VERSION 5.8 ;
BUSBITCHARS "[]" ;
DIVIDERCHAR "/" ;
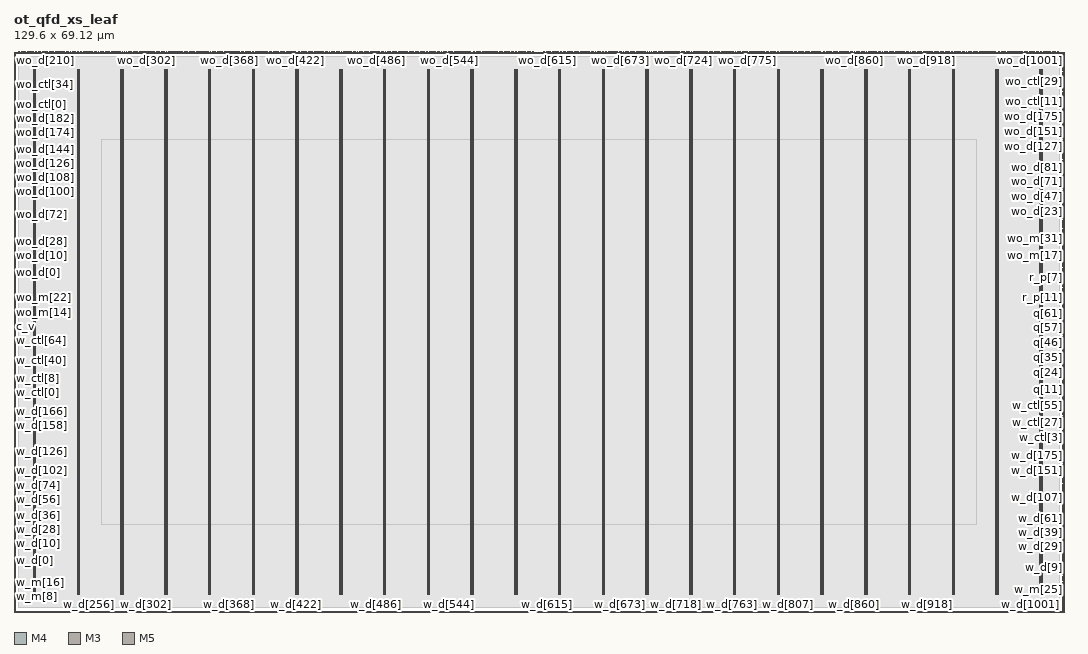
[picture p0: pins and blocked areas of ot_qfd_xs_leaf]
MACRO ot_qfd_xs_leaf
  CLASS BLOCK ;
  ORIGIN 0 0 ;
  FOREIGN ot_qfd_xs_leaf 0 0 ;
  SIZE 129.6 BY 69.12 ;
  SYMMETRY X Y ;
  PIN c_ep
    DIRECTION INPUT ;
    USE SIGNAL ;
    PORT
      LAYER M4 ;
        RECT 129.408 26.928 129.600 26.952 ;
    END
  END c_ep
  PIN c_v
    DIRECTION INPUT ;
    USE SIGNAL ;
    PORT
      LAYER M4 ;
        RECT 0.000 34.224 0.192 34.248 ;
    END
  END c_v
  PIN clk
    DIRECTION INPUT ;
    USE SIGNAL ;
    PORT
      LAYER M4 ;
        RECT 0.000 34.416 0.192 34.440 ;
    END
  END clk
  PIN co_ep
    DIRECTION OUTPUT ;
    USE SIGNAL ;
    PORT
      LAYER M4 ;
        RECT 129.408 68.784 129.600 68.808 ;
    END
  END co_ep
  PIN co_v
    DIRECTION OUTPUT ;
    USE SIGNAL ;
    PORT
      LAYER M4 ;
        RECT 0.000 68.784 0.192 68.808 ;
    END
  END co_v
  PIN q[0]
    DIRECTION OUTPUT ;
    USE SIGNAL ;
    PORT
      LAYER M4 ;
        RECT 129.408 27.072 129.600 27.096 ;
    END
  END q[0]
  PIN q[10]
    DIRECTION OUTPUT ;
    USE SIGNAL ;
    PORT
      LAYER M4 ;
        RECT 129.408 27.264 129.600 27.288 ;
    END
  END q[10]
  PIN q[11]
    DIRECTION OUTPUT ;
    USE SIGNAL ;
    PORT
      LAYER M4 ;
        RECT 129.408 27.408 129.600 27.432 ;
    END
  END q[11]
  PIN q[12]
    DIRECTION OUTPUT ;
    USE SIGNAL ;
    PORT
      LAYER M4 ;
        RECT 129.408 27.504 129.600 27.528 ;
    END
  END q[12]
  PIN q[13]
    DIRECTION OUTPUT ;
    USE SIGNAL ;
    PORT
      LAYER M4 ;
        RECT 129.408 27.696 129.600 27.720 ;
    END
  END q[13]
  PIN q[14]
    DIRECTION OUTPUT ;
    USE SIGNAL ;
    PORT
      LAYER M4 ;
        RECT 129.408 27.840 129.600 27.864 ;
    END
  END q[14]
  PIN q[15]
    DIRECTION OUTPUT ;
    USE SIGNAL ;
    PORT
      LAYER M4 ;
        RECT 129.408 28.032 129.600 28.056 ;
    END
  END q[15]
  PIN q[16]
    DIRECTION OUTPUT ;
    USE SIGNAL ;
    PORT
      LAYER M4 ;
        RECT 129.408 28.176 129.600 28.200 ;
    END
  END q[16]
  PIN q[17]
    DIRECTION OUTPUT ;
    USE SIGNAL ;
    PORT
      LAYER M4 ;
        RECT 129.408 28.368 129.600 28.392 ;
    END
  END q[17]
  PIN q[18]
    DIRECTION OUTPUT ;
    USE SIGNAL ;
    PORT
      LAYER M4 ;
        RECT 129.408 28.464 129.600 28.488 ;
    END
  END q[18]
  PIN q[19]
    DIRECTION OUTPUT ;
    USE SIGNAL ;
    PORT
      LAYER M4 ;
        RECT 129.408 28.608 129.600 28.632 ;
    END
  END q[19]
  PIN q[1]
    DIRECTION OUTPUT ;
    USE SIGNAL ;
    PORT
      LAYER M4 ;
        RECT 129.408 28.800 129.600 28.824 ;
    END
  END q[1]
  PIN q[20]
    DIRECTION OUTPUT ;
    USE SIGNAL ;
    PORT
      LAYER M4 ;
        RECT 129.408 28.944 129.600 28.968 ;
    END
  END q[20]
  PIN q[21]
    DIRECTION OUTPUT ;
    USE SIGNAL ;
    PORT
      LAYER M4 ;
        RECT 129.408 29.136 129.600 29.160 ;
    END
  END q[21]
  PIN q[22]
    DIRECTION OUTPUT ;
    USE SIGNAL ;
    PORT
      LAYER M4 ;
        RECT 129.408 29.232 129.600 29.256 ;
    END
  END q[22]
  PIN q[23]
    DIRECTION OUTPUT ;
    USE SIGNAL ;
    PORT
      LAYER M4 ;
        RECT 129.408 29.424 129.600 29.448 ;
    END
  END q[23]
  PIN q[24]
    DIRECTION OUTPUT ;
    USE SIGNAL ;
    PORT
      LAYER M4 ;
        RECT 129.408 29.568 129.600 29.592 ;
    END
  END q[24]
  PIN q[25]
    DIRECTION OUTPUT ;
    USE SIGNAL ;
    PORT
      LAYER M4 ;
        RECT 129.408 29.712 129.600 29.736 ;
    END
  END q[25]
  PIN q[26]
    DIRECTION OUTPUT ;
    USE SIGNAL ;
    PORT
      LAYER M4 ;
        RECT 129.408 29.904 129.600 29.928 ;
    END
  END q[26]
  PIN q[27]
    DIRECTION OUTPUT ;
    USE SIGNAL ;
    PORT
      LAYER M4 ;
        RECT 129.408 30.000 129.600 30.024 ;
    END
  END q[27]
  PIN q[28]
    DIRECTION OUTPUT ;
    USE SIGNAL ;
    PORT
      LAYER M4 ;
        RECT 129.408 30.192 129.600 30.216 ;
    END
  END q[28]
  PIN q[29]
    DIRECTION OUTPUT ;
    USE SIGNAL ;
    PORT
      LAYER M4 ;
        RECT 129.408 30.336 129.600 30.360 ;
    END
  END q[29]
  PIN q[2]
    DIRECTION OUTPUT ;
    USE SIGNAL ;
    PORT
      LAYER M4 ;
        RECT 129.408 30.480 129.600 30.504 ;
    END
  END q[2]
  PIN q[30]
    DIRECTION OUTPUT ;
    USE SIGNAL ;
    PORT
      LAYER M4 ;
        RECT 129.408 30.672 129.600 30.696 ;
    END
  END q[30]
  PIN q[31]
    DIRECTION OUTPUT ;
    USE SIGNAL ;
    PORT
      LAYER M4 ;
        RECT 129.408 30.768 129.600 30.792 ;
    END
  END q[31]
  PIN q[32]
    DIRECTION OUTPUT ;
    USE SIGNAL ;
    PORT
      LAYER M4 ;
        RECT 129.408 30.960 129.600 30.984 ;
    END
  END q[32]
  PIN q[33]
    DIRECTION OUTPUT ;
    USE SIGNAL ;
    PORT
      LAYER M4 ;
        RECT 129.408 31.104 129.600 31.128 ;
    END
  END q[33]
  PIN q[34]
    DIRECTION OUTPUT ;
    USE SIGNAL ;
    PORT
      LAYER M4 ;
        RECT 129.408 31.296 129.600 31.320 ;
    END
  END q[34]
  PIN q[35]
    DIRECTION OUTPUT ;
    USE SIGNAL ;
    PORT
      LAYER M4 ;
        RECT 129.408 31.440 129.600 31.464 ;
    END
  END q[35]
  PIN q[36]
    DIRECTION OUTPUT ;
    USE SIGNAL ;
    PORT
      LAYER M4 ;
        RECT 129.408 31.536 129.600 31.560 ;
    END
  END q[36]
  PIN q[37]
    DIRECTION OUTPUT ;
    USE SIGNAL ;
    PORT
      LAYER M4 ;
        RECT 129.408 31.728 129.600 31.752 ;
    END
  END q[37]
  PIN q[38]
    DIRECTION OUTPUT ;
    USE SIGNAL ;
    PORT
      LAYER M4 ;
        RECT 129.408 31.872 129.600 31.896 ;
    END
  END q[38]
  PIN q[39]
    DIRECTION OUTPUT ;
    USE SIGNAL ;
    PORT
      LAYER M4 ;
        RECT 129.408 32.064 129.600 32.088 ;
    END
  END q[39]
  PIN q[3]
    DIRECTION OUTPUT ;
    USE SIGNAL ;
    PORT
      LAYER M4 ;
        RECT 129.408 32.208 129.600 32.232 ;
    END
  END q[3]
  PIN q[40]
    DIRECTION OUTPUT ;
    USE SIGNAL ;
    PORT
      LAYER M4 ;
        RECT 129.408 32.400 129.600 32.424 ;
    END
  END q[40]
  PIN q[41]
    DIRECTION OUTPUT ;
    USE SIGNAL ;
    PORT
      LAYER M4 ;
        RECT 129.408 32.496 129.600 32.520 ;
    END
  END q[41]
  PIN q[42]
    DIRECTION OUTPUT ;
    USE SIGNAL ;
    PORT
      LAYER M4 ;
        RECT 129.408 32.640 129.600 32.664 ;
    END
  END q[42]
  PIN q[43]
    DIRECTION OUTPUT ;
    USE SIGNAL ;
    PORT
      LAYER M4 ;
        RECT 129.408 32.832 129.600 32.856 ;
    END
  END q[43]
  PIN q[44]
    DIRECTION OUTPUT ;
    USE SIGNAL ;
    PORT
      LAYER M4 ;
        RECT 129.408 32.976 129.600 33.000 ;
    END
  END q[44]
  PIN q[45]
    DIRECTION OUTPUT ;
    USE SIGNAL ;
    PORT
      LAYER M4 ;
        RECT 129.408 33.168 129.600 33.192 ;
    END
  END q[45]
  PIN q[46]
    DIRECTION OUTPUT ;
    USE SIGNAL ;
    PORT
      LAYER M4 ;
        RECT 129.408 33.264 129.600 33.288 ;
    END
  END q[46]
  PIN q[47]
    DIRECTION OUTPUT ;
    USE SIGNAL ;
    PORT
      LAYER M4 ;
        RECT 129.408 33.456 129.600 33.480 ;
    END
  END q[47]
  PIN q[48]
    DIRECTION OUTPUT ;
    USE SIGNAL ;
    PORT
      LAYER M4 ;
        RECT 129.408 33.600 129.600 33.624 ;
    END
  END q[48]
  PIN q[49]
    DIRECTION OUTPUT ;
    USE SIGNAL ;
    PORT
      LAYER M4 ;
        RECT 129.408 33.744 129.600 33.768 ;
    END
  END q[49]
  PIN q[4]
    DIRECTION OUTPUT ;
    USE SIGNAL ;
    PORT
      LAYER M4 ;
        RECT 129.408 33.936 129.600 33.960 ;
    END
  END q[4]
  PIN q[50]
    DIRECTION OUTPUT ;
    USE SIGNAL ;
    PORT
      LAYER M4 ;
        RECT 129.408 34.032 129.600 34.056 ;
    END
  END q[50]
  PIN q[51]
    DIRECTION OUTPUT ;
    USE SIGNAL ;
    PORT
      LAYER M4 ;
        RECT 129.408 34.224 129.600 34.248 ;
    END
  END q[51]
  PIN q[52]
    DIRECTION OUTPUT ;
    USE SIGNAL ;
    PORT
      LAYER M4 ;
        RECT 129.408 34.368 129.600 34.392 ;
    END
  END q[52]
  PIN q[53]
    DIRECTION OUTPUT ;
    USE SIGNAL ;
    PORT
      LAYER M4 ;
        RECT 129.408 34.560 129.600 34.584 ;
    END
  END q[53]
  PIN q[54]
    DIRECTION OUTPUT ;
    USE SIGNAL ;
    PORT
      LAYER M4 ;
        RECT 129.408 34.704 129.600 34.728 ;
    END
  END q[54]
  PIN q[55]
    DIRECTION OUTPUT ;
    USE SIGNAL ;
    PORT
      LAYER M4 ;
        RECT 129.408 34.800 129.600 34.824 ;
    END
  END q[55]
  PIN q[56]
    DIRECTION OUTPUT ;
    USE SIGNAL ;
    PORT
      LAYER M4 ;
        RECT 129.408 34.992 129.600 35.016 ;
    END
  END q[56]
  PIN q[57]
    DIRECTION OUTPUT ;
    USE SIGNAL ;
    PORT
      LAYER M4 ;
        RECT 129.408 35.136 129.600 35.160 ;
    END
  END q[57]
  PIN q[58]
    DIRECTION OUTPUT ;
    USE SIGNAL ;
    PORT
      LAYER M4 ;
        RECT 129.408 35.328 129.600 35.352 ;
    END
  END q[58]
  PIN q[59]
    DIRECTION OUTPUT ;
    USE SIGNAL ;
    PORT
      LAYER M4 ;
        RECT 129.408 35.472 129.600 35.496 ;
    END
  END q[59]
  PIN q[5]
    DIRECTION OUTPUT ;
    USE SIGNAL ;
    PORT
      LAYER M4 ;
        RECT 129.408 35.568 129.600 35.592 ;
    END
  END q[5]
  PIN q[60]
    DIRECTION OUTPUT ;
    USE SIGNAL ;
    PORT
      LAYER M4 ;
        RECT 129.408 35.760 129.600 35.784 ;
    END
  END q[60]
  PIN q[61]
    DIRECTION OUTPUT ;
    USE SIGNAL ;
    PORT
      LAYER M4 ;
        RECT 129.408 35.904 129.600 35.928 ;
    END
  END q[61]
  PIN q[62]
    DIRECTION OUTPUT ;
    USE SIGNAL ;
    PORT
      LAYER M4 ;
        RECT 129.408 36.096 129.600 36.120 ;
    END
  END q[62]
  PIN q[63]
    DIRECTION OUTPUT ;
    USE SIGNAL ;
    PORT
      LAYER M4 ;
        RECT 129.408 36.240 129.600 36.264 ;
    END
  END q[63]
  PIN q[6]
    DIRECTION OUTPUT ;
    USE SIGNAL ;
    PORT
      LAYER M4 ;
        RECT 129.408 36.432 129.600 36.456 ;
    END
  END q[6]
  PIN q[7]
    DIRECTION OUTPUT ;
    USE SIGNAL ;
    PORT
      LAYER M4 ;
        RECT 129.408 36.528 129.600 36.552 ;
    END
  END q[7]
  PIN q[8]
    DIRECTION OUTPUT ;
    USE SIGNAL ;
    PORT
      LAYER M4 ;
        RECT 129.408 36.672 129.600 36.696 ;
    END
  END q[8]
  PIN q[9]
    DIRECTION OUTPUT ;
    USE SIGNAL ;
    PORT
      LAYER M4 ;
        RECT 129.408 36.864 129.600 36.888 ;
    END
  END q[9]
  PIN q_bad
    DIRECTION OUTPUT ;
    USE SIGNAL ;
    PORT
      LAYER M4 ;
        RECT 129.408 37.008 129.600 37.032 ;
    END
  END q_bad
  PIN q_v
    DIRECTION OUTPUT ;
    USE SIGNAL ;
    PORT
      LAYER M4 ;
        RECT 129.408 37.200 129.600 37.224 ;
    END
  END q_v
  PIN r_ep
    DIRECTION INPUT ;
    USE SIGNAL ;
    PORT
      LAYER M4 ;
        RECT 129.408 37.296 129.600 37.320 ;
    END
  END r_ep
  PIN r_p[0]
    DIRECTION INPUT ;
    USE SIGNAL ;
    PORT
      LAYER M4 ;
        RECT 129.408 37.488 129.600 37.512 ;
    END
  END r_p[0]
  PIN r_p[10]
    DIRECTION INPUT ;
    USE SIGNAL ;
    PORT
      LAYER M4 ;
        RECT 129.408 37.632 129.600 37.656 ;
    END
  END r_p[10]
  PIN r_p[11]
    DIRECTION INPUT ;
    USE SIGNAL ;
    PORT
      LAYER M4 ;
        RECT 129.408 37.776 129.600 37.800 ;
    END
  END r_p[11]
  PIN r_p[12]
    DIRECTION INPUT ;
    USE SIGNAL ;
    PORT
      LAYER M4 ;
        RECT 129.408 37.968 129.600 37.992 ;
    END
  END r_p[12]
  PIN r_p[13]
    DIRECTION INPUT ;
    USE SIGNAL ;
    PORT
      LAYER M4 ;
        RECT 129.408 38.064 129.600 38.088 ;
    END
  END r_p[13]
  PIN r_p[14]
    DIRECTION INPUT ;
    USE SIGNAL ;
    PORT
      LAYER M4 ;
        RECT 129.408 38.256 129.600 38.280 ;
    END
  END r_p[14]
  PIN r_p[15]
    DIRECTION INPUT ;
    USE SIGNAL ;
    PORT
      LAYER M4 ;
        RECT 129.408 38.400 129.600 38.424 ;
    END
  END r_p[15]
  PIN r_p[16]
    DIRECTION INPUT ;
    USE SIGNAL ;
    PORT
      LAYER M4 ;
        RECT 129.408 38.544 129.600 38.568 ;
    END
  END r_p[16]
  PIN r_p[17]
    DIRECTION INPUT ;
    USE SIGNAL ;
    PORT
      LAYER M4 ;
        RECT 129.408 38.736 129.600 38.760 ;
    END
  END r_p[17]
  PIN r_p[18]
    DIRECTION INPUT ;
    USE SIGNAL ;
    PORT
      LAYER M4 ;
        RECT 129.408 38.832 129.600 38.856 ;
    END
  END r_p[18]
  PIN r_p[19]
    DIRECTION INPUT ;
    USE SIGNAL ;
    PORT
      LAYER M4 ;
        RECT 129.408 39.024 129.600 39.048 ;
    END
  END r_p[19]
  PIN r_p[1]
    DIRECTION INPUT ;
    USE SIGNAL ;
    PORT
      LAYER M4 ;
        RECT 129.408 39.168 129.600 39.192 ;
    END
  END r_p[1]
  PIN r_p[20]
    DIRECTION INPUT ;
    USE SIGNAL ;
    PORT
      LAYER M4 ;
        RECT 129.408 39.360 129.600 39.384 ;
    END
  END r_p[20]
  PIN r_p[21]
    DIRECTION INPUT ;
    USE SIGNAL ;
    PORT
      LAYER M4 ;
        RECT 129.408 39.504 129.600 39.528 ;
    END
  END r_p[21]
  PIN r_p[22]
    DIRECTION INPUT ;
    USE SIGNAL ;
    PORT
      LAYER M4 ;
        RECT 129.408 39.600 129.600 39.624 ;
    END
  END r_p[22]
  PIN r_p[23]
    DIRECTION INPUT ;
    USE SIGNAL ;
    PORT
      LAYER M4 ;
        RECT 129.408 39.792 129.600 39.816 ;
    END
  END r_p[23]
  PIN r_p[24]
    DIRECTION INPUT ;
    USE SIGNAL ;
    PORT
      LAYER M4 ;
        RECT 129.408 39.936 129.600 39.960 ;
    END
  END r_p[24]
  PIN r_p[25]
    DIRECTION INPUT ;
    USE SIGNAL ;
    PORT
      LAYER M4 ;
        RECT 129.408 40.128 129.600 40.152 ;
    END
  END r_p[25]
  PIN r_p[26]
    DIRECTION INPUT ;
    USE SIGNAL ;
    PORT
      LAYER M4 ;
        RECT 129.408 40.272 129.600 40.296 ;
    END
  END r_p[26]
  PIN r_p[27]
    DIRECTION INPUT ;
    USE SIGNAL ;
    PORT
      LAYER M4 ;
        RECT 129.408 40.464 129.600 40.488 ;
    END
  END r_p[27]
  PIN r_p[2]
    DIRECTION INPUT ;
    USE SIGNAL ;
    PORT
      LAYER M4 ;
        RECT 129.408 40.560 129.600 40.584 ;
    END
  END r_p[2]
  PIN r_p[3]
    DIRECTION INPUT ;
    USE SIGNAL ;
    PORT
      LAYER M4 ;
        RECT 129.408 40.704 129.600 40.728 ;
    END
  END r_p[3]
  PIN r_p[4]
    DIRECTION INPUT ;
    USE SIGNAL ;
    PORT
      LAYER M4 ;
        RECT 129.408 40.896 129.600 40.920 ;
    END
  END r_p[4]
  PIN r_p[5]
    DIRECTION INPUT ;
    USE SIGNAL ;
    PORT
      LAYER M4 ;
        RECT 129.408 41.040 129.600 41.064 ;
    END
  END r_p[5]
  PIN r_p[6]
    DIRECTION INPUT ;
    USE SIGNAL ;
    PORT
      LAYER M4 ;
        RECT 129.408 41.232 129.600 41.256 ;
    END
  END r_p[6]
  PIN r_p[7]
    DIRECTION INPUT ;
    USE SIGNAL ;
    PORT
      LAYER M4 ;
        RECT 129.408 41.328 129.600 41.352 ;
    END
  END r_p[7]
  PIN r_p[8]
    DIRECTION INPUT ;
    USE SIGNAL ;
    PORT
      LAYER M4 ;
        RECT 129.408 41.520 129.600 41.544 ;
    END
  END r_p[8]
  PIN r_p[9]
    DIRECTION INPUT ;
    USE SIGNAL ;
    PORT
      LAYER M4 ;
        RECT 129.408 41.664 129.600 41.688 ;
    END
  END r_p[9]
  PIN r_t
    DIRECTION INPUT ;
    USE SIGNAL ;
    PORT
      LAYER M4 ;
        RECT 129.408 41.808 129.600 41.832 ;
    END
  END r_t
  PIN r_v
    DIRECTION INPUT ;
    USE SIGNAL ;
    PORT
      LAYER M4 ;
        RECT 129.408 42.000 129.600 42.024 ;
    END
  END r_v
  PIN rst_n
    DIRECTION INPUT ;
    USE SIGNAL ;
    PORT
      LAYER M4 ;
        RECT 0.000 34.608 0.192 34.632 ;
    END
  END rst_n
  PIN w_ctl[0]
    DIRECTION INPUT ;
    USE SIGNAL ;
    PORT
      LAYER M4 ;
        RECT 0.000 27.120 0.192 27.144 ;
    END
  END w_ctl[0]
  PIN w_ctl[10]
    DIRECTION INPUT ;
    USE SIGNAL ;
    PORT
      LAYER M4 ;
        RECT 0.000 28.080 0.192 28.104 ;
    END
  END w_ctl[10]
  PIN w_ctl[11]
    DIRECTION INPUT ;
    USE SIGNAL ;
    PORT
      LAYER M4 ;
        RECT 129.408 22.128 129.600 22.152 ;
    END
  END w_ctl[11]
  PIN w_ctl[12]
    DIRECTION INPUT ;
    USE SIGNAL ;
    PORT
      LAYER M4 ;
        RECT 0.000 28.272 0.192 28.296 ;
    END
  END w_ctl[12]
  PIN w_ctl[13]
    DIRECTION INPUT ;
    USE SIGNAL ;
    PORT
      LAYER M4 ;
        RECT 129.408 22.272 129.600 22.296 ;
    END
  END w_ctl[13]
  PIN w_ctl[14]
    DIRECTION INPUT ;
    USE SIGNAL ;
    PORT
      LAYER M4 ;
        RECT 0.000 28.464 0.192 28.488 ;
    END
  END w_ctl[14]
  PIN w_ctl[15]
    DIRECTION INPUT ;
    USE SIGNAL ;
    PORT
      LAYER M4 ;
        RECT 129.408 22.416 129.600 22.440 ;
    END
  END w_ctl[15]
  PIN w_ctl[16]
    DIRECTION INPUT ;
    USE SIGNAL ;
    PORT
      LAYER M4 ;
        RECT 0.000 28.656 0.192 28.680 ;
    END
  END w_ctl[16]
  PIN w_ctl[17]
    DIRECTION INPUT ;
    USE SIGNAL ;
    PORT
      LAYER M4 ;
        RECT 129.408 22.608 129.600 22.632 ;
    END
  END w_ctl[17]
  PIN w_ctl[18]
    DIRECTION INPUT ;
    USE SIGNAL ;
    PORT
      LAYER M4 ;
        RECT 0.000 28.944 0.192 28.968 ;
    END
  END w_ctl[18]
  PIN w_ctl[19]
    DIRECTION INPUT ;
    USE SIGNAL ;
    PORT
      LAYER M4 ;
        RECT 129.408 22.704 129.600 22.728 ;
    END
  END w_ctl[19]
  PIN w_ctl[1]
    DIRECTION INPUT ;
    USE SIGNAL ;
    PORT
      LAYER M4 ;
        RECT 129.408 21.360 129.600 21.384 ;
    END
  END w_ctl[1]
  PIN w_ctl[20]
    DIRECTION INPUT ;
    USE SIGNAL ;
    PORT
      LAYER M4 ;
        RECT 0.000 29.136 0.192 29.160 ;
    END
  END w_ctl[20]
  PIN w_ctl[21]
    DIRECTION INPUT ;
    USE SIGNAL ;
    PORT
      LAYER M4 ;
        RECT 129.408 22.896 129.600 22.920 ;
    END
  END w_ctl[21]
  PIN w_ctl[22]
    DIRECTION INPUT ;
    USE SIGNAL ;
    PORT
      LAYER M4 ;
        RECT 0.000 29.328 0.192 29.352 ;
    END
  END w_ctl[22]
  PIN w_ctl[23]
    DIRECTION INPUT ;
    USE SIGNAL ;
    PORT
      LAYER M4 ;
        RECT 129.408 23.040 129.600 23.064 ;
    END
  END w_ctl[23]
  PIN w_ctl[24]
    DIRECTION INPUT ;
    USE SIGNAL ;
    PORT
      LAYER M4 ;
        RECT 0.000 29.520 0.192 29.544 ;
    END
  END w_ctl[24]
  PIN w_ctl[25]
    DIRECTION INPUT ;
    USE SIGNAL ;
    PORT
      LAYER M4 ;
        RECT 129.408 23.232 129.600 23.256 ;
    END
  END w_ctl[25]
  PIN w_ctl[26]
    DIRECTION INPUT ;
    USE SIGNAL ;
    PORT
      LAYER M4 ;
        RECT 0.000 29.712 0.192 29.736 ;
    END
  END w_ctl[26]
  PIN w_ctl[27]
    DIRECTION INPUT ;
    USE SIGNAL ;
    PORT
      LAYER M4 ;
        RECT 129.408 23.376 129.600 23.400 ;
    END
  END w_ctl[27]
  PIN w_ctl[28]
    DIRECTION INPUT ;
    USE SIGNAL ;
    PORT
      LAYER M4 ;
        RECT 0.000 29.904 0.192 29.928 ;
    END
  END w_ctl[28]
  PIN w_ctl[29]
    DIRECTION INPUT ;
    USE SIGNAL ;
    PORT
      LAYER M4 ;
        RECT 129.408 23.472 129.600 23.496 ;
    END
  END w_ctl[29]
  PIN w_ctl[2]
    DIRECTION INPUT ;
    USE SIGNAL ;
    PORT
      LAYER M4 ;
        RECT 0.000 27.312 0.192 27.336 ;
    END
  END w_ctl[2]
  PIN w_ctl[30]
    DIRECTION INPUT ;
    USE SIGNAL ;
    PORT
      LAYER M4 ;
        RECT 0.000 30.096 0.192 30.120 ;
    END
  END w_ctl[30]
  PIN w_ctl[31]
    DIRECTION INPUT ;
    USE SIGNAL ;
    PORT
      LAYER M4 ;
        RECT 129.408 23.664 129.600 23.688 ;
    END
  END w_ctl[31]
  PIN w_ctl[32]
    DIRECTION INPUT ;
    USE SIGNAL ;
    PORT
      LAYER M4 ;
        RECT 0.000 30.288 0.192 30.312 ;
    END
  END w_ctl[32]
  PIN w_ctl[33]
    DIRECTION INPUT ;
    USE SIGNAL ;
    PORT
      LAYER M4 ;
        RECT 129.408 23.808 129.600 23.832 ;
    END
  END w_ctl[33]
  PIN w_ctl[34]
    DIRECTION INPUT ;
    USE SIGNAL ;
    PORT
      LAYER M4 ;
        RECT 0.000 30.480 0.192 30.504 ;
    END
  END w_ctl[34]
  PIN w_ctl[35]
    DIRECTION INPUT ;
    USE SIGNAL ;
    PORT
      LAYER M4 ;
        RECT 129.408 24.000 129.600 24.024 ;
    END
  END w_ctl[35]
  PIN w_ctl[36]
    DIRECTION INPUT ;
    USE SIGNAL ;
    PORT
      LAYER M4 ;
        RECT 0.000 30.672 0.192 30.696 ;
    END
  END w_ctl[36]
  PIN w_ctl[37]
    DIRECTION INPUT ;
    USE SIGNAL ;
    PORT
      LAYER M4 ;
        RECT 129.408 24.144 129.600 24.168 ;
    END
  END w_ctl[37]
  PIN w_ctl[38]
    DIRECTION INPUT ;
    USE SIGNAL ;
    PORT
      LAYER M4 ;
        RECT 0.000 30.864 0.192 30.888 ;
    END
  END w_ctl[38]
  PIN w_ctl[39]
    DIRECTION INPUT ;
    USE SIGNAL ;
    PORT
      LAYER M4 ;
        RECT 129.408 24.336 129.600 24.360 ;
    END
  END w_ctl[39]
  PIN w_ctl[3]
    DIRECTION INPUT ;
    USE SIGNAL ;
    PORT
      LAYER M4 ;
        RECT 129.408 21.504 129.600 21.528 ;
    END
  END w_ctl[3]
  PIN w_ctl[40]
    DIRECTION INPUT ;
    USE SIGNAL ;
    PORT
      LAYER M4 ;
        RECT 0.000 31.056 0.192 31.080 ;
    END
  END w_ctl[40]
  PIN w_ctl[41]
    DIRECTION INPUT ;
    USE SIGNAL ;
    PORT
      LAYER M4 ;
        RECT 129.408 24.432 129.600 24.456 ;
    END
  END w_ctl[41]
  PIN w_ctl[42]
    DIRECTION INPUT ;
    USE SIGNAL ;
    PORT
      LAYER M4 ;
        RECT 0.000 31.296 0.192 31.320 ;
    END
  END w_ctl[42]
  PIN w_ctl[43]
    DIRECTION INPUT ;
    USE SIGNAL ;
    PORT
      LAYER M4 ;
        RECT 129.408 24.576 129.600 24.600 ;
    END
  END w_ctl[43]
  PIN w_ctl[44]
    DIRECTION INPUT ;
    USE SIGNAL ;
    PORT
      LAYER M4 ;
        RECT 0.000 31.488 0.192 31.512 ;
    END
  END w_ctl[44]
  PIN w_ctl[45]
    DIRECTION INPUT ;
    USE SIGNAL ;
    PORT
      LAYER M4 ;
        RECT 129.408 24.768 129.600 24.792 ;
    END
  END w_ctl[45]
  PIN w_ctl[46]
    DIRECTION INPUT ;
    USE SIGNAL ;
    PORT
      LAYER M4 ;
        RECT 0.000 31.680 0.192 31.704 ;
    END
  END w_ctl[46]
  PIN w_ctl[47]
    DIRECTION INPUT ;
    USE SIGNAL ;
    PORT
      LAYER M4 ;
        RECT 129.408 24.912 129.600 24.936 ;
    END
  END w_ctl[47]
  PIN w_ctl[48]
    DIRECTION INPUT ;
    USE SIGNAL ;
    PORT
      LAYER M4 ;
        RECT 0.000 31.872 0.192 31.896 ;
    END
  END w_ctl[48]
  PIN w_ctl[49]
    DIRECTION INPUT ;
    USE SIGNAL ;
    PORT
      LAYER M4 ;
        RECT 129.408 25.104 129.600 25.128 ;
    END
  END w_ctl[49]
  PIN w_ctl[4]
    DIRECTION INPUT ;
    USE SIGNAL ;
    PORT
      LAYER M4 ;
        RECT 0.000 27.504 0.192 27.528 ;
    END
  END w_ctl[4]
  PIN w_ctl[50]
    DIRECTION INPUT ;
    USE SIGNAL ;
    PORT
      LAYER M4 ;
        RECT 0.000 32.064 0.192 32.088 ;
    END
  END w_ctl[50]
  PIN w_ctl[51]
    DIRECTION INPUT ;
    USE SIGNAL ;
    PORT
      LAYER M4 ;
        RECT 129.408 25.200 129.600 25.224 ;
    END
  END w_ctl[51]
  PIN w_ctl[52]
    DIRECTION INPUT ;
    USE SIGNAL ;
    PORT
      LAYER M4 ;
        RECT 0.000 32.256 0.192 32.280 ;
    END
  END w_ctl[52]
  PIN w_ctl[53]
    DIRECTION INPUT ;
    USE SIGNAL ;
    PORT
      LAYER M4 ;
        RECT 129.408 25.392 129.600 25.416 ;
    END
  END w_ctl[53]
  PIN w_ctl[54]
    DIRECTION INPUT ;
    USE SIGNAL ;
    PORT
      LAYER M4 ;
        RECT 0.000 32.448 0.192 32.472 ;
    END
  END w_ctl[54]
  PIN w_ctl[55]
    DIRECTION INPUT ;
    USE SIGNAL ;
    PORT
      LAYER M4 ;
        RECT 129.408 25.536 129.600 25.560 ;
    END
  END w_ctl[55]
  PIN w_ctl[56]
    DIRECTION INPUT ;
    USE SIGNAL ;
    PORT
      LAYER M4 ;
        RECT 0.000 32.640 0.192 32.664 ;
    END
  END w_ctl[56]
  PIN w_ctl[57]
    DIRECTION INPUT ;
    USE SIGNAL ;
    PORT
      LAYER M4 ;
        RECT 129.408 25.680 129.600 25.704 ;
    END
  END w_ctl[57]
  PIN w_ctl[58]
    DIRECTION INPUT ;
    USE SIGNAL ;
    PORT
      LAYER M4 ;
        RECT 0.000 32.832 0.192 32.856 ;
    END
  END w_ctl[58]
  PIN w_ctl[59]
    DIRECTION INPUT ;
    USE SIGNAL ;
    PORT
      LAYER M4 ;
        RECT 129.408 25.872 129.600 25.896 ;
    END
  END w_ctl[59]
  PIN w_ctl[5]
    DIRECTION INPUT ;
    USE SIGNAL ;
    PORT
      LAYER M4 ;
        RECT 129.408 21.648 129.600 21.672 ;
    END
  END w_ctl[5]
  PIN w_ctl[60]
    DIRECTION INPUT ;
    USE SIGNAL ;
    PORT
      LAYER M4 ;
        RECT 0.000 33.024 0.192 33.048 ;
    END
  END w_ctl[60]
  PIN w_ctl[61]
    DIRECTION INPUT ;
    USE SIGNAL ;
    PORT
      LAYER M4 ;
        RECT 129.408 25.968 129.600 25.992 ;
    END
  END w_ctl[61]
  PIN w_ctl[62]
    DIRECTION INPUT ;
    USE SIGNAL ;
    PORT
      LAYER M4 ;
        RECT 0.000 33.216 0.192 33.240 ;
    END
  END w_ctl[62]
  PIN w_ctl[63]
    DIRECTION INPUT ;
    USE SIGNAL ;
    PORT
      LAYER M4 ;
        RECT 129.408 26.160 129.600 26.184 ;
    END
  END w_ctl[63]
  PIN w_ctl[64]
    DIRECTION INPUT ;
    USE SIGNAL ;
    PORT
      LAYER M4 ;
        RECT 0.000 33.456 0.192 33.480 ;
    END
  END w_ctl[64]
  PIN w_ctl[65]
    DIRECTION INPUT ;
    USE SIGNAL ;
    PORT
      LAYER M4 ;
        RECT 129.408 26.304 129.600 26.328 ;
    END
  END w_ctl[65]
  PIN w_ctl[66]
    DIRECTION INPUT ;
    USE SIGNAL ;
    PORT
      LAYER M4 ;
        RECT 0.000 33.648 0.192 33.672 ;
    END
  END w_ctl[66]
  PIN w_ctl[67]
    DIRECTION INPUT ;
    USE SIGNAL ;
    PORT
      LAYER M4 ;
        RECT 129.408 26.496 129.600 26.520 ;
    END
  END w_ctl[67]
  PIN w_ctl[68]
    DIRECTION INPUT ;
    USE SIGNAL ;
    PORT
      LAYER M4 ;
        RECT 0.000 33.840 0.192 33.864 ;
    END
  END w_ctl[68]
  PIN w_ctl[69]
    DIRECTION INPUT ;
    USE SIGNAL ;
    PORT
      LAYER M4 ;
        RECT 129.408 26.640 129.600 26.664 ;
    END
  END w_ctl[69]
  PIN w_ctl[6]
    DIRECTION INPUT ;
    USE SIGNAL ;
    PORT
      LAYER M4 ;
        RECT 0.000 27.696 0.192 27.720 ;
    END
  END w_ctl[6]
  PIN w_ctl[70]
    DIRECTION INPUT ;
    USE SIGNAL ;
    PORT
      LAYER M4 ;
        RECT 0.000 34.032 0.192 34.056 ;
    END
  END w_ctl[70]
  PIN w_ctl[71]
    DIRECTION INPUT ;
    USE SIGNAL ;
    PORT
      LAYER M4 ;
        RECT 129.408 26.736 129.600 26.760 ;
    END
  END w_ctl[71]
  PIN w_ctl[7]
    DIRECTION INPUT ;
    USE SIGNAL ;
    PORT
      LAYER M4 ;
        RECT 129.408 21.840 129.600 21.864 ;
    END
  END w_ctl[7]
  PIN w_ctl[8]
    DIRECTION INPUT ;
    USE SIGNAL ;
    PORT
      LAYER M4 ;
        RECT 0.000 27.888 0.192 27.912 ;
    END
  END w_ctl[8]
  PIN w_ctl[9]
    DIRECTION INPUT ;
    USE SIGNAL ;
    PORT
      LAYER M4 ;
        RECT 129.408 21.936 129.600 21.960 ;
    END
  END w_ctl[9]
  PIN w_d[0]
    DIRECTION INPUT ;
    USE SIGNAL ;
    PORT
      LAYER M4 ;
        RECT 0.000 7.344 0.192 7.368 ;
    END
  END w_d[0]
  PIN w_d[1000]
    DIRECTION INPUT ;
    USE SIGNAL ;
    PORT
      LAYER M3 ;
        RECT 125.280 0.000 125.298 0.038 ;
    END
  END w_d[1000]
  PIN w_d[1001]
    DIRECTION INPUT ;
    USE SIGNAL ;
    PORT
      LAYER M3 ;
        RECT 125.424 0.000 125.442 0.038 ;
    END
  END w_d[1001]
  PIN w_d[1002]
    DIRECTION INPUT ;
    USE SIGNAL ;
    PORT
      LAYER M3 ;
        RECT 125.568 0.000 125.586 0.038 ;
    END
  END w_d[1002]
  PIN w_d[1003]
    DIRECTION INPUT ;
    USE SIGNAL ;
    PORT
      LAYER M3 ;
        RECT 125.712 0.000 125.730 0.038 ;
    END
  END w_d[1003]
  PIN w_d[1004]
    DIRECTION INPUT ;
    USE SIGNAL ;
    PORT
      LAYER M5 ;
        RECT 125.856 0.000 125.880 0.084 ;
    END
  END w_d[1004]
  PIN w_d[1005]
    DIRECTION INPUT ;
    USE SIGNAL ;
    PORT
      LAYER M3 ;
        RECT 126.000 0.000 126.018 0.038 ;
    END
  END w_d[1005]
  PIN w_d[1006]
    DIRECTION INPUT ;
    USE SIGNAL ;
    PORT
      LAYER M5 ;
        RECT 126.144 0.000 126.168 0.084 ;
    END
  END w_d[1006]
  PIN w_d[1007]
    DIRECTION INPUT ;
    USE SIGNAL ;
    PORT
      LAYER M5 ;
        RECT 126.336 0.000 126.360 0.084 ;
    END
  END w_d[1007]
  PIN w_d[1008]
    DIRECTION INPUT ;
    USE SIGNAL ;
    PORT
      LAYER M5 ;
        RECT 126.432 0.000 126.456 0.084 ;
    END
  END w_d[1008]
  PIN w_d[1009]
    DIRECTION INPUT ;
    USE SIGNAL ;
    PORT
      LAYER M3 ;
        RECT 126.648 0.000 126.666 0.038 ;
    END
  END w_d[1009]
  PIN w_d[100]
    DIRECTION INPUT ;
    USE SIGNAL ;
    PORT
      LAYER M4 ;
        RECT 0.000 17.232 0.192 17.256 ;
    END
  END w_d[100]
  PIN w_d[1010]
    DIRECTION INPUT ;
    USE SIGNAL ;
    PORT
      LAYER M3 ;
        RECT 126.864 0.000 126.882 0.038 ;
    END
  END w_d[1010]
  PIN w_d[1011]
    DIRECTION INPUT ;
    USE SIGNAL ;
    PORT
      LAYER M3 ;
        RECT 127.080 0.000 127.098 0.038 ;
    END
  END w_d[1011]
  PIN w_d[1012]
    DIRECTION INPUT ;
    USE SIGNAL ;
    PORT
      LAYER M3 ;
        RECT 127.224 0.000 127.242 0.038 ;
    END
  END w_d[1012]
  PIN w_d[1013]
    DIRECTION INPUT ;
    USE SIGNAL ;
    PORT
      LAYER M3 ;
        RECT 127.368 0.000 127.386 0.038 ;
    END
  END w_d[1013]
  PIN w_d[1014]
    DIRECTION INPUT ;
    USE SIGNAL ;
    PORT
      LAYER M3 ;
        RECT 127.512 0.000 127.530 0.038 ;
    END
  END w_d[1014]
  PIN w_d[1015]
    DIRECTION INPUT ;
    USE SIGNAL ;
    PORT
      LAYER M5 ;
        RECT 127.680 0.000 127.704 0.084 ;
    END
  END w_d[1015]
  PIN w_d[1016]
    DIRECTION INPUT ;
    USE SIGNAL ;
    PORT
      LAYER M3 ;
        RECT 127.800 0.000 127.818 0.038 ;
    END
  END w_d[1016]
  PIN w_d[1017]
    DIRECTION INPUT ;
    USE SIGNAL ;
    PORT
      LAYER M5 ;
        RECT 127.968 0.000 127.992 0.084 ;
    END
  END w_d[1017]
  PIN w_d[1018]
    DIRECTION INPUT ;
    USE SIGNAL ;
    PORT
      LAYER M3 ;
        RECT 128.160 0.000 128.178 0.038 ;
    END
  END w_d[1018]
  PIN w_d[1019]
    DIRECTION INPUT ;
    USE SIGNAL ;
    PORT
      LAYER M5 ;
        RECT 128.256 0.000 128.280 0.084 ;
    END
  END w_d[1019]
  PIN w_d[101]
    DIRECTION INPUT ;
    USE SIGNAL ;
    PORT
      LAYER M4 ;
        RECT 129.408 13.584 129.600 13.608 ;
    END
  END w_d[101]
  PIN w_d[1020]
    DIRECTION INPUT ;
    USE SIGNAL ;
    PORT
      LAYER M3 ;
        RECT 128.448 0.000 128.466 0.038 ;
    END
  END w_d[1020]
  PIN w_d[1021]
    DIRECTION INPUT ;
    USE SIGNAL ;
    PORT
      LAYER M5 ;
        RECT 128.544 0.000 128.568 0.084 ;
    END
  END w_d[1021]
  PIN w_d[1022]
    DIRECTION INPUT ;
    USE SIGNAL ;
    PORT
      LAYER M3 ;
        RECT 128.736 0.000 128.754 0.038 ;
    END
  END w_d[1022]
  PIN w_d[1023]
    DIRECTION INPUT ;
    USE SIGNAL ;
    PORT
      LAYER M3 ;
        RECT 128.880 0.000 128.898 0.038 ;
    END
  END w_d[1023]
  PIN w_d[102]
    DIRECTION INPUT ;
    USE SIGNAL ;
    PORT
      LAYER M4 ;
        RECT 0.000 17.472 0.192 17.496 ;
    END
  END w_d[102]
  PIN w_d[103]
    DIRECTION INPUT ;
    USE SIGNAL ;
    PORT
      LAYER M4 ;
        RECT 129.408 13.776 129.600 13.800 ;
    END
  END w_d[103]
  PIN w_d[104]
    DIRECTION INPUT ;
    USE SIGNAL ;
    PORT
      LAYER M4 ;
        RECT 0.000 17.664 0.192 17.688 ;
    END
  END w_d[104]
  PIN w_d[105]
    DIRECTION INPUT ;
    USE SIGNAL ;
    PORT
      LAYER M4 ;
        RECT 129.408 13.872 129.600 13.896 ;
    END
  END w_d[105]
  PIN w_d[106]
    DIRECTION INPUT ;
    USE SIGNAL ;
    PORT
      LAYER M4 ;
        RECT 0.000 17.856 0.192 17.880 ;
    END
  END w_d[106]
  PIN w_d[107]
    DIRECTION INPUT ;
    USE SIGNAL ;
    PORT
      LAYER M4 ;
        RECT 129.408 14.064 129.600 14.088 ;
    END
  END w_d[107]
  PIN w_d[108]
    DIRECTION INPUT ;
    USE SIGNAL ;
    PORT
      LAYER M4 ;
        RECT 0.000 18.048 0.192 18.072 ;
    END
  END w_d[108]
  PIN w_d[109]
    DIRECTION INPUT ;
    USE SIGNAL ;
    PORT
      LAYER M4 ;
        RECT 129.408 14.208 129.600 14.232 ;
    END
  END w_d[109]
  PIN w_d[10]
    DIRECTION INPUT ;
    USE SIGNAL ;
    PORT
      LAYER M4 ;
        RECT 0.000 8.400 0.192 8.424 ;
    END
  END w_d[10]
  PIN w_d[110]
    DIRECTION INPUT ;
    USE SIGNAL ;
    PORT
      LAYER M4 ;
        RECT 0.000 18.240 0.192 18.264 ;
    END
  END w_d[110]
  PIN w_d[111]
    DIRECTION INPUT ;
    USE SIGNAL ;
    PORT
      LAYER M4 ;
        RECT 129.408 14.352 129.600 14.376 ;
    END
  END w_d[111]
  PIN w_d[112]
    DIRECTION INPUT ;
    USE SIGNAL ;
    PORT
      LAYER M4 ;
        RECT 0.000 18.432 0.192 18.456 ;
    END
  END w_d[112]
  PIN w_d[113]
    DIRECTION INPUT ;
    USE SIGNAL ;
    PORT
      LAYER M4 ;
        RECT 129.408 14.544 129.600 14.568 ;
    END
  END w_d[113]
  PIN w_d[114]
    DIRECTION INPUT ;
    USE SIGNAL ;
    PORT
      LAYER M4 ;
        RECT 0.000 18.624 0.192 18.648 ;
    END
  END w_d[114]
  PIN w_d[115]
    DIRECTION INPUT ;
    USE SIGNAL ;
    PORT
      LAYER M4 ;
        RECT 129.408 14.640 129.600 14.664 ;
    END
  END w_d[115]
  PIN w_d[116]
    DIRECTION INPUT ;
    USE SIGNAL ;
    PORT
      LAYER M4 ;
        RECT 0.000 18.816 0.192 18.840 ;
    END
  END w_d[116]
  PIN w_d[117]
    DIRECTION INPUT ;
    USE SIGNAL ;
    PORT
      LAYER M4 ;
        RECT 129.408 14.832 129.600 14.856 ;
    END
  END w_d[117]
  PIN w_d[118]
    DIRECTION INPUT ;
    USE SIGNAL ;
    PORT
      LAYER M4 ;
        RECT 0.000 19.008 0.192 19.032 ;
    END
  END w_d[118]
  PIN w_d[119]
    DIRECTION INPUT ;
    USE SIGNAL ;
    PORT
      LAYER M4 ;
        RECT 129.408 14.976 129.600 15.000 ;
    END
  END w_d[119]
  PIN w_d[11]
    DIRECTION INPUT ;
    USE SIGNAL ;
    PORT
      LAYER M4 ;
        RECT 129.408 6.576 129.600 6.600 ;
    END
  END w_d[11]
  PIN w_d[120]
    DIRECTION INPUT ;
    USE SIGNAL ;
    PORT
      LAYER M4 ;
        RECT 0.000 19.200 0.192 19.224 ;
    END
  END w_d[120]
  PIN w_d[121]
    DIRECTION INPUT ;
    USE SIGNAL ;
    PORT
      LAYER M4 ;
        RECT 129.408 15.168 129.600 15.192 ;
    END
  END w_d[121]
  PIN w_d[122]
    DIRECTION INPUT ;
    USE SIGNAL ;
    PORT
      LAYER M4 ;
        RECT 0.000 19.392 0.192 19.416 ;
    END
  END w_d[122]
  PIN w_d[123]
    DIRECTION INPUT ;
    USE SIGNAL ;
    PORT
      LAYER M4 ;
        RECT 129.408 15.312 129.600 15.336 ;
    END
  END w_d[123]
  PIN w_d[124]
    DIRECTION INPUT ;
    USE SIGNAL ;
    PORT
      LAYER M4 ;
        RECT 0.000 19.584 0.192 19.608 ;
    END
  END w_d[124]
  PIN w_d[125]
    DIRECTION INPUT ;
    USE SIGNAL ;
    PORT
      LAYER M4 ;
        RECT 129.408 15.408 129.600 15.432 ;
    END
  END w_d[125]
  PIN w_d[126]
    DIRECTION INPUT ;
    USE SIGNAL ;
    PORT
      LAYER M4 ;
        RECT 0.000 19.824 0.192 19.848 ;
    END
  END w_d[126]
  PIN w_d[127]
    DIRECTION INPUT ;
    USE SIGNAL ;
    PORT
      LAYER M4 ;
        RECT 129.408 15.600 129.600 15.624 ;
    END
  END w_d[127]
  PIN w_d[128]
    DIRECTION INPUT ;
    USE SIGNAL ;
    PORT
      LAYER M4 ;
        RECT 0.000 20.016 0.192 20.040 ;
    END
  END w_d[128]
  PIN w_d[129]
    DIRECTION INPUT ;
    USE SIGNAL ;
    PORT
      LAYER M4 ;
        RECT 129.408 15.744 129.600 15.768 ;
    END
  END w_d[129]
  PIN w_d[12]
    DIRECTION INPUT ;
    USE SIGNAL ;
    PORT
      LAYER M4 ;
        RECT 0.000 8.592 0.192 8.616 ;
    END
  END w_d[12]
  PIN w_d[130]
    DIRECTION INPUT ;
    USE SIGNAL ;
    PORT
      LAYER M4 ;
        RECT 0.000 20.208 0.192 20.232 ;
    END
  END w_d[130]
  PIN w_d[131]
    DIRECTION INPUT ;
    USE SIGNAL ;
    PORT
      LAYER M4 ;
        RECT 129.408 15.936 129.600 15.960 ;
    END
  END w_d[131]
  PIN w_d[132]
    DIRECTION INPUT ;
    USE SIGNAL ;
    PORT
      LAYER M4 ;
        RECT 0.000 20.400 0.192 20.424 ;
    END
  END w_d[132]
  PIN w_d[133]
    DIRECTION INPUT ;
    USE SIGNAL ;
    PORT
      LAYER M4 ;
        RECT 129.408 16.080 129.600 16.104 ;
    END
  END w_d[133]
  PIN w_d[134]
    DIRECTION INPUT ;
    USE SIGNAL ;
    PORT
      LAYER M4 ;
        RECT 0.000 20.592 0.192 20.616 ;
    END
  END w_d[134]
  PIN w_d[135]
    DIRECTION INPUT ;
    USE SIGNAL ;
    PORT
      LAYER M4 ;
        RECT 129.408 16.272 129.600 16.296 ;
    END
  END w_d[135]
  PIN w_d[136]
    DIRECTION INPUT ;
    USE SIGNAL ;
    PORT
      LAYER M4 ;
        RECT 0.000 20.784 0.192 20.808 ;
    END
  END w_d[136]
  PIN w_d[137]
    DIRECTION INPUT ;
    USE SIGNAL ;
    PORT
      LAYER M4 ;
        RECT 129.408 16.368 129.600 16.392 ;
    END
  END w_d[137]
  PIN w_d[138]
    DIRECTION INPUT ;
    USE SIGNAL ;
    PORT
      LAYER M4 ;
        RECT 0.000 20.976 0.192 21.000 ;
    END
  END w_d[138]
  PIN w_d[139]
    DIRECTION INPUT ;
    USE SIGNAL ;
    PORT
      LAYER M4 ;
        RECT 129.408 16.512 129.600 16.536 ;
    END
  END w_d[139]
  PIN w_d[13]
    DIRECTION INPUT ;
    USE SIGNAL ;
    PORT
      LAYER M4 ;
        RECT 129.408 6.768 129.600 6.792 ;
    END
  END w_d[13]
  PIN w_d[140]
    DIRECTION INPUT ;
    USE SIGNAL ;
    PORT
      LAYER M4 ;
        RECT 0.000 21.168 0.192 21.192 ;
    END
  END w_d[140]
  PIN w_d[141]
    DIRECTION INPUT ;
    USE SIGNAL ;
    PORT
      LAYER M4 ;
        RECT 129.408 16.704 129.600 16.728 ;
    END
  END w_d[141]
  PIN w_d[142]
    DIRECTION INPUT ;
    USE SIGNAL ;
    PORT
      LAYER M4 ;
        RECT 0.000 21.360 0.192 21.384 ;
    END
  END w_d[142]
  PIN w_d[143]
    DIRECTION INPUT ;
    USE SIGNAL ;
    PORT
      LAYER M4 ;
        RECT 129.408 16.848 129.600 16.872 ;
    END
  END w_d[143]
  PIN w_d[144]
    DIRECTION INPUT ;
    USE SIGNAL ;
    PORT
      LAYER M4 ;
        RECT 0.000 21.552 0.192 21.576 ;
    END
  END w_d[144]
  PIN w_d[145]
    DIRECTION INPUT ;
    USE SIGNAL ;
    PORT
      LAYER M4 ;
        RECT 129.408 17.040 129.600 17.064 ;
    END
  END w_d[145]
  PIN w_d[146]
    DIRECTION INPUT ;
    USE SIGNAL ;
    PORT
      LAYER M4 ;
        RECT 0.000 21.744 0.192 21.768 ;
    END
  END w_d[146]
  PIN w_d[147]
    DIRECTION INPUT ;
    USE SIGNAL ;
    PORT
      LAYER M4 ;
        RECT 129.408 17.136 129.600 17.160 ;
    END
  END w_d[147]
  PIN w_d[148]
    DIRECTION INPUT ;
    USE SIGNAL ;
    PORT
      LAYER M4 ;
        RECT 0.000 22.032 0.192 22.056 ;
    END
  END w_d[148]
  PIN w_d[149]
    DIRECTION INPUT ;
    USE SIGNAL ;
    PORT
      LAYER M4 ;
        RECT 129.408 17.328 129.600 17.352 ;
    END
  END w_d[149]
  PIN w_d[14]
    DIRECTION INPUT ;
    USE SIGNAL ;
    PORT
      LAYER M4 ;
        RECT 0.000 8.784 0.192 8.808 ;
    END
  END w_d[14]
  PIN w_d[150]
    DIRECTION INPUT ;
    USE SIGNAL ;
    PORT
      LAYER M4 ;
        RECT 0.000 22.224 0.192 22.248 ;
    END
  END w_d[150]
  PIN w_d[151]
    DIRECTION INPUT ;
    USE SIGNAL ;
    PORT
      LAYER M4 ;
        RECT 129.408 17.472 129.600 17.496 ;
    END
  END w_d[151]
  PIN w_d[152]
    DIRECTION INPUT ;
    USE SIGNAL ;
    PORT
      LAYER M4 ;
        RECT 0.000 22.416 0.192 22.440 ;
    END
  END w_d[152]
  PIN w_d[153]
    DIRECTION INPUT ;
    USE SIGNAL ;
    PORT
      LAYER M4 ;
        RECT 129.408 17.616 129.600 17.640 ;
    END
  END w_d[153]
  PIN w_d[154]
    DIRECTION INPUT ;
    USE SIGNAL ;
    PORT
      LAYER M4 ;
        RECT 0.000 22.608 0.192 22.632 ;
    END
  END w_d[154]
  PIN w_d[155]
    DIRECTION INPUT ;
    USE SIGNAL ;
    PORT
      LAYER M4 ;
        RECT 129.408 17.808 129.600 17.832 ;
    END
  END w_d[155]
  PIN w_d[156]
    DIRECTION INPUT ;
    USE SIGNAL ;
    PORT
      LAYER M4 ;
        RECT 0.000 22.800 0.192 22.824 ;
    END
  END w_d[156]
  PIN w_d[157]
    DIRECTION INPUT ;
    USE SIGNAL ;
    PORT
      LAYER M4 ;
        RECT 129.408 17.904 129.600 17.928 ;
    END
  END w_d[157]
  PIN w_d[158]
    DIRECTION INPUT ;
    USE SIGNAL ;
    PORT
      LAYER M4 ;
        RECT 0.000 22.992 0.192 23.016 ;
    END
  END w_d[158]
  PIN w_d[159]
    DIRECTION INPUT ;
    USE SIGNAL ;
    PORT
      LAYER M4 ;
        RECT 129.408 18.096 129.600 18.120 ;
    END
  END w_d[159]
  PIN w_d[15]
    DIRECTION INPUT ;
    USE SIGNAL ;
    PORT
      LAYER M4 ;
        RECT 129.408 6.912 129.600 6.936 ;
    END
  END w_d[15]
  PIN w_d[160]
    DIRECTION INPUT ;
    USE SIGNAL ;
    PORT
      LAYER M4 ;
        RECT 0.000 23.184 0.192 23.208 ;
    END
  END w_d[160]
  PIN w_d[161]
    DIRECTION INPUT ;
    USE SIGNAL ;
    PORT
      LAYER M4 ;
        RECT 129.408 18.240 129.600 18.264 ;
    END
  END w_d[161]
  PIN w_d[162]
    DIRECTION INPUT ;
    USE SIGNAL ;
    PORT
      LAYER M4 ;
        RECT 0.000 23.376 0.192 23.400 ;
    END
  END w_d[162]
  PIN w_d[163]
    DIRECTION INPUT ;
    USE SIGNAL ;
    PORT
      LAYER M4 ;
        RECT 129.408 18.432 129.600 18.456 ;
    END
  END w_d[163]
  PIN w_d[164]
    DIRECTION INPUT ;
    USE SIGNAL ;
    PORT
      LAYER M4 ;
        RECT 0.000 23.568 0.192 23.592 ;
    END
  END w_d[164]
  PIN w_d[165]
    DIRECTION INPUT ;
    USE SIGNAL ;
    PORT
      LAYER M4 ;
        RECT 129.408 18.576 129.600 18.600 ;
    END
  END w_d[165]
  PIN w_d[166]
    DIRECTION INPUT ;
    USE SIGNAL ;
    PORT
      LAYER M4 ;
        RECT 0.000 23.760 0.192 23.784 ;
    END
  END w_d[166]
  PIN w_d[167]
    DIRECTION INPUT ;
    USE SIGNAL ;
    PORT
      LAYER M4 ;
        RECT 129.408 18.672 129.600 18.696 ;
    END
  END w_d[167]
  PIN w_d[168]
    DIRECTION INPUT ;
    USE SIGNAL ;
    PORT
      LAYER M4 ;
        RECT 0.000 23.952 0.192 23.976 ;
    END
  END w_d[168]
  PIN w_d[169]
    DIRECTION INPUT ;
    USE SIGNAL ;
    PORT
      LAYER M4 ;
        RECT 129.408 18.864 129.600 18.888 ;
    END
  END w_d[169]
  PIN w_d[16]
    DIRECTION INPUT ;
    USE SIGNAL ;
    PORT
      LAYER M4 ;
        RECT 0.000 8.976 0.192 9.000 ;
    END
  END w_d[16]
  PIN w_d[170]
    DIRECTION INPUT ;
    USE SIGNAL ;
    PORT
      LAYER M4 ;
        RECT 0.000 24.144 0.192 24.168 ;
    END
  END w_d[170]
  PIN w_d[171]
    DIRECTION INPUT ;
    USE SIGNAL ;
    PORT
      LAYER M4 ;
        RECT 129.408 19.008 129.600 19.032 ;
    END
  END w_d[171]
  PIN w_d[172]
    DIRECTION INPUT ;
    USE SIGNAL ;
    PORT
      LAYER M4 ;
        RECT 0.000 24.384 0.192 24.408 ;
    END
  END w_d[172]
  PIN w_d[173]
    DIRECTION INPUT ;
    USE SIGNAL ;
    PORT
      LAYER M4 ;
        RECT 129.408 19.200 129.600 19.224 ;
    END
  END w_d[173]
  PIN w_d[174]
    DIRECTION INPUT ;
    USE SIGNAL ;
    PORT
      LAYER M4 ;
        RECT 0.000 24.576 0.192 24.600 ;
    END
  END w_d[174]
  PIN w_d[175]
    DIRECTION INPUT ;
    USE SIGNAL ;
    PORT
      LAYER M4 ;
        RECT 129.408 19.344 129.600 19.368 ;
    END
  END w_d[175]
  PIN w_d[176]
    DIRECTION INPUT ;
    USE SIGNAL ;
    PORT
      LAYER M4 ;
        RECT 0.000 24.768 0.192 24.792 ;
    END
  END w_d[176]
  PIN w_d[177]
    DIRECTION INPUT ;
    USE SIGNAL ;
    PORT
      LAYER M4 ;
        RECT 129.408 19.440 129.600 19.464 ;
    END
  END w_d[177]
  PIN w_d[178]
    DIRECTION INPUT ;
    USE SIGNAL ;
    PORT
      LAYER M4 ;
        RECT 0.000 24.960 0.192 24.984 ;
    END
  END w_d[178]
  PIN w_d[179]
    DIRECTION INPUT ;
    USE SIGNAL ;
    PORT
      LAYER M4 ;
        RECT 129.408 19.632 129.600 19.656 ;
    END
  END w_d[179]
  PIN w_d[17]
    DIRECTION INPUT ;
    USE SIGNAL ;
    PORT
      LAYER M4 ;
        RECT 129.408 7.104 129.600 7.128 ;
    END
  END w_d[17]
  PIN w_d[180]
    DIRECTION INPUT ;
    USE SIGNAL ;
    PORT
      LAYER M4 ;
        RECT 0.000 25.152 0.192 25.176 ;
    END
  END w_d[180]
  PIN w_d[181]
    DIRECTION INPUT ;
    USE SIGNAL ;
    PORT
      LAYER M4 ;
        RECT 129.408 19.776 129.600 19.800 ;
    END
  END w_d[181]
  PIN w_d[182]
    DIRECTION INPUT ;
    USE SIGNAL ;
    PORT
      LAYER M4 ;
        RECT 0.000 25.344 0.192 25.368 ;
    END
  END w_d[182]
  PIN w_d[183]
    DIRECTION INPUT ;
    USE SIGNAL ;
    PORT
      LAYER M4 ;
        RECT 129.408 19.968 129.600 19.992 ;
    END
  END w_d[183]
  PIN w_d[184]
    DIRECTION INPUT ;
    USE SIGNAL ;
    PORT
      LAYER M4 ;
        RECT 0.000 25.536 0.192 25.560 ;
    END
  END w_d[184]
  PIN w_d[185]
    DIRECTION INPUT ;
    USE SIGNAL ;
    PORT
      LAYER M4 ;
        RECT 129.408 20.112 129.600 20.136 ;
    END
  END w_d[185]
  PIN w_d[186]
    DIRECTION INPUT ;
    USE SIGNAL ;
    PORT
      LAYER M4 ;
        RECT 0.000 25.728 0.192 25.752 ;
    END
  END w_d[186]
  PIN w_d[187]
    DIRECTION INPUT ;
    USE SIGNAL ;
    PORT
      LAYER M4 ;
        RECT 129.408 20.304 129.600 20.328 ;
    END
  END w_d[187]
  PIN w_d[188]
    DIRECTION INPUT ;
    USE SIGNAL ;
    PORT
      LAYER M4 ;
        RECT 0.000 25.920 0.192 25.944 ;
    END
  END w_d[188]
  PIN w_d[189]
    DIRECTION INPUT ;
    USE SIGNAL ;
    PORT
      LAYER M4 ;
        RECT 129.408 20.400 129.600 20.424 ;
    END
  END w_d[189]
  PIN w_d[18]
    DIRECTION INPUT ;
    USE SIGNAL ;
    PORT
      LAYER M4 ;
        RECT 0.000 9.168 0.192 9.192 ;
    END
  END w_d[18]
  PIN w_d[190]
    DIRECTION INPUT ;
    USE SIGNAL ;
    PORT
      LAYER M4 ;
        RECT 0.000 26.112 0.192 26.136 ;
    END
  END w_d[190]
  PIN w_d[191]
    DIRECTION INPUT ;
    USE SIGNAL ;
    PORT
      LAYER M4 ;
        RECT 129.408 20.544 129.600 20.568 ;
    END
  END w_d[191]
  PIN w_d[192]
    DIRECTION INPUT ;
    USE SIGNAL ;
    PORT
      LAYER M4 ;
        RECT 0.000 26.304 0.192 26.328 ;
    END
  END w_d[192]
  PIN w_d[193]
    DIRECTION INPUT ;
    USE SIGNAL ;
    PORT
      LAYER M4 ;
        RECT 129.408 20.736 129.600 20.760 ;
    END
  END w_d[193]
  PIN w_d[194]
    DIRECTION INPUT ;
    USE SIGNAL ;
    PORT
      LAYER M4 ;
        RECT 0.000 26.496 0.192 26.520 ;
    END
  END w_d[194]
  PIN w_d[195]
    DIRECTION INPUT ;
    USE SIGNAL ;
    PORT
      LAYER M4 ;
        RECT 129.408 20.880 129.600 20.904 ;
    END
  END w_d[195]
  PIN w_d[196]
    DIRECTION INPUT ;
    USE SIGNAL ;
    PORT
      LAYER M4 ;
        RECT 0.000 26.736 0.192 26.760 ;
    END
  END w_d[196]
  PIN w_d[197]
    DIRECTION INPUT ;
    USE SIGNAL ;
    PORT
      LAYER M4 ;
        RECT 129.408 21.072 129.600 21.096 ;
    END
  END w_d[197]
  PIN w_d[198]
    DIRECTION INPUT ;
    USE SIGNAL ;
    PORT
      LAYER M4 ;
        RECT 0.000 26.928 0.192 26.952 ;
    END
  END w_d[198]
  PIN w_d[199]
    DIRECTION INPUT ;
    USE SIGNAL ;
    PORT
      LAYER M4 ;
        RECT 129.408 21.168 129.600 21.192 ;
    END
  END w_d[199]
  PIN w_d[19]
    DIRECTION INPUT ;
    USE SIGNAL ;
    PORT
      LAYER M4 ;
        RECT 129.408 7.248 129.600 7.272 ;
    END
  END w_d[19]
  PIN w_d[1]
    DIRECTION INPUT ;
    USE SIGNAL ;
    PORT
      LAYER M4 ;
        RECT 129.408 5.808 129.600 5.832 ;
    END
  END w_d[1]
  PIN w_d[200]
    DIRECTION INPUT ;
    USE SIGNAL ;
    PORT
      LAYER M3 ;
        RECT 0.576 0.000 0.594 0.038 ;
    END
  END w_d[200]
  PIN w_d[201]
    DIRECTION INPUT ;
    USE SIGNAL ;
    PORT
      LAYER M3 ;
        RECT 0.720 0.000 0.738 0.038 ;
    END
  END w_d[201]
  PIN w_d[202]
    DIRECTION INPUT ;
    USE SIGNAL ;
    PORT
      LAYER M5 ;
        RECT 0.864 0.000 0.888 0.084 ;
    END
  END w_d[202]
  PIN w_d[203]
    DIRECTION INPUT ;
    USE SIGNAL ;
    PORT
      LAYER M3 ;
        RECT 1.008 0.000 1.026 0.038 ;
    END
  END w_d[203]
  PIN w_d[204]
    DIRECTION INPUT ;
    USE SIGNAL ;
    PORT
      LAYER M5 ;
        RECT 1.152 0.000 1.176 0.084 ;
    END
  END w_d[204]
  PIN w_d[205]
    DIRECTION INPUT ;
    USE SIGNAL ;
    PORT
      LAYER M5 ;
        RECT 1.344 0.000 1.368 0.084 ;
    END
  END w_d[205]
  PIN w_d[206]
    DIRECTION INPUT ;
    USE SIGNAL ;
    PORT
      LAYER M5 ;
        RECT 1.440 0.000 1.464 0.084 ;
    END
  END w_d[206]
  PIN w_d[207]
    DIRECTION INPUT ;
    USE SIGNAL ;
    PORT
      LAYER M5 ;
        RECT 1.632 0.000 1.656 0.084 ;
    END
  END w_d[207]
  PIN w_d[208]
    DIRECTION INPUT ;
    USE SIGNAL ;
    PORT
      LAYER M3 ;
        RECT 1.800 0.000 1.818 0.038 ;
    END
  END w_d[208]
  PIN w_d[209]
    DIRECTION INPUT ;
    USE SIGNAL ;
    PORT
      LAYER M5 ;
        RECT 1.920 0.000 1.944 0.084 ;
    END
  END w_d[209]
  PIN w_d[20]
    DIRECTION INPUT ;
    USE SIGNAL ;
    PORT
      LAYER M4 ;
        RECT 0.000 9.360 0.192 9.384 ;
    END
  END w_d[20]
  PIN w_d[210]
    DIRECTION INPUT ;
    USE SIGNAL ;
    PORT
      LAYER M3 ;
        RECT 2.088 0.000 2.106 0.038 ;
    END
  END w_d[210]
  PIN w_d[211]
    DIRECTION INPUT ;
    USE SIGNAL ;
    PORT
      LAYER M5 ;
        RECT 2.208 0.000 2.232 0.084 ;
    END
  END w_d[211]
  PIN w_d[212]
    DIRECTION INPUT ;
    USE SIGNAL ;
    PORT
      LAYER M3 ;
        RECT 2.376 0.000 2.394 0.038 ;
    END
  END w_d[212]
  PIN w_d[213]
    DIRECTION INPUT ;
    USE SIGNAL ;
    PORT
      LAYER M3 ;
        RECT 2.592 0.000 2.610 0.038 ;
    END
  END w_d[213]
  PIN w_d[214]
    DIRECTION INPUT ;
    USE SIGNAL ;
    PORT
      LAYER M3 ;
        RECT 2.808 0.000 2.826 0.038 ;
    END
  END w_d[214]
  PIN w_d[215]
    DIRECTION INPUT ;
    USE SIGNAL ;
    PORT
      LAYER M5 ;
        RECT 2.976 0.000 3.000 0.084 ;
    END
  END w_d[215]
  PIN w_d[216]
    DIRECTION INPUT ;
    USE SIGNAL ;
    PORT
      LAYER M3 ;
        RECT 3.168 0.000 3.186 0.038 ;
    END
  END w_d[216]
  PIN w_d[217]
    DIRECTION INPUT ;
    USE SIGNAL ;
    PORT
      LAYER M5 ;
        RECT 3.264 0.000 3.288 0.084 ;
    END
  END w_d[217]
  PIN w_d[218]
    DIRECTION INPUT ;
    USE SIGNAL ;
    PORT
      LAYER M3 ;
        RECT 3.456 0.000 3.474 0.038 ;
    END
  END w_d[218]
  PIN w_d[219]
    DIRECTION INPUT ;
    USE SIGNAL ;
    PORT
      LAYER M3 ;
        RECT 3.600 0.000 3.618 0.038 ;
    END
  END w_d[219]
  PIN w_d[21]
    DIRECTION INPUT ;
    USE SIGNAL ;
    PORT
      LAYER M4 ;
        RECT 129.408 7.344 129.600 7.368 ;
    END
  END w_d[21]
  PIN w_d[220]
    DIRECTION INPUT ;
    USE SIGNAL ;
    PORT
      LAYER M3 ;
        RECT 3.744 0.000 3.762 0.038 ;
    END
  END w_d[220]
  PIN w_d[221]
    DIRECTION INPUT ;
    USE SIGNAL ;
    PORT
      LAYER M3 ;
        RECT 3.888 0.000 3.906 0.038 ;
    END
  END w_d[221]
  PIN w_d[222]
    DIRECTION INPUT ;
    USE SIGNAL ;
    PORT
      LAYER M3 ;
        RECT 4.032 0.000 4.050 0.038 ;
    END
  END w_d[222]
  PIN w_d[223]
    DIRECTION INPUT ;
    USE SIGNAL ;
    PORT
      LAYER M3 ;
        RECT 4.176 0.000 4.194 0.038 ;
    END
  END w_d[223]
  PIN w_d[224]
    DIRECTION INPUT ;
    USE SIGNAL ;
    PORT
      LAYER M5 ;
        RECT 4.320 0.000 4.344 0.084 ;
    END
  END w_d[224]
  PIN w_d[225]
    DIRECTION INPUT ;
    USE SIGNAL ;
    PORT
      LAYER M3 ;
        RECT 4.464 0.000 4.482 0.038 ;
    END
  END w_d[225]
  PIN w_d[226]
    DIRECTION INPUT ;
    USE SIGNAL ;
    PORT
      LAYER M5 ;
        RECT 4.608 0.000 4.632 0.084 ;
    END
  END w_d[226]
  PIN w_d[227]
    DIRECTION INPUT ;
    USE SIGNAL ;
    PORT
      LAYER M5 ;
        RECT 4.800 0.000 4.824 0.084 ;
    END
  END w_d[227]
  PIN w_d[228]
    DIRECTION INPUT ;
    USE SIGNAL ;
    PORT
      LAYER M5 ;
        RECT 4.896 0.000 4.920 0.084 ;
    END
  END w_d[228]
  PIN w_d[229]
    DIRECTION INPUT ;
    USE SIGNAL ;
    PORT
      LAYER M5 ;
        RECT 5.088 0.000 5.112 0.084 ;
    END
  END w_d[229]
  PIN w_d[22]
    DIRECTION INPUT ;
    USE SIGNAL ;
    PORT
      LAYER M4 ;
        RECT 0.000 9.552 0.192 9.576 ;
    END
  END w_d[22]
  PIN w_d[230]
    DIRECTION INPUT ;
    USE SIGNAL ;
    PORT
      LAYER M3 ;
        RECT 5.256 0.000 5.274 0.038 ;
    END
  END w_d[230]
  PIN w_d[231]
    DIRECTION INPUT ;
    USE SIGNAL ;
    PORT
      LAYER M5 ;
        RECT 5.376 0.000 5.400 0.084 ;
    END
  END w_d[231]
  PIN w_d[232]
    DIRECTION INPUT ;
    USE SIGNAL ;
    PORT
      LAYER M3 ;
        RECT 5.544 0.000 5.562 0.038 ;
    END
  END w_d[232]
  PIN w_d[233]
    DIRECTION INPUT ;
    USE SIGNAL ;
    PORT
      LAYER M5 ;
        RECT 5.664 0.000 5.688 0.084 ;
    END
  END w_d[233]
  PIN w_d[234]
    DIRECTION INPUT ;
    USE SIGNAL ;
    PORT
      LAYER M3 ;
        RECT 5.832 0.000 5.850 0.038 ;
    END
  END w_d[234]
  PIN w_d[235]
    DIRECTION INPUT ;
    USE SIGNAL ;
    PORT
      LAYER M3 ;
        RECT 5.976 0.000 5.994 0.038 ;
    END
  END w_d[235]
  PIN w_d[236]
    DIRECTION INPUT ;
    USE SIGNAL ;
    PORT
      LAYER M3 ;
        RECT 6.120 0.000 6.138 0.038 ;
    END
  END w_d[236]
  PIN w_d[237]
    DIRECTION INPUT ;
    USE SIGNAL ;
    PORT
      LAYER M3 ;
        RECT 6.264 0.000 6.282 0.038 ;
    END
  END w_d[237]
  PIN w_d[238]
    DIRECTION INPUT ;
    USE SIGNAL ;
    PORT
      LAYER M5 ;
        RECT 6.432 0.000 6.456 0.084 ;
    END
  END w_d[238]
  PIN w_d[239]
    DIRECTION INPUT ;
    USE SIGNAL ;
    PORT
      LAYER M3 ;
        RECT 6.552 0.000 6.570 0.038 ;
    END
  END w_d[239]
  PIN w_d[23]
    DIRECTION INPUT ;
    USE SIGNAL ;
    PORT
      LAYER M4 ;
        RECT 129.408 7.536 129.600 7.560 ;
    END
  END w_d[23]
  PIN w_d[240]
    DIRECTION INPUT ;
    USE SIGNAL ;
    PORT
      LAYER M5 ;
        RECT 6.720 0.000 6.744 0.084 ;
    END
  END w_d[240]
  PIN w_d[241]
    DIRECTION INPUT ;
    USE SIGNAL ;
    PORT
      LAYER M3 ;
        RECT 6.912 0.000 6.930 0.038 ;
    END
  END w_d[241]
  PIN w_d[242]
    DIRECTION INPUT ;
    USE SIGNAL ;
    PORT
      LAYER M5 ;
        RECT 7.008 0.000 7.032 0.084 ;
    END
  END w_d[242]
  PIN w_d[243]
    DIRECTION INPUT ;
    USE SIGNAL ;
    PORT
      LAYER M3 ;
        RECT 7.200 0.000 7.218 0.038 ;
    END
  END w_d[243]
  PIN w_d[244]
    DIRECTION INPUT ;
    USE SIGNAL ;
    PORT
      LAYER M5 ;
        RECT 7.296 0.000 7.320 0.084 ;
    END
  END w_d[244]
  PIN w_d[245]
    DIRECTION INPUT ;
    USE SIGNAL ;
    PORT
      LAYER M3 ;
        RECT 7.488 0.000 7.506 0.038 ;
    END
  END w_d[245]
  PIN w_d[246]
    DIRECTION INPUT ;
    USE SIGNAL ;
    PORT
      LAYER M3 ;
        RECT 7.632 0.000 7.650 0.038 ;
    END
  END w_d[246]
  PIN w_d[247]
    DIRECTION INPUT ;
    USE SIGNAL ;
    PORT
      LAYER M3 ;
        RECT 7.776 0.000 7.794 0.038 ;
    END
  END w_d[247]
  PIN w_d[248]
    DIRECTION INPUT ;
    USE SIGNAL ;
    PORT
      LAYER M3 ;
        RECT 7.992 0.000 8.010 0.038 ;
    END
  END w_d[248]
  PIN w_d[249]
    DIRECTION INPUT ;
    USE SIGNAL ;
    PORT
      LAYER M5 ;
        RECT 8.256 0.000 8.280 0.084 ;
    END
  END w_d[249]
  PIN w_d[24]
    DIRECTION INPUT ;
    USE SIGNAL ;
    PORT
      LAYER M4 ;
        RECT 0.000 9.744 0.192 9.768 ;
    END
  END w_d[24]
  PIN w_d[250]
    DIRECTION INPUT ;
    USE SIGNAL ;
    PORT
      LAYER M5 ;
        RECT 8.352 0.000 8.376 0.084 ;
    END
  END w_d[250]
  PIN w_d[251]
    DIRECTION INPUT ;
    USE SIGNAL ;
    PORT
      LAYER M5 ;
        RECT 8.544 0.000 8.568 0.084 ;
    END
  END w_d[251]
  PIN w_d[252]
    DIRECTION INPUT ;
    USE SIGNAL ;
    PORT
      LAYER M3 ;
        RECT 8.712 0.000 8.730 0.038 ;
    END
  END w_d[252]
  PIN w_d[253]
    DIRECTION INPUT ;
    USE SIGNAL ;
    PORT
      LAYER M5 ;
        RECT 8.832 0.000 8.856 0.084 ;
    END
  END w_d[253]
  PIN w_d[254]
    DIRECTION INPUT ;
    USE SIGNAL ;
    PORT
      LAYER M3 ;
        RECT 9.000 0.000 9.018 0.038 ;
    END
  END w_d[254]
  PIN w_d[255]
    DIRECTION INPUT ;
    USE SIGNAL ;
    PORT
      LAYER M3 ;
        RECT 9.144 0.000 9.162 0.038 ;
    END
  END w_d[255]
  PIN w_d[256]
    DIRECTION INPUT ;
    USE SIGNAL ;
    PORT
      LAYER M3 ;
        RECT 9.288 0.000 9.306 0.038 ;
    END
  END w_d[256]
  PIN w_d[257]
    DIRECTION INPUT ;
    USE SIGNAL ;
    PORT
      LAYER M3 ;
        RECT 9.432 0.000 9.450 0.038 ;
    END
  END w_d[257]
  PIN w_d[258]
    DIRECTION INPUT ;
    USE SIGNAL ;
    PORT
      LAYER M3 ;
        RECT 9.576 0.000 9.594 0.038 ;
    END
  END w_d[258]
  PIN w_d[259]
    DIRECTION INPUT ;
    USE SIGNAL ;
    PORT
      LAYER M3 ;
        RECT 9.720 0.000 9.738 0.038 ;
    END
  END w_d[259]
  PIN w_d[25]
    DIRECTION INPUT ;
    USE SIGNAL ;
    PORT
      LAYER M4 ;
        RECT 129.408 7.680 129.600 7.704 ;
    END
  END w_d[25]
  PIN w_d[260]
    DIRECTION INPUT ;
    USE SIGNAL ;
    PORT
      LAYER M5 ;
        RECT 9.888 0.000 9.912 0.084 ;
    END
  END w_d[260]
  PIN w_d[261]
    DIRECTION INPUT ;
    USE SIGNAL ;
    PORT
      LAYER M3 ;
        RECT 10.008 0.000 10.026 0.038 ;
    END
  END w_d[261]
  PIN w_d[262]
    DIRECTION INPUT ;
    USE SIGNAL ;
    PORT
      LAYER M5 ;
        RECT 10.176 0.000 10.200 0.084 ;
    END
  END w_d[262]
  PIN w_d[263]
    DIRECTION INPUT ;
    USE SIGNAL ;
    PORT
      LAYER M3 ;
        RECT 10.368 0.000 10.386 0.038 ;
    END
  END w_d[263]
  PIN w_d[264]
    DIRECTION INPUT ;
    USE SIGNAL ;
    PORT
      LAYER M5 ;
        RECT 10.464 0.000 10.488 0.084 ;
    END
  END w_d[264]
  PIN w_d[265]
    DIRECTION INPUT ;
    USE SIGNAL ;
    PORT
      LAYER M3 ;
        RECT 10.656 0.000 10.674 0.038 ;
    END
  END w_d[265]
  PIN w_d[266]
    DIRECTION INPUT ;
    USE SIGNAL ;
    PORT
      LAYER M3 ;
        RECT 10.800 0.000 10.818 0.038 ;
    END
  END w_d[266]
  PIN w_d[267]
    DIRECTION INPUT ;
    USE SIGNAL ;
    PORT
      LAYER M3 ;
        RECT 10.944 0.000 10.962 0.038 ;
    END
  END w_d[267]
  PIN w_d[268]
    DIRECTION INPUT ;
    USE SIGNAL ;
    PORT
      LAYER M3 ;
        RECT 11.088 0.000 11.106 0.038 ;
    END
  END w_d[268]
  PIN w_d[269]
    DIRECTION INPUT ;
    USE SIGNAL ;
    PORT
      LAYER M3 ;
        RECT 11.232 0.000 11.250 0.038 ;
    END
  END w_d[269]
  PIN w_d[26]
    DIRECTION INPUT ;
    USE SIGNAL ;
    PORT
      LAYER M4 ;
        RECT 0.000 9.936 0.192 9.960 ;
    END
  END w_d[26]
  PIN w_d[270]
    DIRECTION INPUT ;
    USE SIGNAL ;
    PORT
      LAYER M3 ;
        RECT 11.376 0.000 11.394 0.038 ;
    END
  END w_d[270]
  PIN w_d[271]
    DIRECTION INPUT ;
    USE SIGNAL ;
    PORT
      LAYER M5 ;
        RECT 11.520 0.000 11.544 0.084 ;
    END
  END w_d[271]
  PIN w_d[272]
    DIRECTION INPUT ;
    USE SIGNAL ;
    PORT
      LAYER M3 ;
        RECT 11.664 0.000 11.682 0.038 ;
    END
  END w_d[272]
  PIN w_d[273]
    DIRECTION INPUT ;
    USE SIGNAL ;
    PORT
      LAYER M5 ;
        RECT 11.808 0.000 11.832 0.084 ;
    END
  END w_d[273]
  PIN w_d[274]
    DIRECTION INPUT ;
    USE SIGNAL ;
    PORT
      LAYER M5 ;
        RECT 12.000 0.000 12.024 0.084 ;
    END
  END w_d[274]
  PIN w_d[275]
    DIRECTION INPUT ;
    USE SIGNAL ;
    PORT
      LAYER M5 ;
        RECT 12.096 0.000 12.120 0.084 ;
    END
  END w_d[275]
  PIN w_d[276]
    DIRECTION INPUT ;
    USE SIGNAL ;
    PORT
      LAYER M5 ;
        RECT 12.288 0.000 12.312 0.084 ;
    END
  END w_d[276]
  PIN w_d[277]
    DIRECTION INPUT ;
    USE SIGNAL ;
    PORT
      LAYER M3 ;
        RECT 12.456 0.000 12.474 0.038 ;
    END
  END w_d[277]
  PIN w_d[278]
    DIRECTION INPUT ;
    USE SIGNAL ;
    PORT
      LAYER M5 ;
        RECT 12.576 0.000 12.600 0.084 ;
    END
  END w_d[278]
  PIN w_d[279]
    DIRECTION INPUT ;
    USE SIGNAL ;
    PORT
      LAYER M3 ;
        RECT 12.744 0.000 12.762 0.038 ;
    END
  END w_d[279]
  PIN w_d[27]
    DIRECTION INPUT ;
    USE SIGNAL ;
    PORT
      LAYER M4 ;
        RECT 129.408 7.872 129.600 7.896 ;
    END
  END w_d[27]
  PIN w_d[280]
    DIRECTION INPUT ;
    USE SIGNAL ;
    PORT
      LAYER M5 ;
        RECT 12.864 0.000 12.888 0.084 ;
    END
  END w_d[280]
  PIN w_d[281]
    DIRECTION INPUT ;
    USE SIGNAL ;
    PORT
      LAYER M3 ;
        RECT 13.032 0.000 13.050 0.038 ;
    END
  END w_d[281]
  PIN w_d[282]
    DIRECTION INPUT ;
    USE SIGNAL ;
    PORT
      LAYER M3 ;
        RECT 13.176 0.000 13.194 0.038 ;
    END
  END w_d[282]
  PIN w_d[283]
    DIRECTION INPUT ;
    USE SIGNAL ;
    PORT
      LAYER M3 ;
        RECT 13.392 0.000 13.410 0.038 ;
    END
  END w_d[283]
  PIN w_d[284]
    DIRECTION INPUT ;
    USE SIGNAL ;
    PORT
      LAYER M5 ;
        RECT 13.632 0.000 13.656 0.084 ;
    END
  END w_d[284]
  PIN w_d[285]
    DIRECTION INPUT ;
    USE SIGNAL ;
    PORT
      LAYER M3 ;
        RECT 13.824 0.000 13.842 0.038 ;
    END
  END w_d[285]
  PIN w_d[286]
    DIRECTION INPUT ;
    USE SIGNAL ;
    PORT
      LAYER M5 ;
        RECT 13.920 0.000 13.944 0.084 ;
    END
  END w_d[286]
  PIN w_d[287]
    DIRECTION INPUT ;
    USE SIGNAL ;
    PORT
      LAYER M3 ;
        RECT 14.112 0.000 14.130 0.038 ;
    END
  END w_d[287]
  PIN w_d[288]
    DIRECTION INPUT ;
    USE SIGNAL ;
    PORT
      LAYER M3 ;
        RECT 14.256 0.000 14.274 0.038 ;
    END
  END w_d[288]
  PIN w_d[289]
    DIRECTION INPUT ;
    USE SIGNAL ;
    PORT
      LAYER M3 ;
        RECT 14.400 0.000 14.418 0.038 ;
    END
  END w_d[289]
  PIN w_d[28]
    DIRECTION INPUT ;
    USE SIGNAL ;
    PORT
      LAYER M4 ;
        RECT 0.000 10.128 0.192 10.152 ;
    END
  END w_d[28]
  PIN w_d[290]
    DIRECTION INPUT ;
    USE SIGNAL ;
    PORT
      LAYER M3 ;
        RECT 14.544 0.000 14.562 0.038 ;
    END
  END w_d[290]
  PIN w_d[291]
    DIRECTION INPUT ;
    USE SIGNAL ;
    PORT
      LAYER M3 ;
        RECT 14.688 0.000 14.706 0.038 ;
    END
  END w_d[291]
  PIN w_d[292]
    DIRECTION INPUT ;
    USE SIGNAL ;
    PORT
      LAYER M3 ;
        RECT 14.832 0.000 14.850 0.038 ;
    END
  END w_d[292]
  PIN w_d[293]
    DIRECTION INPUT ;
    USE SIGNAL ;
    PORT
      LAYER M5 ;
        RECT 14.976 0.000 15.000 0.084 ;
    END
  END w_d[293]
  PIN w_d[294]
    DIRECTION INPUT ;
    USE SIGNAL ;
    PORT
      LAYER M3 ;
        RECT 15.120 0.000 15.138 0.038 ;
    END
  END w_d[294]
  PIN w_d[295]
    DIRECTION INPUT ;
    USE SIGNAL ;
    PORT
      LAYER M5 ;
        RECT 15.264 0.000 15.288 0.084 ;
    END
  END w_d[295]
  PIN w_d[296]
    DIRECTION INPUT ;
    USE SIGNAL ;
    PORT
      LAYER M5 ;
        RECT 15.456 0.000 15.480 0.084 ;
    END
  END w_d[296]
  PIN w_d[297]
    DIRECTION INPUT ;
    USE SIGNAL ;
    PORT
      LAYER M5 ;
        RECT 15.552 0.000 15.576 0.084 ;
    END
  END w_d[297]
  PIN w_d[298]
    DIRECTION INPUT ;
    USE SIGNAL ;
    PORT
      LAYER M5 ;
        RECT 15.744 0.000 15.768 0.084 ;
    END
  END w_d[298]
  PIN w_d[299]
    DIRECTION INPUT ;
    USE SIGNAL ;
    PORT
      LAYER M3 ;
        RECT 15.912 0.000 15.930 0.038 ;
    END
  END w_d[299]
  PIN w_d[29]
    DIRECTION INPUT ;
    USE SIGNAL ;
    PORT
      LAYER M4 ;
        RECT 129.408 8.016 129.600 8.040 ;
    END
  END w_d[29]
  PIN w_d[2]
    DIRECTION INPUT ;
    USE SIGNAL ;
    PORT
      LAYER M4 ;
        RECT 0.000 7.536 0.192 7.560 ;
    END
  END w_d[2]
  PIN w_d[300]
    DIRECTION INPUT ;
    USE SIGNAL ;
    PORT
      LAYER M5 ;
        RECT 16.032 0.000 16.056 0.084 ;
    END
  END w_d[300]
  PIN w_d[301]
    DIRECTION INPUT ;
    USE SIGNAL ;
    PORT
      LAYER M3 ;
        RECT 16.200 0.000 16.218 0.038 ;
    END
  END w_d[301]
  PIN w_d[302]
    DIRECTION INPUT ;
    USE SIGNAL ;
    PORT
      LAYER M3 ;
        RECT 16.344 0.000 16.362 0.038 ;
    END
  END w_d[302]
  PIN w_d[303]
    DIRECTION INPUT ;
    USE SIGNAL ;
    PORT
      LAYER M3 ;
        RECT 16.488 0.000 16.506 0.038 ;
    END
  END w_d[303]
  PIN w_d[304]
    DIRECTION INPUT ;
    USE SIGNAL ;
    PORT
      LAYER M3 ;
        RECT 16.632 0.000 16.650 0.038 ;
    END
  END w_d[304]
  PIN w_d[305]
    DIRECTION INPUT ;
    USE SIGNAL ;
    PORT
      LAYER M3 ;
        RECT 16.776 0.000 16.794 0.038 ;
    END
  END w_d[305]
  PIN w_d[306]
    DIRECTION INPUT ;
    USE SIGNAL ;
    PORT
      LAYER M3 ;
        RECT 16.920 0.000 16.938 0.038 ;
    END
  END w_d[306]
  PIN w_d[307]
    DIRECTION INPUT ;
    USE SIGNAL ;
    PORT
      LAYER M5 ;
        RECT 17.088 0.000 17.112 0.084 ;
    END
  END w_d[307]
  PIN w_d[308]
    DIRECTION INPUT ;
    USE SIGNAL ;
    PORT
      LAYER M3 ;
        RECT 17.208 0.000 17.226 0.038 ;
    END
  END w_d[308]
  PIN w_d[309]
    DIRECTION INPUT ;
    USE SIGNAL ;
    PORT
      LAYER M5 ;
        RECT 17.376 0.000 17.400 0.084 ;
    END
  END w_d[309]
  PIN w_d[30]
    DIRECTION INPUT ;
    USE SIGNAL ;
    PORT
      LAYER M4 ;
        RECT 0.000 10.320 0.192 10.344 ;
    END
  END w_d[30]
  PIN w_d[310]
    DIRECTION INPUT ;
    USE SIGNAL ;
    PORT
      LAYER M3 ;
        RECT 17.568 0.000 17.586 0.038 ;
    END
  END w_d[310]
  PIN w_d[311]
    DIRECTION INPUT ;
    USE SIGNAL ;
    PORT
      LAYER M5 ;
        RECT 17.664 0.000 17.688 0.084 ;
    END
  END w_d[311]
  PIN w_d[312]
    DIRECTION INPUT ;
    USE SIGNAL ;
    PORT
      LAYER M3 ;
        RECT 17.856 0.000 17.874 0.038 ;
    END
  END w_d[312]
  PIN w_d[313]
    DIRECTION INPUT ;
    USE SIGNAL ;
    PORT
      LAYER M3 ;
        RECT 18.000 0.000 18.018 0.038 ;
    END
  END w_d[313]
  PIN w_d[314]
    DIRECTION INPUT ;
    USE SIGNAL ;
    PORT
      LAYER M3 ;
        RECT 18.144 0.000 18.162 0.038 ;
    END
  END w_d[314]
  PIN w_d[315]
    DIRECTION INPUT ;
    USE SIGNAL ;
    PORT
      LAYER M3 ;
        RECT 18.288 0.000 18.306 0.038 ;
    END
  END w_d[315]
  PIN w_d[316]
    DIRECTION INPUT ;
    USE SIGNAL ;
    PORT
      LAYER M3 ;
        RECT 18.432 0.000 18.450 0.038 ;
    END
  END w_d[316]
  PIN w_d[317]
    DIRECTION INPUT ;
    USE SIGNAL ;
    PORT
      LAYER M3 ;
        RECT 18.576 0.000 18.594 0.038 ;
    END
  END w_d[317]
  PIN w_d[318]
    DIRECTION INPUT ;
    USE SIGNAL ;
    PORT
      LAYER M3 ;
        RECT 18.864 0.000 18.882 0.038 ;
    END
  END w_d[318]
  PIN w_d[319]
    DIRECTION INPUT ;
    USE SIGNAL ;
    PORT
      LAYER M5 ;
        RECT 19.008 0.000 19.032 0.084 ;
    END
  END w_d[319]
  PIN w_d[31]
    DIRECTION INPUT ;
    USE SIGNAL ;
    PORT
      LAYER M4 ;
        RECT 129.408 8.208 129.600 8.232 ;
    END
  END w_d[31]
  PIN w_d[320]
    DIRECTION INPUT ;
    USE SIGNAL ;
    PORT
      LAYER M5 ;
        RECT 19.200 0.000 19.224 0.084 ;
    END
  END w_d[320]
  PIN w_d[321]
    DIRECTION INPUT ;
    USE SIGNAL ;
    PORT
      LAYER M3 ;
        RECT 19.368 0.000 19.386 0.038 ;
    END
  END w_d[321]
  PIN w_d[322]
    DIRECTION INPUT ;
    USE SIGNAL ;
    PORT
      LAYER M5 ;
        RECT 19.488 0.000 19.512 0.084 ;
    END
  END w_d[322]
  PIN w_d[323]
    DIRECTION INPUT ;
    USE SIGNAL ;
    PORT
      LAYER M3 ;
        RECT 19.656 0.000 19.674 0.038 ;
    END
  END w_d[323]
  PIN w_d[324]
    DIRECTION INPUT ;
    USE SIGNAL ;
    PORT
      LAYER M3 ;
        RECT 19.800 0.000 19.818 0.038 ;
    END
  END w_d[324]
  PIN w_d[325]
    DIRECTION INPUT ;
    USE SIGNAL ;
    PORT
      LAYER M3 ;
        RECT 19.944 0.000 19.962 0.038 ;
    END
  END w_d[325]
  PIN w_d[326]
    DIRECTION INPUT ;
    USE SIGNAL ;
    PORT
      LAYER M3 ;
        RECT 20.088 0.000 20.106 0.038 ;
    END
  END w_d[326]
  PIN w_d[327]
    DIRECTION INPUT ;
    USE SIGNAL ;
    PORT
      LAYER M3 ;
        RECT 20.232 0.000 20.250 0.038 ;
    END
  END w_d[327]
  PIN w_d[328]
    DIRECTION INPUT ;
    USE SIGNAL ;
    PORT
      LAYER M3 ;
        RECT 20.376 0.000 20.394 0.038 ;
    END
  END w_d[328]
  PIN w_d[329]
    DIRECTION INPUT ;
    USE SIGNAL ;
    PORT
      LAYER M5 ;
        RECT 20.544 0.000 20.568 0.084 ;
    END
  END w_d[329]
  PIN w_d[32]
    DIRECTION INPUT ;
    USE SIGNAL ;
    PORT
      LAYER M4 ;
        RECT 0.000 10.512 0.192 10.536 ;
    END
  END w_d[32]
  PIN w_d[330]
    DIRECTION INPUT ;
    USE SIGNAL ;
    PORT
      LAYER M3 ;
        RECT 20.664 0.000 20.682 0.038 ;
    END
  END w_d[330]
  PIN w_d[331]
    DIRECTION INPUT ;
    USE SIGNAL ;
    PORT
      LAYER M5 ;
        RECT 20.832 0.000 20.856 0.084 ;
    END
  END w_d[331]
  PIN w_d[332]
    DIRECTION INPUT ;
    USE SIGNAL ;
    PORT
      LAYER M3 ;
        RECT 21.024 0.000 21.042 0.038 ;
    END
  END w_d[332]
  PIN w_d[333]
    DIRECTION INPUT ;
    USE SIGNAL ;
    PORT
      LAYER M5 ;
        RECT 21.120 0.000 21.144 0.084 ;
    END
  END w_d[333]
  PIN w_d[334]
    DIRECTION INPUT ;
    USE SIGNAL ;
    PORT
      LAYER M3 ;
        RECT 21.312 0.000 21.330 0.038 ;
    END
  END w_d[334]
  PIN w_d[335]
    DIRECTION INPUT ;
    USE SIGNAL ;
    PORT
      LAYER M3 ;
        RECT 21.456 0.000 21.474 0.038 ;
    END
  END w_d[335]
  PIN w_d[336]
    DIRECTION INPUT ;
    USE SIGNAL ;
    PORT
      LAYER M3 ;
        RECT 21.600 0.000 21.618 0.038 ;
    END
  END w_d[336]
  PIN w_d[337]
    DIRECTION INPUT ;
    USE SIGNAL ;
    PORT
      LAYER M3 ;
        RECT 21.744 0.000 21.762 0.038 ;
    END
  END w_d[337]
  PIN w_d[338]
    DIRECTION INPUT ;
    USE SIGNAL ;
    PORT
      LAYER M5 ;
        RECT 21.888 0.000 21.912 0.084 ;
    END
  END w_d[338]
  PIN w_d[339]
    DIRECTION INPUT ;
    USE SIGNAL ;
    PORT
      LAYER M3 ;
        RECT 22.032 0.000 22.050 0.038 ;
    END
  END w_d[339]
  PIN w_d[33]
    DIRECTION INPUT ;
    USE SIGNAL ;
    PORT
      LAYER M4 ;
        RECT 129.408 8.304 129.600 8.328 ;
    END
  END w_d[33]
  PIN w_d[340]
    DIRECTION INPUT ;
    USE SIGNAL ;
    PORT
      LAYER M5 ;
        RECT 22.176 0.000 22.200 0.084 ;
    END
  END w_d[340]
  PIN w_d[341]
    DIRECTION INPUT ;
    USE SIGNAL ;
    PORT
      LAYER M3 ;
        RECT 22.320 0.000 22.338 0.038 ;
    END
  END w_d[341]
  PIN w_d[342]
    DIRECTION INPUT ;
    USE SIGNAL ;
    PORT
      LAYER M5 ;
        RECT 22.464 0.000 22.488 0.084 ;
    END
  END w_d[342]
  PIN w_d[343]
    DIRECTION INPUT ;
    USE SIGNAL ;
    PORT
      LAYER M5 ;
        RECT 22.656 0.000 22.680 0.084 ;
    END
  END w_d[343]
  PIN w_d[344]
    DIRECTION INPUT ;
    USE SIGNAL ;
    PORT
      LAYER M5 ;
        RECT 22.752 0.000 22.776 0.084 ;
    END
  END w_d[344]
  PIN w_d[345]
    DIRECTION INPUT ;
    USE SIGNAL ;
    PORT
      LAYER M5 ;
        RECT 22.944 0.000 22.968 0.084 ;
    END
  END w_d[345]
  PIN w_d[346]
    DIRECTION INPUT ;
    USE SIGNAL ;
    PORT
      LAYER M3 ;
        RECT 23.112 0.000 23.130 0.038 ;
    END
  END w_d[346]
  PIN w_d[347]
    DIRECTION INPUT ;
    USE SIGNAL ;
    PORT
      LAYER M5 ;
        RECT 23.232 0.000 23.256 0.084 ;
    END
  END w_d[347]
  PIN w_d[348]
    DIRECTION INPUT ;
    USE SIGNAL ;
    PORT
      LAYER M3 ;
        RECT 23.400 0.000 23.418 0.038 ;
    END
  END w_d[348]
  PIN w_d[349]
    DIRECTION INPUT ;
    USE SIGNAL ;
    PORT
      LAYER M3 ;
        RECT 23.544 0.000 23.562 0.038 ;
    END
  END w_d[349]
  PIN w_d[34]
    DIRECTION INPUT ;
    USE SIGNAL ;
    PORT
      LAYER M4 ;
        RECT 0.000 10.752 0.192 10.776 ;
    END
  END w_d[34]
  PIN w_d[350]
    DIRECTION INPUT ;
    USE SIGNAL ;
    PORT
      LAYER M3 ;
        RECT 23.688 0.000 23.706 0.038 ;
    END
  END w_d[350]
  PIN w_d[351]
    DIRECTION INPUT ;
    USE SIGNAL ;
    PORT
      LAYER M3 ;
        RECT 23.832 0.000 23.850 0.038 ;
    END
  END w_d[351]
  PIN w_d[352]
    DIRECTION INPUT ;
    USE SIGNAL ;
    PORT
      LAYER M3 ;
        RECT 23.976 0.000 23.994 0.038 ;
    END
  END w_d[352]
  PIN w_d[353]
    DIRECTION INPUT ;
    USE SIGNAL ;
    PORT
      LAYER M3 ;
        RECT 24.192 0.000 24.210 0.038 ;
    END
  END w_d[353]
  PIN w_d[354]
    DIRECTION INPUT ;
    USE SIGNAL ;
    PORT
      LAYER M3 ;
        RECT 24.480 0.000 24.498 0.038 ;
    END
  END w_d[354]
  PIN w_d[355]
    DIRECTION INPUT ;
    USE SIGNAL ;
    PORT
      LAYER M5 ;
        RECT 24.576 0.000 24.600 0.084 ;
    END
  END w_d[355]
  PIN w_d[356]
    DIRECTION INPUT ;
    USE SIGNAL ;
    PORT
      LAYER M3 ;
        RECT 24.768 0.000 24.786 0.038 ;
    END
  END w_d[356]
  PIN w_d[357]
    DIRECTION INPUT ;
    USE SIGNAL ;
    PORT
      LAYER M3 ;
        RECT 24.912 0.000 24.930 0.038 ;
    END
  END w_d[357]
  PIN w_d[358]
    DIRECTION INPUT ;
    USE SIGNAL ;
    PORT
      LAYER M3 ;
        RECT 25.056 0.000 25.074 0.038 ;
    END
  END w_d[358]
  PIN w_d[359]
    DIRECTION INPUT ;
    USE SIGNAL ;
    PORT
      LAYER M3 ;
        RECT 25.200 0.000 25.218 0.038 ;
    END
  END w_d[359]
  PIN w_d[35]
    DIRECTION INPUT ;
    USE SIGNAL ;
    PORT
      LAYER M4 ;
        RECT 129.408 8.448 129.600 8.472 ;
    END
  END w_d[35]
  PIN w_d[360]
    DIRECTION INPUT ;
    USE SIGNAL ;
    PORT
      LAYER M5 ;
        RECT 25.344 0.000 25.368 0.084 ;
    END
  END w_d[360]
  PIN w_d[361]
    DIRECTION INPUT ;
    USE SIGNAL ;
    PORT
      LAYER M3 ;
        RECT 25.488 0.000 25.506 0.038 ;
    END
  END w_d[361]
  PIN w_d[362]
    DIRECTION INPUT ;
    USE SIGNAL ;
    PORT
      LAYER M5 ;
        RECT 25.632 0.000 25.656 0.084 ;
    END
  END w_d[362]
  PIN w_d[363]
    DIRECTION INPUT ;
    USE SIGNAL ;
    PORT
      LAYER M3 ;
        RECT 25.776 0.000 25.794 0.038 ;
    END
  END w_d[363]
  PIN w_d[364]
    DIRECTION INPUT ;
    USE SIGNAL ;
    PORT
      LAYER M5 ;
        RECT 25.920 0.000 25.944 0.084 ;
    END
  END w_d[364]
  PIN w_d[365]
    DIRECTION INPUT ;
    USE SIGNAL ;
    PORT
      LAYER M5 ;
        RECT 26.112 0.000 26.136 0.084 ;
    END
  END w_d[365]
  PIN w_d[366]
    DIRECTION INPUT ;
    USE SIGNAL ;
    PORT
      LAYER M5 ;
        RECT 26.208 0.000 26.232 0.084 ;
    END
  END w_d[366]
  PIN w_d[367]
    DIRECTION INPUT ;
    USE SIGNAL ;
    PORT
      LAYER M5 ;
        RECT 26.400 0.000 26.424 0.084 ;
    END
  END w_d[367]
  PIN w_d[368]
    DIRECTION INPUT ;
    USE SIGNAL ;
    PORT
      LAYER M3 ;
        RECT 26.568 0.000 26.586 0.038 ;
    END
  END w_d[368]
  PIN w_d[369]
    DIRECTION INPUT ;
    USE SIGNAL ;
    PORT
      LAYER M5 ;
        RECT 26.688 0.000 26.712 0.084 ;
    END
  END w_d[369]
  PIN w_d[36]
    DIRECTION INPUT ;
    USE SIGNAL ;
    PORT
      LAYER M4 ;
        RECT 0.000 10.944 0.192 10.968 ;
    END
  END w_d[36]
  PIN w_d[370]
    DIRECTION INPUT ;
    USE SIGNAL ;
    PORT
      LAYER M3 ;
        RECT 26.856 0.000 26.874 0.038 ;
    END
  END w_d[370]
  PIN w_d[371]
    DIRECTION INPUT ;
    USE SIGNAL ;
    PORT
      LAYER M3 ;
        RECT 27.000 0.000 27.018 0.038 ;
    END
  END w_d[371]
  PIN w_d[372]
    DIRECTION INPUT ;
    USE SIGNAL ;
    PORT
      LAYER M3 ;
        RECT 27.144 0.000 27.162 0.038 ;
    END
  END w_d[372]
  PIN w_d[373]
    DIRECTION INPUT ;
    USE SIGNAL ;
    PORT
      LAYER M3 ;
        RECT 27.288 0.000 27.306 0.038 ;
    END
  END w_d[373]
  PIN w_d[374]
    DIRECTION INPUT ;
    USE SIGNAL ;
    PORT
      LAYER M3 ;
        RECT 27.432 0.000 27.450 0.038 ;
    END
  END w_d[374]
  PIN w_d[375]
    DIRECTION INPUT ;
    USE SIGNAL ;
    PORT
      LAYER M3 ;
        RECT 27.576 0.000 27.594 0.038 ;
    END
  END w_d[375]
  PIN w_d[376]
    DIRECTION INPUT ;
    USE SIGNAL ;
    PORT
      LAYER M5 ;
        RECT 27.744 0.000 27.768 0.084 ;
    END
  END w_d[376]
  PIN w_d[377]
    DIRECTION INPUT ;
    USE SIGNAL ;
    PORT
      LAYER M3 ;
        RECT 27.864 0.000 27.882 0.038 ;
    END
  END w_d[377]
  PIN w_d[378]
    DIRECTION INPUT ;
    USE SIGNAL ;
    PORT
      LAYER M5 ;
        RECT 28.032 0.000 28.056 0.084 ;
    END
  END w_d[378]
  PIN w_d[379]
    DIRECTION INPUT ;
    USE SIGNAL ;
    PORT
      LAYER M3 ;
        RECT 28.224 0.000 28.242 0.038 ;
    END
  END w_d[379]
  PIN w_d[37]
    DIRECTION INPUT ;
    USE SIGNAL ;
    PORT
      LAYER M4 ;
        RECT 129.408 8.640 129.600 8.664 ;
    END
  END w_d[37]
  PIN w_d[380]
    DIRECTION INPUT ;
    USE SIGNAL ;
    PORT
      LAYER M5 ;
        RECT 28.320 0.000 28.344 0.084 ;
    END
  END w_d[380]
  PIN w_d[381]
    DIRECTION INPUT ;
    USE SIGNAL ;
    PORT
      LAYER M3 ;
        RECT 28.512 0.000 28.530 0.038 ;
    END
  END w_d[381]
  PIN w_d[382]
    DIRECTION INPUT ;
    USE SIGNAL ;
    PORT
      LAYER M3 ;
        RECT 28.656 0.000 28.674 0.038 ;
    END
  END w_d[382]
  PIN w_d[383]
    DIRECTION INPUT ;
    USE SIGNAL ;
    PORT
      LAYER M3 ;
        RECT 28.800 0.000 28.818 0.038 ;
    END
  END w_d[383]
  PIN w_d[384]
    DIRECTION INPUT ;
    USE SIGNAL ;
    PORT
      LAYER M3 ;
        RECT 28.944 0.000 28.962 0.038 ;
    END
  END w_d[384]
  PIN w_d[385]
    DIRECTION INPUT ;
    USE SIGNAL ;
    PORT
      LAYER M5 ;
        RECT 29.088 0.000 29.112 0.084 ;
    END
  END w_d[385]
  PIN w_d[386]
    DIRECTION INPUT ;
    USE SIGNAL ;
    PORT
      LAYER M3 ;
        RECT 29.232 0.000 29.250 0.038 ;
    END
  END w_d[386]
  PIN w_d[387]
    DIRECTION INPUT ;
    USE SIGNAL ;
    PORT
      LAYER M5 ;
        RECT 29.376 0.000 29.400 0.084 ;
    END
  END w_d[387]
  PIN w_d[388]
    DIRECTION INPUT ;
    USE SIGNAL ;
    PORT
      LAYER M3 ;
        RECT 29.592 0.000 29.610 0.038 ;
    END
  END w_d[388]
  PIN w_d[389]
    DIRECTION INPUT ;
    USE SIGNAL ;
    PORT
      LAYER M5 ;
        RECT 29.856 0.000 29.880 0.084 ;
    END
  END w_d[389]
  PIN w_d[38]
    DIRECTION INPUT ;
    USE SIGNAL ;
    PORT
      LAYER M4 ;
        RECT 0.000 11.136 0.192 11.160 ;
    END
  END w_d[38]
  PIN w_d[390]
    DIRECTION INPUT ;
    USE SIGNAL ;
    PORT
      LAYER M3 ;
        RECT 30.024 0.000 30.042 0.038 ;
    END
  END w_d[390]
  PIN w_d[391]
    DIRECTION INPUT ;
    USE SIGNAL ;
    PORT
      LAYER M5 ;
        RECT 30.144 0.000 30.168 0.084 ;
    END
  END w_d[391]
  PIN w_d[392]
    DIRECTION INPUT ;
    USE SIGNAL ;
    PORT
      LAYER M3 ;
        RECT 30.312 0.000 30.330 0.038 ;
    END
  END w_d[392]
  PIN w_d[393]
    DIRECTION INPUT ;
    USE SIGNAL ;
    PORT
      LAYER M3 ;
        RECT 30.456 0.000 30.474 0.038 ;
    END
  END w_d[393]
  PIN w_d[394]
    DIRECTION INPUT ;
    USE SIGNAL ;
    PORT
      LAYER M3 ;
        RECT 30.600 0.000 30.618 0.038 ;
    END
  END w_d[394]
  PIN w_d[395]
    DIRECTION INPUT ;
    USE SIGNAL ;
    PORT
      LAYER M3 ;
        RECT 30.744 0.000 30.762 0.038 ;
    END
  END w_d[395]
  PIN w_d[396]
    DIRECTION INPUT ;
    USE SIGNAL ;
    PORT
      LAYER M5 ;
        RECT 30.912 0.000 30.936 0.084 ;
    END
  END w_d[396]
  PIN w_d[397]
    DIRECTION INPUT ;
    USE SIGNAL ;
    PORT
      LAYER M3 ;
        RECT 31.032 0.000 31.050 0.038 ;
    END
  END w_d[397]
  PIN w_d[398]
    DIRECTION INPUT ;
    USE SIGNAL ;
    PORT
      LAYER M5 ;
        RECT 31.200 0.000 31.224 0.084 ;
    END
  END w_d[398]
  PIN w_d[399]
    DIRECTION INPUT ;
    USE SIGNAL ;
    PORT
      LAYER M3 ;
        RECT 31.320 0.000 31.338 0.038 ;
    END
  END w_d[399]
  PIN w_d[39]
    DIRECTION INPUT ;
    USE SIGNAL ;
    PORT
      LAYER M4 ;
        RECT 129.408 8.784 129.600 8.808 ;
    END
  END w_d[39]
  PIN w_d[3]
    DIRECTION INPUT ;
    USE SIGNAL ;
    PORT
      LAYER M4 ;
        RECT 129.408 6.000 129.600 6.024 ;
    END
  END w_d[3]
  PIN w_d[400]
    DIRECTION INPUT ;
    USE SIGNAL ;
    PORT
      LAYER M5 ;
        RECT 31.488 0.000 31.512 0.084 ;
    END
  END w_d[400]
  PIN w_d[401]
    DIRECTION INPUT ;
    USE SIGNAL ;
    PORT
      LAYER M3 ;
        RECT 31.680 0.000 31.698 0.038 ;
    END
  END w_d[401]
  PIN w_d[402]
    DIRECTION INPUT ;
    USE SIGNAL ;
    PORT
      LAYER M5 ;
        RECT 31.776 0.000 31.800 0.084 ;
    END
  END w_d[402]
  PIN w_d[403]
    DIRECTION INPUT ;
    USE SIGNAL ;
    PORT
      LAYER M3 ;
        RECT 31.968 0.000 31.986 0.038 ;
    END
  END w_d[403]
  PIN w_d[404]
    DIRECTION INPUT ;
    USE SIGNAL ;
    PORT
      LAYER M3 ;
        RECT 32.112 0.000 32.130 0.038 ;
    END
  END w_d[404]
  PIN w_d[405]
    DIRECTION INPUT ;
    USE SIGNAL ;
    PORT
      LAYER M3 ;
        RECT 32.256 0.000 32.274 0.038 ;
    END
  END w_d[405]
  PIN w_d[406]
    DIRECTION INPUT ;
    USE SIGNAL ;
    PORT
      LAYER M3 ;
        RECT 32.400 0.000 32.418 0.038 ;
    END
  END w_d[406]
  PIN w_d[407]
    DIRECTION INPUT ;
    USE SIGNAL ;
    PORT
      LAYER M5 ;
        RECT 32.544 0.000 32.568 0.084 ;
    END
  END w_d[407]
  PIN w_d[408]
    DIRECTION INPUT ;
    USE SIGNAL ;
    PORT
      LAYER M3 ;
        RECT 32.688 0.000 32.706 0.038 ;
    END
  END w_d[408]
  PIN w_d[409]
    DIRECTION INPUT ;
    USE SIGNAL ;
    PORT
      LAYER M5 ;
        RECT 32.832 0.000 32.856 0.084 ;
    END
  END w_d[409]
  PIN w_d[40]
    DIRECTION INPUT ;
    USE SIGNAL ;
    PORT
      LAYER M4 ;
        RECT 0.000 11.328 0.192 11.352 ;
    END
  END w_d[40]
  PIN w_d[410]
    DIRECTION INPUT ;
    USE SIGNAL ;
    PORT
      LAYER M3 ;
        RECT 32.976 0.000 32.994 0.038 ;
    END
  END w_d[410]
  PIN w_d[411]
    DIRECTION INPUT ;
    USE SIGNAL ;
    PORT
      LAYER M5 ;
        RECT 33.120 0.000 33.144 0.084 ;
    END
  END w_d[411]
  PIN w_d[412]
    DIRECTION INPUT ;
    USE SIGNAL ;
    PORT
      LAYER M5 ;
        RECT 33.312 0.000 33.336 0.084 ;
    END
  END w_d[412]
  PIN w_d[413]
    DIRECTION INPUT ;
    USE SIGNAL ;
    PORT
      LAYER M5 ;
        RECT 33.408 0.000 33.432 0.084 ;
    END
  END w_d[413]
  PIN w_d[414]
    DIRECTION INPUT ;
    USE SIGNAL ;
    PORT
      LAYER M5 ;
        RECT 33.600 0.000 33.624 0.084 ;
    END
  END w_d[414]
  PIN w_d[415]
    DIRECTION INPUT ;
    USE SIGNAL ;
    PORT
      LAYER M3 ;
        RECT 33.768 0.000 33.786 0.038 ;
    END
  END w_d[415]
  PIN w_d[416]
    DIRECTION INPUT ;
    USE SIGNAL ;
    PORT
      LAYER M5 ;
        RECT 33.888 0.000 33.912 0.084 ;
    END
  END w_d[416]
  PIN w_d[417]
    DIRECTION INPUT ;
    USE SIGNAL ;
    PORT
      LAYER M3 ;
        RECT 34.056 0.000 34.074 0.038 ;
    END
  END w_d[417]
  PIN w_d[418]
    DIRECTION INPUT ;
    USE SIGNAL ;
    PORT
      LAYER M3 ;
        RECT 34.200 0.000 34.218 0.038 ;
    END
  END w_d[418]
  PIN w_d[419]
    DIRECTION INPUT ;
    USE SIGNAL ;
    PORT
      LAYER M3 ;
        RECT 34.344 0.000 34.362 0.038 ;
    END
  END w_d[419]
  PIN w_d[41]
    DIRECTION INPUT ;
    USE SIGNAL ;
    PORT
      LAYER M4 ;
        RECT 129.408 8.976 129.600 9.000 ;
    END
  END w_d[41]
  PIN w_d[420]
    DIRECTION INPUT ;
    USE SIGNAL ;
    PORT
      LAYER M3 ;
        RECT 34.488 0.000 34.506 0.038 ;
    END
  END w_d[420]
  PIN w_d[421]
    DIRECTION INPUT ;
    USE SIGNAL ;
    PORT
      LAYER M3 ;
        RECT 34.632 0.000 34.650 0.038 ;
    END
  END w_d[421]
  PIN w_d[422]
    DIRECTION INPUT ;
    USE SIGNAL ;
    PORT
      LAYER M3 ;
        RECT 34.776 0.000 34.794 0.038 ;
    END
  END w_d[422]
  PIN w_d[423]
    DIRECTION INPUT ;
    USE SIGNAL ;
    PORT
      LAYER M3 ;
        RECT 35.064 0.000 35.082 0.038 ;
    END
  END w_d[423]
  PIN w_d[424]
    DIRECTION INPUT ;
    USE SIGNAL ;
    PORT
      LAYER M5 ;
        RECT 35.232 0.000 35.256 0.084 ;
    END
  END w_d[424]
  PIN w_d[425]
    DIRECTION INPUT ;
    USE SIGNAL ;
    PORT
      LAYER M3 ;
        RECT 35.424 0.000 35.442 0.038 ;
    END
  END w_d[425]
  PIN w_d[426]
    DIRECTION INPUT ;
    USE SIGNAL ;
    PORT
      LAYER M3 ;
        RECT 35.568 0.000 35.586 0.038 ;
    END
  END w_d[426]
  PIN w_d[427]
    DIRECTION INPUT ;
    USE SIGNAL ;
    PORT
      LAYER M3 ;
        RECT 35.712 0.000 35.730 0.038 ;
    END
  END w_d[427]
  PIN w_d[428]
    DIRECTION INPUT ;
    USE SIGNAL ;
    PORT
      LAYER M3 ;
        RECT 35.856 0.000 35.874 0.038 ;
    END
  END w_d[428]
  PIN w_d[429]
    DIRECTION INPUT ;
    USE SIGNAL ;
    PORT
      LAYER M5 ;
        RECT 36.000 0.000 36.024 0.084 ;
    END
  END w_d[429]
  PIN w_d[42]
    DIRECTION INPUT ;
    USE SIGNAL ;
    PORT
      LAYER M4 ;
        RECT 0.000 11.520 0.192 11.544 ;
    END
  END w_d[42]
  PIN w_d[430]
    DIRECTION INPUT ;
    USE SIGNAL ;
    PORT
      LAYER M3 ;
        RECT 36.144 0.000 36.162 0.038 ;
    END
  END w_d[430]
  PIN w_d[431]
    DIRECTION INPUT ;
    USE SIGNAL ;
    PORT
      LAYER M5 ;
        RECT 36.288 0.000 36.312 0.084 ;
    END
  END w_d[431]
  PIN w_d[432]
    DIRECTION INPUT ;
    USE SIGNAL ;
    PORT
      LAYER M5 ;
        RECT 36.480 0.000 36.504 0.084 ;
    END
  END w_d[432]
  PIN w_d[433]
    DIRECTION INPUT ;
    USE SIGNAL ;
    PORT
      LAYER M5 ;
        RECT 36.576 0.000 36.600 0.084 ;
    END
  END w_d[433]
  PIN w_d[434]
    DIRECTION INPUT ;
    USE SIGNAL ;
    PORT
      LAYER M5 ;
        RECT 36.768 0.000 36.792 0.084 ;
    END
  END w_d[434]
  PIN w_d[435]
    DIRECTION INPUT ;
    USE SIGNAL ;
    PORT
      LAYER M5 ;
        RECT 36.864 0.000 36.888 0.084 ;
    END
  END w_d[435]
  PIN w_d[436]
    DIRECTION INPUT ;
    USE SIGNAL ;
    PORT
      LAYER M5 ;
        RECT 37.056 0.000 37.080 0.084 ;
    END
  END w_d[436]
  PIN w_d[437]
    DIRECTION INPUT ;
    USE SIGNAL ;
    PORT
      LAYER M3 ;
        RECT 37.224 0.000 37.242 0.038 ;
    END
  END w_d[437]
  PIN w_d[438]
    DIRECTION INPUT ;
    USE SIGNAL ;
    PORT
      LAYER M5 ;
        RECT 37.344 0.000 37.368 0.084 ;
    END
  END w_d[438]
  PIN w_d[439]
    DIRECTION INPUT ;
    USE SIGNAL ;
    PORT
      LAYER M3 ;
        RECT 37.512 0.000 37.530 0.038 ;
    END
  END w_d[439]
  PIN w_d[43]
    DIRECTION INPUT ;
    USE SIGNAL ;
    PORT
      LAYER M4 ;
        RECT 129.408 9.072 129.600 9.096 ;
    END
  END w_d[43]
  PIN w_d[440]
    DIRECTION INPUT ;
    USE SIGNAL ;
    PORT
      LAYER M3 ;
        RECT 37.656 0.000 37.674 0.038 ;
    END
  END w_d[440]
  PIN w_d[441]
    DIRECTION INPUT ;
    USE SIGNAL ;
    PORT
      LAYER M3 ;
        RECT 37.800 0.000 37.818 0.038 ;
    END
  END w_d[441]
  PIN w_d[442]
    DIRECTION INPUT ;
    USE SIGNAL ;
    PORT
      LAYER M3 ;
        RECT 37.944 0.000 37.962 0.038 ;
    END
  END w_d[442]
  PIN w_d[443]
    DIRECTION INPUT ;
    USE SIGNAL ;
    PORT
      LAYER M5 ;
        RECT 38.112 0.000 38.136 0.084 ;
    END
  END w_d[443]
  PIN w_d[444]
    DIRECTION INPUT ;
    USE SIGNAL ;
    PORT
      LAYER M3 ;
        RECT 38.232 0.000 38.250 0.038 ;
    END
  END w_d[444]
  PIN w_d[445]
    DIRECTION INPUT ;
    USE SIGNAL ;
    PORT
      LAYER M5 ;
        RECT 38.400 0.000 38.424 0.084 ;
    END
  END w_d[445]
  PIN w_d[446]
    DIRECTION INPUT ;
    USE SIGNAL ;
    PORT
      LAYER M3 ;
        RECT 38.520 0.000 38.538 0.038 ;
    END
  END w_d[446]
  PIN w_d[447]
    DIRECTION INPUT ;
    USE SIGNAL ;
    PORT
      LAYER M5 ;
        RECT 38.688 0.000 38.712 0.084 ;
    END
  END w_d[447]
  PIN w_d[448]
    DIRECTION INPUT ;
    USE SIGNAL ;
    PORT
      LAYER M3 ;
        RECT 38.880 0.000 38.898 0.038 ;
    END
  END w_d[448]
  PIN w_d[449]
    DIRECTION INPUT ;
    USE SIGNAL ;
    PORT
      LAYER M5 ;
        RECT 38.976 0.000 39.000 0.084 ;
    END
  END w_d[449]
  PIN w_d[44]
    DIRECTION INPUT ;
    USE SIGNAL ;
    PORT
      LAYER M4 ;
        RECT 0.000 11.712 0.192 11.736 ;
    END
  END w_d[44]
  PIN w_d[450]
    DIRECTION INPUT ;
    USE SIGNAL ;
    PORT
      LAYER M3 ;
        RECT 39.168 0.000 39.186 0.038 ;
    END
  END w_d[450]
  PIN w_d[451]
    DIRECTION INPUT ;
    USE SIGNAL ;
    PORT
      LAYER M3 ;
        RECT 39.312 0.000 39.330 0.038 ;
    END
  END w_d[451]
  PIN w_d[452]
    DIRECTION INPUT ;
    USE SIGNAL ;
    PORT
      LAYER M3 ;
        RECT 39.456 0.000 39.474 0.038 ;
    END
  END w_d[452]
  PIN w_d[453]
    DIRECTION INPUT ;
    USE SIGNAL ;
    PORT
      LAYER M3 ;
        RECT 39.600 0.000 39.618 0.038 ;
    END
  END w_d[453]
  PIN w_d[454]
    DIRECTION INPUT ;
    USE SIGNAL ;
    PORT
      LAYER M5 ;
        RECT 39.744 0.000 39.768 0.084 ;
    END
  END w_d[454]
  PIN w_d[455]
    DIRECTION INPUT ;
    USE SIGNAL ;
    PORT
      LAYER M3 ;
        RECT 39.888 0.000 39.906 0.038 ;
    END
  END w_d[455]
  PIN w_d[456]
    DIRECTION INPUT ;
    USE SIGNAL ;
    PORT
      LAYER M5 ;
        RECT 40.032 0.000 40.056 0.084 ;
    END
  END w_d[456]
  PIN w_d[457]
    DIRECTION INPUT ;
    USE SIGNAL ;
    PORT
      LAYER M3 ;
        RECT 40.176 0.000 40.194 0.038 ;
    END
  END w_d[457]
  PIN w_d[458]
    DIRECTION INPUT ;
    USE SIGNAL ;
    PORT
      LAYER M3 ;
        RECT 40.464 0.000 40.482 0.038 ;
    END
  END w_d[458]
  PIN w_d[459]
    DIRECTION INPUT ;
    USE SIGNAL ;
    PORT
      LAYER M3 ;
        RECT 40.680 0.000 40.698 0.038 ;
    END
  END w_d[459]
  PIN w_d[45]
    DIRECTION INPUT ;
    USE SIGNAL ;
    PORT
      LAYER M4 ;
        RECT 129.408 9.264 129.600 9.288 ;
    END
  END w_d[45]
  PIN w_d[460]
    DIRECTION INPUT ;
    USE SIGNAL ;
    PORT
      LAYER M5 ;
        RECT 40.800 0.000 40.824 0.084 ;
    END
  END w_d[460]
  PIN w_d[461]
    DIRECTION INPUT ;
    USE SIGNAL ;
    PORT
      LAYER M3 ;
        RECT 40.968 0.000 40.986 0.038 ;
    END
  END w_d[461]
  PIN w_d[462]
    DIRECTION INPUT ;
    USE SIGNAL ;
    PORT
      LAYER M3 ;
        RECT 41.112 0.000 41.130 0.038 ;
    END
  END w_d[462]
  PIN w_d[463]
    DIRECTION INPUT ;
    USE SIGNAL ;
    PORT
      LAYER M3 ;
        RECT 41.256 0.000 41.274 0.038 ;
    END
  END w_d[463]
  PIN w_d[464]
    DIRECTION INPUT ;
    USE SIGNAL ;
    PORT
      LAYER M3 ;
        RECT 41.400 0.000 41.418 0.038 ;
    END
  END w_d[464]
  PIN w_d[465]
    DIRECTION INPUT ;
    USE SIGNAL ;
    PORT
      LAYER M5 ;
        RECT 41.568 0.000 41.592 0.084 ;
    END
  END w_d[465]
  PIN w_d[466]
    DIRECTION INPUT ;
    USE SIGNAL ;
    PORT
      LAYER M3 ;
        RECT 41.688 0.000 41.706 0.038 ;
    END
  END w_d[466]
  PIN w_d[467]
    DIRECTION INPUT ;
    USE SIGNAL ;
    PORT
      LAYER M5 ;
        RECT 41.856 0.000 41.880 0.084 ;
    END
  END w_d[467]
  PIN w_d[468]
    DIRECTION INPUT ;
    USE SIGNAL ;
    PORT
      LAYER M3 ;
        RECT 41.976 0.000 41.994 0.038 ;
    END
  END w_d[468]
  PIN w_d[469]
    DIRECTION INPUT ;
    USE SIGNAL ;
    PORT
      LAYER M5 ;
        RECT 42.144 0.000 42.168 0.084 ;
    END
  END w_d[469]
  PIN w_d[46]
    DIRECTION INPUT ;
    USE SIGNAL ;
    PORT
      LAYER M4 ;
        RECT 0.000 11.904 0.192 11.928 ;
    END
  END w_d[46]
  PIN w_d[470]
    DIRECTION INPUT ;
    USE SIGNAL ;
    PORT
      LAYER M3 ;
        RECT 42.336 0.000 42.354 0.038 ;
    END
  END w_d[470]
  PIN w_d[471]
    DIRECTION INPUT ;
    USE SIGNAL ;
    PORT
      LAYER M5 ;
        RECT 42.432 0.000 42.456 0.084 ;
    END
  END w_d[471]
  PIN w_d[472]
    DIRECTION INPUT ;
    USE SIGNAL ;
    PORT
      LAYER M3 ;
        RECT 42.624 0.000 42.642 0.038 ;
    END
  END w_d[472]
  PIN w_d[473]
    DIRECTION INPUT ;
    USE SIGNAL ;
    PORT
      LAYER M3 ;
        RECT 42.768 0.000 42.786 0.038 ;
    END
  END w_d[473]
  PIN w_d[474]
    DIRECTION INPUT ;
    USE SIGNAL ;
    PORT
      LAYER M3 ;
        RECT 42.912 0.000 42.930 0.038 ;
    END
  END w_d[474]
  PIN w_d[475]
    DIRECTION INPUT ;
    USE SIGNAL ;
    PORT
      LAYER M3 ;
        RECT 43.056 0.000 43.074 0.038 ;
    END
  END w_d[475]
  PIN w_d[476]
    DIRECTION INPUT ;
    USE SIGNAL ;
    PORT
      LAYER M5 ;
        RECT 43.200 0.000 43.224 0.084 ;
    END
  END w_d[476]
  PIN w_d[477]
    DIRECTION INPUT ;
    USE SIGNAL ;
    PORT
      LAYER M3 ;
        RECT 43.344 0.000 43.362 0.038 ;
    END
  END w_d[477]
  PIN w_d[478]
    DIRECTION INPUT ;
    USE SIGNAL ;
    PORT
      LAYER M5 ;
        RECT 43.488 0.000 43.512 0.084 ;
    END
  END w_d[478]
  PIN w_d[479]
    DIRECTION INPUT ;
    USE SIGNAL ;
    PORT
      LAYER M5 ;
        RECT 43.680 0.000 43.704 0.084 ;
    END
  END w_d[479]
  PIN w_d[47]
    DIRECTION INPUT ;
    USE SIGNAL ;
    PORT
      LAYER M4 ;
        RECT 129.408 9.408 129.600 9.432 ;
    END
  END w_d[47]
  PIN w_d[480]
    DIRECTION INPUT ;
    USE SIGNAL ;
    PORT
      LAYER M5 ;
        RECT 43.776 0.000 43.800 0.084 ;
    END
  END w_d[480]
  PIN w_d[481]
    DIRECTION INPUT ;
    USE SIGNAL ;
    PORT
      LAYER M5 ;
        RECT 43.968 0.000 43.992 0.084 ;
    END
  END w_d[481]
  PIN w_d[482]
    DIRECTION INPUT ;
    USE SIGNAL ;
    PORT
      LAYER M5 ;
        RECT 44.064 0.000 44.088 0.084 ;
    END
  END w_d[482]
  PIN w_d[483]
    DIRECTION INPUT ;
    USE SIGNAL ;
    PORT
      LAYER M5 ;
        RECT 44.256 0.000 44.280 0.084 ;
    END
  END w_d[483]
  PIN w_d[484]
    DIRECTION INPUT ;
    USE SIGNAL ;
    PORT
      LAYER M3 ;
        RECT 44.424 0.000 44.442 0.038 ;
    END
  END w_d[484]
  PIN w_d[485]
    DIRECTION INPUT ;
    USE SIGNAL ;
    PORT
      LAYER M5 ;
        RECT 44.544 0.000 44.568 0.084 ;
    END
  END w_d[485]
  PIN w_d[486]
    DIRECTION INPUT ;
    USE SIGNAL ;
    PORT
      LAYER M3 ;
        RECT 44.712 0.000 44.730 0.038 ;
    END
  END w_d[486]
  PIN w_d[487]
    DIRECTION INPUT ;
    USE SIGNAL ;
    PORT
      LAYER M3 ;
        RECT 44.856 0.000 44.874 0.038 ;
    END
  END w_d[487]
  PIN w_d[488]
    DIRECTION INPUT ;
    USE SIGNAL ;
    PORT
      LAYER M3 ;
        RECT 45.000 0.000 45.018 0.038 ;
    END
  END w_d[488]
  PIN w_d[489]
    DIRECTION INPUT ;
    USE SIGNAL ;
    PORT
      LAYER M3 ;
        RECT 45.144 0.000 45.162 0.038 ;
    END
  END w_d[489]
  PIN w_d[48]
    DIRECTION INPUT ;
    USE SIGNAL ;
    PORT
      LAYER M4 ;
        RECT 0.000 12.096 0.192 12.120 ;
    END
  END w_d[48]
  PIN w_d[490]
    DIRECTION INPUT ;
    USE SIGNAL ;
    PORT
      LAYER M5 ;
        RECT 45.312 0.000 45.336 0.084 ;
    END
  END w_d[490]
  PIN w_d[491]
    DIRECTION INPUT ;
    USE SIGNAL ;
    PORT
      LAYER M3 ;
        RECT 45.432 0.000 45.450 0.038 ;
    END
  END w_d[491]
  PIN w_d[492]
    DIRECTION INPUT ;
    USE SIGNAL ;
    PORT
      LAYER M5 ;
        RECT 45.600 0.000 45.624 0.084 ;
    END
  END w_d[492]
  PIN w_d[493]
    DIRECTION INPUT ;
    USE SIGNAL ;
    PORT
      LAYER M3 ;
        RECT 45.792 0.000 45.810 0.038 ;
    END
  END w_d[493]
  PIN w_d[494]
    DIRECTION INPUT ;
    USE SIGNAL ;
    PORT
      LAYER M3 ;
        RECT 46.080 0.000 46.098 0.038 ;
    END
  END w_d[494]
  PIN w_d[495]
    DIRECTION INPUT ;
    USE SIGNAL ;
    PORT
      LAYER M3 ;
        RECT 46.224 0.000 46.242 0.038 ;
    END
  END w_d[495]
  PIN w_d[496]
    DIRECTION INPUT ;
    USE SIGNAL ;
    PORT
      LAYER M3 ;
        RECT 46.368 0.000 46.386 0.038 ;
    END
  END w_d[496]
  PIN w_d[497]
    DIRECTION INPUT ;
    USE SIGNAL ;
    PORT
      LAYER M3 ;
        RECT 46.512 0.000 46.530 0.038 ;
    END
  END w_d[497]
  PIN w_d[498]
    DIRECTION INPUT ;
    USE SIGNAL ;
    PORT
      LAYER M5 ;
        RECT 46.656 0.000 46.680 0.084 ;
    END
  END w_d[498]
  PIN w_d[499]
    DIRECTION INPUT ;
    USE SIGNAL ;
    PORT
      LAYER M3 ;
        RECT 46.800 0.000 46.818 0.038 ;
    END
  END w_d[499]
  PIN w_d[49]
    DIRECTION INPUT ;
    USE SIGNAL ;
    PORT
      LAYER M4 ;
        RECT 129.408 9.552 129.600 9.576 ;
    END
  END w_d[49]
  PIN w_d[4]
    DIRECTION INPUT ;
    USE SIGNAL ;
    PORT
      LAYER M4 ;
        RECT 0.000 7.728 0.192 7.752 ;
    END
  END w_d[4]
  PIN w_d[500]
    DIRECTION INPUT ;
    USE SIGNAL ;
    PORT
      LAYER M5 ;
        RECT 46.944 0.000 46.968 0.084 ;
    END
  END w_d[500]
  PIN w_d[501]
    DIRECTION INPUT ;
    USE SIGNAL ;
    PORT
      LAYER M5 ;
        RECT 47.136 0.000 47.160 0.084 ;
    END
  END w_d[501]
  PIN w_d[502]
    DIRECTION INPUT ;
    USE SIGNAL ;
    PORT
      LAYER M5 ;
        RECT 47.232 0.000 47.256 0.084 ;
    END
  END w_d[502]
  PIN w_d[503]
    DIRECTION INPUT ;
    USE SIGNAL ;
    PORT
      LAYER M5 ;
        RECT 47.424 0.000 47.448 0.084 ;
    END
  END w_d[503]
  PIN w_d[504]
    DIRECTION INPUT ;
    USE SIGNAL ;
    PORT
      LAYER M5 ;
        RECT 47.520 0.000 47.544 0.084 ;
    END
  END w_d[504]
  PIN w_d[505]
    DIRECTION INPUT ;
    USE SIGNAL ;
    PORT
      LAYER M5 ;
        RECT 47.712 0.000 47.736 0.084 ;
    END
  END w_d[505]
  PIN w_d[506]
    DIRECTION INPUT ;
    USE SIGNAL ;
    PORT
      LAYER M3 ;
        RECT 47.880 0.000 47.898 0.038 ;
    END
  END w_d[506]
  PIN w_d[507]
    DIRECTION INPUT ;
    USE SIGNAL ;
    PORT
      LAYER M5 ;
        RECT 48.000 0.000 48.024 0.084 ;
    END
  END w_d[507]
  PIN w_d[508]
    DIRECTION INPUT ;
    USE SIGNAL ;
    PORT
      LAYER M3 ;
        RECT 48.168 0.000 48.186 0.038 ;
    END
  END w_d[508]
  PIN w_d[509]
    DIRECTION INPUT ;
    USE SIGNAL ;
    PORT
      LAYER M3 ;
        RECT 48.312 0.000 48.330 0.038 ;
    END
  END w_d[509]
  PIN w_d[50]
    DIRECTION INPUT ;
    USE SIGNAL ;
    PORT
      LAYER M4 ;
        RECT 0.000 12.288 0.192 12.312 ;
    END
  END w_d[50]
  PIN w_d[510]
    DIRECTION INPUT ;
    USE SIGNAL ;
    PORT
      LAYER M3 ;
        RECT 48.456 0.000 48.474 0.038 ;
    END
  END w_d[510]
  PIN w_d[511]
    DIRECTION INPUT ;
    USE SIGNAL ;
    PORT
      LAYER M3 ;
        RECT 48.600 0.000 48.618 0.038 ;
    END
  END w_d[511]
  PIN w_d[512]
    DIRECTION INPUT ;
    USE SIGNAL ;
    PORT
      LAYER M5 ;
        RECT 48.768 0.000 48.792 0.084 ;
    END
  END w_d[512]
  PIN w_d[513]
    DIRECTION INPUT ;
    USE SIGNAL ;
    PORT
      LAYER M3 ;
        RECT 48.888 0.000 48.906 0.038 ;
    END
  END w_d[513]
  PIN w_d[514]
    DIRECTION INPUT ;
    USE SIGNAL ;
    PORT
      LAYER M5 ;
        RECT 49.056 0.000 49.080 0.084 ;
    END
  END w_d[514]
  PIN w_d[515]
    DIRECTION INPUT ;
    USE SIGNAL ;
    PORT
      LAYER M3 ;
        RECT 49.176 0.000 49.194 0.038 ;
    END
  END w_d[515]
  PIN w_d[516]
    DIRECTION INPUT ;
    USE SIGNAL ;
    PORT
      LAYER M5 ;
        RECT 49.344 0.000 49.368 0.084 ;
    END
  END w_d[516]
  PIN w_d[517]
    DIRECTION INPUT ;
    USE SIGNAL ;
    PORT
      LAYER M3 ;
        RECT 49.536 0.000 49.554 0.038 ;
    END
  END w_d[517]
  PIN w_d[518]
    DIRECTION INPUT ;
    USE SIGNAL ;
    PORT
      LAYER M5 ;
        RECT 49.632 0.000 49.656 0.084 ;
    END
  END w_d[518]
  PIN w_d[519]
    DIRECTION INPUT ;
    USE SIGNAL ;
    PORT
      LAYER M3 ;
        RECT 49.824 0.000 49.842 0.038 ;
    END
  END w_d[519]
  PIN w_d[51]
    DIRECTION INPUT ;
    USE SIGNAL ;
    PORT
      LAYER M4 ;
        RECT 129.408 9.744 129.600 9.768 ;
    END
  END w_d[51]
  PIN w_d[520]
    DIRECTION INPUT ;
    USE SIGNAL ;
    PORT
      LAYER M3 ;
        RECT 49.968 0.000 49.986 0.038 ;
    END
  END w_d[520]
  PIN w_d[521]
    DIRECTION INPUT ;
    USE SIGNAL ;
    PORT
      LAYER M3 ;
        RECT 50.112 0.000 50.130 0.038 ;
    END
  END w_d[521]
  PIN w_d[522]
    DIRECTION INPUT ;
    USE SIGNAL ;
    PORT
      LAYER M3 ;
        RECT 50.256 0.000 50.274 0.038 ;
    END
  END w_d[522]
  PIN w_d[523]
    DIRECTION INPUT ;
    USE SIGNAL ;
    PORT
      LAYER M5 ;
        RECT 50.400 0.000 50.424 0.084 ;
    END
  END w_d[523]
  PIN w_d[524]
    DIRECTION INPUT ;
    USE SIGNAL ;
    PORT
      LAYER M3 ;
        RECT 50.544 0.000 50.562 0.038 ;
    END
  END w_d[524]
  PIN w_d[525]
    DIRECTION INPUT ;
    USE SIGNAL ;
    PORT
      LAYER M5 ;
        RECT 50.688 0.000 50.712 0.084 ;
    END
  END w_d[525]
  PIN w_d[526]
    DIRECTION INPUT ;
    USE SIGNAL ;
    PORT
      LAYER M5 ;
        RECT 50.880 0.000 50.904 0.084 ;
    END
  END w_d[526]
  PIN w_d[527]
    DIRECTION INPUT ;
    USE SIGNAL ;
    PORT
      LAYER M5 ;
        RECT 50.976 0.000 51.000 0.084 ;
    END
  END w_d[527]
  PIN w_d[528]
    DIRECTION INPUT ;
    USE SIGNAL ;
    PORT
      LAYER M3 ;
        RECT 51.264 0.000 51.282 0.038 ;
    END
  END w_d[528]
  PIN w_d[529]
    DIRECTION INPUT ;
    USE SIGNAL ;
    PORT
      LAYER M5 ;
        RECT 51.456 0.000 51.480 0.084 ;
    END
  END w_d[529]
  PIN w_d[52]
    DIRECTION INPUT ;
    USE SIGNAL ;
    PORT
      LAYER M4 ;
        RECT 0.000 12.480 0.192 12.504 ;
    END
  END w_d[52]
  PIN w_d[530]
    DIRECTION INPUT ;
    USE SIGNAL ;
    PORT
      LAYER M3 ;
        RECT 51.624 0.000 51.642 0.038 ;
    END
  END w_d[530]
  PIN w_d[531]
    DIRECTION INPUT ;
    USE SIGNAL ;
    PORT
      LAYER M3 ;
        RECT 51.768 0.000 51.786 0.038 ;
    END
  END w_d[531]
  PIN w_d[532]
    DIRECTION INPUT ;
    USE SIGNAL ;
    PORT
      LAYER M3 ;
        RECT 51.912 0.000 51.930 0.038 ;
    END
  END w_d[532]
  PIN w_d[533]
    DIRECTION INPUT ;
    USE SIGNAL ;
    PORT
      LAYER M3 ;
        RECT 52.056 0.000 52.074 0.038 ;
    END
  END w_d[533]
  PIN w_d[534]
    DIRECTION INPUT ;
    USE SIGNAL ;
    PORT
      LAYER M5 ;
        RECT 52.224 0.000 52.248 0.084 ;
    END
  END w_d[534]
  PIN w_d[535]
    DIRECTION INPUT ;
    USE SIGNAL ;
    PORT
      LAYER M3 ;
        RECT 52.344 0.000 52.362 0.038 ;
    END
  END w_d[535]
  PIN w_d[536]
    DIRECTION INPUT ;
    USE SIGNAL ;
    PORT
      LAYER M5 ;
        RECT 52.512 0.000 52.536 0.084 ;
    END
  END w_d[536]
  PIN w_d[537]
    DIRECTION INPUT ;
    USE SIGNAL ;
    PORT
      LAYER M3 ;
        RECT 52.704 0.000 52.722 0.038 ;
    END
  END w_d[537]
  PIN w_d[538]
    DIRECTION INPUT ;
    USE SIGNAL ;
    PORT
      LAYER M5 ;
        RECT 52.800 0.000 52.824 0.084 ;
    END
  END w_d[538]
  PIN w_d[539]
    DIRECTION INPUT ;
    USE SIGNAL ;
    PORT
      LAYER M3 ;
        RECT 52.992 0.000 53.010 0.038 ;
    END
  END w_d[539]
  PIN w_d[53]
    DIRECTION INPUT ;
    USE SIGNAL ;
    PORT
      LAYER M4 ;
        RECT 129.408 9.840 129.600 9.864 ;
    END
  END w_d[53]
  PIN w_d[540]
    DIRECTION INPUT ;
    USE SIGNAL ;
    PORT
      LAYER M5 ;
        RECT 53.088 0.000 53.112 0.084 ;
    END
  END w_d[540]
  PIN w_d[541]
    DIRECTION INPUT ;
    USE SIGNAL ;
    PORT
      LAYER M3 ;
        RECT 53.280 0.000 53.298 0.038 ;
    END
  END w_d[541]
  PIN w_d[542]
    DIRECTION INPUT ;
    USE SIGNAL ;
    PORT
      LAYER M3 ;
        RECT 53.424 0.000 53.442 0.038 ;
    END
  END w_d[542]
  PIN w_d[543]
    DIRECTION INPUT ;
    USE SIGNAL ;
    PORT
      LAYER M3 ;
        RECT 53.568 0.000 53.586 0.038 ;
    END
  END w_d[543]
  PIN w_d[544]
    DIRECTION INPUT ;
    USE SIGNAL ;
    PORT
      LAYER M3 ;
        RECT 53.712 0.000 53.730 0.038 ;
    END
  END w_d[544]
  PIN w_d[545]
    DIRECTION INPUT ;
    USE SIGNAL ;
    PORT
      LAYER M5 ;
        RECT 53.856 0.000 53.880 0.084 ;
    END
  END w_d[545]
  PIN w_d[546]
    DIRECTION INPUT ;
    USE SIGNAL ;
    PORT
      LAYER M3 ;
        RECT 54.000 0.000 54.018 0.038 ;
    END
  END w_d[546]
  PIN w_d[547]
    DIRECTION INPUT ;
    USE SIGNAL ;
    PORT
      LAYER M5 ;
        RECT 54.144 0.000 54.168 0.084 ;
    END
  END w_d[547]
  PIN w_d[548]
    DIRECTION INPUT ;
    USE SIGNAL ;
    PORT
      LAYER M5 ;
        RECT 54.336 0.000 54.360 0.084 ;
    END
  END w_d[548]
  PIN w_d[549]
    DIRECTION INPUT ;
    USE SIGNAL ;
    PORT
      LAYER M5 ;
        RECT 54.432 0.000 54.456 0.084 ;
    END
  END w_d[549]
  PIN w_d[54]
    DIRECTION INPUT ;
    USE SIGNAL ;
    PORT
      LAYER M4 ;
        RECT 0.000 12.672 0.192 12.696 ;
    END
  END w_d[54]
  PIN w_d[550]
    DIRECTION INPUT ;
    USE SIGNAL ;
    PORT
      LAYER M5 ;
        RECT 54.624 0.000 54.648 0.084 ;
    END
  END w_d[550]
  PIN w_d[551]
    DIRECTION INPUT ;
    USE SIGNAL ;
    PORT
      LAYER M5 ;
        RECT 54.720 0.000 54.744 0.084 ;
    END
  END w_d[551]
  PIN w_d[552]
    DIRECTION INPUT ;
    USE SIGNAL ;
    PORT
      LAYER M5 ;
        RECT 54.912 0.000 54.936 0.084 ;
    END
  END w_d[552]
  PIN w_d[553]
    DIRECTION INPUT ;
    USE SIGNAL ;
    PORT
      LAYER M3 ;
        RECT 55.080 0.000 55.098 0.038 ;
    END
  END w_d[553]
  PIN w_d[554]
    DIRECTION INPUT ;
    USE SIGNAL ;
    PORT
      LAYER M5 ;
        RECT 55.200 0.000 55.224 0.084 ;
    END
  END w_d[554]
  PIN w_d[555]
    DIRECTION INPUT ;
    USE SIGNAL ;
    PORT
      LAYER M3 ;
        RECT 55.368 0.000 55.386 0.038 ;
    END
  END w_d[555]
  PIN w_d[556]
    DIRECTION INPUT ;
    USE SIGNAL ;
    PORT
      LAYER M3 ;
        RECT 55.512 0.000 55.530 0.038 ;
    END
  END w_d[556]
  PIN w_d[557]
    DIRECTION INPUT ;
    USE SIGNAL ;
    PORT
      LAYER M3 ;
        RECT 55.656 0.000 55.674 0.038 ;
    END
  END w_d[557]
  PIN w_d[558]
    DIRECTION INPUT ;
    USE SIGNAL ;
    PORT
      LAYER M3 ;
        RECT 55.800 0.000 55.818 0.038 ;
    END
  END w_d[558]
  PIN w_d[559]
    DIRECTION INPUT ;
    USE SIGNAL ;
    PORT
      LAYER M5 ;
        RECT 55.968 0.000 55.992 0.084 ;
    END
  END w_d[559]
  PIN w_d[55]
    DIRECTION INPUT ;
    USE SIGNAL ;
    PORT
      LAYER M4 ;
        RECT 129.408 10.032 129.600 10.056 ;
    END
  END w_d[55]
  PIN w_d[560]
    DIRECTION INPUT ;
    USE SIGNAL ;
    PORT
      LAYER M3 ;
        RECT 56.088 0.000 56.106 0.038 ;
    END
  END w_d[560]
  PIN w_d[561]
    DIRECTION INPUT ;
    USE SIGNAL ;
    PORT
      LAYER M5 ;
        RECT 56.256 0.000 56.280 0.084 ;
    END
  END w_d[561]
  PIN w_d[562]
    DIRECTION INPUT ;
    USE SIGNAL ;
    PORT
      LAYER M3 ;
        RECT 56.376 0.000 56.394 0.038 ;
    END
  END w_d[562]
  PIN w_d[563]
    DIRECTION INPUT ;
    USE SIGNAL ;
    PORT
      LAYER M3 ;
        RECT 56.664 0.000 56.682 0.038 ;
    END
  END w_d[563]
  PIN w_d[564]
    DIRECTION INPUT ;
    USE SIGNAL ;
    PORT
      LAYER M3 ;
        RECT 56.880 0.000 56.898 0.038 ;
    END
  END w_d[564]
  PIN w_d[565]
    DIRECTION INPUT ;
    USE SIGNAL ;
    PORT
      LAYER M3 ;
        RECT 57.024 0.000 57.042 0.038 ;
    END
  END w_d[565]
  PIN w_d[566]
    DIRECTION INPUT ;
    USE SIGNAL ;
    PORT
      LAYER M3 ;
        RECT 57.168 0.000 57.186 0.038 ;
    END
  END w_d[566]
  PIN w_d[567]
    DIRECTION INPUT ;
    USE SIGNAL ;
    PORT
      LAYER M5 ;
        RECT 57.312 0.000 57.336 0.084 ;
    END
  END w_d[567]
  PIN w_d[568]
    DIRECTION INPUT ;
    USE SIGNAL ;
    PORT
      LAYER M3 ;
        RECT 57.456 0.000 57.474 0.038 ;
    END
  END w_d[568]
  PIN w_d[569]
    DIRECTION INPUT ;
    USE SIGNAL ;
    PORT
      LAYER M5 ;
        RECT 57.600 0.000 57.624 0.084 ;
    END
  END w_d[569]
  PIN w_d[56]
    DIRECTION INPUT ;
    USE SIGNAL ;
    PORT
      LAYER M4 ;
        RECT 0.000 12.912 0.192 12.936 ;
    END
  END w_d[56]
  PIN w_d[570]
    DIRECTION INPUT ;
    USE SIGNAL ;
    PORT
      LAYER M5 ;
        RECT 57.792 0.000 57.816 0.084 ;
    END
  END w_d[570]
  PIN w_d[571]
    DIRECTION INPUT ;
    USE SIGNAL ;
    PORT
      LAYER M5 ;
        RECT 57.888 0.000 57.912 0.084 ;
    END
  END w_d[571]
  PIN w_d[572]
    DIRECTION INPUT ;
    USE SIGNAL ;
    PORT
      LAYER M5 ;
        RECT 58.080 0.000 58.104 0.084 ;
    END
  END w_d[572]
  PIN w_d[573]
    DIRECTION INPUT ;
    USE SIGNAL ;
    PORT
      LAYER M3 ;
        RECT 58.248 0.000 58.266 0.038 ;
    END
  END w_d[573]
  PIN w_d[574]
    DIRECTION INPUT ;
    USE SIGNAL ;
    PORT
      LAYER M5 ;
        RECT 58.368 0.000 58.392 0.084 ;
    END
  END w_d[574]
  PIN w_d[575]
    DIRECTION INPUT ;
    USE SIGNAL ;
    PORT
      LAYER M3 ;
        RECT 58.536 0.000 58.554 0.038 ;
    END
  END w_d[575]
  PIN w_d[576]
    DIRECTION INPUT ;
    USE SIGNAL ;
    PORT
      LAYER M5 ;
        RECT 58.656 0.000 58.680 0.084 ;
    END
  END w_d[576]
  PIN w_d[577]
    DIRECTION INPUT ;
    USE SIGNAL ;
    PORT
      LAYER M3 ;
        RECT 58.824 0.000 58.842 0.038 ;
    END
  END w_d[577]
  PIN w_d[578]
    DIRECTION INPUT ;
    USE SIGNAL ;
    PORT
      LAYER M3 ;
        RECT 58.968 0.000 58.986 0.038 ;
    END
  END w_d[578]
  PIN w_d[579]
    DIRECTION INPUT ;
    USE SIGNAL ;
    PORT
      LAYER M3 ;
        RECT 59.112 0.000 59.130 0.038 ;
    END
  END w_d[579]
  PIN w_d[57]
    DIRECTION INPUT ;
    USE SIGNAL ;
    PORT
      LAYER M4 ;
        RECT 129.408 10.176 129.600 10.200 ;
    END
  END w_d[57]
  PIN w_d[580]
    DIRECTION INPUT ;
    USE SIGNAL ;
    PORT
      LAYER M3 ;
        RECT 59.256 0.000 59.274 0.038 ;
    END
  END w_d[580]
  PIN w_d[581]
    DIRECTION INPUT ;
    USE SIGNAL ;
    PORT
      LAYER M5 ;
        RECT 59.424 0.000 59.448 0.084 ;
    END
  END w_d[581]
  PIN w_d[582]
    DIRECTION INPUT ;
    USE SIGNAL ;
    PORT
      LAYER M3 ;
        RECT 59.544 0.000 59.562 0.038 ;
    END
  END w_d[582]
  PIN w_d[583]
    DIRECTION INPUT ;
    USE SIGNAL ;
    PORT
      LAYER M5 ;
        RECT 59.712 0.000 59.736 0.084 ;
    END
  END w_d[583]
  PIN w_d[584]
    DIRECTION INPUT ;
    USE SIGNAL ;
    PORT
      LAYER M3 ;
        RECT 59.904 0.000 59.922 0.038 ;
    END
  END w_d[584]
  PIN w_d[585]
    DIRECTION INPUT ;
    USE SIGNAL ;
    PORT
      LAYER M5 ;
        RECT 60.000 0.000 60.024 0.084 ;
    END
  END w_d[585]
  PIN w_d[586]
    DIRECTION INPUT ;
    USE SIGNAL ;
    PORT
      LAYER M3 ;
        RECT 60.192 0.000 60.210 0.038 ;
    END
  END w_d[586]
  PIN w_d[587]
    DIRECTION INPUT ;
    USE SIGNAL ;
    PORT
      LAYER M5 ;
        RECT 60.288 0.000 60.312 0.084 ;
    END
  END w_d[587]
  PIN w_d[588]
    DIRECTION INPUT ;
    USE SIGNAL ;
    PORT
      LAYER M3 ;
        RECT 60.480 0.000 60.498 0.038 ;
    END
  END w_d[588]
  PIN w_d[589]
    DIRECTION INPUT ;
    USE SIGNAL ;
    PORT
      LAYER M3 ;
        RECT 60.624 0.000 60.642 0.038 ;
    END
  END w_d[589]
  PIN w_d[58]
    DIRECTION INPUT ;
    USE SIGNAL ;
    PORT
      LAYER M4 ;
        RECT 0.000 13.104 0.192 13.128 ;
    END
  END w_d[58]
  PIN w_d[590]
    DIRECTION INPUT ;
    USE SIGNAL ;
    PORT
      LAYER M3 ;
        RECT 60.768 0.000 60.786 0.038 ;
    END
  END w_d[590]
  PIN w_d[591]
    DIRECTION INPUT ;
    USE SIGNAL ;
    PORT
      LAYER M3 ;
        RECT 60.912 0.000 60.930 0.038 ;
    END
  END w_d[591]
  PIN w_d[592]
    DIRECTION INPUT ;
    USE SIGNAL ;
    PORT
      LAYER M5 ;
        RECT 61.056 0.000 61.080 0.084 ;
    END
  END w_d[592]
  PIN w_d[593]
    DIRECTION INPUT ;
    USE SIGNAL ;
    PORT
      LAYER M3 ;
        RECT 61.200 0.000 61.218 0.038 ;
    END
  END w_d[593]
  PIN w_d[594]
    DIRECTION INPUT ;
    USE SIGNAL ;
    PORT
      LAYER M5 ;
        RECT 61.344 0.000 61.368 0.084 ;
    END
  END w_d[594]
  PIN w_d[595]
    DIRECTION INPUT ;
    USE SIGNAL ;
    PORT
      LAYER M5 ;
        RECT 61.536 0.000 61.560 0.084 ;
    END
  END w_d[595]
  PIN w_d[596]
    DIRECTION INPUT ;
    USE SIGNAL ;
    PORT
      LAYER M5 ;
        RECT 61.632 0.000 61.656 0.084 ;
    END
  END w_d[596]
  PIN w_d[597]
    DIRECTION INPUT ;
    USE SIGNAL ;
    PORT
      LAYER M3 ;
        RECT 61.848 0.000 61.866 0.038 ;
    END
  END w_d[597]
  PIN w_d[598]
    DIRECTION INPUT ;
    USE SIGNAL ;
    PORT
      LAYER M3 ;
        RECT 62.064 0.000 62.082 0.038 ;
    END
  END w_d[598]
  PIN w_d[599]
    DIRECTION INPUT ;
    USE SIGNAL ;
    PORT
      LAYER M3 ;
        RECT 62.280 0.000 62.298 0.038 ;
    END
  END w_d[599]
  PIN w_d[59]
    DIRECTION INPUT ;
    USE SIGNAL ;
    PORT
      LAYER M4 ;
        RECT 129.408 10.368 129.600 10.392 ;
    END
  END w_d[59]
  PIN w_d[5]
    DIRECTION INPUT ;
    USE SIGNAL ;
    PORT
      LAYER M4 ;
        RECT 129.408 6.144 129.600 6.168 ;
    END
  END w_d[5]
  PIN w_d[600]
    DIRECTION INPUT ;
    USE SIGNAL ;
    PORT
      LAYER M3 ;
        RECT 62.424 0.000 62.442 0.038 ;
    END
  END w_d[600]
  PIN w_d[601]
    DIRECTION INPUT ;
    USE SIGNAL ;
    PORT
      LAYER M3 ;
        RECT 62.568 0.000 62.586 0.038 ;
    END
  END w_d[601]
  PIN w_d[602]
    DIRECTION INPUT ;
    USE SIGNAL ;
    PORT
      LAYER M3 ;
        RECT 62.712 0.000 62.730 0.038 ;
    END
  END w_d[602]
  PIN w_d[603]
    DIRECTION INPUT ;
    USE SIGNAL ;
    PORT
      LAYER M5 ;
        RECT 62.880 0.000 62.904 0.084 ;
    END
  END w_d[603]
  PIN w_d[604]
    DIRECTION INPUT ;
    USE SIGNAL ;
    PORT
      LAYER M3 ;
        RECT 63.000 0.000 63.018 0.038 ;
    END
  END w_d[604]
  PIN w_d[605]
    DIRECTION INPUT ;
    USE SIGNAL ;
    PORT
      LAYER M5 ;
        RECT 63.168 0.000 63.192 0.084 ;
    END
  END w_d[605]
  PIN w_d[606]
    DIRECTION INPUT ;
    USE SIGNAL ;
    PORT
      LAYER M3 ;
        RECT 63.360 0.000 63.378 0.038 ;
    END
  END w_d[606]
  PIN w_d[607]
    DIRECTION INPUT ;
    USE SIGNAL ;
    PORT
      LAYER M5 ;
        RECT 63.456 0.000 63.480 0.084 ;
    END
  END w_d[607]
  PIN w_d[608]
    DIRECTION INPUT ;
    USE SIGNAL ;
    PORT
      LAYER M3 ;
        RECT 63.648 0.000 63.666 0.038 ;
    END
  END w_d[608]
  PIN w_d[609]
    DIRECTION INPUT ;
    USE SIGNAL ;
    PORT
      LAYER M5 ;
        RECT 63.744 0.000 63.768 0.084 ;
    END
  END w_d[609]
  PIN w_d[60]
    DIRECTION INPUT ;
    USE SIGNAL ;
    PORT
      LAYER M4 ;
        RECT 0.000 13.296 0.192 13.320 ;
    END
  END w_d[60]
  PIN w_d[610]
    DIRECTION INPUT ;
    USE SIGNAL ;
    PORT
      LAYER M3 ;
        RECT 63.936 0.000 63.954 0.038 ;
    END
  END w_d[610]
  PIN w_d[611]
    DIRECTION INPUT ;
    USE SIGNAL ;
    PORT
      LAYER M3 ;
        RECT 64.080 0.000 64.098 0.038 ;
    END
  END w_d[611]
  PIN w_d[612]
    DIRECTION INPUT ;
    USE SIGNAL ;
    PORT
      LAYER M3 ;
        RECT 65.376 0.000 65.394 0.038 ;
    END
  END w_d[612]
  PIN w_d[613]
    DIRECTION INPUT ;
    USE SIGNAL ;
    PORT
      LAYER M3 ;
        RECT 65.520 0.000 65.538 0.038 ;
    END
  END w_d[613]
  PIN w_d[614]
    DIRECTION INPUT ;
    USE SIGNAL ;
    PORT
      LAYER M5 ;
        RECT 65.664 0.000 65.688 0.084 ;
    END
  END w_d[614]
  PIN w_d[615]
    DIRECTION INPUT ;
    USE SIGNAL ;
    PORT
      LAYER M3 ;
        RECT 65.808 0.000 65.826 0.038 ;
    END
  END w_d[615]
  PIN w_d[616]
    DIRECTION INPUT ;
    USE SIGNAL ;
    PORT
      LAYER M5 ;
        RECT 65.952 0.000 65.976 0.084 ;
    END
  END w_d[616]
  PIN w_d[617]
    DIRECTION INPUT ;
    USE SIGNAL ;
    PORT
      LAYER M5 ;
        RECT 66.144 0.000 66.168 0.084 ;
    END
  END w_d[617]
  PIN w_d[618]
    DIRECTION INPUT ;
    USE SIGNAL ;
    PORT
      LAYER M5 ;
        RECT 66.240 0.000 66.264 0.084 ;
    END
  END w_d[618]
  PIN w_d[619]
    DIRECTION INPUT ;
    USE SIGNAL ;
    PORT
      LAYER M5 ;
        RECT 66.432 0.000 66.456 0.084 ;
    END
  END w_d[619]
  PIN w_d[61]
    DIRECTION INPUT ;
    USE SIGNAL ;
    PORT
      LAYER M4 ;
        RECT 129.408 10.512 129.600 10.536 ;
    END
  END w_d[61]
  PIN w_d[620]
    DIRECTION INPUT ;
    USE SIGNAL ;
    PORT
      LAYER M3 ;
        RECT 66.600 0.000 66.618 0.038 ;
    END
  END w_d[620]
  PIN w_d[621]
    DIRECTION INPUT ;
    USE SIGNAL ;
    PORT
      LAYER M5 ;
        RECT 66.720 0.000 66.744 0.084 ;
    END
  END w_d[621]
  PIN w_d[622]
    DIRECTION INPUT ;
    USE SIGNAL ;
    PORT
      LAYER M3 ;
        RECT 66.888 0.000 66.906 0.038 ;
    END
  END w_d[622]
  PIN w_d[623]
    DIRECTION INPUT ;
    USE SIGNAL ;
    PORT
      LAYER M5 ;
        RECT 67.008 0.000 67.032 0.084 ;
    END
  END w_d[623]
  PIN w_d[624]
    DIRECTION INPUT ;
    USE SIGNAL ;
    PORT
      LAYER M3 ;
        RECT 67.176 0.000 67.194 0.038 ;
    END
  END w_d[624]
  PIN w_d[625]
    DIRECTION INPUT ;
    USE SIGNAL ;
    PORT
      LAYER M3 ;
        RECT 67.392 0.000 67.410 0.038 ;
    END
  END w_d[625]
  PIN w_d[626]
    DIRECTION INPUT ;
    USE SIGNAL ;
    PORT
      LAYER M3 ;
        RECT 67.608 0.000 67.626 0.038 ;
    END
  END w_d[626]
  PIN w_d[627]
    DIRECTION INPUT ;
    USE SIGNAL ;
    PORT
      LAYER M5 ;
        RECT 67.776 0.000 67.800 0.084 ;
    END
  END w_d[627]
  PIN w_d[628]
    DIRECTION INPUT ;
    USE SIGNAL ;
    PORT
      LAYER M3 ;
        RECT 67.968 0.000 67.986 0.038 ;
    END
  END w_d[628]
  PIN w_d[629]
    DIRECTION INPUT ;
    USE SIGNAL ;
    PORT
      LAYER M5 ;
        RECT 68.064 0.000 68.088 0.084 ;
    END
  END w_d[629]
  PIN w_d[62]
    DIRECTION INPUT ;
    USE SIGNAL ;
    PORT
      LAYER M4 ;
        RECT 0.000 13.488 0.192 13.512 ;
    END
  END w_d[62]
  PIN w_d[630]
    DIRECTION INPUT ;
    USE SIGNAL ;
    PORT
      LAYER M3 ;
        RECT 68.256 0.000 68.274 0.038 ;
    END
  END w_d[630]
  PIN w_d[631]
    DIRECTION INPUT ;
    USE SIGNAL ;
    PORT
      LAYER M3 ;
        RECT 68.400 0.000 68.418 0.038 ;
    END
  END w_d[631]
  PIN w_d[632]
    DIRECTION INPUT ;
    USE SIGNAL ;
    PORT
      LAYER M3 ;
        RECT 68.544 0.000 68.562 0.038 ;
    END
  END w_d[632]
  PIN w_d[633]
    DIRECTION INPUT ;
    USE SIGNAL ;
    PORT
      LAYER M3 ;
        RECT 68.688 0.000 68.706 0.038 ;
    END
  END w_d[633]
  PIN w_d[634]
    DIRECTION INPUT ;
    USE SIGNAL ;
    PORT
      LAYER M3 ;
        RECT 68.832 0.000 68.850 0.038 ;
    END
  END w_d[634]
  PIN w_d[635]
    DIRECTION INPUT ;
    USE SIGNAL ;
    PORT
      LAYER M3 ;
        RECT 68.976 0.000 68.994 0.038 ;
    END
  END w_d[635]
  PIN w_d[636]
    DIRECTION INPUT ;
    USE SIGNAL ;
    PORT
      LAYER M5 ;
        RECT 69.120 0.000 69.144 0.084 ;
    END
  END w_d[636]
  PIN w_d[637]
    DIRECTION INPUT ;
    USE SIGNAL ;
    PORT
      LAYER M3 ;
        RECT 69.264 0.000 69.282 0.038 ;
    END
  END w_d[637]
  PIN w_d[638]
    DIRECTION INPUT ;
    USE SIGNAL ;
    PORT
      LAYER M5 ;
        RECT 69.408 0.000 69.432 0.084 ;
    END
  END w_d[638]
  PIN w_d[639]
    DIRECTION INPUT ;
    USE SIGNAL ;
    PORT
      LAYER M5 ;
        RECT 69.600 0.000 69.624 0.084 ;
    END
  END w_d[639]
  PIN w_d[63]
    DIRECTION INPUT ;
    USE SIGNAL ;
    PORT
      LAYER M4 ;
        RECT 129.408 10.608 129.600 10.632 ;
    END
  END w_d[63]
  PIN w_d[640]
    DIRECTION INPUT ;
    USE SIGNAL ;
    PORT
      LAYER M5 ;
        RECT 69.696 0.000 69.720 0.084 ;
    END
  END w_d[640]
  PIN w_d[641]
    DIRECTION INPUT ;
    USE SIGNAL ;
    PORT
      LAYER M5 ;
        RECT 69.888 0.000 69.912 0.084 ;
    END
  END w_d[641]
  PIN w_d[642]
    DIRECTION INPUT ;
    USE SIGNAL ;
    PORT
      LAYER M3 ;
        RECT 70.056 0.000 70.074 0.038 ;
    END
  END w_d[642]
  PIN w_d[643]
    DIRECTION INPUT ;
    USE SIGNAL ;
    PORT
      LAYER M5 ;
        RECT 70.176 0.000 70.200 0.084 ;
    END
  END w_d[643]
  PIN w_d[644]
    DIRECTION INPUT ;
    USE SIGNAL ;
    PORT
      LAYER M3 ;
        RECT 70.344 0.000 70.362 0.038 ;
    END
  END w_d[644]
  PIN w_d[645]
    DIRECTION INPUT ;
    USE SIGNAL ;
    PORT
      LAYER M5 ;
        RECT 70.464 0.000 70.488 0.084 ;
    END
  END w_d[645]
  PIN w_d[646]
    DIRECTION INPUT ;
    USE SIGNAL ;
    PORT
      LAYER M3 ;
        RECT 70.632 0.000 70.650 0.038 ;
    END
  END w_d[646]
  PIN w_d[647]
    DIRECTION INPUT ;
    USE SIGNAL ;
    PORT
      LAYER M3 ;
        RECT 70.776 0.000 70.794 0.038 ;
    END
  END w_d[647]
  PIN w_d[648]
    DIRECTION INPUT ;
    USE SIGNAL ;
    PORT
      LAYER M3 ;
        RECT 70.920 0.000 70.938 0.038 ;
    END
  END w_d[648]
  PIN w_d[649]
    DIRECTION INPUT ;
    USE SIGNAL ;
    PORT
      LAYER M3 ;
        RECT 71.064 0.000 71.082 0.038 ;
    END
  END w_d[649]
  PIN w_d[64]
    DIRECTION INPUT ;
    USE SIGNAL ;
    PORT
      LAYER M4 ;
        RECT 0.000 13.680 0.192 13.704 ;
    END
  END w_d[64]
  PIN w_d[650]
    DIRECTION INPUT ;
    USE SIGNAL ;
    PORT
      LAYER M5 ;
        RECT 71.232 0.000 71.256 0.084 ;
    END
  END w_d[650]
  PIN w_d[651]
    DIRECTION INPUT ;
    USE SIGNAL ;
    PORT
      LAYER M3 ;
        RECT 71.352 0.000 71.370 0.038 ;
    END
  END w_d[651]
  PIN w_d[652]
    DIRECTION INPUT ;
    USE SIGNAL ;
    PORT
      LAYER M5 ;
        RECT 71.520 0.000 71.544 0.084 ;
    END
  END w_d[652]
  PIN w_d[653]
    DIRECTION INPUT ;
    USE SIGNAL ;
    PORT
      LAYER M3 ;
        RECT 71.712 0.000 71.730 0.038 ;
    END
  END w_d[653]
  PIN w_d[654]
    DIRECTION INPUT ;
    USE SIGNAL ;
    PORT
      LAYER M5 ;
        RECT 71.808 0.000 71.832 0.084 ;
    END
  END w_d[654]
  PIN w_d[655]
    DIRECTION INPUT ;
    USE SIGNAL ;
    PORT
      LAYER M3 ;
        RECT 72.000 0.000 72.018 0.038 ;
    END
  END w_d[655]
  PIN w_d[656]
    DIRECTION INPUT ;
    USE SIGNAL ;
    PORT
      LAYER M5 ;
        RECT 72.096 0.000 72.120 0.084 ;
    END
  END w_d[656]
  PIN w_d[657]
    DIRECTION INPUT ;
    USE SIGNAL ;
    PORT
      LAYER M3 ;
        RECT 72.288 0.000 72.306 0.038 ;
    END
  END w_d[657]
  PIN w_d[658]
    DIRECTION INPUT ;
    USE SIGNAL ;
    PORT
      LAYER M3 ;
        RECT 72.432 0.000 72.450 0.038 ;
    END
  END w_d[658]
  PIN w_d[659]
    DIRECTION INPUT ;
    USE SIGNAL ;
    PORT
      LAYER M3 ;
        RECT 72.576 0.000 72.594 0.038 ;
    END
  END w_d[659]
  PIN w_d[65]
    DIRECTION INPUT ;
    USE SIGNAL ;
    PORT
      LAYER M4 ;
        RECT 129.408 10.800 129.600 10.824 ;
    END
  END w_d[65]
  PIN w_d[660]
    DIRECTION INPUT ;
    USE SIGNAL ;
    PORT
      LAYER M3 ;
        RECT 72.792 0.000 72.810 0.038 ;
    END
  END w_d[660]
  PIN w_d[661]
    DIRECTION INPUT ;
    USE SIGNAL ;
    PORT
      LAYER M5 ;
        RECT 73.056 0.000 73.080 0.084 ;
    END
  END w_d[661]
  PIN w_d[662]
    DIRECTION INPUT ;
    USE SIGNAL ;
    PORT
      LAYER M5 ;
        RECT 73.152 0.000 73.176 0.084 ;
    END
  END w_d[662]
  PIN w_d[663]
    DIRECTION INPUT ;
    USE SIGNAL ;
    PORT
      LAYER M5 ;
        RECT 73.344 0.000 73.368 0.084 ;
    END
  END w_d[663]
  PIN w_d[664]
    DIRECTION INPUT ;
    USE SIGNAL ;
    PORT
      LAYER M3 ;
        RECT 73.512 0.000 73.530 0.038 ;
    END
  END w_d[664]
  PIN w_d[665]
    DIRECTION INPUT ;
    USE SIGNAL ;
    PORT
      LAYER M5 ;
        RECT 73.632 0.000 73.656 0.084 ;
    END
  END w_d[665]
  PIN w_d[666]
    DIRECTION INPUT ;
    USE SIGNAL ;
    PORT
      LAYER M3 ;
        RECT 73.800 0.000 73.818 0.038 ;
    END
  END w_d[666]
  PIN w_d[667]
    DIRECTION INPUT ;
    USE SIGNAL ;
    PORT
      LAYER M3 ;
        RECT 73.944 0.000 73.962 0.038 ;
    END
  END w_d[667]
  PIN w_d[668]
    DIRECTION INPUT ;
    USE SIGNAL ;
    PORT
      LAYER M3 ;
        RECT 74.088 0.000 74.106 0.038 ;
    END
  END w_d[668]
  PIN w_d[669]
    DIRECTION INPUT ;
    USE SIGNAL ;
    PORT
      LAYER M3 ;
        RECT 74.232 0.000 74.250 0.038 ;
    END
  END w_d[669]
  PIN w_d[66]
    DIRECTION INPUT ;
    USE SIGNAL ;
    PORT
      LAYER M4 ;
        RECT 0.000 13.872 0.192 13.896 ;
    END
  END w_d[66]
  PIN w_d[670]
    DIRECTION INPUT ;
    USE SIGNAL ;
    PORT
      LAYER M3 ;
        RECT 74.376 0.000 74.394 0.038 ;
    END
  END w_d[670]
  PIN w_d[671]
    DIRECTION INPUT ;
    USE SIGNAL ;
    PORT
      LAYER M3 ;
        RECT 74.520 0.000 74.538 0.038 ;
    END
  END w_d[671]
  PIN w_d[672]
    DIRECTION INPUT ;
    USE SIGNAL ;
    PORT
      LAYER M5 ;
        RECT 74.688 0.000 74.712 0.084 ;
    END
  END w_d[672]
  PIN w_d[673]
    DIRECTION INPUT ;
    USE SIGNAL ;
    PORT
      LAYER M3 ;
        RECT 74.808 0.000 74.826 0.038 ;
    END
  END w_d[673]
  PIN w_d[674]
    DIRECTION INPUT ;
    USE SIGNAL ;
    PORT
      LAYER M5 ;
        RECT 74.976 0.000 75.000 0.084 ;
    END
  END w_d[674]
  PIN w_d[675]
    DIRECTION INPUT ;
    USE SIGNAL ;
    PORT
      LAYER M3 ;
        RECT 75.168 0.000 75.186 0.038 ;
    END
  END w_d[675]
  PIN w_d[676]
    DIRECTION INPUT ;
    USE SIGNAL ;
    PORT
      LAYER M5 ;
        RECT 75.264 0.000 75.288 0.084 ;
    END
  END w_d[676]
  PIN w_d[677]
    DIRECTION INPUT ;
    USE SIGNAL ;
    PORT
      LAYER M3 ;
        RECT 75.456 0.000 75.474 0.038 ;
    END
  END w_d[677]
  PIN w_d[678]
    DIRECTION INPUT ;
    USE SIGNAL ;
    PORT
      LAYER M3 ;
        RECT 75.600 0.000 75.618 0.038 ;
    END
  END w_d[678]
  PIN w_d[679]
    DIRECTION INPUT ;
    USE SIGNAL ;
    PORT
      LAYER M3 ;
        RECT 75.744 0.000 75.762 0.038 ;
    END
  END w_d[679]
  PIN w_d[67]
    DIRECTION INPUT ;
    USE SIGNAL ;
    PORT
      LAYER M4 ;
        RECT 129.408 10.944 129.600 10.968 ;
    END
  END w_d[67]
  PIN w_d[680]
    DIRECTION INPUT ;
    USE SIGNAL ;
    PORT
      LAYER M3 ;
        RECT 75.888 0.000 75.906 0.038 ;
    END
  END w_d[680]
  PIN w_d[681]
    DIRECTION INPUT ;
    USE SIGNAL ;
    PORT
      LAYER M3 ;
        RECT 76.032 0.000 76.050 0.038 ;
    END
  END w_d[681]
  PIN w_d[682]
    DIRECTION INPUT ;
    USE SIGNAL ;
    PORT
      LAYER M3 ;
        RECT 76.176 0.000 76.194 0.038 ;
    END
  END w_d[682]
  PIN w_d[683]
    DIRECTION INPUT ;
    USE SIGNAL ;
    PORT
      LAYER M5 ;
        RECT 76.320 0.000 76.344 0.084 ;
    END
  END w_d[683]
  PIN w_d[684]
    DIRECTION INPUT ;
    USE SIGNAL ;
    PORT
      LAYER M3 ;
        RECT 76.464 0.000 76.482 0.038 ;
    END
  END w_d[684]
  PIN w_d[685]
    DIRECTION INPUT ;
    USE SIGNAL ;
    PORT
      LAYER M5 ;
        RECT 76.608 0.000 76.632 0.084 ;
    END
  END w_d[685]
  PIN w_d[686]
    DIRECTION INPUT ;
    USE SIGNAL ;
    PORT
      LAYER M5 ;
        RECT 76.800 0.000 76.824 0.084 ;
    END
  END w_d[686]
  PIN w_d[687]
    DIRECTION INPUT ;
    USE SIGNAL ;
    PORT
      LAYER M5 ;
        RECT 76.896 0.000 76.920 0.084 ;
    END
  END w_d[687]
  PIN w_d[688]
    DIRECTION INPUT ;
    USE SIGNAL ;
    PORT
      LAYER M5 ;
        RECT 77.088 0.000 77.112 0.084 ;
    END
  END w_d[688]
  PIN w_d[689]
    DIRECTION INPUT ;
    USE SIGNAL ;
    PORT
      LAYER M3 ;
        RECT 77.256 0.000 77.274 0.038 ;
    END
  END w_d[689]
  PIN w_d[68]
    DIRECTION INPUT ;
    USE SIGNAL ;
    PORT
      LAYER M4 ;
        RECT 0.000 14.064 0.192 14.088 ;
    END
  END w_d[68]
  PIN w_d[690]
    DIRECTION INPUT ;
    USE SIGNAL ;
    PORT
      LAYER M5 ;
        RECT 77.376 0.000 77.400 0.084 ;
    END
  END w_d[690]
  PIN w_d[691]
    DIRECTION INPUT ;
    USE SIGNAL ;
    PORT
      LAYER M3 ;
        RECT 77.544 0.000 77.562 0.038 ;
    END
  END w_d[691]
  PIN w_d[692]
    DIRECTION INPUT ;
    USE SIGNAL ;
    PORT
      LAYER M5 ;
        RECT 77.664 0.000 77.688 0.084 ;
    END
  END w_d[692]
  PIN w_d[693]
    DIRECTION INPUT ;
    USE SIGNAL ;
    PORT
      LAYER M3 ;
        RECT 77.832 0.000 77.850 0.038 ;
    END
  END w_d[693]
  PIN w_d[694]
    DIRECTION INPUT ;
    USE SIGNAL ;
    PORT
      LAYER M3 ;
        RECT 77.976 0.000 77.994 0.038 ;
    END
  END w_d[694]
  PIN w_d[695]
    DIRECTION INPUT ;
    USE SIGNAL ;
    PORT
      LAYER M3 ;
        RECT 78.192 0.000 78.210 0.038 ;
    END
  END w_d[695]
  PIN w_d[696]
    DIRECTION INPUT ;
    USE SIGNAL ;
    PORT
      LAYER M5 ;
        RECT 78.432 0.000 78.456 0.084 ;
    END
  END w_d[696]
  PIN w_d[697]
    DIRECTION INPUT ;
    USE SIGNAL ;
    PORT
      LAYER M3 ;
        RECT 78.624 0.000 78.642 0.038 ;
    END
  END w_d[697]
  PIN w_d[698]
    DIRECTION INPUT ;
    USE SIGNAL ;
    PORT
      LAYER M5 ;
        RECT 78.720 0.000 78.744 0.084 ;
    END
  END w_d[698]
  PIN w_d[699]
    DIRECTION INPUT ;
    USE SIGNAL ;
    PORT
      LAYER M3 ;
        RECT 78.912 0.000 78.930 0.038 ;
    END
  END w_d[699]
  PIN w_d[69]
    DIRECTION INPUT ;
    USE SIGNAL ;
    PORT
      LAYER M4 ;
        RECT 129.408 11.136 129.600 11.160 ;
    END
  END w_d[69]
  PIN w_d[6]
    DIRECTION INPUT ;
    USE SIGNAL ;
    PORT
      LAYER M4 ;
        RECT 0.000 7.920 0.192 7.944 ;
    END
  END w_d[6]
  PIN w_d[700]
    DIRECTION INPUT ;
    USE SIGNAL ;
    PORT
      LAYER M3 ;
        RECT 79.056 0.000 79.074 0.038 ;
    END
  END w_d[700]
  PIN w_d[701]
    DIRECTION INPUT ;
    USE SIGNAL ;
    PORT
      LAYER M3 ;
        RECT 79.200 0.000 79.218 0.038 ;
    END
  END w_d[701]
  PIN w_d[702]
    DIRECTION INPUT ;
    USE SIGNAL ;
    PORT
      LAYER M3 ;
        RECT 79.344 0.000 79.362 0.038 ;
    END
  END w_d[702]
  PIN w_d[703]
    DIRECTION INPUT ;
    USE SIGNAL ;
    PORT
      LAYER M3 ;
        RECT 79.488 0.000 79.506 0.038 ;
    END
  END w_d[703]
  PIN w_d[704]
    DIRECTION INPUT ;
    USE SIGNAL ;
    PORT
      LAYER M3 ;
        RECT 79.632 0.000 79.650 0.038 ;
    END
  END w_d[704]
  PIN w_d[705]
    DIRECTION INPUT ;
    USE SIGNAL ;
    PORT
      LAYER M5 ;
        RECT 79.776 0.000 79.800 0.084 ;
    END
  END w_d[705]
  PIN w_d[706]
    DIRECTION INPUT ;
    USE SIGNAL ;
    PORT
      LAYER M3 ;
        RECT 79.920 0.000 79.938 0.038 ;
    END
  END w_d[706]
  PIN w_d[707]
    DIRECTION INPUT ;
    USE SIGNAL ;
    PORT
      LAYER M5 ;
        RECT 80.064 0.000 80.088 0.084 ;
    END
  END w_d[707]
  PIN w_d[708]
    DIRECTION INPUT ;
    USE SIGNAL ;
    PORT
      LAYER M5 ;
        RECT 80.256 0.000 80.280 0.084 ;
    END
  END w_d[708]
  PIN w_d[709]
    DIRECTION INPUT ;
    USE SIGNAL ;
    PORT
      LAYER M5 ;
        RECT 80.352 0.000 80.376 0.084 ;
    END
  END w_d[709]
  PIN w_d[70]
    DIRECTION INPUT ;
    USE SIGNAL ;
    PORT
      LAYER M4 ;
        RECT 0.000 14.256 0.192 14.280 ;
    END
  END w_d[70]
  PIN w_d[710]
    DIRECTION INPUT ;
    USE SIGNAL ;
    PORT
      LAYER M5 ;
        RECT 80.544 0.000 80.568 0.084 ;
    END
  END w_d[710]
  PIN w_d[711]
    DIRECTION INPUT ;
    USE SIGNAL ;
    PORT
      LAYER M3 ;
        RECT 80.712 0.000 80.730 0.038 ;
    END
  END w_d[711]
  PIN w_d[712]
    DIRECTION INPUT ;
    USE SIGNAL ;
    PORT
      LAYER M5 ;
        RECT 80.832 0.000 80.856 0.084 ;
    END
  END w_d[712]
  PIN w_d[713]
    DIRECTION INPUT ;
    USE SIGNAL ;
    PORT
      LAYER M3 ;
        RECT 81.000 0.000 81.018 0.038 ;
    END
  END w_d[713]
  PIN w_d[714]
    DIRECTION INPUT ;
    USE SIGNAL ;
    PORT
      LAYER M3 ;
        RECT 81.144 0.000 81.162 0.038 ;
    END
  END w_d[714]
  PIN w_d[715]
    DIRECTION INPUT ;
    USE SIGNAL ;
    PORT
      LAYER M3 ;
        RECT 81.288 0.000 81.306 0.038 ;
    END
  END w_d[715]
  PIN w_d[716]
    DIRECTION INPUT ;
    USE SIGNAL ;
    PORT
      LAYER M3 ;
        RECT 81.432 0.000 81.450 0.038 ;
    END
  END w_d[716]
  PIN w_d[717]
    DIRECTION INPUT ;
    USE SIGNAL ;
    PORT
      LAYER M3 ;
        RECT 81.576 0.000 81.594 0.038 ;
    END
  END w_d[717]
  PIN w_d[718]
    DIRECTION INPUT ;
    USE SIGNAL ;
    PORT
      LAYER M3 ;
        RECT 81.720 0.000 81.738 0.038 ;
    END
  END w_d[718]
  PIN w_d[719]
    DIRECTION INPUT ;
    USE SIGNAL ;
    PORT
      LAYER M5 ;
        RECT 81.888 0.000 81.912 0.084 ;
    END
  END w_d[719]
  PIN w_d[71]
    DIRECTION INPUT ;
    USE SIGNAL ;
    PORT
      LAYER M4 ;
        RECT 129.408 11.280 129.600 11.304 ;
    END
  END w_d[71]
  PIN w_d[720]
    DIRECTION INPUT ;
    USE SIGNAL ;
    PORT
      LAYER M3 ;
        RECT 82.008 0.000 82.026 0.038 ;
    END
  END w_d[720]
  PIN w_d[721]
    DIRECTION INPUT ;
    USE SIGNAL ;
    PORT
      LAYER M5 ;
        RECT 82.176 0.000 82.200 0.084 ;
    END
  END w_d[721]
  PIN w_d[722]
    DIRECTION INPUT ;
    USE SIGNAL ;
    PORT
      LAYER M3 ;
        RECT 82.368 0.000 82.386 0.038 ;
    END
  END w_d[722]
  PIN w_d[723]
    DIRECTION INPUT ;
    USE SIGNAL ;
    PORT
      LAYER M5 ;
        RECT 82.464 0.000 82.488 0.084 ;
    END
  END w_d[723]
  PIN w_d[724]
    DIRECTION INPUT ;
    USE SIGNAL ;
    PORT
      LAYER M3 ;
        RECT 82.656 0.000 82.674 0.038 ;
    END
  END w_d[724]
  PIN w_d[725]
    DIRECTION INPUT ;
    USE SIGNAL ;
    PORT
      LAYER M3 ;
        RECT 82.800 0.000 82.818 0.038 ;
    END
  END w_d[725]
  PIN w_d[726]
    DIRECTION INPUT ;
    USE SIGNAL ;
    PORT
      LAYER M3 ;
        RECT 82.944 0.000 82.962 0.038 ;
    END
  END w_d[726]
  PIN w_d[727]
    DIRECTION INPUT ;
    USE SIGNAL ;
    PORT
      LAYER M3 ;
        RECT 83.088 0.000 83.106 0.038 ;
    END
  END w_d[727]
  PIN w_d[728]
    DIRECTION INPUT ;
    USE SIGNAL ;
    PORT
      LAYER M3 ;
        RECT 83.232 0.000 83.250 0.038 ;
    END
  END w_d[728]
  PIN w_d[729]
    DIRECTION INPUT ;
    USE SIGNAL ;
    PORT
      LAYER M3 ;
        RECT 83.376 0.000 83.394 0.038 ;
    END
  END w_d[729]
  PIN w_d[72]
    DIRECTION INPUT ;
    USE SIGNAL ;
    PORT
      LAYER M4 ;
        RECT 0.000 14.448 0.192 14.472 ;
    END
  END w_d[72]
  PIN w_d[730]
    DIRECTION INPUT ;
    USE SIGNAL ;
    PORT
      LAYER M3 ;
        RECT 83.664 0.000 83.682 0.038 ;
    END
  END w_d[730]
  PIN w_d[731]
    DIRECTION INPUT ;
    USE SIGNAL ;
    PORT
      LAYER M5 ;
        RECT 83.808 0.000 83.832 0.084 ;
    END
  END w_d[731]
  PIN w_d[732]
    DIRECTION INPUT ;
    USE SIGNAL ;
    PORT
      LAYER M5 ;
        RECT 84.000 0.000 84.024 0.084 ;
    END
  END w_d[732]
  PIN w_d[733]
    DIRECTION INPUT ;
    USE SIGNAL ;
    PORT
      LAYER M3 ;
        RECT 84.168 0.000 84.186 0.038 ;
    END
  END w_d[733]
  PIN w_d[734]
    DIRECTION INPUT ;
    USE SIGNAL ;
    PORT
      LAYER M5 ;
        RECT 84.288 0.000 84.312 0.084 ;
    END
  END w_d[734]
  PIN w_d[735]
    DIRECTION INPUT ;
    USE SIGNAL ;
    PORT
      LAYER M3 ;
        RECT 84.456 0.000 84.474 0.038 ;
    END
  END w_d[735]
  PIN w_d[736]
    DIRECTION INPUT ;
    USE SIGNAL ;
    PORT
      LAYER M3 ;
        RECT 84.600 0.000 84.618 0.038 ;
    END
  END w_d[736]
  PIN w_d[737]
    DIRECTION INPUT ;
    USE SIGNAL ;
    PORT
      LAYER M3 ;
        RECT 84.744 0.000 84.762 0.038 ;
    END
  END w_d[737]
  PIN w_d[738]
    DIRECTION INPUT ;
    USE SIGNAL ;
    PORT
      LAYER M3 ;
        RECT 84.888 0.000 84.906 0.038 ;
    END
  END w_d[738]
  PIN w_d[739]
    DIRECTION INPUT ;
    USE SIGNAL ;
    PORT
      LAYER M3 ;
        RECT 85.032 0.000 85.050 0.038 ;
    END
  END w_d[739]
  PIN w_d[73]
    DIRECTION INPUT ;
    USE SIGNAL ;
    PORT
      LAYER M4 ;
        RECT 129.408 11.376 129.600 11.400 ;
    END
  END w_d[73]
  PIN w_d[740]
    DIRECTION INPUT ;
    USE SIGNAL ;
    PORT
      LAYER M3 ;
        RECT 85.176 0.000 85.194 0.038 ;
    END
  END w_d[740]
  PIN w_d[741]
    DIRECTION INPUT ;
    USE SIGNAL ;
    PORT
      LAYER M5 ;
        RECT 85.344 0.000 85.368 0.084 ;
    END
  END w_d[741]
  PIN w_d[742]
    DIRECTION INPUT ;
    USE SIGNAL ;
    PORT
      LAYER M3 ;
        RECT 85.464 0.000 85.482 0.038 ;
    END
  END w_d[742]
  PIN w_d[743]
    DIRECTION INPUT ;
    USE SIGNAL ;
    PORT
      LAYER M5 ;
        RECT 85.632 0.000 85.656 0.084 ;
    END
  END w_d[743]
  PIN w_d[744]
    DIRECTION INPUT ;
    USE SIGNAL ;
    PORT
      LAYER M3 ;
        RECT 85.824 0.000 85.842 0.038 ;
    END
  END w_d[744]
  PIN w_d[745]
    DIRECTION INPUT ;
    USE SIGNAL ;
    PORT
      LAYER M5 ;
        RECT 85.920 0.000 85.944 0.084 ;
    END
  END w_d[745]
  PIN w_d[746]
    DIRECTION INPUT ;
    USE SIGNAL ;
    PORT
      LAYER M3 ;
        RECT 86.112 0.000 86.130 0.038 ;
    END
  END w_d[746]
  PIN w_d[747]
    DIRECTION INPUT ;
    USE SIGNAL ;
    PORT
      LAYER M3 ;
        RECT 86.256 0.000 86.274 0.038 ;
    END
  END w_d[747]
  PIN w_d[748]
    DIRECTION INPUT ;
    USE SIGNAL ;
    PORT
      LAYER M3 ;
        RECT 86.400 0.000 86.418 0.038 ;
    END
  END w_d[748]
  PIN w_d[749]
    DIRECTION INPUT ;
    USE SIGNAL ;
    PORT
      LAYER M3 ;
        RECT 86.544 0.000 86.562 0.038 ;
    END
  END w_d[749]
  PIN w_d[74]
    DIRECTION INPUT ;
    USE SIGNAL ;
    PORT
      LAYER M4 ;
        RECT 0.000 14.640 0.192 14.664 ;
    END
  END w_d[74]
  PIN w_d[750]
    DIRECTION INPUT ;
    USE SIGNAL ;
    PORT
      LAYER M5 ;
        RECT 86.688 0.000 86.712 0.084 ;
    END
  END w_d[750]
  PIN w_d[751]
    DIRECTION INPUT ;
    USE SIGNAL ;
    PORT
      LAYER M3 ;
        RECT 86.832 0.000 86.850 0.038 ;
    END
  END w_d[751]
  PIN w_d[752]
    DIRECTION INPUT ;
    USE SIGNAL ;
    PORT
      LAYER M5 ;
        RECT 86.976 0.000 87.000 0.084 ;
    END
  END w_d[752]
  PIN w_d[753]
    DIRECTION INPUT ;
    USE SIGNAL ;
    PORT
      LAYER M3 ;
        RECT 87.120 0.000 87.138 0.038 ;
    END
  END w_d[753]
  PIN w_d[754]
    DIRECTION INPUT ;
    USE SIGNAL ;
    PORT
      LAYER M5 ;
        RECT 87.264 0.000 87.288 0.084 ;
    END
  END w_d[754]
  PIN w_d[755]
    DIRECTION INPUT ;
    USE SIGNAL ;
    PORT
      LAYER M5 ;
        RECT 87.456 0.000 87.480 0.084 ;
    END
  END w_d[755]
  PIN w_d[756]
    DIRECTION INPUT ;
    USE SIGNAL ;
    PORT
      LAYER M5 ;
        RECT 87.552 0.000 87.576 0.084 ;
    END
  END w_d[756]
  PIN w_d[757]
    DIRECTION INPUT ;
    USE SIGNAL ;
    PORT
      LAYER M5 ;
        RECT 87.744 0.000 87.768 0.084 ;
    END
  END w_d[757]
  PIN w_d[758]
    DIRECTION INPUT ;
    USE SIGNAL ;
    PORT
      LAYER M3 ;
        RECT 87.912 0.000 87.930 0.038 ;
    END
  END w_d[758]
  PIN w_d[759]
    DIRECTION INPUT ;
    USE SIGNAL ;
    PORT
      LAYER M5 ;
        RECT 88.032 0.000 88.056 0.084 ;
    END
  END w_d[759]
  PIN w_d[75]
    DIRECTION INPUT ;
    USE SIGNAL ;
    PORT
      LAYER M4 ;
        RECT 129.408 11.568 129.600 11.592 ;
    END
  END w_d[75]
  PIN w_d[760]
    DIRECTION INPUT ;
    USE SIGNAL ;
    PORT
      LAYER M3 ;
        RECT 88.200 0.000 88.218 0.038 ;
    END
  END w_d[760]
  PIN w_d[761]
    DIRECTION INPUT ;
    USE SIGNAL ;
    PORT
      LAYER M3 ;
        RECT 88.344 0.000 88.362 0.038 ;
    END
  END w_d[761]
  PIN w_d[762]
    DIRECTION INPUT ;
    USE SIGNAL ;
    PORT
      LAYER M3 ;
        RECT 88.488 0.000 88.506 0.038 ;
    END
  END w_d[762]
  PIN w_d[763]
    DIRECTION INPUT ;
    USE SIGNAL ;
    PORT
      LAYER M3 ;
        RECT 88.632 0.000 88.650 0.038 ;
    END
  END w_d[763]
  PIN w_d[764]
    DIRECTION INPUT ;
    USE SIGNAL ;
    PORT
      LAYER M3 ;
        RECT 88.776 0.000 88.794 0.038 ;
    END
  END w_d[764]
  PIN w_d[765]
    DIRECTION INPUT ;
    USE SIGNAL ;
    PORT
      LAYER M3 ;
        RECT 88.992 0.000 89.010 0.038 ;
    END
  END w_d[765]
  PIN w_d[766]
    DIRECTION INPUT ;
    USE SIGNAL ;
    PORT
      LAYER M3 ;
        RECT 89.280 0.000 89.298 0.038 ;
    END
  END w_d[766]
  PIN w_d[767]
    DIRECTION INPUT ;
    USE SIGNAL ;
    PORT
      LAYER M5 ;
        RECT 89.376 0.000 89.400 0.084 ;
    END
  END w_d[767]
  PIN w_d[768]
    DIRECTION INPUT ;
    USE SIGNAL ;
    PORT
      LAYER M3 ;
        RECT 89.568 0.000 89.586 0.038 ;
    END
  END w_d[768]
  PIN w_d[769]
    DIRECTION INPUT ;
    USE SIGNAL ;
    PORT
      LAYER M3 ;
        RECT 89.712 0.000 89.730 0.038 ;
    END
  END w_d[769]
  PIN w_d[76]
    DIRECTION INPUT ;
    USE SIGNAL ;
    PORT
      LAYER M4 ;
        RECT 0.000 14.832 0.192 14.856 ;
    END
  END w_d[76]
  PIN w_d[770]
    DIRECTION INPUT ;
    USE SIGNAL ;
    PORT
      LAYER M3 ;
        RECT 89.856 0.000 89.874 0.038 ;
    END
  END w_d[770]
  PIN w_d[771]
    DIRECTION INPUT ;
    USE SIGNAL ;
    PORT
      LAYER M3 ;
        RECT 90.000 0.000 90.018 0.038 ;
    END
  END w_d[771]
  PIN w_d[772]
    DIRECTION INPUT ;
    USE SIGNAL ;
    PORT
      LAYER M5 ;
        RECT 90.144 0.000 90.168 0.084 ;
    END
  END w_d[772]
  PIN w_d[773]
    DIRECTION INPUT ;
    USE SIGNAL ;
    PORT
      LAYER M3 ;
        RECT 90.288 0.000 90.306 0.038 ;
    END
  END w_d[773]
  PIN w_d[774]
    DIRECTION INPUT ;
    USE SIGNAL ;
    PORT
      LAYER M5 ;
        RECT 90.432 0.000 90.456 0.084 ;
    END
  END w_d[774]
  PIN w_d[775]
    DIRECTION INPUT ;
    USE SIGNAL ;
    PORT
      LAYER M3 ;
        RECT 90.576 0.000 90.594 0.038 ;
    END
  END w_d[775]
  PIN w_d[776]
    DIRECTION INPUT ;
    USE SIGNAL ;
    PORT
      LAYER M5 ;
        RECT 90.720 0.000 90.744 0.084 ;
    END
  END w_d[776]
  PIN w_d[777]
    DIRECTION INPUT ;
    USE SIGNAL ;
    PORT
      LAYER M5 ;
        RECT 90.912 0.000 90.936 0.084 ;
    END
  END w_d[777]
  PIN w_d[778]
    DIRECTION INPUT ;
    USE SIGNAL ;
    PORT
      LAYER M5 ;
        RECT 91.008 0.000 91.032 0.084 ;
    END
  END w_d[778]
  PIN w_d[779]
    DIRECTION INPUT ;
    USE SIGNAL ;
    PORT
      LAYER M5 ;
        RECT 91.200 0.000 91.224 0.084 ;
    END
  END w_d[779]
  PIN w_d[77]
    DIRECTION INPUT ;
    USE SIGNAL ;
    PORT
      LAYER M4 ;
        RECT 129.408 11.712 129.600 11.736 ;
    END
  END w_d[77]
  PIN w_d[780]
    DIRECTION INPUT ;
    USE SIGNAL ;
    PORT
      LAYER M3 ;
        RECT 91.368 0.000 91.386 0.038 ;
    END
  END w_d[780]
  PIN w_d[781]
    DIRECTION INPUT ;
    USE SIGNAL ;
    PORT
      LAYER M5 ;
        RECT 91.488 0.000 91.512 0.084 ;
    END
  END w_d[781]
  PIN w_d[782]
    DIRECTION INPUT ;
    USE SIGNAL ;
    PORT
      LAYER M3 ;
        RECT 91.656 0.000 91.674 0.038 ;
    END
  END w_d[782]
  PIN w_d[783]
    DIRECTION INPUT ;
    USE SIGNAL ;
    PORT
      LAYER M3 ;
        RECT 91.800 0.000 91.818 0.038 ;
    END
  END w_d[783]
  PIN w_d[784]
    DIRECTION INPUT ;
    USE SIGNAL ;
    PORT
      LAYER M3 ;
        RECT 91.944 0.000 91.962 0.038 ;
    END
  END w_d[784]
  PIN w_d[785]
    DIRECTION INPUT ;
    USE SIGNAL ;
    PORT
      LAYER M3 ;
        RECT 92.088 0.000 92.106 0.038 ;
    END
  END w_d[785]
  PIN w_d[786]
    DIRECTION INPUT ;
    USE SIGNAL ;
    PORT
      LAYER M3 ;
        RECT 92.232 0.000 92.250 0.038 ;
    END
  END w_d[786]
  PIN w_d[787]
    DIRECTION INPUT ;
    USE SIGNAL ;
    PORT
      LAYER M3 ;
        RECT 92.376 0.000 92.394 0.038 ;
    END
  END w_d[787]
  PIN w_d[788]
    DIRECTION INPUT ;
    USE SIGNAL ;
    PORT
      LAYER M5 ;
        RECT 92.544 0.000 92.568 0.084 ;
    END
  END w_d[788]
  PIN w_d[789]
    DIRECTION INPUT ;
    USE SIGNAL ;
    PORT
      LAYER M3 ;
        RECT 92.664 0.000 92.682 0.038 ;
    END
  END w_d[789]
  PIN w_d[78]
    DIRECTION INPUT ;
    USE SIGNAL ;
    PORT
      LAYER M4 ;
        RECT 0.000 15.024 0.192 15.048 ;
    END
  END w_d[78]
  PIN w_d[790]
    DIRECTION INPUT ;
    USE SIGNAL ;
    PORT
      LAYER M5 ;
        RECT 92.832 0.000 92.856 0.084 ;
    END
  END w_d[790]
  PIN w_d[791]
    DIRECTION INPUT ;
    USE SIGNAL ;
    PORT
      LAYER M3 ;
        RECT 93.024 0.000 93.042 0.038 ;
    END
  END w_d[791]
  PIN w_d[792]
    DIRECTION INPUT ;
    USE SIGNAL ;
    PORT
      LAYER M5 ;
        RECT 93.120 0.000 93.144 0.084 ;
    END
  END w_d[792]
  PIN w_d[793]
    DIRECTION INPUT ;
    USE SIGNAL ;
    PORT
      LAYER M3 ;
        RECT 93.312 0.000 93.330 0.038 ;
    END
  END w_d[793]
  PIN w_d[794]
    DIRECTION INPUT ;
    USE SIGNAL ;
    PORT
      LAYER M3 ;
        RECT 93.456 0.000 93.474 0.038 ;
    END
  END w_d[794]
  PIN w_d[795]
    DIRECTION INPUT ;
    USE SIGNAL ;
    PORT
      LAYER M3 ;
        RECT 93.600 0.000 93.618 0.038 ;
    END
  END w_d[795]
  PIN w_d[796]
    DIRECTION INPUT ;
    USE SIGNAL ;
    PORT
      LAYER M3 ;
        RECT 93.744 0.000 93.762 0.038 ;
    END
  END w_d[796]
  PIN w_d[797]
    DIRECTION INPUT ;
    USE SIGNAL ;
    PORT
      LAYER M5 ;
        RECT 93.888 0.000 93.912 0.084 ;
    END
  END w_d[797]
  PIN w_d[798]
    DIRECTION INPUT ;
    USE SIGNAL ;
    PORT
      LAYER M3 ;
        RECT 94.032 0.000 94.050 0.038 ;
    END
  END w_d[798]
  PIN w_d[799]
    DIRECTION INPUT ;
    USE SIGNAL ;
    PORT
      LAYER M5 ;
        RECT 94.176 0.000 94.200 0.084 ;
    END
  END w_d[799]
  PIN w_d[79]
    DIRECTION INPUT ;
    USE SIGNAL ;
    PORT
      LAYER M4 ;
        RECT 129.408 11.904 129.600 11.928 ;
    END
  END w_d[79]
  PIN w_d[7]
    DIRECTION INPUT ;
    USE SIGNAL ;
    PORT
      LAYER M4 ;
        RECT 129.408 6.288 129.600 6.312 ;
    END
  END w_d[7]
  PIN w_d[800]
    DIRECTION INPUT ;
    USE SIGNAL ;
    PORT
      LAYER M3 ;
        RECT 94.392 0.000 94.410 0.038 ;
    END
  END w_d[800]
  PIN w_d[801]
    DIRECTION INPUT ;
    USE SIGNAL ;
    PORT
      LAYER M5 ;
        RECT 94.656 0.000 94.680 0.084 ;
    END
  END w_d[801]
  PIN w_d[802]
    DIRECTION INPUT ;
    USE SIGNAL ;
    PORT
      LAYER M3 ;
        RECT 94.824 0.000 94.842 0.038 ;
    END
  END w_d[802]
  PIN w_d[803]
    DIRECTION INPUT ;
    USE SIGNAL ;
    PORT
      LAYER M5 ;
        RECT 94.944 0.000 94.968 0.084 ;
    END
  END w_d[803]
  PIN w_d[804]
    DIRECTION INPUT ;
    USE SIGNAL ;
    PORT
      LAYER M3 ;
        RECT 95.112 0.000 95.130 0.038 ;
    END
  END w_d[804]
  PIN w_d[805]
    DIRECTION INPUT ;
    USE SIGNAL ;
    PORT
      LAYER M3 ;
        RECT 95.256 0.000 95.274 0.038 ;
    END
  END w_d[805]
  PIN w_d[806]
    DIRECTION INPUT ;
    USE SIGNAL ;
    PORT
      LAYER M3 ;
        RECT 95.400 0.000 95.418 0.038 ;
    END
  END w_d[806]
  PIN w_d[807]
    DIRECTION INPUT ;
    USE SIGNAL ;
    PORT
      LAYER M3 ;
        RECT 95.544 0.000 95.562 0.038 ;
    END
  END w_d[807]
  PIN w_d[808]
    DIRECTION INPUT ;
    USE SIGNAL ;
    PORT
      LAYER M5 ;
        RECT 95.712 0.000 95.736 0.084 ;
    END
  END w_d[808]
  PIN w_d[809]
    DIRECTION INPUT ;
    USE SIGNAL ;
    PORT
      LAYER M3 ;
        RECT 95.832 0.000 95.850 0.038 ;
    END
  END w_d[809]
  PIN w_d[80]
    DIRECTION INPUT ;
    USE SIGNAL ;
    PORT
      LAYER M4 ;
        RECT 0.000 15.312 0.192 15.336 ;
    END
  END w_d[80]
  PIN w_d[810]
    DIRECTION INPUT ;
    USE SIGNAL ;
    PORT
      LAYER M5 ;
        RECT 96.000 0.000 96.024 0.084 ;
    END
  END w_d[810]
  PIN w_d[811]
    DIRECTION INPUT ;
    USE SIGNAL ;
    PORT
      LAYER M3 ;
        RECT 96.120 0.000 96.138 0.038 ;
    END
  END w_d[811]
  PIN w_d[812]
    DIRECTION INPUT ;
    USE SIGNAL ;
    PORT
      LAYER M5 ;
        RECT 96.288 0.000 96.312 0.084 ;
    END
  END w_d[812]
  PIN w_d[813]
    DIRECTION INPUT ;
    USE SIGNAL ;
    PORT
      LAYER M3 ;
        RECT 96.480 0.000 96.498 0.038 ;
    END
  END w_d[813]
  PIN w_d[814]
    DIRECTION INPUT ;
    USE SIGNAL ;
    PORT
      LAYER M5 ;
        RECT 96.576 0.000 96.600 0.084 ;
    END
  END w_d[814]
  PIN w_d[815]
    DIRECTION INPUT ;
    USE SIGNAL ;
    PORT
      LAYER M3 ;
        RECT 96.768 0.000 96.786 0.038 ;
    END
  END w_d[815]
  PIN w_d[816]
    DIRECTION INPUT ;
    USE SIGNAL ;
    PORT
      LAYER M3 ;
        RECT 96.912 0.000 96.930 0.038 ;
    END
  END w_d[816]
  PIN w_d[817]
    DIRECTION INPUT ;
    USE SIGNAL ;
    PORT
      LAYER M3 ;
        RECT 97.056 0.000 97.074 0.038 ;
    END
  END w_d[817]
  PIN w_d[818]
    DIRECTION INPUT ;
    USE SIGNAL ;
    PORT
      LAYER M3 ;
        RECT 97.200 0.000 97.218 0.038 ;
    END
  END w_d[818]
  PIN w_d[819]
    DIRECTION INPUT ;
    USE SIGNAL ;
    PORT
      LAYER M5 ;
        RECT 97.344 0.000 97.368 0.084 ;
    END
  END w_d[819]
  PIN w_d[81]
    DIRECTION INPUT ;
    USE SIGNAL ;
    PORT
      LAYER M4 ;
        RECT 129.408 12.048 129.600 12.072 ;
    END
  END w_d[81]
  PIN w_d[820]
    DIRECTION INPUT ;
    USE SIGNAL ;
    PORT
      LAYER M3 ;
        RECT 97.488 0.000 97.506 0.038 ;
    END
  END w_d[820]
  PIN w_d[821]
    DIRECTION INPUT ;
    USE SIGNAL ;
    PORT
      LAYER M5 ;
        RECT 97.632 0.000 97.656 0.084 ;
    END
  END w_d[821]
  PIN w_d[822]
    DIRECTION INPUT ;
    USE SIGNAL ;
    PORT
      LAYER M3 ;
        RECT 97.776 0.000 97.794 0.038 ;
    END
  END w_d[822]
  PIN w_d[823]
    DIRECTION INPUT ;
    USE SIGNAL ;
    PORT
      LAYER M5 ;
        RECT 97.920 0.000 97.944 0.084 ;
    END
  END w_d[823]
  PIN w_d[824]
    DIRECTION INPUT ;
    USE SIGNAL ;
    PORT
      LAYER M5 ;
        RECT 98.112 0.000 98.136 0.084 ;
    END
  END w_d[824]
  PIN w_d[825]
    DIRECTION INPUT ;
    USE SIGNAL ;
    PORT
      LAYER M5 ;
        RECT 98.208 0.000 98.232 0.084 ;
    END
  END w_d[825]
  PIN w_d[826]
    DIRECTION INPUT ;
    USE SIGNAL ;
    PORT
      LAYER M5 ;
        RECT 98.400 0.000 98.424 0.084 ;
    END
  END w_d[826]
  PIN w_d[827]
    DIRECTION INPUT ;
    USE SIGNAL ;
    PORT
      LAYER M3 ;
        RECT 98.568 0.000 98.586 0.038 ;
    END
  END w_d[827]
  PIN w_d[828]
    DIRECTION INPUT ;
    USE SIGNAL ;
    PORT
      LAYER M5 ;
        RECT 98.688 0.000 98.712 0.084 ;
    END
  END w_d[828]
  PIN w_d[829]
    DIRECTION INPUT ;
    USE SIGNAL ;
    PORT
      LAYER M3 ;
        RECT 98.856 0.000 98.874 0.038 ;
    END
  END w_d[829]
  PIN w_d[82]
    DIRECTION INPUT ;
    USE SIGNAL ;
    PORT
      LAYER M4 ;
        RECT 0.000 15.504 0.192 15.528 ;
    END
  END w_d[82]
  PIN w_d[830]
    DIRECTION INPUT ;
    USE SIGNAL ;
    PORT
      LAYER M3 ;
        RECT 99.000 0.000 99.018 0.038 ;
    END
  END w_d[830]
  PIN w_d[831]
    DIRECTION INPUT ;
    USE SIGNAL ;
    PORT
      LAYER M3 ;
        RECT 99.144 0.000 99.162 0.038 ;
    END
  END w_d[831]
  PIN w_d[832]
    DIRECTION INPUT ;
    USE SIGNAL ;
    PORT
      LAYER M3 ;
        RECT 99.288 0.000 99.306 0.038 ;
    END
  END w_d[832]
  PIN w_d[833]
    DIRECTION INPUT ;
    USE SIGNAL ;
    PORT
      LAYER M3 ;
        RECT 99.432 0.000 99.450 0.038 ;
    END
  END w_d[833]
  PIN w_d[834]
    DIRECTION INPUT ;
    USE SIGNAL ;
    PORT
      LAYER M3 ;
        RECT 99.576 0.000 99.594 0.038 ;
    END
  END w_d[834]
  PIN w_d[835]
    DIRECTION INPUT ;
    USE SIGNAL ;
    PORT
      LAYER M3 ;
        RECT 99.864 0.000 99.882 0.038 ;
    END
  END w_d[835]
  PIN w_d[836]
    DIRECTION INPUT ;
    USE SIGNAL ;
    PORT
      LAYER M5 ;
        RECT 100.032 0.000 100.056 0.084 ;
    END
  END w_d[836]
  PIN w_d[837]
    DIRECTION INPUT ;
    USE SIGNAL ;
    PORT
      LAYER M3 ;
        RECT 100.224 0.000 100.242 0.038 ;
    END
  END w_d[837]
  PIN w_d[838]
    DIRECTION INPUT ;
    USE SIGNAL ;
    PORT
      LAYER M3 ;
        RECT 100.368 0.000 100.386 0.038 ;
    END
  END w_d[838]
  PIN w_d[839]
    DIRECTION INPUT ;
    USE SIGNAL ;
    PORT
      LAYER M3 ;
        RECT 100.512 0.000 100.530 0.038 ;
    END
  END w_d[839]
  PIN w_d[83]
    DIRECTION INPUT ;
    USE SIGNAL ;
    PORT
      LAYER M4 ;
        RECT 129.408 12.240 129.600 12.264 ;
    END
  END w_d[83]
  PIN w_d[840]
    DIRECTION INPUT ;
    USE SIGNAL ;
    PORT
      LAYER M3 ;
        RECT 100.656 0.000 100.674 0.038 ;
    END
  END w_d[840]
  PIN w_d[841]
    DIRECTION INPUT ;
    USE SIGNAL ;
    PORT
      LAYER M5 ;
        RECT 100.800 0.000 100.824 0.084 ;
    END
  END w_d[841]
  PIN w_d[842]
    DIRECTION INPUT ;
    USE SIGNAL ;
    PORT
      LAYER M3 ;
        RECT 100.944 0.000 100.962 0.038 ;
    END
  END w_d[842]
  PIN w_d[843]
    DIRECTION INPUT ;
    USE SIGNAL ;
    PORT
      LAYER M5 ;
        RECT 101.088 0.000 101.112 0.084 ;
    END
  END w_d[843]
  PIN w_d[844]
    DIRECTION INPUT ;
    USE SIGNAL ;
    PORT
      LAYER M5 ;
        RECT 101.280 0.000 101.304 0.084 ;
    END
  END w_d[844]
  PIN w_d[845]
    DIRECTION INPUT ;
    USE SIGNAL ;
    PORT
      LAYER M5 ;
        RECT 101.376 0.000 101.400 0.084 ;
    END
  END w_d[845]
  PIN w_d[846]
    DIRECTION INPUT ;
    USE SIGNAL ;
    PORT
      LAYER M5 ;
        RECT 101.568 0.000 101.592 0.084 ;
    END
  END w_d[846]
  PIN w_d[847]
    DIRECTION INPUT ;
    USE SIGNAL ;
    PORT
      LAYER M5 ;
        RECT 101.664 0.000 101.688 0.084 ;
    END
  END w_d[847]
  PIN w_d[848]
    DIRECTION INPUT ;
    USE SIGNAL ;
    PORT
      LAYER M5 ;
        RECT 101.856 0.000 101.880 0.084 ;
    END
  END w_d[848]
  PIN w_d[849]
    DIRECTION INPUT ;
    USE SIGNAL ;
    PORT
      LAYER M3 ;
        RECT 102.024 0.000 102.042 0.038 ;
    END
  END w_d[849]
  PIN w_d[84]
    DIRECTION INPUT ;
    USE SIGNAL ;
    PORT
      LAYER M4 ;
        RECT 0.000 15.696 0.192 15.720 ;
    END
  END w_d[84]
  PIN w_d[850]
    DIRECTION INPUT ;
    USE SIGNAL ;
    PORT
      LAYER M5 ;
        RECT 102.144 0.000 102.168 0.084 ;
    END
  END w_d[850]
  PIN w_d[851]
    DIRECTION INPUT ;
    USE SIGNAL ;
    PORT
      LAYER M3 ;
        RECT 102.312 0.000 102.330 0.038 ;
    END
  END w_d[851]
  PIN w_d[852]
    DIRECTION INPUT ;
    USE SIGNAL ;
    PORT
      LAYER M3 ;
        RECT 102.456 0.000 102.474 0.038 ;
    END
  END w_d[852]
  PIN w_d[853]
    DIRECTION INPUT ;
    USE SIGNAL ;
    PORT
      LAYER M3 ;
        RECT 102.600 0.000 102.618 0.038 ;
    END
  END w_d[853]
  PIN w_d[854]
    DIRECTION INPUT ;
    USE SIGNAL ;
    PORT
      LAYER M3 ;
        RECT 102.744 0.000 102.762 0.038 ;
    END
  END w_d[854]
  PIN w_d[855]
    DIRECTION INPUT ;
    USE SIGNAL ;
    PORT
      LAYER M5 ;
        RECT 102.912 0.000 102.936 0.084 ;
    END
  END w_d[855]
  PIN w_d[856]
    DIRECTION INPUT ;
    USE SIGNAL ;
    PORT
      LAYER M3 ;
        RECT 103.032 0.000 103.050 0.038 ;
    END
  END w_d[856]
  PIN w_d[857]
    DIRECTION INPUT ;
    USE SIGNAL ;
    PORT
      LAYER M5 ;
        RECT 103.200 0.000 103.224 0.084 ;
    END
  END w_d[857]
  PIN w_d[858]
    DIRECTION INPUT ;
    USE SIGNAL ;
    PORT
      LAYER M3 ;
        RECT 103.320 0.000 103.338 0.038 ;
    END
  END w_d[858]
  PIN w_d[859]
    DIRECTION INPUT ;
    USE SIGNAL ;
    PORT
      LAYER M5 ;
        RECT 103.488 0.000 103.512 0.084 ;
    END
  END w_d[859]
  PIN w_d[85]
    DIRECTION INPUT ;
    USE SIGNAL ;
    PORT
      LAYER M4 ;
        RECT 129.408 12.336 129.600 12.360 ;
    END
  END w_d[85]
  PIN w_d[860]
    DIRECTION INPUT ;
    USE SIGNAL ;
    PORT
      LAYER M3 ;
        RECT 103.680 0.000 103.698 0.038 ;
    END
  END w_d[860]
  PIN w_d[861]
    DIRECTION INPUT ;
    USE SIGNAL ;
    PORT
      LAYER M5 ;
        RECT 103.776 0.000 103.800 0.084 ;
    END
  END w_d[861]
  PIN w_d[862]
    DIRECTION INPUT ;
    USE SIGNAL ;
    PORT
      LAYER M3 ;
        RECT 103.968 0.000 103.986 0.038 ;
    END
  END w_d[862]
  PIN w_d[863]
    DIRECTION INPUT ;
    USE SIGNAL ;
    PORT
      LAYER M3 ;
        RECT 104.112 0.000 104.130 0.038 ;
    END
  END w_d[863]
  PIN w_d[864]
    DIRECTION INPUT ;
    USE SIGNAL ;
    PORT
      LAYER M3 ;
        RECT 104.256 0.000 104.274 0.038 ;
    END
  END w_d[864]
  PIN w_d[865]
    DIRECTION INPUT ;
    USE SIGNAL ;
    PORT
      LAYER M3 ;
        RECT 104.400 0.000 104.418 0.038 ;
    END
  END w_d[865]
  PIN w_d[866]
    DIRECTION INPUT ;
    USE SIGNAL ;
    PORT
      LAYER M5 ;
        RECT 104.544 0.000 104.568 0.084 ;
    END
  END w_d[866]
  PIN w_d[867]
    DIRECTION INPUT ;
    USE SIGNAL ;
    PORT
      LAYER M3 ;
        RECT 104.688 0.000 104.706 0.038 ;
    END
  END w_d[867]
  PIN w_d[868]
    DIRECTION INPUT ;
    USE SIGNAL ;
    PORT
      LAYER M5 ;
        RECT 104.832 0.000 104.856 0.084 ;
    END
  END w_d[868]
  PIN w_d[869]
    DIRECTION INPUT ;
    USE SIGNAL ;
    PORT
      LAYER M3 ;
        RECT 104.976 0.000 104.994 0.038 ;
    END
  END w_d[869]
  PIN w_d[86]
    DIRECTION INPUT ;
    USE SIGNAL ;
    PORT
      LAYER M4 ;
        RECT 0.000 15.888 0.192 15.912 ;
    END
  END w_d[86]
  PIN w_d[870]
    DIRECTION INPUT ;
    USE SIGNAL ;
    PORT
      LAYER M3 ;
        RECT 105.264 0.000 105.282 0.038 ;
    END
  END w_d[870]
  PIN w_d[871]
    DIRECTION INPUT ;
    USE SIGNAL ;
    PORT
      LAYER M3 ;
        RECT 105.480 0.000 105.498 0.038 ;
    END
  END w_d[871]
  PIN w_d[872]
    DIRECTION INPUT ;
    USE SIGNAL ;
    PORT
      LAYER M5 ;
        RECT 105.600 0.000 105.624 0.084 ;
    END
  END w_d[872]
  PIN w_d[873]
    DIRECTION INPUT ;
    USE SIGNAL ;
    PORT
      LAYER M3 ;
        RECT 105.768 0.000 105.786 0.038 ;
    END
  END w_d[873]
  PIN w_d[874]
    DIRECTION INPUT ;
    USE SIGNAL ;
    PORT
      LAYER M3 ;
        RECT 105.912 0.000 105.930 0.038 ;
    END
  END w_d[874]
  PIN w_d[875]
    DIRECTION INPUT ;
    USE SIGNAL ;
    PORT
      LAYER M3 ;
        RECT 106.056 0.000 106.074 0.038 ;
    END
  END w_d[875]
  PIN w_d[876]
    DIRECTION INPUT ;
    USE SIGNAL ;
    PORT
      LAYER M3 ;
        RECT 106.200 0.000 106.218 0.038 ;
    END
  END w_d[876]
  PIN w_d[877]
    DIRECTION INPUT ;
    USE SIGNAL ;
    PORT
      LAYER M5 ;
        RECT 106.368 0.000 106.392 0.084 ;
    END
  END w_d[877]
  PIN w_d[878]
    DIRECTION INPUT ;
    USE SIGNAL ;
    PORT
      LAYER M3 ;
        RECT 106.488 0.000 106.506 0.038 ;
    END
  END w_d[878]
  PIN w_d[879]
    DIRECTION INPUT ;
    USE SIGNAL ;
    PORT
      LAYER M5 ;
        RECT 106.656 0.000 106.680 0.084 ;
    END
  END w_d[879]
  PIN w_d[87]
    DIRECTION INPUT ;
    USE SIGNAL ;
    PORT
      LAYER M4 ;
        RECT 129.408 12.480 129.600 12.504 ;
    END
  END w_d[87]
  PIN w_d[880]
    DIRECTION INPUT ;
    USE SIGNAL ;
    PORT
      LAYER M3 ;
        RECT 106.776 0.000 106.794 0.038 ;
    END
  END w_d[880]
  PIN w_d[881]
    DIRECTION INPUT ;
    USE SIGNAL ;
    PORT
      LAYER M5 ;
        RECT 106.944 0.000 106.968 0.084 ;
    END
  END w_d[881]
  PIN w_d[882]
    DIRECTION INPUT ;
    USE SIGNAL ;
    PORT
      LAYER M3 ;
        RECT 107.136 0.000 107.154 0.038 ;
    END
  END w_d[882]
  PIN w_d[883]
    DIRECTION INPUT ;
    USE SIGNAL ;
    PORT
      LAYER M5 ;
        RECT 107.232 0.000 107.256 0.084 ;
    END
  END w_d[883]
  PIN w_d[884]
    DIRECTION INPUT ;
    USE SIGNAL ;
    PORT
      LAYER M3 ;
        RECT 107.424 0.000 107.442 0.038 ;
    END
  END w_d[884]
  PIN w_d[885]
    DIRECTION INPUT ;
    USE SIGNAL ;
    PORT
      LAYER M3 ;
        RECT 107.568 0.000 107.586 0.038 ;
    END
  END w_d[885]
  PIN w_d[886]
    DIRECTION INPUT ;
    USE SIGNAL ;
    PORT
      LAYER M3 ;
        RECT 107.712 0.000 107.730 0.038 ;
    END
  END w_d[886]
  PIN w_d[887]
    DIRECTION INPUT ;
    USE SIGNAL ;
    PORT
      LAYER M3 ;
        RECT 107.856 0.000 107.874 0.038 ;
    END
  END w_d[887]
  PIN w_d[888]
    DIRECTION INPUT ;
    USE SIGNAL ;
    PORT
      LAYER M5 ;
        RECT 108.000 0.000 108.024 0.084 ;
    END
  END w_d[888]
  PIN w_d[889]
    DIRECTION INPUT ;
    USE SIGNAL ;
    PORT
      LAYER M3 ;
        RECT 108.144 0.000 108.162 0.038 ;
    END
  END w_d[889]
  PIN w_d[88]
    DIRECTION INPUT ;
    USE SIGNAL ;
    PORT
      LAYER M4 ;
        RECT 0.000 16.080 0.192 16.104 ;
    END
  END w_d[88]
  PIN w_d[890]
    DIRECTION INPUT ;
    USE SIGNAL ;
    PORT
      LAYER M5 ;
        RECT 108.288 0.000 108.312 0.084 ;
    END
  END w_d[890]
  PIN w_d[891]
    DIRECTION INPUT ;
    USE SIGNAL ;
    PORT
      LAYER M5 ;
        RECT 108.480 0.000 108.504 0.084 ;
    END
  END w_d[891]
  PIN w_d[892]
    DIRECTION INPUT ;
    USE SIGNAL ;
    PORT
      LAYER M5 ;
        RECT 108.576 0.000 108.600 0.084 ;
    END
  END w_d[892]
  PIN w_d[893]
    DIRECTION INPUT ;
    USE SIGNAL ;
    PORT
      LAYER M5 ;
        RECT 108.768 0.000 108.792 0.084 ;
    END
  END w_d[893]
  PIN w_d[894]
    DIRECTION INPUT ;
    USE SIGNAL ;
    PORT
      LAYER M5 ;
        RECT 108.864 0.000 108.888 0.084 ;
    END
  END w_d[894]
  PIN w_d[895]
    DIRECTION INPUT ;
    USE SIGNAL ;
    PORT
      LAYER M5 ;
        RECT 109.056 0.000 109.080 0.084 ;
    END
  END w_d[895]
  PIN w_d[896]
    DIRECTION INPUT ;
    USE SIGNAL ;
    PORT
      LAYER M3 ;
        RECT 109.224 0.000 109.242 0.038 ;
    END
  END w_d[896]
  PIN w_d[897]
    DIRECTION INPUT ;
    USE SIGNAL ;
    PORT
      LAYER M5 ;
        RECT 109.344 0.000 109.368 0.084 ;
    END
  END w_d[897]
  PIN w_d[898]
    DIRECTION INPUT ;
    USE SIGNAL ;
    PORT
      LAYER M3 ;
        RECT 109.512 0.000 109.530 0.038 ;
    END
  END w_d[898]
  PIN w_d[899]
    DIRECTION INPUT ;
    USE SIGNAL ;
    PORT
      LAYER M3 ;
        RECT 109.656 0.000 109.674 0.038 ;
    END
  END w_d[899]
  PIN w_d[89]
    DIRECTION INPUT ;
    USE SIGNAL ;
    PORT
      LAYER M4 ;
        RECT 129.408 12.672 129.600 12.696 ;
    END
  END w_d[89]
  PIN w_d[8]
    DIRECTION INPUT ;
    USE SIGNAL ;
    PORT
      LAYER M4 ;
        RECT 0.000 8.112 0.192 8.136 ;
    END
  END w_d[8]
  PIN w_d[900]
    DIRECTION INPUT ;
    USE SIGNAL ;
    PORT
      LAYER M3 ;
        RECT 109.800 0.000 109.818 0.038 ;
    END
  END w_d[900]
  PIN w_d[901]
    DIRECTION INPUT ;
    USE SIGNAL ;
    PORT
      LAYER M3 ;
        RECT 109.944 0.000 109.962 0.038 ;
    END
  END w_d[901]
  PIN w_d[902]
    DIRECTION INPUT ;
    USE SIGNAL ;
    PORT
      LAYER M5 ;
        RECT 110.112 0.000 110.136 0.084 ;
    END
  END w_d[902]
  PIN w_d[903]
    DIRECTION INPUT ;
    USE SIGNAL ;
    PORT
      LAYER M3 ;
        RECT 110.232 0.000 110.250 0.038 ;
    END
  END w_d[903]
  PIN w_d[904]
    DIRECTION INPUT ;
    USE SIGNAL ;
    PORT
      LAYER M5 ;
        RECT 110.400 0.000 110.424 0.084 ;
    END
  END w_d[904]
  PIN w_d[905]
    DIRECTION INPUT ;
    USE SIGNAL ;
    PORT
      LAYER M3 ;
        RECT 110.592 0.000 110.610 0.038 ;
    END
  END w_d[905]
  PIN w_d[906]
    DIRECTION INPUT ;
    USE SIGNAL ;
    PORT
      LAYER M3 ;
        RECT 110.880 0.000 110.898 0.038 ;
    END
  END w_d[906]
  PIN w_d[907]
    DIRECTION INPUT ;
    USE SIGNAL ;
    PORT
      LAYER M3 ;
        RECT 111.024 0.000 111.042 0.038 ;
    END
  END w_d[907]
  PIN w_d[908]
    DIRECTION INPUT ;
    USE SIGNAL ;
    PORT
      LAYER M3 ;
        RECT 111.168 0.000 111.186 0.038 ;
    END
  END w_d[908]
  PIN w_d[909]
    DIRECTION INPUT ;
    USE SIGNAL ;
    PORT
      LAYER M3 ;
        RECT 111.312 0.000 111.330 0.038 ;
    END
  END w_d[909]
  PIN w_d[90]
    DIRECTION INPUT ;
    USE SIGNAL ;
    PORT
      LAYER M4 ;
        RECT 0.000 16.272 0.192 16.296 ;
    END
  END w_d[90]
  PIN w_d[910]
    DIRECTION INPUT ;
    USE SIGNAL ;
    PORT
      LAYER M5 ;
        RECT 111.456 0.000 111.480 0.084 ;
    END
  END w_d[910]
  PIN w_d[911]
    DIRECTION INPUT ;
    USE SIGNAL ;
    PORT
      LAYER M3 ;
        RECT 111.600 0.000 111.618 0.038 ;
    END
  END w_d[911]
  PIN w_d[912]
    DIRECTION INPUT ;
    USE SIGNAL ;
    PORT
      LAYER M5 ;
        RECT 111.744 0.000 111.768 0.084 ;
    END
  END w_d[912]
  PIN w_d[913]
    DIRECTION INPUT ;
    USE SIGNAL ;
    PORT
      LAYER M5 ;
        RECT 111.936 0.000 111.960 0.084 ;
    END
  END w_d[913]
  PIN w_d[914]
    DIRECTION INPUT ;
    USE SIGNAL ;
    PORT
      LAYER M5 ;
        RECT 112.032 0.000 112.056 0.084 ;
    END
  END w_d[914]
  PIN w_d[915]
    DIRECTION INPUT ;
    USE SIGNAL ;
    PORT
      LAYER M5 ;
        RECT 112.224 0.000 112.248 0.084 ;
    END
  END w_d[915]
  PIN w_d[916]
    DIRECTION INPUT ;
    USE SIGNAL ;
    PORT
      LAYER M5 ;
        RECT 112.320 0.000 112.344 0.084 ;
    END
  END w_d[916]
  PIN w_d[917]
    DIRECTION INPUT ;
    USE SIGNAL ;
    PORT
      LAYER M5 ;
        RECT 112.512 0.000 112.536 0.084 ;
    END
  END w_d[917]
  PIN w_d[918]
    DIRECTION INPUT ;
    USE SIGNAL ;
    PORT
      LAYER M3 ;
        RECT 112.680 0.000 112.698 0.038 ;
    END
  END w_d[918]
  PIN w_d[919]
    DIRECTION INPUT ;
    USE SIGNAL ;
    PORT
      LAYER M5 ;
        RECT 112.800 0.000 112.824 0.084 ;
    END
  END w_d[919]
  PIN w_d[91]
    DIRECTION INPUT ;
    USE SIGNAL ;
    PORT
      LAYER M4 ;
        RECT 129.408 12.816 129.600 12.840 ;
    END
  END w_d[91]
  PIN w_d[920]
    DIRECTION INPUT ;
    USE SIGNAL ;
    PORT
      LAYER M3 ;
        RECT 112.968 0.000 112.986 0.038 ;
    END
  END w_d[920]
  PIN w_d[921]
    DIRECTION INPUT ;
    USE SIGNAL ;
    PORT
      LAYER M3 ;
        RECT 113.112 0.000 113.130 0.038 ;
    END
  END w_d[921]
  PIN w_d[922]
    DIRECTION INPUT ;
    USE SIGNAL ;
    PORT
      LAYER M3 ;
        RECT 113.256 0.000 113.274 0.038 ;
    END
  END w_d[922]
  PIN w_d[923]
    DIRECTION INPUT ;
    USE SIGNAL ;
    PORT
      LAYER M3 ;
        RECT 113.400 0.000 113.418 0.038 ;
    END
  END w_d[923]
  PIN w_d[924]
    DIRECTION INPUT ;
    USE SIGNAL ;
    PORT
      LAYER M5 ;
        RECT 113.568 0.000 113.592 0.084 ;
    END
  END w_d[924]
  PIN w_d[925]
    DIRECTION INPUT ;
    USE SIGNAL ;
    PORT
      LAYER M3 ;
        RECT 113.688 0.000 113.706 0.038 ;
    END
  END w_d[925]
  PIN w_d[926]
    DIRECTION INPUT ;
    USE SIGNAL ;
    PORT
      LAYER M5 ;
        RECT 113.856 0.000 113.880 0.084 ;
    END
  END w_d[926]
  PIN w_d[927]
    DIRECTION INPUT ;
    USE SIGNAL ;
    PORT
      LAYER M3 ;
        RECT 113.976 0.000 113.994 0.038 ;
    END
  END w_d[927]
  PIN w_d[928]
    DIRECTION INPUT ;
    USE SIGNAL ;
    PORT
      LAYER M5 ;
        RECT 114.144 0.000 114.168 0.084 ;
    END
  END w_d[928]
  PIN w_d[929]
    DIRECTION INPUT ;
    USE SIGNAL ;
    PORT
      LAYER M3 ;
        RECT 114.336 0.000 114.354 0.038 ;
    END
  END w_d[929]
  PIN w_d[92]
    DIRECTION INPUT ;
    USE SIGNAL ;
    PORT
      LAYER M4 ;
        RECT 0.000 16.464 0.192 16.488 ;
    END
  END w_d[92]
  PIN w_d[930]
    DIRECTION INPUT ;
    USE SIGNAL ;
    PORT
      LAYER M5 ;
        RECT 114.432 0.000 114.456 0.084 ;
    END
  END w_d[930]
  PIN w_d[931]
    DIRECTION INPUT ;
    USE SIGNAL ;
    PORT
      LAYER M3 ;
        RECT 114.624 0.000 114.642 0.038 ;
    END
  END w_d[931]
  PIN w_d[932]
    DIRECTION INPUT ;
    USE SIGNAL ;
    PORT
      LAYER M3 ;
        RECT 114.768 0.000 114.786 0.038 ;
    END
  END w_d[932]
  PIN w_d[933]
    DIRECTION INPUT ;
    USE SIGNAL ;
    PORT
      LAYER M3 ;
        RECT 114.912 0.000 114.930 0.038 ;
    END
  END w_d[933]
  PIN w_d[934]
    DIRECTION INPUT ;
    USE SIGNAL ;
    PORT
      LAYER M3 ;
        RECT 115.056 0.000 115.074 0.038 ;
    END
  END w_d[934]
  PIN w_d[935]
    DIRECTION INPUT ;
    USE SIGNAL ;
    PORT
      LAYER M5 ;
        RECT 115.200 0.000 115.224 0.084 ;
    END
  END w_d[935]
  PIN w_d[936]
    DIRECTION INPUT ;
    USE SIGNAL ;
    PORT
      LAYER M3 ;
        RECT 115.344 0.000 115.362 0.038 ;
    END
  END w_d[936]
  PIN w_d[937]
    DIRECTION INPUT ;
    USE SIGNAL ;
    PORT
      LAYER M5 ;
        RECT 115.488 0.000 115.512 0.084 ;
    END
  END w_d[937]
  PIN w_d[938]
    DIRECTION INPUT ;
    USE SIGNAL ;
    PORT
      LAYER M5 ;
        RECT 115.680 0.000 115.704 0.084 ;
    END
  END w_d[938]
  PIN w_d[939]
    DIRECTION INPUT ;
    USE SIGNAL ;
    PORT
      LAYER M5 ;
        RECT 115.776 0.000 115.800 0.084 ;
    END
  END w_d[939]
  PIN w_d[93]
    DIRECTION INPUT ;
    USE SIGNAL ;
    PORT
      LAYER M4 ;
        RECT 129.408 13.008 129.600 13.032 ;
    END
  END w_d[93]
  PIN w_d[940]
    DIRECTION INPUT ;
    USE SIGNAL ;
    PORT
      LAYER M3 ;
        RECT 116.064 0.000 116.082 0.038 ;
    END
  END w_d[940]
  PIN w_d[941]
    DIRECTION INPUT ;
    USE SIGNAL ;
    PORT
      LAYER M5 ;
        RECT 116.256 0.000 116.280 0.084 ;
    END
  END w_d[941]
  PIN w_d[942]
    DIRECTION INPUT ;
    USE SIGNAL ;
    PORT
      LAYER M3 ;
        RECT 116.424 0.000 116.442 0.038 ;
    END
  END w_d[942]
  PIN w_d[943]
    DIRECTION INPUT ;
    USE SIGNAL ;
    PORT
      LAYER M3 ;
        RECT 116.568 0.000 116.586 0.038 ;
    END
  END w_d[943]
  PIN w_d[944]
    DIRECTION INPUT ;
    USE SIGNAL ;
    PORT
      LAYER M3 ;
        RECT 116.712 0.000 116.730 0.038 ;
    END
  END w_d[944]
  PIN w_d[945]
    DIRECTION INPUT ;
    USE SIGNAL ;
    PORT
      LAYER M3 ;
        RECT 116.856 0.000 116.874 0.038 ;
    END
  END w_d[945]
  PIN w_d[946]
    DIRECTION INPUT ;
    USE SIGNAL ;
    PORT
      LAYER M5 ;
        RECT 117.024 0.000 117.048 0.084 ;
    END
  END w_d[946]
  PIN w_d[947]
    DIRECTION INPUT ;
    USE SIGNAL ;
    PORT
      LAYER M3 ;
        RECT 117.144 0.000 117.162 0.038 ;
    END
  END w_d[947]
  PIN w_d[948]
    DIRECTION INPUT ;
    USE SIGNAL ;
    PORT
      LAYER M5 ;
        RECT 117.312 0.000 117.336 0.084 ;
    END
  END w_d[948]
  PIN w_d[949]
    DIRECTION INPUT ;
    USE SIGNAL ;
    PORT
      LAYER M3 ;
        RECT 117.504 0.000 117.522 0.038 ;
    END
  END w_d[949]
  PIN w_d[94]
    DIRECTION INPUT ;
    USE SIGNAL ;
    PORT
      LAYER M4 ;
        RECT 0.000 16.656 0.192 16.680 ;
    END
  END w_d[94]
  PIN w_d[950]
    DIRECTION INPUT ;
    USE SIGNAL ;
    PORT
      LAYER M5 ;
        RECT 117.600 0.000 117.624 0.084 ;
    END
  END w_d[950]
  PIN w_d[951]
    DIRECTION INPUT ;
    USE SIGNAL ;
    PORT
      LAYER M3 ;
        RECT 117.792 0.000 117.810 0.038 ;
    END
  END w_d[951]
  PIN w_d[952]
    DIRECTION INPUT ;
    USE SIGNAL ;
    PORT
      LAYER M5 ;
        RECT 117.888 0.000 117.912 0.084 ;
    END
  END w_d[952]
  PIN w_d[953]
    DIRECTION INPUT ;
    USE SIGNAL ;
    PORT
      LAYER M3 ;
        RECT 118.080 0.000 118.098 0.038 ;
    END
  END w_d[953]
  PIN w_d[954]
    DIRECTION INPUT ;
    USE SIGNAL ;
    PORT
      LAYER M3 ;
        RECT 118.224 0.000 118.242 0.038 ;
    END
  END w_d[954]
  PIN w_d[955]
    DIRECTION INPUT ;
    USE SIGNAL ;
    PORT
      LAYER M3 ;
        RECT 118.368 0.000 118.386 0.038 ;
    END
  END w_d[955]
  PIN w_d[956]
    DIRECTION INPUT ;
    USE SIGNAL ;
    PORT
      LAYER M3 ;
        RECT 118.512 0.000 118.530 0.038 ;
    END
  END w_d[956]
  PIN w_d[957]
    DIRECTION INPUT ;
    USE SIGNAL ;
    PORT
      LAYER M5 ;
        RECT 118.656 0.000 118.680 0.084 ;
    END
  END w_d[957]
  PIN w_d[958]
    DIRECTION INPUT ;
    USE SIGNAL ;
    PORT
      LAYER M3 ;
        RECT 118.800 0.000 118.818 0.038 ;
    END
  END w_d[958]
  PIN w_d[959]
    DIRECTION INPUT ;
    USE SIGNAL ;
    PORT
      LAYER M5 ;
        RECT 118.944 0.000 118.968 0.084 ;
    END
  END w_d[959]
  PIN w_d[95]
    DIRECTION INPUT ;
    USE SIGNAL ;
    PORT
      LAYER M4 ;
        RECT 129.408 13.104 129.600 13.128 ;
    END
  END w_d[95]
  PIN w_d[960]
    DIRECTION INPUT ;
    USE SIGNAL ;
    PORT
      LAYER M5 ;
        RECT 119.136 0.000 119.160 0.084 ;
    END
  END w_d[960]
  PIN w_d[961]
    DIRECTION INPUT ;
    USE SIGNAL ;
    PORT
      LAYER M5 ;
        RECT 119.232 0.000 119.256 0.084 ;
    END
  END w_d[961]
  PIN w_d[962]
    DIRECTION INPUT ;
    USE SIGNAL ;
    PORT
      LAYER M5 ;
        RECT 119.424 0.000 119.448 0.084 ;
    END
  END w_d[962]
  PIN w_d[963]
    DIRECTION INPUT ;
    USE SIGNAL ;
    PORT
      LAYER M5 ;
        RECT 119.520 0.000 119.544 0.084 ;
    END
  END w_d[963]
  PIN w_d[964]
    DIRECTION INPUT ;
    USE SIGNAL ;
    PORT
      LAYER M5 ;
        RECT 119.712 0.000 119.736 0.084 ;
    END
  END w_d[964]
  PIN w_d[965]
    DIRECTION INPUT ;
    USE SIGNAL ;
    PORT
      LAYER M3 ;
        RECT 119.880 0.000 119.898 0.038 ;
    END
  END w_d[965]
  PIN w_d[966]
    DIRECTION INPUT ;
    USE SIGNAL ;
    PORT
      LAYER M5 ;
        RECT 120.000 0.000 120.024 0.084 ;
    END
  END w_d[966]
  PIN w_d[967]
    DIRECTION INPUT ;
    USE SIGNAL ;
    PORT
      LAYER M3 ;
        RECT 120.168 0.000 120.186 0.038 ;
    END
  END w_d[967]
  PIN w_d[968]
    DIRECTION INPUT ;
    USE SIGNAL ;
    PORT
      LAYER M3 ;
        RECT 120.312 0.000 120.330 0.038 ;
    END
  END w_d[968]
  PIN w_d[969]
    DIRECTION INPUT ;
    USE SIGNAL ;
    PORT
      LAYER M3 ;
        RECT 120.456 0.000 120.474 0.038 ;
    END
  END w_d[969]
  PIN w_d[96]
    DIRECTION INPUT ;
    USE SIGNAL ;
    PORT
      LAYER M4 ;
        RECT 0.000 16.848 0.192 16.872 ;
    END
  END w_d[96]
  PIN w_d[970]
    DIRECTION INPUT ;
    USE SIGNAL ;
    PORT
      LAYER M3 ;
        RECT 120.600 0.000 120.618 0.038 ;
    END
  END w_d[970]
  PIN w_d[971]
    DIRECTION INPUT ;
    USE SIGNAL ;
    PORT
      LAYER M5 ;
        RECT 120.768 0.000 120.792 0.084 ;
    END
  END w_d[971]
  PIN w_d[972]
    DIRECTION INPUT ;
    USE SIGNAL ;
    PORT
      LAYER M3 ;
        RECT 120.888 0.000 120.906 0.038 ;
    END
  END w_d[972]
  PIN w_d[973]
    DIRECTION INPUT ;
    USE SIGNAL ;
    PORT
      LAYER M5 ;
        RECT 121.056 0.000 121.080 0.084 ;
    END
  END w_d[973]
  PIN w_d[974]
    DIRECTION INPUT ;
    USE SIGNAL ;
    PORT
      LAYER M3 ;
        RECT 121.176 0.000 121.194 0.038 ;
    END
  END w_d[974]
  PIN w_d[975]
    DIRECTION INPUT ;
    USE SIGNAL ;
    PORT
      LAYER M3 ;
        RECT 121.464 0.000 121.482 0.038 ;
    END
  END w_d[975]
  PIN w_d[976]
    DIRECTION INPUT ;
    USE SIGNAL ;
    PORT
      LAYER M3 ;
        RECT 121.680 0.000 121.698 0.038 ;
    END
  END w_d[976]
  PIN w_d[977]
    DIRECTION INPUT ;
    USE SIGNAL ;
    PORT
      LAYER M3 ;
        RECT 121.824 0.000 121.842 0.038 ;
    END
  END w_d[977]
  PIN w_d[978]
    DIRECTION INPUT ;
    USE SIGNAL ;
    PORT
      LAYER M3 ;
        RECT 121.968 0.000 121.986 0.038 ;
    END
  END w_d[978]
  PIN w_d[979]
    DIRECTION INPUT ;
    USE SIGNAL ;
    PORT
      LAYER M5 ;
        RECT 122.112 0.000 122.136 0.084 ;
    END
  END w_d[979]
  PIN w_d[97]
    DIRECTION INPUT ;
    USE SIGNAL ;
    PORT
      LAYER M4 ;
        RECT 129.408 13.296 129.600 13.320 ;
    END
  END w_d[97]
  PIN w_d[980]
    DIRECTION INPUT ;
    USE SIGNAL ;
    PORT
      LAYER M3 ;
        RECT 122.256 0.000 122.274 0.038 ;
    END
  END w_d[980]
  PIN w_d[981]
    DIRECTION INPUT ;
    USE SIGNAL ;
    PORT
      LAYER M5 ;
        RECT 122.400 0.000 122.424 0.084 ;
    END
  END w_d[981]
  PIN w_d[982]
    DIRECTION INPUT ;
    USE SIGNAL ;
    PORT
      LAYER M5 ;
        RECT 122.592 0.000 122.616 0.084 ;
    END
  END w_d[982]
  PIN w_d[983]
    DIRECTION INPUT ;
    USE SIGNAL ;
    PORT
      LAYER M5 ;
        RECT 122.688 0.000 122.712 0.084 ;
    END
  END w_d[983]
  PIN w_d[984]
    DIRECTION INPUT ;
    USE SIGNAL ;
    PORT
      LAYER M5 ;
        RECT 122.880 0.000 122.904 0.084 ;
    END
  END w_d[984]
  PIN w_d[985]
    DIRECTION INPUT ;
    USE SIGNAL ;
    PORT
      LAYER M3 ;
        RECT 123.048 0.000 123.066 0.038 ;
    END
  END w_d[985]
  PIN w_d[986]
    DIRECTION INPUT ;
    USE SIGNAL ;
    PORT
      LAYER M5 ;
        RECT 123.168 0.000 123.192 0.084 ;
    END
  END w_d[986]
  PIN w_d[987]
    DIRECTION INPUT ;
    USE SIGNAL ;
    PORT
      LAYER M3 ;
        RECT 123.336 0.000 123.354 0.038 ;
    END
  END w_d[987]
  PIN w_d[988]
    DIRECTION INPUT ;
    USE SIGNAL ;
    PORT
      LAYER M5 ;
        RECT 123.456 0.000 123.480 0.084 ;
    END
  END w_d[988]
  PIN w_d[989]
    DIRECTION INPUT ;
    USE SIGNAL ;
    PORT
      LAYER M3 ;
        RECT 123.624 0.000 123.642 0.038 ;
    END
  END w_d[989]
  PIN w_d[98]
    DIRECTION INPUT ;
    USE SIGNAL ;
    PORT
      LAYER M4 ;
        RECT 0.000 17.040 0.192 17.064 ;
    END
  END w_d[98]
  PIN w_d[990]
    DIRECTION INPUT ;
    USE SIGNAL ;
    PORT
      LAYER M3 ;
        RECT 123.768 0.000 123.786 0.038 ;
    END
  END w_d[990]
  PIN w_d[991]
    DIRECTION INPUT ;
    USE SIGNAL ;
    PORT
      LAYER M3 ;
        RECT 123.912 0.000 123.930 0.038 ;
    END
  END w_d[991]
  PIN w_d[992]
    DIRECTION INPUT ;
    USE SIGNAL ;
    PORT
      LAYER M3 ;
        RECT 124.056 0.000 124.074 0.038 ;
    END
  END w_d[992]
  PIN w_d[993]
    DIRECTION INPUT ;
    USE SIGNAL ;
    PORT
      LAYER M5 ;
        RECT 124.224 0.000 124.248 0.084 ;
    END
  END w_d[993]
  PIN w_d[994]
    DIRECTION INPUT ;
    USE SIGNAL ;
    PORT
      LAYER M3 ;
        RECT 124.344 0.000 124.362 0.038 ;
    END
  END w_d[994]
  PIN w_d[995]
    DIRECTION INPUT ;
    USE SIGNAL ;
    PORT
      LAYER M5 ;
        RECT 124.512 0.000 124.536 0.084 ;
    END
  END w_d[995]
  PIN w_d[996]
    DIRECTION INPUT ;
    USE SIGNAL ;
    PORT
      LAYER M3 ;
        RECT 124.704 0.000 124.722 0.038 ;
    END
  END w_d[996]
  PIN w_d[997]
    DIRECTION INPUT ;
    USE SIGNAL ;
    PORT
      LAYER M5 ;
        RECT 124.800 0.000 124.824 0.084 ;
    END
  END w_d[997]
  PIN w_d[998]
    DIRECTION INPUT ;
    USE SIGNAL ;
    PORT
      LAYER M3 ;
        RECT 124.992 0.000 125.010 0.038 ;
    END
  END w_d[998]
  PIN w_d[999]
    DIRECTION INPUT ;
    USE SIGNAL ;
    PORT
      LAYER M5 ;
        RECT 125.088 0.000 125.112 0.084 ;
    END
  END w_d[999]
  PIN w_d[99]
    DIRECTION INPUT ;
    USE SIGNAL ;
    PORT
      LAYER M4 ;
        RECT 129.408 13.440 129.600 13.464 ;
    END
  END w_d[99]
  PIN w_d[9]
    DIRECTION INPUT ;
    USE SIGNAL ;
    PORT
      LAYER M4 ;
        RECT 129.408 6.480 129.600 6.504 ;
    END
  END w_d[9]
  PIN w_ep
    DIRECTION INPUT ;
    USE SIGNAL ;
    PORT
      LAYER M4 ;
        RECT 129.408 0.240 129.600 0.264 ;
    END
  END w_ep
  PIN w_m[0]
    DIRECTION INPUT ;
    USE SIGNAL ;
    PORT
      LAYER M4 ;
        RECT 0.000 1.008 0.192 1.032 ;
    END
  END w_m[0]
  PIN w_m[10]
    DIRECTION INPUT ;
    USE SIGNAL ;
    PORT
      LAYER M4 ;
        RECT 0.000 2.064 0.192 2.088 ;
    END
  END w_m[10]
  PIN w_m[11]
    DIRECTION INPUT ;
    USE SIGNAL ;
    PORT
      LAYER M4 ;
        RECT 129.408 1.680 129.600 1.704 ;
    END
  END w_m[11]
  PIN w_m[12]
    DIRECTION INPUT ;
    USE SIGNAL ;
    PORT
      LAYER M4 ;
        RECT 0.000 2.256 0.192 2.280 ;
    END
  END w_m[12]
  PIN w_m[13]
    DIRECTION INPUT ;
    USE SIGNAL ;
    PORT
      LAYER M4 ;
        RECT 129.408 1.776 129.600 1.800 ;
    END
  END w_m[13]
  PIN w_m[14]
    DIRECTION INPUT ;
    USE SIGNAL ;
    PORT
      LAYER M4 ;
        RECT 0.000 2.448 0.192 2.472 ;
    END
  END w_m[14]
  PIN w_m[15]
    DIRECTION INPUT ;
    USE SIGNAL ;
    PORT
      LAYER M4 ;
        RECT 129.408 1.968 129.600 1.992 ;
    END
  END w_m[15]
  PIN w_m[16]
    DIRECTION INPUT ;
    USE SIGNAL ;
    PORT
      LAYER M4 ;
        RECT 0.000 2.640 0.192 2.664 ;
    END
  END w_m[16]
  PIN w_m[17]
    DIRECTION INPUT ;
    USE SIGNAL ;
    PORT
      LAYER M4 ;
        RECT 129.408 2.112 129.600 2.136 ;
    END
  END w_m[17]
  PIN w_m[18]
    DIRECTION INPUT ;
    USE SIGNAL ;
    PORT
      LAYER M4 ;
        RECT 0.000 2.832 0.192 2.856 ;
    END
  END w_m[18]
  PIN w_m[19]
    DIRECTION INPUT ;
    USE SIGNAL ;
    PORT
      LAYER M4 ;
        RECT 129.408 2.304 129.600 2.328 ;
    END
  END w_m[19]
  PIN w_m[1]
    DIRECTION INPUT ;
    USE SIGNAL ;
    PORT
      LAYER M4 ;
        RECT 129.408 0.912 129.600 0.936 ;
    END
  END w_m[1]
  PIN w_m[20]
    DIRECTION INPUT ;
    USE SIGNAL ;
    PORT
      LAYER M4 ;
        RECT 0.000 3.024 0.192 3.048 ;
    END
  END w_m[20]
  PIN w_m[21]
    DIRECTION INPUT ;
    USE SIGNAL ;
    PORT
      LAYER M4 ;
        RECT 129.408 2.448 129.600 2.472 ;
    END
  END w_m[21]
  PIN w_m[22]
    DIRECTION INPUT ;
    USE SIGNAL ;
    PORT
      LAYER M4 ;
        RECT 0.000 3.216 0.192 3.240 ;
    END
  END w_m[22]
  PIN w_m[23]
    DIRECTION INPUT ;
    USE SIGNAL ;
    PORT
      LAYER M4 ;
        RECT 129.408 2.544 129.600 2.568 ;
    END
  END w_m[23]
  PIN w_m[24]
    DIRECTION INPUT ;
    USE SIGNAL ;
    PORT
      LAYER M4 ;
        RECT 0.000 3.408 0.192 3.432 ;
    END
  END w_m[24]
  PIN w_m[25]
    DIRECTION INPUT ;
    USE SIGNAL ;
    PORT
      LAYER M4 ;
        RECT 129.408 2.736 129.600 2.760 ;
    END
  END w_m[25]
  PIN w_m[26]
    DIRECTION INPUT ;
    USE SIGNAL ;
    PORT
      LAYER M4 ;
        RECT 0.000 3.600 0.192 3.624 ;
    END
  END w_m[26]
  PIN w_m[27]
    DIRECTION INPUT ;
    USE SIGNAL ;
    PORT
      LAYER M4 ;
        RECT 129.408 2.880 129.600 2.904 ;
    END
  END w_m[27]
  PIN w_m[28]
    DIRECTION INPUT ;
    USE SIGNAL ;
    PORT
      LAYER M4 ;
        RECT 0.000 3.840 0.192 3.864 ;
    END
  END w_m[28]
  PIN w_m[29]
    DIRECTION INPUT ;
    USE SIGNAL ;
    PORT
      LAYER M4 ;
        RECT 129.408 3.072 129.600 3.096 ;
    END
  END w_m[29]
  PIN w_m[2]
    DIRECTION INPUT ;
    USE SIGNAL ;
    PORT
      LAYER M4 ;
        RECT 0.000 1.200 0.192 1.224 ;
    END
  END w_m[2]
  PIN w_m[30]
    DIRECTION INPUT ;
    USE SIGNAL ;
    PORT
      LAYER M4 ;
        RECT 0.000 4.032 0.192 4.056 ;
    END
  END w_m[30]
  PIN w_m[31]
    DIRECTION INPUT ;
    USE SIGNAL ;
    PORT
      LAYER M4 ;
        RECT 129.408 3.216 129.600 3.240 ;
    END
  END w_m[31]
  PIN w_m[32]
    DIRECTION INPUT ;
    USE SIGNAL ;
    PORT
      LAYER M4 ;
        RECT 0.000 4.224 0.192 4.248 ;
    END
  END w_m[32]
  PIN w_m[33]
    DIRECTION INPUT ;
    USE SIGNAL ;
    PORT
      LAYER M4 ;
        RECT 129.408 3.312 129.600 3.336 ;
    END
  END w_m[33]
  PIN w_m[34]
    DIRECTION INPUT ;
    USE SIGNAL ;
    PORT
      LAYER M4 ;
        RECT 0.000 4.416 0.192 4.440 ;
    END
  END w_m[34]
  PIN w_m[35]
    DIRECTION INPUT ;
    USE SIGNAL ;
    PORT
      LAYER M4 ;
        RECT 129.408 3.504 129.600 3.528 ;
    END
  END w_m[35]
  PIN w_m[36]
    DIRECTION INPUT ;
    USE SIGNAL ;
    PORT
      LAYER M4 ;
        RECT 0.000 4.608 0.192 4.632 ;
    END
  END w_m[36]
  PIN w_m[37]
    DIRECTION INPUT ;
    USE SIGNAL ;
    PORT
      LAYER M4 ;
        RECT 129.408 3.648 129.600 3.672 ;
    END
  END w_m[37]
  PIN w_m[38]
    DIRECTION INPUT ;
    USE SIGNAL ;
    PORT
      LAYER M4 ;
        RECT 0.000 4.800 0.192 4.824 ;
    END
  END w_m[38]
  PIN w_m[39]
    DIRECTION INPUT ;
    USE SIGNAL ;
    PORT
      LAYER M4 ;
        RECT 129.408 3.840 129.600 3.864 ;
    END
  END w_m[39]
  PIN w_m[3]
    DIRECTION INPUT ;
    USE SIGNAL ;
    PORT
      LAYER M4 ;
        RECT 129.408 1.008 129.600 1.032 ;
    END
  END w_m[3]
  PIN w_m[40]
    DIRECTION INPUT ;
    USE SIGNAL ;
    PORT
      LAYER M4 ;
        RECT 0.000 4.992 0.192 5.016 ;
    END
  END w_m[40]
  PIN w_m[41]
    DIRECTION INPUT ;
    USE SIGNAL ;
    PORT
      LAYER M4 ;
        RECT 129.408 3.984 129.600 4.008 ;
    END
  END w_m[41]
  PIN w_m[42]
    DIRECTION INPUT ;
    USE SIGNAL ;
    PORT
      LAYER M4 ;
        RECT 0.000 5.184 0.192 5.208 ;
    END
  END w_m[42]
  PIN w_m[43]
    DIRECTION INPUT ;
    USE SIGNAL ;
    PORT
      LAYER M4 ;
        RECT 129.408 4.176 129.600 4.200 ;
    END
  END w_m[43]
  PIN w_m[44]
    DIRECTION INPUT ;
    USE SIGNAL ;
    PORT
      LAYER M4 ;
        RECT 0.000 5.376 0.192 5.400 ;
    END
  END w_m[44]
  PIN w_m[45]
    DIRECTION INPUT ;
    USE SIGNAL ;
    PORT
      LAYER M4 ;
        RECT 129.408 4.272 129.600 4.296 ;
    END
  END w_m[45]
  PIN w_m[46]
    DIRECTION INPUT ;
    USE SIGNAL ;
    PORT
      LAYER M4 ;
        RECT 0.000 5.568 0.192 5.592 ;
    END
  END w_m[46]
  PIN w_m[47]
    DIRECTION INPUT ;
    USE SIGNAL ;
    PORT
      LAYER M4 ;
        RECT 129.408 4.416 129.600 4.440 ;
    END
  END w_m[47]
  PIN w_m[48]
    DIRECTION INPUT ;
    USE SIGNAL ;
    PORT
      LAYER M4 ;
        RECT 0.000 5.760 0.192 5.784 ;
    END
  END w_m[48]
  PIN w_m[49]
    DIRECTION INPUT ;
    USE SIGNAL ;
    PORT
      LAYER M4 ;
        RECT 129.408 4.608 129.600 4.632 ;
    END
  END w_m[49]
  PIN w_m[4]
    DIRECTION INPUT ;
    USE SIGNAL ;
    PORT
      LAYER M4 ;
        RECT 0.000 1.488 0.192 1.512 ;
    END
  END w_m[4]
  PIN w_m[50]
    DIRECTION INPUT ;
    USE SIGNAL ;
    PORT
      LAYER M4 ;
        RECT 0.000 6.000 0.192 6.024 ;
    END
  END w_m[50]
  PIN w_m[51]
    DIRECTION INPUT ;
    USE SIGNAL ;
    PORT
      LAYER M4 ;
        RECT 129.408 4.752 129.600 4.776 ;
    END
  END w_m[51]
  PIN w_m[52]
    DIRECTION INPUT ;
    USE SIGNAL ;
    PORT
      LAYER M4 ;
        RECT 0.000 6.192 0.192 6.216 ;
    END
  END w_m[52]
  PIN w_m[53]
    DIRECTION INPUT ;
    USE SIGNAL ;
    PORT
      LAYER M4 ;
        RECT 129.408 4.944 129.600 4.968 ;
    END
  END w_m[53]
  PIN w_m[54]
    DIRECTION INPUT ;
    USE SIGNAL ;
    PORT
      LAYER M4 ;
        RECT 0.000 6.384 0.192 6.408 ;
    END
  END w_m[54]
  PIN w_m[55]
    DIRECTION INPUT ;
    USE SIGNAL ;
    PORT
      LAYER M4 ;
        RECT 129.408 5.040 129.600 5.064 ;
    END
  END w_m[55]
  PIN w_m[56]
    DIRECTION INPUT ;
    USE SIGNAL ;
    PORT
      LAYER M4 ;
        RECT 0.000 6.576 0.192 6.600 ;
    END
  END w_m[56]
  PIN w_m[57]
    DIRECTION INPUT ;
    USE SIGNAL ;
    PORT
      LAYER M4 ;
        RECT 129.408 5.232 129.600 5.256 ;
    END
  END w_m[57]
  PIN w_m[58]
    DIRECTION INPUT ;
    USE SIGNAL ;
    PORT
      LAYER M4 ;
        RECT 0.000 6.768 0.192 6.792 ;
    END
  END w_m[58]
  PIN w_m[59]
    DIRECTION INPUT ;
    USE SIGNAL ;
    PORT
      LAYER M4 ;
        RECT 129.408 5.376 129.600 5.400 ;
    END
  END w_m[59]
  PIN w_m[5]
    DIRECTION INPUT ;
    USE SIGNAL ;
    PORT
      LAYER M4 ;
        RECT 129.408 1.200 129.600 1.224 ;
    END
  END w_m[5]
  PIN w_m[60]
    DIRECTION INPUT ;
    USE SIGNAL ;
    PORT
      LAYER M4 ;
        RECT 0.000 6.960 0.192 6.984 ;
    END
  END w_m[60]
  PIN w_m[61]
    DIRECTION INPUT ;
    USE SIGNAL ;
    PORT
      LAYER M4 ;
        RECT 129.408 5.520 129.600 5.544 ;
    END
  END w_m[61]
  PIN w_m[62]
    DIRECTION INPUT ;
    USE SIGNAL ;
    PORT
      LAYER M4 ;
        RECT 0.000 7.152 0.192 7.176 ;
    END
  END w_m[62]
  PIN w_m[63]
    DIRECTION INPUT ;
    USE SIGNAL ;
    PORT
      LAYER M4 ;
        RECT 129.408 5.712 129.600 5.736 ;
    END
  END w_m[63]
  PIN w_m[6]
    DIRECTION INPUT ;
    USE SIGNAL ;
    PORT
      LAYER M4 ;
        RECT 0.000 1.680 0.192 1.704 ;
    END
  END w_m[6]
  PIN w_m[7]
    DIRECTION INPUT ;
    USE SIGNAL ;
    PORT
      LAYER M4 ;
        RECT 129.408 1.344 129.600 1.368 ;
    END
  END w_m[7]
  PIN w_m[8]
    DIRECTION INPUT ;
    USE SIGNAL ;
    PORT
      LAYER M4 ;
        RECT 0.000 1.872 0.192 1.896 ;
    END
  END w_m[8]
  PIN w_m[9]
    DIRECTION INPUT ;
    USE SIGNAL ;
    PORT
      LAYER M4 ;
        RECT 129.408 1.488 129.600 1.512 ;
    END
  END w_m[9]
  PIN w_off[0]
    DIRECTION INPUT ;
    USE SIGNAL ;
    PORT
      LAYER M4 ;
        RECT 0.000 0.432 0.192 0.456 ;
    END
  END w_off[0]
  PIN w_off[1]
    DIRECTION INPUT ;
    USE SIGNAL ;
    PORT
      LAYER M4 ;
        RECT 129.408 0.384 129.600 0.408 ;
    END
  END w_off[1]
  PIN w_off[2]
    DIRECTION INPUT ;
    USE SIGNAL ;
    PORT
      LAYER M4 ;
        RECT 0.000 0.624 0.192 0.648 ;
    END
  END w_off[2]
  PIN w_off[3]
    DIRECTION INPUT ;
    USE SIGNAL ;
    PORT
      LAYER M4 ;
        RECT 129.408 0.576 129.600 0.600 ;
    END
  END w_off[3]
  PIN w_off[4]
    DIRECTION INPUT ;
    USE SIGNAL ;
    PORT
      LAYER M4 ;
        RECT 0.000 0.816 0.192 0.840 ;
    END
  END w_off[4]
  PIN w_off[5]
    DIRECTION INPUT ;
    USE SIGNAL ;
    PORT
      LAYER M4 ;
        RECT 129.408 0.720 129.600 0.744 ;
    END
  END w_off[5]
  PIN w_v
    DIRECTION INPUT ;
    USE SIGNAL ;
    PORT
      LAYER M4 ;
        RECT 0.000 0.240 0.192 0.264 ;
    END
  END w_v
  PIN wo_ctl[0]
    DIRECTION OUTPUT ;
    USE SIGNAL ;
    PORT
      LAYER M4 ;
        RECT 0.000 61.680 0.192 61.704 ;
    END
  END wo_ctl[0]
  PIN wo_ctl[10]
    DIRECTION OUTPUT ;
    USE SIGNAL ;
    PORT
      LAYER M4 ;
        RECT 0.000 62.640 0.192 62.664 ;
    END
  END wo_ctl[10]
  PIN wo_ctl[11]
    DIRECTION OUTPUT ;
    USE SIGNAL ;
    PORT
      LAYER M4 ;
        RECT 129.408 63.984 129.600 64.008 ;
    END
  END wo_ctl[11]
  PIN wo_ctl[12]
    DIRECTION OUTPUT ;
    USE SIGNAL ;
    PORT
      LAYER M4 ;
        RECT 0.000 62.832 0.192 62.856 ;
    END
  END wo_ctl[12]
  PIN wo_ctl[13]
    DIRECTION OUTPUT ;
    USE SIGNAL ;
    PORT
      LAYER M4 ;
        RECT 129.408 64.128 129.600 64.152 ;
    END
  END wo_ctl[13]
  PIN wo_ctl[14]
    DIRECTION OUTPUT ;
    USE SIGNAL ;
    PORT
      LAYER M4 ;
        RECT 0.000 63.024 0.192 63.048 ;
    END
  END wo_ctl[14]
  PIN wo_ctl[15]
    DIRECTION OUTPUT ;
    USE SIGNAL ;
    PORT
      LAYER M4 ;
        RECT 129.408 64.320 129.600 64.344 ;
    END
  END wo_ctl[15]
  PIN wo_ctl[16]
    DIRECTION OUTPUT ;
    USE SIGNAL ;
    PORT
      LAYER M4 ;
        RECT 0.000 63.312 0.192 63.336 ;
    END
  END wo_ctl[16]
  PIN wo_ctl[17]
    DIRECTION OUTPUT ;
    USE SIGNAL ;
    PORT
      LAYER M4 ;
        RECT 129.408 64.464 129.600 64.488 ;
    END
  END wo_ctl[17]
  PIN wo_ctl[18]
    DIRECTION OUTPUT ;
    USE SIGNAL ;
    PORT
      LAYER M4 ;
        RECT 0.000 63.504 0.192 63.528 ;
    END
  END wo_ctl[18]
  PIN wo_ctl[19]
    DIRECTION OUTPUT ;
    USE SIGNAL ;
    PORT
      LAYER M4 ;
        RECT 129.408 64.656 129.600 64.680 ;
    END
  END wo_ctl[19]
  PIN wo_ctl[1]
    DIRECTION OUTPUT ;
    USE SIGNAL ;
    PORT
      LAYER M4 ;
        RECT 129.408 63.216 129.600 63.240 ;
    END
  END wo_ctl[1]
  PIN wo_ctl[20]
    DIRECTION OUTPUT ;
    USE SIGNAL ;
    PORT
      LAYER M4 ;
        RECT 0.000 63.696 0.192 63.720 ;
    END
  END wo_ctl[20]
  PIN wo_ctl[21]
    DIRECTION OUTPUT ;
    USE SIGNAL ;
    PORT
      LAYER M4 ;
        RECT 129.408 64.752 129.600 64.776 ;
    END
  END wo_ctl[21]
  PIN wo_ctl[22]
    DIRECTION OUTPUT ;
    USE SIGNAL ;
    PORT
      LAYER M4 ;
        RECT 0.000 63.888 0.192 63.912 ;
    END
  END wo_ctl[22]
  PIN wo_ctl[23]
    DIRECTION OUTPUT ;
    USE SIGNAL ;
    PORT
      LAYER M4 ;
        RECT 129.408 64.896 129.600 64.920 ;
    END
  END wo_ctl[23]
  PIN wo_ctl[24]
    DIRECTION OUTPUT ;
    USE SIGNAL ;
    PORT
      LAYER M4 ;
        RECT 0.000 64.080 0.192 64.104 ;
    END
  END wo_ctl[24]
  PIN wo_ctl[25]
    DIRECTION OUTPUT ;
    USE SIGNAL ;
    PORT
      LAYER M4 ;
        RECT 129.408 65.088 129.600 65.112 ;
    END
  END wo_ctl[25]
  PIN wo_ctl[26]
    DIRECTION OUTPUT ;
    USE SIGNAL ;
    PORT
      LAYER M4 ;
        RECT 0.000 64.272 0.192 64.296 ;
    END
  END wo_ctl[26]
  PIN wo_ctl[27]
    DIRECTION OUTPUT ;
    USE SIGNAL ;
    PORT
      LAYER M4 ;
        RECT 129.408 65.232 129.600 65.256 ;
    END
  END wo_ctl[27]
  PIN wo_ctl[28]
    DIRECTION OUTPUT ;
    USE SIGNAL ;
    PORT
      LAYER M4 ;
        RECT 0.000 64.464 0.192 64.488 ;
    END
  END wo_ctl[28]
  PIN wo_ctl[29]
    DIRECTION OUTPUT ;
    USE SIGNAL ;
    PORT
      LAYER M4 ;
        RECT 129.408 65.424 129.600 65.448 ;
    END
  END wo_ctl[29]
  PIN wo_ctl[2]
    DIRECTION OUTPUT ;
    USE SIGNAL ;
    PORT
      LAYER M4 ;
        RECT 0.000 61.872 0.192 61.896 ;
    END
  END wo_ctl[2]
  PIN wo_ctl[30]
    DIRECTION OUTPUT ;
    USE SIGNAL ;
    PORT
      LAYER M4 ;
        RECT 0.000 64.656 0.192 64.680 ;
    END
  END wo_ctl[30]
  PIN wo_ctl[31]
    DIRECTION OUTPUT ;
    USE SIGNAL ;
    PORT
      LAYER M4 ;
        RECT 129.408 65.520 129.600 65.544 ;
    END
  END wo_ctl[31]
  PIN wo_ctl[32]
    DIRECTION OUTPUT ;
    USE SIGNAL ;
    PORT
      LAYER M4 ;
        RECT 0.000 64.848 0.192 64.872 ;
    END
  END wo_ctl[32]
  PIN wo_ctl[33]
    DIRECTION OUTPUT ;
    USE SIGNAL ;
    PORT
      LAYER M4 ;
        RECT 129.408 65.712 129.600 65.736 ;
    END
  END wo_ctl[33]
  PIN wo_ctl[34]
    DIRECTION OUTPUT ;
    USE SIGNAL ;
    PORT
      LAYER M4 ;
        RECT 0.000 65.040 0.192 65.064 ;
    END
  END wo_ctl[34]
  PIN wo_ctl[35]
    DIRECTION OUTPUT ;
    USE SIGNAL ;
    PORT
      LAYER M4 ;
        RECT 129.408 65.856 129.600 65.880 ;
    END
  END wo_ctl[35]
  PIN wo_ctl[36]
    DIRECTION OUTPUT ;
    USE SIGNAL ;
    PORT
      LAYER M4 ;
        RECT 0.000 65.232 0.192 65.256 ;
    END
  END wo_ctl[36]
  PIN wo_ctl[37]
    DIRECTION OUTPUT ;
    USE SIGNAL ;
    PORT
      LAYER M4 ;
        RECT 129.408 66.000 129.600 66.024 ;
    END
  END wo_ctl[37]
  PIN wo_ctl[38]
    DIRECTION OUTPUT ;
    USE SIGNAL ;
    PORT
      LAYER M4 ;
        RECT 0.000 65.472 0.192 65.496 ;
    END
  END wo_ctl[38]
  PIN wo_ctl[39]
    DIRECTION OUTPUT ;
    USE SIGNAL ;
    PORT
      LAYER M4 ;
        RECT 129.408 66.192 129.600 66.216 ;
    END
  END wo_ctl[39]
  PIN wo_ctl[3]
    DIRECTION OUTPUT ;
    USE SIGNAL ;
    PORT
      LAYER M4 ;
        RECT 129.408 63.360 129.600 63.384 ;
    END
  END wo_ctl[3]
  PIN wo_ctl[40]
    DIRECTION OUTPUT ;
    USE SIGNAL ;
    PORT
      LAYER M4 ;
        RECT 0.000 65.664 0.192 65.688 ;
    END
  END wo_ctl[40]
  PIN wo_ctl[41]
    DIRECTION OUTPUT ;
    USE SIGNAL ;
    PORT
      LAYER M4 ;
        RECT 129.408 66.288 129.600 66.312 ;
    END
  END wo_ctl[41]
  PIN wo_ctl[42]
    DIRECTION OUTPUT ;
    USE SIGNAL ;
    PORT
      LAYER M4 ;
        RECT 0.000 65.856 0.192 65.880 ;
    END
  END wo_ctl[42]
  PIN wo_ctl[43]
    DIRECTION OUTPUT ;
    USE SIGNAL ;
    PORT
      LAYER M4 ;
        RECT 129.408 66.480 129.600 66.504 ;
    END
  END wo_ctl[43]
  PIN wo_ctl[44]
    DIRECTION OUTPUT ;
    USE SIGNAL ;
    PORT
      LAYER M4 ;
        RECT 0.000 66.048 0.192 66.072 ;
    END
  END wo_ctl[44]
  PIN wo_ctl[45]
    DIRECTION OUTPUT ;
    USE SIGNAL ;
    PORT
      LAYER M4 ;
        RECT 129.408 66.624 129.600 66.648 ;
    END
  END wo_ctl[45]
  PIN wo_ctl[46]
    DIRECTION OUTPUT ;
    USE SIGNAL ;
    PORT
      LAYER M4 ;
        RECT 0.000 66.240 0.192 66.264 ;
    END
  END wo_ctl[46]
  PIN wo_ctl[47]
    DIRECTION OUTPUT ;
    USE SIGNAL ;
    PORT
      LAYER M4 ;
        RECT 129.408 66.816 129.600 66.840 ;
    END
  END wo_ctl[47]
  PIN wo_ctl[48]
    DIRECTION OUTPUT ;
    USE SIGNAL ;
    PORT
      LAYER M4 ;
        RECT 0.000 66.432 0.192 66.456 ;
    END
  END wo_ctl[48]
  PIN wo_ctl[49]
    DIRECTION OUTPUT ;
    USE SIGNAL ;
    PORT
      LAYER M4 ;
        RECT 129.408 66.960 129.600 66.984 ;
    END
  END wo_ctl[49]
  PIN wo_ctl[4]
    DIRECTION OUTPUT ;
    USE SIGNAL ;
    PORT
      LAYER M4 ;
        RECT 0.000 62.064 0.192 62.088 ;
    END
  END wo_ctl[4]
  PIN wo_ctl[50]
    DIRECTION OUTPUT ;
    USE SIGNAL ;
    PORT
      LAYER M4 ;
        RECT 0.000 66.624 0.192 66.648 ;
    END
  END wo_ctl[50]
  PIN wo_ctl[51]
    DIRECTION OUTPUT ;
    USE SIGNAL ;
    PORT
      LAYER M4 ;
        RECT 129.408 67.056 129.600 67.080 ;
    END
  END wo_ctl[51]
  PIN wo_ctl[52]
    DIRECTION OUTPUT ;
    USE SIGNAL ;
    PORT
      LAYER M4 ;
        RECT 0.000 66.816 0.192 66.840 ;
    END
  END wo_ctl[52]
  PIN wo_ctl[53]
    DIRECTION OUTPUT ;
    USE SIGNAL ;
    PORT
      LAYER M4 ;
        RECT 129.408 67.248 129.600 67.272 ;
    END
  END wo_ctl[53]
  PIN wo_ctl[54]
    DIRECTION OUTPUT ;
    USE SIGNAL ;
    PORT
      LAYER M4 ;
        RECT 0.000 67.008 0.192 67.032 ;
    END
  END wo_ctl[54]
  PIN wo_ctl[55]
    DIRECTION OUTPUT ;
    USE SIGNAL ;
    PORT
      LAYER M4 ;
        RECT 129.408 67.392 129.600 67.416 ;
    END
  END wo_ctl[55]
  PIN wo_ctl[56]
    DIRECTION OUTPUT ;
    USE SIGNAL ;
    PORT
      LAYER M4 ;
        RECT 0.000 67.200 0.192 67.224 ;
    END
  END wo_ctl[56]
  PIN wo_ctl[57]
    DIRECTION OUTPUT ;
    USE SIGNAL ;
    PORT
      LAYER M4 ;
        RECT 129.408 67.584 129.600 67.608 ;
    END
  END wo_ctl[57]
  PIN wo_ctl[58]
    DIRECTION OUTPUT ;
    USE SIGNAL ;
    PORT
      LAYER M4 ;
        RECT 0.000 67.392 0.192 67.416 ;
    END
  END wo_ctl[58]
  PIN wo_ctl[59]
    DIRECTION OUTPUT ;
    USE SIGNAL ;
    PORT
      LAYER M4 ;
        RECT 129.408 67.728 129.600 67.752 ;
    END
  END wo_ctl[59]
  PIN wo_ctl[5]
    DIRECTION OUTPUT ;
    USE SIGNAL ;
    PORT
      LAYER M4 ;
        RECT 129.408 63.552 129.600 63.576 ;
    END
  END wo_ctl[5]
  PIN wo_ctl[60]
    DIRECTION OUTPUT ;
    USE SIGNAL ;
    PORT
      LAYER M4 ;
        RECT 0.000 67.584 0.192 67.608 ;
    END
  END wo_ctl[60]
  PIN wo_ctl[61]
    DIRECTION OUTPUT ;
    USE SIGNAL ;
    PORT
      LAYER M4 ;
        RECT 129.408 67.824 129.600 67.848 ;
    END
  END wo_ctl[61]
  PIN wo_ctl[62]
    DIRECTION OUTPUT ;
    USE SIGNAL ;
    PORT
      LAYER M4 ;
        RECT 0.000 67.824 0.192 67.848 ;
    END
  END wo_ctl[62]
  PIN wo_ctl[63]
    DIRECTION OUTPUT ;
    USE SIGNAL ;
    PORT
      LAYER M4 ;
        RECT 129.408 68.016 129.600 68.040 ;
    END
  END wo_ctl[63]
  PIN wo_ctl[64]
    DIRECTION OUTPUT ;
    USE SIGNAL ;
    PORT
      LAYER M4 ;
        RECT 0.000 68.016 0.192 68.040 ;
    END
  END wo_ctl[64]
  PIN wo_ctl[65]
    DIRECTION OUTPUT ;
    USE SIGNAL ;
    PORT
      LAYER M4 ;
        RECT 129.408 68.160 129.600 68.184 ;
    END
  END wo_ctl[65]
  PIN wo_ctl[66]
    DIRECTION OUTPUT ;
    USE SIGNAL ;
    PORT
      LAYER M4 ;
        RECT 0.000 68.208 0.192 68.232 ;
    END
  END wo_ctl[66]
  PIN wo_ctl[67]
    DIRECTION OUTPUT ;
    USE SIGNAL ;
    PORT
      LAYER M4 ;
        RECT 129.408 68.352 129.600 68.376 ;
    END
  END wo_ctl[67]
  PIN wo_ctl[68]
    DIRECTION OUTPUT ;
    USE SIGNAL ;
    PORT
      LAYER M4 ;
        RECT 0.000 68.400 0.192 68.424 ;
    END
  END wo_ctl[68]
  PIN wo_ctl[69]
    DIRECTION OUTPUT ;
    USE SIGNAL ;
    PORT
      LAYER M4 ;
        RECT 129.408 68.496 129.600 68.520 ;
    END
  END wo_ctl[69]
  PIN wo_ctl[6]
    DIRECTION OUTPUT ;
    USE SIGNAL ;
    PORT
      LAYER M4 ;
        RECT 0.000 62.256 0.192 62.280 ;
    END
  END wo_ctl[6]
  PIN wo_ctl[70]
    DIRECTION OUTPUT ;
    USE SIGNAL ;
    PORT
      LAYER M4 ;
        RECT 0.000 68.592 0.192 68.616 ;
    END
  END wo_ctl[70]
  PIN wo_ctl[71]
    DIRECTION OUTPUT ;
    USE SIGNAL ;
    PORT
      LAYER M4 ;
        RECT 129.408 68.688 129.600 68.712 ;
    END
  END wo_ctl[71]
  PIN wo_ctl[7]
    DIRECTION OUTPUT ;
    USE SIGNAL ;
    PORT
      LAYER M4 ;
        RECT 129.408 63.696 129.600 63.720 ;
    END
  END wo_ctl[7]
  PIN wo_ctl[8]
    DIRECTION OUTPUT ;
    USE SIGNAL ;
    PORT
      LAYER M4 ;
        RECT 0.000 62.448 0.192 62.472 ;
    END
  END wo_ctl[8]
  PIN wo_ctl[9]
    DIRECTION OUTPUT ;
    USE SIGNAL ;
    PORT
      LAYER M4 ;
        RECT 129.408 63.792 129.600 63.816 ;
    END
  END wo_ctl[9]
  PIN wo_d[0]
    DIRECTION OUTPUT ;
    USE SIGNAL ;
    PORT
      LAYER M4 ;
        RECT 0.000 41.904 0.192 41.928 ;
    END
  END wo_d[0]
  PIN wo_d[1000]
    DIRECTION OUTPUT ;
    USE SIGNAL ;
    PORT
      LAYER M3 ;
        RECT 125.280 69.082 125.298 69.120 ;
    END
  END wo_d[1000]
  PIN wo_d[1001]
    DIRECTION OUTPUT ;
    USE SIGNAL ;
    PORT
      LAYER M3 ;
        RECT 125.424 69.082 125.442 69.120 ;
    END
  END wo_d[1001]
  PIN wo_d[1002]
    DIRECTION OUTPUT ;
    USE SIGNAL ;
    PORT
      LAYER M3 ;
        RECT 125.568 69.082 125.586 69.120 ;
    END
  END wo_d[1002]
  PIN wo_d[1003]
    DIRECTION OUTPUT ;
    USE SIGNAL ;
    PORT
      LAYER M3 ;
        RECT 125.712 69.082 125.730 69.120 ;
    END
  END wo_d[1003]
  PIN wo_d[1004]
    DIRECTION OUTPUT ;
    USE SIGNAL ;
    PORT
      LAYER M5 ;
        RECT 125.856 69.036 125.880 69.120 ;
    END
  END wo_d[1004]
  PIN wo_d[1005]
    DIRECTION OUTPUT ;
    USE SIGNAL ;
    PORT
      LAYER M3 ;
        RECT 126.000 69.082 126.018 69.120 ;
    END
  END wo_d[1005]
  PIN wo_d[1006]
    DIRECTION OUTPUT ;
    USE SIGNAL ;
    PORT
      LAYER M5 ;
        RECT 126.144 69.036 126.168 69.120 ;
    END
  END wo_d[1006]
  PIN wo_d[1007]
    DIRECTION OUTPUT ;
    USE SIGNAL ;
    PORT
      LAYER M5 ;
        RECT 126.336 69.036 126.360 69.120 ;
    END
  END wo_d[1007]
  PIN wo_d[1008]
    DIRECTION OUTPUT ;
    USE SIGNAL ;
    PORT
      LAYER M5 ;
        RECT 126.432 69.036 126.456 69.120 ;
    END
  END wo_d[1008]
  PIN wo_d[1009]
    DIRECTION OUTPUT ;
    USE SIGNAL ;
    PORT
      LAYER M3 ;
        RECT 126.648 69.082 126.666 69.120 ;
    END
  END wo_d[1009]
  PIN wo_d[100]
    DIRECTION OUTPUT ;
    USE SIGNAL ;
    PORT
      LAYER M4 ;
        RECT 0.000 51.840 0.192 51.864 ;
    END
  END wo_d[100]
  PIN wo_d[1010]
    DIRECTION OUTPUT ;
    USE SIGNAL ;
    PORT
      LAYER M3 ;
        RECT 126.864 69.082 126.882 69.120 ;
    END
  END wo_d[1010]
  PIN wo_d[1011]
    DIRECTION OUTPUT ;
    USE SIGNAL ;
    PORT
      LAYER M3 ;
        RECT 127.080 69.082 127.098 69.120 ;
    END
  END wo_d[1011]
  PIN wo_d[1012]
    DIRECTION OUTPUT ;
    USE SIGNAL ;
    PORT
      LAYER M3 ;
        RECT 127.224 69.082 127.242 69.120 ;
    END
  END wo_d[1012]
  PIN wo_d[1013]
    DIRECTION OUTPUT ;
    USE SIGNAL ;
    PORT
      LAYER M3 ;
        RECT 127.368 69.082 127.386 69.120 ;
    END
  END wo_d[1013]
  PIN wo_d[1014]
    DIRECTION OUTPUT ;
    USE SIGNAL ;
    PORT
      LAYER M3 ;
        RECT 127.512 69.082 127.530 69.120 ;
    END
  END wo_d[1014]
  PIN wo_d[1015]
    DIRECTION OUTPUT ;
    USE SIGNAL ;
    PORT
      LAYER M5 ;
        RECT 127.680 69.036 127.704 69.120 ;
    END
  END wo_d[1015]
  PIN wo_d[1016]
    DIRECTION OUTPUT ;
    USE SIGNAL ;
    PORT
      LAYER M3 ;
        RECT 127.800 69.082 127.818 69.120 ;
    END
  END wo_d[1016]
  PIN wo_d[1017]
    DIRECTION OUTPUT ;
    USE SIGNAL ;
    PORT
      LAYER M5 ;
        RECT 127.968 69.036 127.992 69.120 ;
    END
  END wo_d[1017]
  PIN wo_d[1018]
    DIRECTION OUTPUT ;
    USE SIGNAL ;
    PORT
      LAYER M3 ;
        RECT 128.160 69.082 128.178 69.120 ;
    END
  END wo_d[1018]
  PIN wo_d[1019]
    DIRECTION OUTPUT ;
    USE SIGNAL ;
    PORT
      LAYER M5 ;
        RECT 128.256 69.036 128.280 69.120 ;
    END
  END wo_d[1019]
  PIN wo_d[101]
    DIRECTION OUTPUT ;
    USE SIGNAL ;
    PORT
      LAYER M4 ;
        RECT 129.408 55.488 129.600 55.512 ;
    END
  END wo_d[101]
  PIN wo_d[1020]
    DIRECTION OUTPUT ;
    USE SIGNAL ;
    PORT
      LAYER M3 ;
        RECT 128.448 69.082 128.466 69.120 ;
    END
  END wo_d[1020]
  PIN wo_d[1021]
    DIRECTION OUTPUT ;
    USE SIGNAL ;
    PORT
      LAYER M5 ;
        RECT 128.544 69.036 128.568 69.120 ;
    END
  END wo_d[1021]
  PIN wo_d[1022]
    DIRECTION OUTPUT ;
    USE SIGNAL ;
    PORT
      LAYER M3 ;
        RECT 128.736 69.082 128.754 69.120 ;
    END
  END wo_d[1022]
  PIN wo_d[1023]
    DIRECTION OUTPUT ;
    USE SIGNAL ;
    PORT
      LAYER M3 ;
        RECT 128.880 69.082 128.898 69.120 ;
    END
  END wo_d[1023]
  PIN wo_d[102]
    DIRECTION OUTPUT ;
    USE SIGNAL ;
    PORT
      LAYER M4 ;
        RECT 0.000 52.032 0.192 52.056 ;
    END
  END wo_d[102]
  PIN wo_d[103]
    DIRECTION OUTPUT ;
    USE SIGNAL ;
    PORT
      LAYER M4 ;
        RECT 129.408 55.632 129.600 55.656 ;
    END
  END wo_d[103]
  PIN wo_d[104]
    DIRECTION OUTPUT ;
    USE SIGNAL ;
    PORT
      LAYER M4 ;
        RECT 0.000 52.224 0.192 52.248 ;
    END
  END wo_d[104]
  PIN wo_d[105]
    DIRECTION OUTPUT ;
    USE SIGNAL ;
    PORT
      LAYER M4 ;
        RECT 129.408 55.728 129.600 55.752 ;
    END
  END wo_d[105]
  PIN wo_d[106]
    DIRECTION OUTPUT ;
    USE SIGNAL ;
    PORT
      LAYER M4 ;
        RECT 0.000 52.416 0.192 52.440 ;
    END
  END wo_d[106]
  PIN wo_d[107]
    DIRECTION OUTPUT ;
    USE SIGNAL ;
    PORT
      LAYER M4 ;
        RECT 129.408 55.920 129.600 55.944 ;
    END
  END wo_d[107]
  PIN wo_d[108]
    DIRECTION OUTPUT ;
    USE SIGNAL ;
    PORT
      LAYER M4 ;
        RECT 0.000 52.608 0.192 52.632 ;
    END
  END wo_d[108]
  PIN wo_d[109]
    DIRECTION OUTPUT ;
    USE SIGNAL ;
    PORT
      LAYER M4 ;
        RECT 129.408 56.064 129.600 56.088 ;
    END
  END wo_d[109]
  PIN wo_d[10]
    DIRECTION OUTPUT ;
    USE SIGNAL ;
    PORT
      LAYER M4 ;
        RECT 0.000 42.960 0.192 42.984 ;
    END
  END wo_d[10]
  PIN wo_d[110]
    DIRECTION OUTPUT ;
    USE SIGNAL ;
    PORT
      LAYER M4 ;
        RECT 0.000 52.800 0.192 52.824 ;
    END
  END wo_d[110]
  PIN wo_d[111]
    DIRECTION OUTPUT ;
    USE SIGNAL ;
    PORT
      LAYER M4 ;
        RECT 129.408 56.256 129.600 56.280 ;
    END
  END wo_d[111]
  PIN wo_d[112]
    DIRECTION OUTPUT ;
    USE SIGNAL ;
    PORT
      LAYER M4 ;
        RECT 0.000 52.992 0.192 53.016 ;
    END
  END wo_d[112]
  PIN wo_d[113]
    DIRECTION OUTPUT ;
    USE SIGNAL ;
    PORT
      LAYER M4 ;
        RECT 129.408 56.400 129.600 56.424 ;
    END
  END wo_d[113]
  PIN wo_d[114]
    DIRECTION OUTPUT ;
    USE SIGNAL ;
    PORT
      LAYER M4 ;
        RECT 0.000 53.184 0.192 53.208 ;
    END
  END wo_d[114]
  PIN wo_d[115]
    DIRECTION OUTPUT ;
    USE SIGNAL ;
    PORT
      LAYER M4 ;
        RECT 129.408 56.592 129.600 56.616 ;
    END
  END wo_d[115]
  PIN wo_d[116]
    DIRECTION OUTPUT ;
    USE SIGNAL ;
    PORT
      LAYER M4 ;
        RECT 0.000 53.376 0.192 53.400 ;
    END
  END wo_d[116]
  PIN wo_d[117]
    DIRECTION OUTPUT ;
    USE SIGNAL ;
    PORT
      LAYER M4 ;
        RECT 129.408 56.688 129.600 56.712 ;
    END
  END wo_d[117]
  PIN wo_d[118]
    DIRECTION OUTPUT ;
    USE SIGNAL ;
    PORT
      LAYER M4 ;
        RECT 0.000 53.568 0.192 53.592 ;
    END
  END wo_d[118]
  PIN wo_d[119]
    DIRECTION OUTPUT ;
    USE SIGNAL ;
    PORT
      LAYER M4 ;
        RECT 129.408 56.832 129.600 56.856 ;
    END
  END wo_d[119]
  PIN wo_d[11]
    DIRECTION OUTPUT ;
    USE SIGNAL ;
    PORT
      LAYER M4 ;
        RECT 129.408 48.528 129.600 48.552 ;
    END
  END wo_d[11]
  PIN wo_d[120]
    DIRECTION OUTPUT ;
    USE SIGNAL ;
    PORT
      LAYER M4 ;
        RECT 0.000 53.760 0.192 53.784 ;
    END
  END wo_d[120]
  PIN wo_d[121]
    DIRECTION OUTPUT ;
    USE SIGNAL ;
    PORT
      LAYER M4 ;
        RECT 129.408 57.024 129.600 57.048 ;
    END
  END wo_d[121]
  PIN wo_d[122]
    DIRECTION OUTPUT ;
    USE SIGNAL ;
    PORT
      LAYER M4 ;
        RECT 0.000 54.000 0.192 54.024 ;
    END
  END wo_d[122]
  PIN wo_d[123]
    DIRECTION OUTPUT ;
    USE SIGNAL ;
    PORT
      LAYER M4 ;
        RECT 129.408 57.168 129.600 57.192 ;
    END
  END wo_d[123]
  PIN wo_d[124]
    DIRECTION OUTPUT ;
    USE SIGNAL ;
    PORT
      LAYER M4 ;
        RECT 0.000 54.192 0.192 54.216 ;
    END
  END wo_d[124]
  PIN wo_d[125]
    DIRECTION OUTPUT ;
    USE SIGNAL ;
    PORT
      LAYER M4 ;
        RECT 129.408 57.360 129.600 57.384 ;
    END
  END wo_d[125]
  PIN wo_d[126]
    DIRECTION OUTPUT ;
    USE SIGNAL ;
    PORT
      LAYER M4 ;
        RECT 0.000 54.384 0.192 54.408 ;
    END
  END wo_d[126]
  PIN wo_d[127]
    DIRECTION OUTPUT ;
    USE SIGNAL ;
    PORT
      LAYER M4 ;
        RECT 129.408 57.456 129.600 57.480 ;
    END
  END wo_d[127]
  PIN wo_d[128]
    DIRECTION OUTPUT ;
    USE SIGNAL ;
    PORT
      LAYER M4 ;
        RECT 0.000 54.576 0.192 54.600 ;
    END
  END wo_d[128]
  PIN wo_d[129]
    DIRECTION OUTPUT ;
    USE SIGNAL ;
    PORT
      LAYER M4 ;
        RECT 129.408 57.648 129.600 57.672 ;
    END
  END wo_d[129]
  PIN wo_d[12]
    DIRECTION OUTPUT ;
    USE SIGNAL ;
    PORT
      LAYER M4 ;
        RECT 0.000 43.152 0.192 43.176 ;
    END
  END wo_d[12]
  PIN wo_d[130]
    DIRECTION OUTPUT ;
    USE SIGNAL ;
    PORT
      LAYER M4 ;
        RECT 0.000 54.768 0.192 54.792 ;
    END
  END wo_d[130]
  PIN wo_d[131]
    DIRECTION OUTPUT ;
    USE SIGNAL ;
    PORT
      LAYER M4 ;
        RECT 129.408 57.792 129.600 57.816 ;
    END
  END wo_d[131]
  PIN wo_d[132]
    DIRECTION OUTPUT ;
    USE SIGNAL ;
    PORT
      LAYER M4 ;
        RECT 0.000 54.960 0.192 54.984 ;
    END
  END wo_d[132]
  PIN wo_d[133]
    DIRECTION OUTPUT ;
    USE SIGNAL ;
    PORT
      LAYER M4 ;
        RECT 129.408 57.936 129.600 57.960 ;
    END
  END wo_d[133]
  PIN wo_d[134]
    DIRECTION OUTPUT ;
    USE SIGNAL ;
    PORT
      LAYER M4 ;
        RECT 0.000 55.152 0.192 55.176 ;
    END
  END wo_d[134]
  PIN wo_d[135]
    DIRECTION OUTPUT ;
    USE SIGNAL ;
    PORT
      LAYER M4 ;
        RECT 129.408 58.128 129.600 58.152 ;
    END
  END wo_d[135]
  PIN wo_d[136]
    DIRECTION OUTPUT ;
    USE SIGNAL ;
    PORT
      LAYER M4 ;
        RECT 0.000 55.344 0.192 55.368 ;
    END
  END wo_d[136]
  PIN wo_d[137]
    DIRECTION OUTPUT ;
    USE SIGNAL ;
    PORT
      LAYER M4 ;
        RECT 129.408 58.224 129.600 58.248 ;
    END
  END wo_d[137]
  PIN wo_d[138]
    DIRECTION OUTPUT ;
    USE SIGNAL ;
    PORT
      LAYER M4 ;
        RECT 0.000 55.536 0.192 55.560 ;
    END
  END wo_d[138]
  PIN wo_d[139]
    DIRECTION OUTPUT ;
    USE SIGNAL ;
    PORT
      LAYER M4 ;
        RECT 129.408 58.416 129.600 58.440 ;
    END
  END wo_d[139]
  PIN wo_d[13]
    DIRECTION OUTPUT ;
    USE SIGNAL ;
    PORT
      LAYER M4 ;
        RECT 129.408 48.624 129.600 48.648 ;
    END
  END wo_d[13]
  PIN wo_d[140]
    DIRECTION OUTPUT ;
    USE SIGNAL ;
    PORT
      LAYER M4 ;
        RECT 0.000 55.728 0.192 55.752 ;
    END
  END wo_d[140]
  PIN wo_d[141]
    DIRECTION OUTPUT ;
    USE SIGNAL ;
    PORT
      LAYER M4 ;
        RECT 129.408 58.560 129.600 58.584 ;
    END
  END wo_d[141]
  PIN wo_d[142]
    DIRECTION OUTPUT ;
    USE SIGNAL ;
    PORT
      LAYER M4 ;
        RECT 0.000 55.920 0.192 55.944 ;
    END
  END wo_d[142]
  PIN wo_d[143]
    DIRECTION OUTPUT ;
    USE SIGNAL ;
    PORT
      LAYER M4 ;
        RECT 129.408 58.752 129.600 58.776 ;
    END
  END wo_d[143]
  PIN wo_d[144]
    DIRECTION OUTPUT ;
    USE SIGNAL ;
    PORT
      LAYER M4 ;
        RECT 0.000 56.112 0.192 56.136 ;
    END
  END wo_d[144]
  PIN wo_d[145]
    DIRECTION OUTPUT ;
    USE SIGNAL ;
    PORT
      LAYER M4 ;
        RECT 129.408 58.896 129.600 58.920 ;
    END
  END wo_d[145]
  PIN wo_d[146]
    DIRECTION OUTPUT ;
    USE SIGNAL ;
    PORT
      LAYER M4 ;
        RECT 0.000 56.400 0.192 56.424 ;
    END
  END wo_d[146]
  PIN wo_d[147]
    DIRECTION OUTPUT ;
    USE SIGNAL ;
    PORT
      LAYER M4 ;
        RECT 129.408 58.992 129.600 59.016 ;
    END
  END wo_d[147]
  PIN wo_d[148]
    DIRECTION OUTPUT ;
    USE SIGNAL ;
    PORT
      LAYER M4 ;
        RECT 0.000 56.592 0.192 56.616 ;
    END
  END wo_d[148]
  PIN wo_d[149]
    DIRECTION OUTPUT ;
    USE SIGNAL ;
    PORT
      LAYER M4 ;
        RECT 129.408 59.184 129.600 59.208 ;
    END
  END wo_d[149]
  PIN wo_d[14]
    DIRECTION OUTPUT ;
    USE SIGNAL ;
    PORT
      LAYER M4 ;
        RECT 0.000 43.344 0.192 43.368 ;
    END
  END wo_d[14]
  PIN wo_d[150]
    DIRECTION OUTPUT ;
    USE SIGNAL ;
    PORT
      LAYER M4 ;
        RECT 0.000 56.784 0.192 56.808 ;
    END
  END wo_d[150]
  PIN wo_d[151]
    DIRECTION OUTPUT ;
    USE SIGNAL ;
    PORT
      LAYER M4 ;
        RECT 129.408 59.328 129.600 59.352 ;
    END
  END wo_d[151]
  PIN wo_d[152]
    DIRECTION OUTPUT ;
    USE SIGNAL ;
    PORT
      LAYER M4 ;
        RECT 0.000 56.976 0.192 57.000 ;
    END
  END wo_d[152]
  PIN wo_d[153]
    DIRECTION OUTPUT ;
    USE SIGNAL ;
    PORT
      LAYER M4 ;
        RECT 129.408 59.520 129.600 59.544 ;
    END
  END wo_d[153]
  PIN wo_d[154]
    DIRECTION OUTPUT ;
    USE SIGNAL ;
    PORT
      LAYER M4 ;
        RECT 0.000 57.168 0.192 57.192 ;
    END
  END wo_d[154]
  PIN wo_d[155]
    DIRECTION OUTPUT ;
    USE SIGNAL ;
    PORT
      LAYER M4 ;
        RECT 129.408 59.664 129.600 59.688 ;
    END
  END wo_d[155]
  PIN wo_d[156]
    DIRECTION OUTPUT ;
    USE SIGNAL ;
    PORT
      LAYER M4 ;
        RECT 0.000 57.360 0.192 57.384 ;
    END
  END wo_d[156]
  PIN wo_d[157]
    DIRECTION OUTPUT ;
    USE SIGNAL ;
    PORT
      LAYER M4 ;
        RECT 129.408 59.760 129.600 59.784 ;
    END
  END wo_d[157]
  PIN wo_d[158]
    DIRECTION OUTPUT ;
    USE SIGNAL ;
    PORT
      LAYER M4 ;
        RECT 0.000 57.552 0.192 57.576 ;
    END
  END wo_d[158]
  PIN wo_d[159]
    DIRECTION OUTPUT ;
    USE SIGNAL ;
    PORT
      LAYER M4 ;
        RECT 129.408 59.952 129.600 59.976 ;
    END
  END wo_d[159]
  PIN wo_d[15]
    DIRECTION OUTPUT ;
    USE SIGNAL ;
    PORT
      LAYER M4 ;
        RECT 129.408 48.768 129.600 48.792 ;
    END
  END wo_d[15]
  PIN wo_d[160]
    DIRECTION OUTPUT ;
    USE SIGNAL ;
    PORT
      LAYER M4 ;
        RECT 0.000 57.744 0.192 57.768 ;
    END
  END wo_d[160]
  PIN wo_d[161]
    DIRECTION OUTPUT ;
    USE SIGNAL ;
    PORT
      LAYER M4 ;
        RECT 129.408 60.096 129.600 60.120 ;
    END
  END wo_d[161]
  PIN wo_d[162]
    DIRECTION OUTPUT ;
    USE SIGNAL ;
    PORT
      LAYER M4 ;
        RECT 0.000 57.936 0.192 57.960 ;
    END
  END wo_d[162]
  PIN wo_d[163]
    DIRECTION OUTPUT ;
    USE SIGNAL ;
    PORT
      LAYER M4 ;
        RECT 129.408 60.288 129.600 60.312 ;
    END
  END wo_d[163]
  PIN wo_d[164]
    DIRECTION OUTPUT ;
    USE SIGNAL ;
    PORT
      LAYER M4 ;
        RECT 0.000 58.128 0.192 58.152 ;
    END
  END wo_d[164]
  PIN wo_d[165]
    DIRECTION OUTPUT ;
    USE SIGNAL ;
    PORT
      LAYER M4 ;
        RECT 129.408 60.432 129.600 60.456 ;
    END
  END wo_d[165]
  PIN wo_d[166]
    DIRECTION OUTPUT ;
    USE SIGNAL ;
    PORT
      LAYER M4 ;
        RECT 0.000 58.320 0.192 58.344 ;
    END
  END wo_d[166]
  PIN wo_d[167]
    DIRECTION OUTPUT ;
    USE SIGNAL ;
    PORT
      LAYER M4 ;
        RECT 129.408 60.624 129.600 60.648 ;
    END
  END wo_d[167]
  PIN wo_d[168]
    DIRECTION OUTPUT ;
    USE SIGNAL ;
    PORT
      LAYER M4 ;
        RECT 0.000 58.560 0.192 58.584 ;
    END
  END wo_d[168]
  PIN wo_d[169]
    DIRECTION OUTPUT ;
    USE SIGNAL ;
    PORT
      LAYER M4 ;
        RECT 129.408 60.720 129.600 60.744 ;
    END
  END wo_d[169]
  PIN wo_d[16]
    DIRECTION OUTPUT ;
    USE SIGNAL ;
    PORT
      LAYER M4 ;
        RECT 0.000 43.536 0.192 43.560 ;
    END
  END wo_d[16]
  PIN wo_d[170]
    DIRECTION OUTPUT ;
    USE SIGNAL ;
    PORT
      LAYER M4 ;
        RECT 0.000 58.752 0.192 58.776 ;
    END
  END wo_d[170]
  PIN wo_d[171]
    DIRECTION OUTPUT ;
    USE SIGNAL ;
    PORT
      LAYER M4 ;
        RECT 129.408 60.864 129.600 60.888 ;
    END
  END wo_d[171]
  PIN wo_d[172]
    DIRECTION OUTPUT ;
    USE SIGNAL ;
    PORT
      LAYER M4 ;
        RECT 0.000 58.944 0.192 58.968 ;
    END
  END wo_d[172]
  PIN wo_d[173]
    DIRECTION OUTPUT ;
    USE SIGNAL ;
    PORT
      LAYER M4 ;
        RECT 129.408 61.056 129.600 61.080 ;
    END
  END wo_d[173]
  PIN wo_d[174]
    DIRECTION OUTPUT ;
    USE SIGNAL ;
    PORT
      LAYER M4 ;
        RECT 0.000 59.136 0.192 59.160 ;
    END
  END wo_d[174]
  PIN wo_d[175]
    DIRECTION OUTPUT ;
    USE SIGNAL ;
    PORT
      LAYER M4 ;
        RECT 129.408 61.200 129.600 61.224 ;
    END
  END wo_d[175]
  PIN wo_d[176]
    DIRECTION OUTPUT ;
    USE SIGNAL ;
    PORT
      LAYER M4 ;
        RECT 0.000 59.328 0.192 59.352 ;
    END
  END wo_d[176]
  PIN wo_d[177]
    DIRECTION OUTPUT ;
    USE SIGNAL ;
    PORT
      LAYER M4 ;
        RECT 129.408 61.392 129.600 61.416 ;
    END
  END wo_d[177]
  PIN wo_d[178]
    DIRECTION OUTPUT ;
    USE SIGNAL ;
    PORT
      LAYER M4 ;
        RECT 0.000 59.520 0.192 59.544 ;
    END
  END wo_d[178]
  PIN wo_d[179]
    DIRECTION OUTPUT ;
    USE SIGNAL ;
    PORT
      LAYER M4 ;
        RECT 129.408 61.488 129.600 61.512 ;
    END
  END wo_d[179]
  PIN wo_d[17]
    DIRECTION OUTPUT ;
    USE SIGNAL ;
    PORT
      LAYER M4 ;
        RECT 129.408 48.960 129.600 48.984 ;
    END
  END wo_d[17]
  PIN wo_d[180]
    DIRECTION OUTPUT ;
    USE SIGNAL ;
    PORT
      LAYER M4 ;
        RECT 0.000 59.712 0.192 59.736 ;
    END
  END wo_d[180]
  PIN wo_d[181]
    DIRECTION OUTPUT ;
    USE SIGNAL ;
    PORT
      LAYER M4 ;
        RECT 129.408 61.680 129.600 61.704 ;
    END
  END wo_d[181]
  PIN wo_d[182]
    DIRECTION OUTPUT ;
    USE SIGNAL ;
    PORT
      LAYER M4 ;
        RECT 0.000 59.904 0.192 59.928 ;
    END
  END wo_d[182]
  PIN wo_d[183]
    DIRECTION OUTPUT ;
    USE SIGNAL ;
    PORT
      LAYER M4 ;
        RECT 129.408 61.824 129.600 61.848 ;
    END
  END wo_d[183]
  PIN wo_d[184]
    DIRECTION OUTPUT ;
    USE SIGNAL ;
    PORT
      LAYER M4 ;
        RECT 0.000 60.096 0.192 60.120 ;
    END
  END wo_d[184]
  PIN wo_d[185]
    DIRECTION OUTPUT ;
    USE SIGNAL ;
    PORT
      LAYER M4 ;
        RECT 129.408 61.968 129.600 61.992 ;
    END
  END wo_d[185]
  PIN wo_d[186]
    DIRECTION OUTPUT ;
    USE SIGNAL ;
    PORT
      LAYER M4 ;
        RECT 0.000 60.288 0.192 60.312 ;
    END
  END wo_d[186]
  PIN wo_d[187]
    DIRECTION OUTPUT ;
    USE SIGNAL ;
    PORT
      LAYER M4 ;
        RECT 129.408 62.160 129.600 62.184 ;
    END
  END wo_d[187]
  PIN wo_d[188]
    DIRECTION OUTPUT ;
    USE SIGNAL ;
    PORT
      LAYER M4 ;
        RECT 0.000 60.480 0.192 60.504 ;
    END
  END wo_d[188]
  PIN wo_d[189]
    DIRECTION OUTPUT ;
    USE SIGNAL ;
    PORT
      LAYER M4 ;
        RECT 129.408 62.256 129.600 62.280 ;
    END
  END wo_d[189]
  PIN wo_d[18]
    DIRECTION OUTPUT ;
    USE SIGNAL ;
    PORT
      LAYER M4 ;
        RECT 0.000 43.728 0.192 43.752 ;
    END
  END wo_d[18]
  PIN wo_d[190]
    DIRECTION OUTPUT ;
    USE SIGNAL ;
    PORT
      LAYER M4 ;
        RECT 0.000 60.672 0.192 60.696 ;
    END
  END wo_d[190]
  PIN wo_d[191]
    DIRECTION OUTPUT ;
    USE SIGNAL ;
    PORT
      LAYER M4 ;
        RECT 129.408 62.448 129.600 62.472 ;
    END
  END wo_d[191]
  PIN wo_d[192]
    DIRECTION OUTPUT ;
    USE SIGNAL ;
    PORT
      LAYER M4 ;
        RECT 0.000 60.912 0.192 60.936 ;
    END
  END wo_d[192]
  PIN wo_d[193]
    DIRECTION OUTPUT ;
    USE SIGNAL ;
    PORT
      LAYER M4 ;
        RECT 129.408 62.592 129.600 62.616 ;
    END
  END wo_d[193]
  PIN wo_d[194]
    DIRECTION OUTPUT ;
    USE SIGNAL ;
    PORT
      LAYER M4 ;
        RECT 0.000 61.104 0.192 61.128 ;
    END
  END wo_d[194]
  PIN wo_d[195]
    DIRECTION OUTPUT ;
    USE SIGNAL ;
    PORT
      LAYER M4 ;
        RECT 129.408 62.736 129.600 62.760 ;
    END
  END wo_d[195]
  PIN wo_d[196]
    DIRECTION OUTPUT ;
    USE SIGNAL ;
    PORT
      LAYER M4 ;
        RECT 0.000 61.296 0.192 61.320 ;
    END
  END wo_d[196]
  PIN wo_d[197]
    DIRECTION OUTPUT ;
    USE SIGNAL ;
    PORT
      LAYER M4 ;
        RECT 129.408 62.928 129.600 62.952 ;
    END
  END wo_d[197]
  PIN wo_d[198]
    DIRECTION OUTPUT ;
    USE SIGNAL ;
    PORT
      LAYER M4 ;
        RECT 0.000 61.488 0.192 61.512 ;
    END
  END wo_d[198]
  PIN wo_d[199]
    DIRECTION OUTPUT ;
    USE SIGNAL ;
    PORT
      LAYER M4 ;
        RECT 129.408 63.024 129.600 63.048 ;
    END
  END wo_d[199]
  PIN wo_d[19]
    DIRECTION OUTPUT ;
    USE SIGNAL ;
    PORT
      LAYER M4 ;
        RECT 129.408 49.104 129.600 49.128 ;
    END
  END wo_d[19]
  PIN wo_d[1]
    DIRECTION OUTPUT ;
    USE SIGNAL ;
    PORT
      LAYER M4 ;
        RECT 129.408 47.664 129.600 47.688 ;
    END
  END wo_d[1]
  PIN wo_d[200]
    DIRECTION OUTPUT ;
    USE SIGNAL ;
    PORT
      LAYER M3 ;
        RECT 0.576 69.082 0.594 69.120 ;
    END
  END wo_d[200]
  PIN wo_d[201]
    DIRECTION OUTPUT ;
    USE SIGNAL ;
    PORT
      LAYER M3 ;
        RECT 0.720 69.082 0.738 69.120 ;
    END
  END wo_d[201]
  PIN wo_d[202]
    DIRECTION OUTPUT ;
    USE SIGNAL ;
    PORT
      LAYER M5 ;
        RECT 0.864 69.036 0.888 69.120 ;
    END
  END wo_d[202]
  PIN wo_d[203]
    DIRECTION OUTPUT ;
    USE SIGNAL ;
    PORT
      LAYER M3 ;
        RECT 1.008 69.082 1.026 69.120 ;
    END
  END wo_d[203]
  PIN wo_d[204]
    DIRECTION OUTPUT ;
    USE SIGNAL ;
    PORT
      LAYER M5 ;
        RECT 1.152 69.036 1.176 69.120 ;
    END
  END wo_d[204]
  PIN wo_d[205]
    DIRECTION OUTPUT ;
    USE SIGNAL ;
    PORT
      LAYER M5 ;
        RECT 1.344 69.036 1.368 69.120 ;
    END
  END wo_d[205]
  PIN wo_d[206]
    DIRECTION OUTPUT ;
    USE SIGNAL ;
    PORT
      LAYER M5 ;
        RECT 1.440 69.036 1.464 69.120 ;
    END
  END wo_d[206]
  PIN wo_d[207]
    DIRECTION OUTPUT ;
    USE SIGNAL ;
    PORT
      LAYER M5 ;
        RECT 1.632 69.036 1.656 69.120 ;
    END
  END wo_d[207]
  PIN wo_d[208]
    DIRECTION OUTPUT ;
    USE SIGNAL ;
    PORT
      LAYER M3 ;
        RECT 1.800 69.082 1.818 69.120 ;
    END
  END wo_d[208]
  PIN wo_d[209]
    DIRECTION OUTPUT ;
    USE SIGNAL ;
    PORT
      LAYER M5 ;
        RECT 1.920 69.036 1.944 69.120 ;
    END
  END wo_d[209]
  PIN wo_d[20]
    DIRECTION OUTPUT ;
    USE SIGNAL ;
    PORT
      LAYER M4 ;
        RECT 0.000 43.920 0.192 43.944 ;
    END
  END wo_d[20]
  PIN wo_d[210]
    DIRECTION OUTPUT ;
    USE SIGNAL ;
    PORT
      LAYER M3 ;
        RECT 2.088 69.082 2.106 69.120 ;
    END
  END wo_d[210]
  PIN wo_d[211]
    DIRECTION OUTPUT ;
    USE SIGNAL ;
    PORT
      LAYER M5 ;
        RECT 2.208 69.036 2.232 69.120 ;
    END
  END wo_d[211]
  PIN wo_d[212]
    DIRECTION OUTPUT ;
    USE SIGNAL ;
    PORT
      LAYER M3 ;
        RECT 2.376 69.082 2.394 69.120 ;
    END
  END wo_d[212]
  PIN wo_d[213]
    DIRECTION OUTPUT ;
    USE SIGNAL ;
    PORT
      LAYER M3 ;
        RECT 2.592 69.082 2.610 69.120 ;
    END
  END wo_d[213]
  PIN wo_d[214]
    DIRECTION OUTPUT ;
    USE SIGNAL ;
    PORT
      LAYER M3 ;
        RECT 2.808 69.082 2.826 69.120 ;
    END
  END wo_d[214]
  PIN wo_d[215]
    DIRECTION OUTPUT ;
    USE SIGNAL ;
    PORT
      LAYER M5 ;
        RECT 2.976 69.036 3.000 69.120 ;
    END
  END wo_d[215]
  PIN wo_d[216]
    DIRECTION OUTPUT ;
    USE SIGNAL ;
    PORT
      LAYER M3 ;
        RECT 3.168 69.082 3.186 69.120 ;
    END
  END wo_d[216]
  PIN wo_d[217]
    DIRECTION OUTPUT ;
    USE SIGNAL ;
    PORT
      LAYER M5 ;
        RECT 3.264 69.036 3.288 69.120 ;
    END
  END wo_d[217]
  PIN wo_d[218]
    DIRECTION OUTPUT ;
    USE SIGNAL ;
    PORT
      LAYER M3 ;
        RECT 3.456 69.082 3.474 69.120 ;
    END
  END wo_d[218]
  PIN wo_d[219]
    DIRECTION OUTPUT ;
    USE SIGNAL ;
    PORT
      LAYER M3 ;
        RECT 3.600 69.082 3.618 69.120 ;
    END
  END wo_d[219]
  PIN wo_d[21]
    DIRECTION OUTPUT ;
    USE SIGNAL ;
    PORT
      LAYER M4 ;
        RECT 129.408 49.296 129.600 49.320 ;
    END
  END wo_d[21]
  PIN wo_d[220]
    DIRECTION OUTPUT ;
    USE SIGNAL ;
    PORT
      LAYER M3 ;
        RECT 3.744 69.082 3.762 69.120 ;
    END
  END wo_d[220]
  PIN wo_d[221]
    DIRECTION OUTPUT ;
    USE SIGNAL ;
    PORT
      LAYER M3 ;
        RECT 3.888 69.082 3.906 69.120 ;
    END
  END wo_d[221]
  PIN wo_d[222]
    DIRECTION OUTPUT ;
    USE SIGNAL ;
    PORT
      LAYER M3 ;
        RECT 4.032 69.082 4.050 69.120 ;
    END
  END wo_d[222]
  PIN wo_d[223]
    DIRECTION OUTPUT ;
    USE SIGNAL ;
    PORT
      LAYER M3 ;
        RECT 4.176 69.082 4.194 69.120 ;
    END
  END wo_d[223]
  PIN wo_d[224]
    DIRECTION OUTPUT ;
    USE SIGNAL ;
    PORT
      LAYER M5 ;
        RECT 4.320 69.036 4.344 69.120 ;
    END
  END wo_d[224]
  PIN wo_d[225]
    DIRECTION OUTPUT ;
    USE SIGNAL ;
    PORT
      LAYER M3 ;
        RECT 4.464 69.082 4.482 69.120 ;
    END
  END wo_d[225]
  PIN wo_d[226]
    DIRECTION OUTPUT ;
    USE SIGNAL ;
    PORT
      LAYER M5 ;
        RECT 4.608 69.036 4.632 69.120 ;
    END
  END wo_d[226]
  PIN wo_d[227]
    DIRECTION OUTPUT ;
    USE SIGNAL ;
    PORT
      LAYER M5 ;
        RECT 4.800 69.036 4.824 69.120 ;
    END
  END wo_d[227]
  PIN wo_d[228]
    DIRECTION OUTPUT ;
    USE SIGNAL ;
    PORT
      LAYER M5 ;
        RECT 4.896 69.036 4.920 69.120 ;
    END
  END wo_d[228]
  PIN wo_d[229]
    DIRECTION OUTPUT ;
    USE SIGNAL ;
    PORT
      LAYER M5 ;
        RECT 5.088 69.036 5.112 69.120 ;
    END
  END wo_d[229]
  PIN wo_d[22]
    DIRECTION OUTPUT ;
    USE SIGNAL ;
    PORT
      LAYER M4 ;
        RECT 0.000 44.112 0.192 44.136 ;
    END
  END wo_d[22]
  PIN wo_d[230]
    DIRECTION OUTPUT ;
    USE SIGNAL ;
    PORT
      LAYER M3 ;
        RECT 5.256 69.082 5.274 69.120 ;
    END
  END wo_d[230]
  PIN wo_d[231]
    DIRECTION OUTPUT ;
    USE SIGNAL ;
    PORT
      LAYER M5 ;
        RECT 5.376 69.036 5.400 69.120 ;
    END
  END wo_d[231]
  PIN wo_d[232]
    DIRECTION OUTPUT ;
    USE SIGNAL ;
    PORT
      LAYER M3 ;
        RECT 5.544 69.082 5.562 69.120 ;
    END
  END wo_d[232]
  PIN wo_d[233]
    DIRECTION OUTPUT ;
    USE SIGNAL ;
    PORT
      LAYER M5 ;
        RECT 5.664 69.036 5.688 69.120 ;
    END
  END wo_d[233]
  PIN wo_d[234]
    DIRECTION OUTPUT ;
    USE SIGNAL ;
    PORT
      LAYER M3 ;
        RECT 5.832 69.082 5.850 69.120 ;
    END
  END wo_d[234]
  PIN wo_d[235]
    DIRECTION OUTPUT ;
    USE SIGNAL ;
    PORT
      LAYER M3 ;
        RECT 5.976 69.082 5.994 69.120 ;
    END
  END wo_d[235]
  PIN wo_d[236]
    DIRECTION OUTPUT ;
    USE SIGNAL ;
    PORT
      LAYER M3 ;
        RECT 6.120 69.082 6.138 69.120 ;
    END
  END wo_d[236]
  PIN wo_d[237]
    DIRECTION OUTPUT ;
    USE SIGNAL ;
    PORT
      LAYER M3 ;
        RECT 6.264 69.082 6.282 69.120 ;
    END
  END wo_d[237]
  PIN wo_d[238]
    DIRECTION OUTPUT ;
    USE SIGNAL ;
    PORT
      LAYER M5 ;
        RECT 6.432 69.036 6.456 69.120 ;
    END
  END wo_d[238]
  PIN wo_d[239]
    DIRECTION OUTPUT ;
    USE SIGNAL ;
    PORT
      LAYER M3 ;
        RECT 6.552 69.082 6.570 69.120 ;
    END
  END wo_d[239]
  PIN wo_d[23]
    DIRECTION OUTPUT ;
    USE SIGNAL ;
    PORT
      LAYER M4 ;
        RECT 129.408 49.392 129.600 49.416 ;
    END
  END wo_d[23]
  PIN wo_d[240]
    DIRECTION OUTPUT ;
    USE SIGNAL ;
    PORT
      LAYER M5 ;
        RECT 6.720 69.036 6.744 69.120 ;
    END
  END wo_d[240]
  PIN wo_d[241]
    DIRECTION OUTPUT ;
    USE SIGNAL ;
    PORT
      LAYER M3 ;
        RECT 6.912 69.082 6.930 69.120 ;
    END
  END wo_d[241]
  PIN wo_d[242]
    DIRECTION OUTPUT ;
    USE SIGNAL ;
    PORT
      LAYER M5 ;
        RECT 7.008 69.036 7.032 69.120 ;
    END
  END wo_d[242]
  PIN wo_d[243]
    DIRECTION OUTPUT ;
    USE SIGNAL ;
    PORT
      LAYER M3 ;
        RECT 7.200 69.082 7.218 69.120 ;
    END
  END wo_d[243]
  PIN wo_d[244]
    DIRECTION OUTPUT ;
    USE SIGNAL ;
    PORT
      LAYER M5 ;
        RECT 7.296 69.036 7.320 69.120 ;
    END
  END wo_d[244]
  PIN wo_d[245]
    DIRECTION OUTPUT ;
    USE SIGNAL ;
    PORT
      LAYER M3 ;
        RECT 7.488 69.082 7.506 69.120 ;
    END
  END wo_d[245]
  PIN wo_d[246]
    DIRECTION OUTPUT ;
    USE SIGNAL ;
    PORT
      LAYER M3 ;
        RECT 7.632 69.082 7.650 69.120 ;
    END
  END wo_d[246]
  PIN wo_d[247]
    DIRECTION OUTPUT ;
    USE SIGNAL ;
    PORT
      LAYER M3 ;
        RECT 7.776 69.082 7.794 69.120 ;
    END
  END wo_d[247]
  PIN wo_d[248]
    DIRECTION OUTPUT ;
    USE SIGNAL ;
    PORT
      LAYER M3 ;
        RECT 7.992 69.082 8.010 69.120 ;
    END
  END wo_d[248]
  PIN wo_d[249]
    DIRECTION OUTPUT ;
    USE SIGNAL ;
    PORT
      LAYER M5 ;
        RECT 8.256 69.036 8.280 69.120 ;
    END
  END wo_d[249]
  PIN wo_d[24]
    DIRECTION OUTPUT ;
    USE SIGNAL ;
    PORT
      LAYER M4 ;
        RECT 0.000 44.304 0.192 44.328 ;
    END
  END wo_d[24]
  PIN wo_d[250]
    DIRECTION OUTPUT ;
    USE SIGNAL ;
    PORT
      LAYER M5 ;
        RECT 8.352 69.036 8.376 69.120 ;
    END
  END wo_d[250]
  PIN wo_d[251]
    DIRECTION OUTPUT ;
    USE SIGNAL ;
    PORT
      LAYER M5 ;
        RECT 8.544 69.036 8.568 69.120 ;
    END
  END wo_d[251]
  PIN wo_d[252]
    DIRECTION OUTPUT ;
    USE SIGNAL ;
    PORT
      LAYER M3 ;
        RECT 8.712 69.082 8.730 69.120 ;
    END
  END wo_d[252]
  PIN wo_d[253]
    DIRECTION OUTPUT ;
    USE SIGNAL ;
    PORT
      LAYER M5 ;
        RECT 8.832 69.036 8.856 69.120 ;
    END
  END wo_d[253]
  PIN wo_d[254]
    DIRECTION OUTPUT ;
    USE SIGNAL ;
    PORT
      LAYER M3 ;
        RECT 9.000 69.082 9.018 69.120 ;
    END
  END wo_d[254]
  PIN wo_d[255]
    DIRECTION OUTPUT ;
    USE SIGNAL ;
    PORT
      LAYER M3 ;
        RECT 9.144 69.082 9.162 69.120 ;
    END
  END wo_d[255]
  PIN wo_d[256]
    DIRECTION OUTPUT ;
    USE SIGNAL ;
    PORT
      LAYER M3 ;
        RECT 9.288 69.082 9.306 69.120 ;
    END
  END wo_d[256]
  PIN wo_d[257]
    DIRECTION OUTPUT ;
    USE SIGNAL ;
    PORT
      LAYER M3 ;
        RECT 9.432 69.082 9.450 69.120 ;
    END
  END wo_d[257]
  PIN wo_d[258]
    DIRECTION OUTPUT ;
    USE SIGNAL ;
    PORT
      LAYER M3 ;
        RECT 9.576 69.082 9.594 69.120 ;
    END
  END wo_d[258]
  PIN wo_d[259]
    DIRECTION OUTPUT ;
    USE SIGNAL ;
    PORT
      LAYER M3 ;
        RECT 9.720 69.082 9.738 69.120 ;
    END
  END wo_d[259]
  PIN wo_d[25]
    DIRECTION OUTPUT ;
    USE SIGNAL ;
    PORT
      LAYER M4 ;
        RECT 129.408 49.584 129.600 49.608 ;
    END
  END wo_d[25]
  PIN wo_d[260]
    DIRECTION OUTPUT ;
    USE SIGNAL ;
    PORT
      LAYER M5 ;
        RECT 9.888 69.036 9.912 69.120 ;
    END
  END wo_d[260]
  PIN wo_d[261]
    DIRECTION OUTPUT ;
    USE SIGNAL ;
    PORT
      LAYER M3 ;
        RECT 10.008 69.082 10.026 69.120 ;
    END
  END wo_d[261]
  PIN wo_d[262]
    DIRECTION OUTPUT ;
    USE SIGNAL ;
    PORT
      LAYER M5 ;
        RECT 10.176 69.036 10.200 69.120 ;
    END
  END wo_d[262]
  PIN wo_d[263]
    DIRECTION OUTPUT ;
    USE SIGNAL ;
    PORT
      LAYER M3 ;
        RECT 10.368 69.082 10.386 69.120 ;
    END
  END wo_d[263]
  PIN wo_d[264]
    DIRECTION OUTPUT ;
    USE SIGNAL ;
    PORT
      LAYER M5 ;
        RECT 10.464 69.036 10.488 69.120 ;
    END
  END wo_d[264]
  PIN wo_d[265]
    DIRECTION OUTPUT ;
    USE SIGNAL ;
    PORT
      LAYER M3 ;
        RECT 10.656 69.082 10.674 69.120 ;
    END
  END wo_d[265]
  PIN wo_d[266]
    DIRECTION OUTPUT ;
    USE SIGNAL ;
    PORT
      LAYER M3 ;
        RECT 10.800 69.082 10.818 69.120 ;
    END
  END wo_d[266]
  PIN wo_d[267]
    DIRECTION OUTPUT ;
    USE SIGNAL ;
    PORT
      LAYER M3 ;
        RECT 10.944 69.082 10.962 69.120 ;
    END
  END wo_d[267]
  PIN wo_d[268]
    DIRECTION OUTPUT ;
    USE SIGNAL ;
    PORT
      LAYER M3 ;
        RECT 11.088 69.082 11.106 69.120 ;
    END
  END wo_d[268]
  PIN wo_d[269]
    DIRECTION OUTPUT ;
    USE SIGNAL ;
    PORT
      LAYER M3 ;
        RECT 11.232 69.082 11.250 69.120 ;
    END
  END wo_d[269]
  PIN wo_d[26]
    DIRECTION OUTPUT ;
    USE SIGNAL ;
    PORT
      LAYER M4 ;
        RECT 0.000 44.496 0.192 44.520 ;
    END
  END wo_d[26]
  PIN wo_d[270]
    DIRECTION OUTPUT ;
    USE SIGNAL ;
    PORT
      LAYER M3 ;
        RECT 11.376 69.082 11.394 69.120 ;
    END
  END wo_d[270]
  PIN wo_d[271]
    DIRECTION OUTPUT ;
    USE SIGNAL ;
    PORT
      LAYER M5 ;
        RECT 11.520 69.036 11.544 69.120 ;
    END
  END wo_d[271]
  PIN wo_d[272]
    DIRECTION OUTPUT ;
    USE SIGNAL ;
    PORT
      LAYER M3 ;
        RECT 11.664 69.082 11.682 69.120 ;
    END
  END wo_d[272]
  PIN wo_d[273]
    DIRECTION OUTPUT ;
    USE SIGNAL ;
    PORT
      LAYER M5 ;
        RECT 11.808 69.036 11.832 69.120 ;
    END
  END wo_d[273]
  PIN wo_d[274]
    DIRECTION OUTPUT ;
    USE SIGNAL ;
    PORT
      LAYER M5 ;
        RECT 12.000 69.036 12.024 69.120 ;
    END
  END wo_d[274]
  PIN wo_d[275]
    DIRECTION OUTPUT ;
    USE SIGNAL ;
    PORT
      LAYER M5 ;
        RECT 12.096 69.036 12.120 69.120 ;
    END
  END wo_d[275]
  PIN wo_d[276]
    DIRECTION OUTPUT ;
    USE SIGNAL ;
    PORT
      LAYER M5 ;
        RECT 12.288 69.036 12.312 69.120 ;
    END
  END wo_d[276]
  PIN wo_d[277]
    DIRECTION OUTPUT ;
    USE SIGNAL ;
    PORT
      LAYER M3 ;
        RECT 12.456 69.082 12.474 69.120 ;
    END
  END wo_d[277]
  PIN wo_d[278]
    DIRECTION OUTPUT ;
    USE SIGNAL ;
    PORT
      LAYER M5 ;
        RECT 12.576 69.036 12.600 69.120 ;
    END
  END wo_d[278]
  PIN wo_d[279]
    DIRECTION OUTPUT ;
    USE SIGNAL ;
    PORT
      LAYER M3 ;
        RECT 12.744 69.082 12.762 69.120 ;
    END
  END wo_d[279]
  PIN wo_d[27]
    DIRECTION OUTPUT ;
    USE SIGNAL ;
    PORT
      LAYER M4 ;
        RECT 129.408 49.728 129.600 49.752 ;
    END
  END wo_d[27]
  PIN wo_d[280]
    DIRECTION OUTPUT ;
    USE SIGNAL ;
    PORT
      LAYER M5 ;
        RECT 12.864 69.036 12.888 69.120 ;
    END
  END wo_d[280]
  PIN wo_d[281]
    DIRECTION OUTPUT ;
    USE SIGNAL ;
    PORT
      LAYER M3 ;
        RECT 13.032 69.082 13.050 69.120 ;
    END
  END wo_d[281]
  PIN wo_d[282]
    DIRECTION OUTPUT ;
    USE SIGNAL ;
    PORT
      LAYER M3 ;
        RECT 13.176 69.082 13.194 69.120 ;
    END
  END wo_d[282]
  PIN wo_d[283]
    DIRECTION OUTPUT ;
    USE SIGNAL ;
    PORT
      LAYER M3 ;
        RECT 13.392 69.082 13.410 69.120 ;
    END
  END wo_d[283]
  PIN wo_d[284]
    DIRECTION OUTPUT ;
    USE SIGNAL ;
    PORT
      LAYER M5 ;
        RECT 13.632 69.036 13.656 69.120 ;
    END
  END wo_d[284]
  PIN wo_d[285]
    DIRECTION OUTPUT ;
    USE SIGNAL ;
    PORT
      LAYER M3 ;
        RECT 13.824 69.082 13.842 69.120 ;
    END
  END wo_d[285]
  PIN wo_d[286]
    DIRECTION OUTPUT ;
    USE SIGNAL ;
    PORT
      LAYER M5 ;
        RECT 13.920 69.036 13.944 69.120 ;
    END
  END wo_d[286]
  PIN wo_d[287]
    DIRECTION OUTPUT ;
    USE SIGNAL ;
    PORT
      LAYER M3 ;
        RECT 14.112 69.082 14.130 69.120 ;
    END
  END wo_d[287]
  PIN wo_d[288]
    DIRECTION OUTPUT ;
    USE SIGNAL ;
    PORT
      LAYER M3 ;
        RECT 14.256 69.082 14.274 69.120 ;
    END
  END wo_d[288]
  PIN wo_d[289]
    DIRECTION OUTPUT ;
    USE SIGNAL ;
    PORT
      LAYER M3 ;
        RECT 14.400 69.082 14.418 69.120 ;
    END
  END wo_d[289]
  PIN wo_d[28]
    DIRECTION OUTPUT ;
    USE SIGNAL ;
    PORT
      LAYER M4 ;
        RECT 0.000 44.688 0.192 44.712 ;
    END
  END wo_d[28]
  PIN wo_d[290]
    DIRECTION OUTPUT ;
    USE SIGNAL ;
    PORT
      LAYER M3 ;
        RECT 14.544 69.082 14.562 69.120 ;
    END
  END wo_d[290]
  PIN wo_d[291]
    DIRECTION OUTPUT ;
    USE SIGNAL ;
    PORT
      LAYER M3 ;
        RECT 14.688 69.082 14.706 69.120 ;
    END
  END wo_d[291]
  PIN wo_d[292]
    DIRECTION OUTPUT ;
    USE SIGNAL ;
    PORT
      LAYER M3 ;
        RECT 14.832 69.082 14.850 69.120 ;
    END
  END wo_d[292]
  PIN wo_d[293]
    DIRECTION OUTPUT ;
    USE SIGNAL ;
    PORT
      LAYER M5 ;
        RECT 14.976 69.036 15.000 69.120 ;
    END
  END wo_d[293]
  PIN wo_d[294]
    DIRECTION OUTPUT ;
    USE SIGNAL ;
    PORT
      LAYER M3 ;
        RECT 15.120 69.082 15.138 69.120 ;
    END
  END wo_d[294]
  PIN wo_d[295]
    DIRECTION OUTPUT ;
    USE SIGNAL ;
    PORT
      LAYER M5 ;
        RECT 15.264 69.036 15.288 69.120 ;
    END
  END wo_d[295]
  PIN wo_d[296]
    DIRECTION OUTPUT ;
    USE SIGNAL ;
    PORT
      LAYER M5 ;
        RECT 15.456 69.036 15.480 69.120 ;
    END
  END wo_d[296]
  PIN wo_d[297]
    DIRECTION OUTPUT ;
    USE SIGNAL ;
    PORT
      LAYER M5 ;
        RECT 15.552 69.036 15.576 69.120 ;
    END
  END wo_d[297]
  PIN wo_d[298]
    DIRECTION OUTPUT ;
    USE SIGNAL ;
    PORT
      LAYER M5 ;
        RECT 15.744 69.036 15.768 69.120 ;
    END
  END wo_d[298]
  PIN wo_d[299]
    DIRECTION OUTPUT ;
    USE SIGNAL ;
    PORT
      LAYER M3 ;
        RECT 15.912 69.082 15.930 69.120 ;
    END
  END wo_d[299]
  PIN wo_d[29]
    DIRECTION OUTPUT ;
    USE SIGNAL ;
    PORT
      LAYER M4 ;
        RECT 129.408 49.872 129.600 49.896 ;
    END
  END wo_d[29]
  PIN wo_d[2]
    DIRECTION OUTPUT ;
    USE SIGNAL ;
    PORT
      LAYER M4 ;
        RECT 0.000 42.096 0.192 42.120 ;
    END
  END wo_d[2]
  PIN wo_d[300]
    DIRECTION OUTPUT ;
    USE SIGNAL ;
    PORT
      LAYER M5 ;
        RECT 16.032 69.036 16.056 69.120 ;
    END
  END wo_d[300]
  PIN wo_d[301]
    DIRECTION OUTPUT ;
    USE SIGNAL ;
    PORT
      LAYER M3 ;
        RECT 16.200 69.082 16.218 69.120 ;
    END
  END wo_d[301]
  PIN wo_d[302]
    DIRECTION OUTPUT ;
    USE SIGNAL ;
    PORT
      LAYER M3 ;
        RECT 16.344 69.082 16.362 69.120 ;
    END
  END wo_d[302]
  PIN wo_d[303]
    DIRECTION OUTPUT ;
    USE SIGNAL ;
    PORT
      LAYER M3 ;
        RECT 16.488 69.082 16.506 69.120 ;
    END
  END wo_d[303]
  PIN wo_d[304]
    DIRECTION OUTPUT ;
    USE SIGNAL ;
    PORT
      LAYER M3 ;
        RECT 16.632 69.082 16.650 69.120 ;
    END
  END wo_d[304]
  PIN wo_d[305]
    DIRECTION OUTPUT ;
    USE SIGNAL ;
    PORT
      LAYER M3 ;
        RECT 16.776 69.082 16.794 69.120 ;
    END
  END wo_d[305]
  PIN wo_d[306]
    DIRECTION OUTPUT ;
    USE SIGNAL ;
    PORT
      LAYER M3 ;
        RECT 16.920 69.082 16.938 69.120 ;
    END
  END wo_d[306]
  PIN wo_d[307]
    DIRECTION OUTPUT ;
    USE SIGNAL ;
    PORT
      LAYER M5 ;
        RECT 17.088 69.036 17.112 69.120 ;
    END
  END wo_d[307]
  PIN wo_d[308]
    DIRECTION OUTPUT ;
    USE SIGNAL ;
    PORT
      LAYER M3 ;
        RECT 17.208 69.082 17.226 69.120 ;
    END
  END wo_d[308]
  PIN wo_d[309]
    DIRECTION OUTPUT ;
    USE SIGNAL ;
    PORT
      LAYER M5 ;
        RECT 17.376 69.036 17.400 69.120 ;
    END
  END wo_d[309]
  PIN wo_d[30]
    DIRECTION OUTPUT ;
    USE SIGNAL ;
    PORT
      LAYER M4 ;
        RECT 0.000 44.928 0.192 44.952 ;
    END
  END wo_d[30]
  PIN wo_d[310]
    DIRECTION OUTPUT ;
    USE SIGNAL ;
    PORT
      LAYER M3 ;
        RECT 17.568 69.082 17.586 69.120 ;
    END
  END wo_d[310]
  PIN wo_d[311]
    DIRECTION OUTPUT ;
    USE SIGNAL ;
    PORT
      LAYER M5 ;
        RECT 17.664 69.036 17.688 69.120 ;
    END
  END wo_d[311]
  PIN wo_d[312]
    DIRECTION OUTPUT ;
    USE SIGNAL ;
    PORT
      LAYER M3 ;
        RECT 17.856 69.082 17.874 69.120 ;
    END
  END wo_d[312]
  PIN wo_d[313]
    DIRECTION OUTPUT ;
    USE SIGNAL ;
    PORT
      LAYER M3 ;
        RECT 18.000 69.082 18.018 69.120 ;
    END
  END wo_d[313]
  PIN wo_d[314]
    DIRECTION OUTPUT ;
    USE SIGNAL ;
    PORT
      LAYER M3 ;
        RECT 18.144 69.082 18.162 69.120 ;
    END
  END wo_d[314]
  PIN wo_d[315]
    DIRECTION OUTPUT ;
    USE SIGNAL ;
    PORT
      LAYER M3 ;
        RECT 18.288 69.082 18.306 69.120 ;
    END
  END wo_d[315]
  PIN wo_d[316]
    DIRECTION OUTPUT ;
    USE SIGNAL ;
    PORT
      LAYER M3 ;
        RECT 18.432 69.082 18.450 69.120 ;
    END
  END wo_d[316]
  PIN wo_d[317]
    DIRECTION OUTPUT ;
    USE SIGNAL ;
    PORT
      LAYER M3 ;
        RECT 18.576 69.082 18.594 69.120 ;
    END
  END wo_d[317]
  PIN wo_d[318]
    DIRECTION OUTPUT ;
    USE SIGNAL ;
    PORT
      LAYER M3 ;
        RECT 18.864 69.082 18.882 69.120 ;
    END
  END wo_d[318]
  PIN wo_d[319]
    DIRECTION OUTPUT ;
    USE SIGNAL ;
    PORT
      LAYER M5 ;
        RECT 19.008 69.036 19.032 69.120 ;
    END
  END wo_d[319]
  PIN wo_d[31]
    DIRECTION OUTPUT ;
    USE SIGNAL ;
    PORT
      LAYER M4 ;
        RECT 129.408 50.064 129.600 50.088 ;
    END
  END wo_d[31]
  PIN wo_d[320]
    DIRECTION OUTPUT ;
    USE SIGNAL ;
    PORT
      LAYER M5 ;
        RECT 19.200 69.036 19.224 69.120 ;
    END
  END wo_d[320]
  PIN wo_d[321]
    DIRECTION OUTPUT ;
    USE SIGNAL ;
    PORT
      LAYER M3 ;
        RECT 19.368 69.082 19.386 69.120 ;
    END
  END wo_d[321]
  PIN wo_d[322]
    DIRECTION OUTPUT ;
    USE SIGNAL ;
    PORT
      LAYER M5 ;
        RECT 19.488 69.036 19.512 69.120 ;
    END
  END wo_d[322]
  PIN wo_d[323]
    DIRECTION OUTPUT ;
    USE SIGNAL ;
    PORT
      LAYER M3 ;
        RECT 19.656 69.082 19.674 69.120 ;
    END
  END wo_d[323]
  PIN wo_d[324]
    DIRECTION OUTPUT ;
    USE SIGNAL ;
    PORT
      LAYER M3 ;
        RECT 19.800 69.082 19.818 69.120 ;
    END
  END wo_d[324]
  PIN wo_d[325]
    DIRECTION OUTPUT ;
    USE SIGNAL ;
    PORT
      LAYER M3 ;
        RECT 19.944 69.082 19.962 69.120 ;
    END
  END wo_d[325]
  PIN wo_d[326]
    DIRECTION OUTPUT ;
    USE SIGNAL ;
    PORT
      LAYER M3 ;
        RECT 20.088 69.082 20.106 69.120 ;
    END
  END wo_d[326]
  PIN wo_d[327]
    DIRECTION OUTPUT ;
    USE SIGNAL ;
    PORT
      LAYER M3 ;
        RECT 20.232 69.082 20.250 69.120 ;
    END
  END wo_d[327]
  PIN wo_d[328]
    DIRECTION OUTPUT ;
    USE SIGNAL ;
    PORT
      LAYER M3 ;
        RECT 20.376 69.082 20.394 69.120 ;
    END
  END wo_d[328]
  PIN wo_d[329]
    DIRECTION OUTPUT ;
    USE SIGNAL ;
    PORT
      LAYER M5 ;
        RECT 20.544 69.036 20.568 69.120 ;
    END
  END wo_d[329]
  PIN wo_d[32]
    DIRECTION OUTPUT ;
    USE SIGNAL ;
    PORT
      LAYER M4 ;
        RECT 0.000 45.120 0.192 45.144 ;
    END
  END wo_d[32]
  PIN wo_d[330]
    DIRECTION OUTPUT ;
    USE SIGNAL ;
    PORT
      LAYER M3 ;
        RECT 20.664 69.082 20.682 69.120 ;
    END
  END wo_d[330]
  PIN wo_d[331]
    DIRECTION OUTPUT ;
    USE SIGNAL ;
    PORT
      LAYER M5 ;
        RECT 20.832 69.036 20.856 69.120 ;
    END
  END wo_d[331]
  PIN wo_d[332]
    DIRECTION OUTPUT ;
    USE SIGNAL ;
    PORT
      LAYER M3 ;
        RECT 21.024 69.082 21.042 69.120 ;
    END
  END wo_d[332]
  PIN wo_d[333]
    DIRECTION OUTPUT ;
    USE SIGNAL ;
    PORT
      LAYER M5 ;
        RECT 21.120 69.036 21.144 69.120 ;
    END
  END wo_d[333]
  PIN wo_d[334]
    DIRECTION OUTPUT ;
    USE SIGNAL ;
    PORT
      LAYER M3 ;
        RECT 21.312 69.082 21.330 69.120 ;
    END
  END wo_d[334]
  PIN wo_d[335]
    DIRECTION OUTPUT ;
    USE SIGNAL ;
    PORT
      LAYER M3 ;
        RECT 21.456 69.082 21.474 69.120 ;
    END
  END wo_d[335]
  PIN wo_d[336]
    DIRECTION OUTPUT ;
    USE SIGNAL ;
    PORT
      LAYER M3 ;
        RECT 21.600 69.082 21.618 69.120 ;
    END
  END wo_d[336]
  PIN wo_d[337]
    DIRECTION OUTPUT ;
    USE SIGNAL ;
    PORT
      LAYER M3 ;
        RECT 21.744 69.082 21.762 69.120 ;
    END
  END wo_d[337]
  PIN wo_d[338]
    DIRECTION OUTPUT ;
    USE SIGNAL ;
    PORT
      LAYER M5 ;
        RECT 21.888 69.036 21.912 69.120 ;
    END
  END wo_d[338]
  PIN wo_d[339]
    DIRECTION OUTPUT ;
    USE SIGNAL ;
    PORT
      LAYER M3 ;
        RECT 22.032 69.082 22.050 69.120 ;
    END
  END wo_d[339]
  PIN wo_d[33]
    DIRECTION OUTPUT ;
    USE SIGNAL ;
    PORT
      LAYER M4 ;
        RECT 129.408 50.160 129.600 50.184 ;
    END
  END wo_d[33]
  PIN wo_d[340]
    DIRECTION OUTPUT ;
    USE SIGNAL ;
    PORT
      LAYER M5 ;
        RECT 22.176 69.036 22.200 69.120 ;
    END
  END wo_d[340]
  PIN wo_d[341]
    DIRECTION OUTPUT ;
    USE SIGNAL ;
    PORT
      LAYER M3 ;
        RECT 22.320 69.082 22.338 69.120 ;
    END
  END wo_d[341]
  PIN wo_d[342]
    DIRECTION OUTPUT ;
    USE SIGNAL ;
    PORT
      LAYER M5 ;
        RECT 22.464 69.036 22.488 69.120 ;
    END
  END wo_d[342]
  PIN wo_d[343]
    DIRECTION OUTPUT ;
    USE SIGNAL ;
    PORT
      LAYER M5 ;
        RECT 22.656 69.036 22.680 69.120 ;
    END
  END wo_d[343]
  PIN wo_d[344]
    DIRECTION OUTPUT ;
    USE SIGNAL ;
    PORT
      LAYER M5 ;
        RECT 22.752 69.036 22.776 69.120 ;
    END
  END wo_d[344]
  PIN wo_d[345]
    DIRECTION OUTPUT ;
    USE SIGNAL ;
    PORT
      LAYER M5 ;
        RECT 22.944 69.036 22.968 69.120 ;
    END
  END wo_d[345]
  PIN wo_d[346]
    DIRECTION OUTPUT ;
    USE SIGNAL ;
    PORT
      LAYER M3 ;
        RECT 23.112 69.082 23.130 69.120 ;
    END
  END wo_d[346]
  PIN wo_d[347]
    DIRECTION OUTPUT ;
    USE SIGNAL ;
    PORT
      LAYER M5 ;
        RECT 23.232 69.036 23.256 69.120 ;
    END
  END wo_d[347]
  PIN wo_d[348]
    DIRECTION OUTPUT ;
    USE SIGNAL ;
    PORT
      LAYER M3 ;
        RECT 23.400 69.082 23.418 69.120 ;
    END
  END wo_d[348]
  PIN wo_d[349]
    DIRECTION OUTPUT ;
    USE SIGNAL ;
    PORT
      LAYER M3 ;
        RECT 23.544 69.082 23.562 69.120 ;
    END
  END wo_d[349]
  PIN wo_d[34]
    DIRECTION OUTPUT ;
    USE SIGNAL ;
    PORT
      LAYER M4 ;
        RECT 0.000 45.312 0.192 45.336 ;
    END
  END wo_d[34]
  PIN wo_d[350]
    DIRECTION OUTPUT ;
    USE SIGNAL ;
    PORT
      LAYER M3 ;
        RECT 23.688 69.082 23.706 69.120 ;
    END
  END wo_d[350]
  PIN wo_d[351]
    DIRECTION OUTPUT ;
    USE SIGNAL ;
    PORT
      LAYER M3 ;
        RECT 23.832 69.082 23.850 69.120 ;
    END
  END wo_d[351]
  PIN wo_d[352]
    DIRECTION OUTPUT ;
    USE SIGNAL ;
    PORT
      LAYER M3 ;
        RECT 23.976 69.082 23.994 69.120 ;
    END
  END wo_d[352]
  PIN wo_d[353]
    DIRECTION OUTPUT ;
    USE SIGNAL ;
    PORT
      LAYER M3 ;
        RECT 24.192 69.082 24.210 69.120 ;
    END
  END wo_d[353]
  PIN wo_d[354]
    DIRECTION OUTPUT ;
    USE SIGNAL ;
    PORT
      LAYER M3 ;
        RECT 24.480 69.082 24.498 69.120 ;
    END
  END wo_d[354]
  PIN wo_d[355]
    DIRECTION OUTPUT ;
    USE SIGNAL ;
    PORT
      LAYER M5 ;
        RECT 24.576 69.036 24.600 69.120 ;
    END
  END wo_d[355]
  PIN wo_d[356]
    DIRECTION OUTPUT ;
    USE SIGNAL ;
    PORT
      LAYER M3 ;
        RECT 24.768 69.082 24.786 69.120 ;
    END
  END wo_d[356]
  PIN wo_d[357]
    DIRECTION OUTPUT ;
    USE SIGNAL ;
    PORT
      LAYER M3 ;
        RECT 24.912 69.082 24.930 69.120 ;
    END
  END wo_d[357]
  PIN wo_d[358]
    DIRECTION OUTPUT ;
    USE SIGNAL ;
    PORT
      LAYER M3 ;
        RECT 25.056 69.082 25.074 69.120 ;
    END
  END wo_d[358]
  PIN wo_d[359]
    DIRECTION OUTPUT ;
    USE SIGNAL ;
    PORT
      LAYER M3 ;
        RECT 25.200 69.082 25.218 69.120 ;
    END
  END wo_d[359]
  PIN wo_d[35]
    DIRECTION OUTPUT ;
    USE SIGNAL ;
    PORT
      LAYER M4 ;
        RECT 129.408 50.352 129.600 50.376 ;
    END
  END wo_d[35]
  PIN wo_d[360]
    DIRECTION OUTPUT ;
    USE SIGNAL ;
    PORT
      LAYER M5 ;
        RECT 25.344 69.036 25.368 69.120 ;
    END
  END wo_d[360]
  PIN wo_d[361]
    DIRECTION OUTPUT ;
    USE SIGNAL ;
    PORT
      LAYER M3 ;
        RECT 25.488 69.082 25.506 69.120 ;
    END
  END wo_d[361]
  PIN wo_d[362]
    DIRECTION OUTPUT ;
    USE SIGNAL ;
    PORT
      LAYER M5 ;
        RECT 25.632 69.036 25.656 69.120 ;
    END
  END wo_d[362]
  PIN wo_d[363]
    DIRECTION OUTPUT ;
    USE SIGNAL ;
    PORT
      LAYER M3 ;
        RECT 25.776 69.082 25.794 69.120 ;
    END
  END wo_d[363]
  PIN wo_d[364]
    DIRECTION OUTPUT ;
    USE SIGNAL ;
    PORT
      LAYER M5 ;
        RECT 25.920 69.036 25.944 69.120 ;
    END
  END wo_d[364]
  PIN wo_d[365]
    DIRECTION OUTPUT ;
    USE SIGNAL ;
    PORT
      LAYER M5 ;
        RECT 26.112 69.036 26.136 69.120 ;
    END
  END wo_d[365]
  PIN wo_d[366]
    DIRECTION OUTPUT ;
    USE SIGNAL ;
    PORT
      LAYER M5 ;
        RECT 26.208 69.036 26.232 69.120 ;
    END
  END wo_d[366]
  PIN wo_d[367]
    DIRECTION OUTPUT ;
    USE SIGNAL ;
    PORT
      LAYER M5 ;
        RECT 26.400 69.036 26.424 69.120 ;
    END
  END wo_d[367]
  PIN wo_d[368]
    DIRECTION OUTPUT ;
    USE SIGNAL ;
    PORT
      LAYER M3 ;
        RECT 26.568 69.082 26.586 69.120 ;
    END
  END wo_d[368]
  PIN wo_d[369]
    DIRECTION OUTPUT ;
    USE SIGNAL ;
    PORT
      LAYER M5 ;
        RECT 26.688 69.036 26.712 69.120 ;
    END
  END wo_d[369]
  PIN wo_d[36]
    DIRECTION OUTPUT ;
    USE SIGNAL ;
    PORT
      LAYER M4 ;
        RECT 0.000 45.504 0.192 45.528 ;
    END
  END wo_d[36]
  PIN wo_d[370]
    DIRECTION OUTPUT ;
    USE SIGNAL ;
    PORT
      LAYER M3 ;
        RECT 26.856 69.082 26.874 69.120 ;
    END
  END wo_d[370]
  PIN wo_d[371]
    DIRECTION OUTPUT ;
    USE SIGNAL ;
    PORT
      LAYER M3 ;
        RECT 27.000 69.082 27.018 69.120 ;
    END
  END wo_d[371]
  PIN wo_d[372]
    DIRECTION OUTPUT ;
    USE SIGNAL ;
    PORT
      LAYER M3 ;
        RECT 27.144 69.082 27.162 69.120 ;
    END
  END wo_d[372]
  PIN wo_d[373]
    DIRECTION OUTPUT ;
    USE SIGNAL ;
    PORT
      LAYER M3 ;
        RECT 27.288 69.082 27.306 69.120 ;
    END
  END wo_d[373]
  PIN wo_d[374]
    DIRECTION OUTPUT ;
    USE SIGNAL ;
    PORT
      LAYER M3 ;
        RECT 27.432 69.082 27.450 69.120 ;
    END
  END wo_d[374]
  PIN wo_d[375]
    DIRECTION OUTPUT ;
    USE SIGNAL ;
    PORT
      LAYER M3 ;
        RECT 27.576 69.082 27.594 69.120 ;
    END
  END wo_d[375]
  PIN wo_d[376]
    DIRECTION OUTPUT ;
    USE SIGNAL ;
    PORT
      LAYER M5 ;
        RECT 27.744 69.036 27.768 69.120 ;
    END
  END wo_d[376]
  PIN wo_d[377]
    DIRECTION OUTPUT ;
    USE SIGNAL ;
    PORT
      LAYER M3 ;
        RECT 27.864 69.082 27.882 69.120 ;
    END
  END wo_d[377]
  PIN wo_d[378]
    DIRECTION OUTPUT ;
    USE SIGNAL ;
    PORT
      LAYER M5 ;
        RECT 28.032 69.036 28.056 69.120 ;
    END
  END wo_d[378]
  PIN wo_d[379]
    DIRECTION OUTPUT ;
    USE SIGNAL ;
    PORT
      LAYER M3 ;
        RECT 28.224 69.082 28.242 69.120 ;
    END
  END wo_d[379]
  PIN wo_d[37]
    DIRECTION OUTPUT ;
    USE SIGNAL ;
    PORT
      LAYER M4 ;
        RECT 129.408 50.496 129.600 50.520 ;
    END
  END wo_d[37]
  PIN wo_d[380]
    DIRECTION OUTPUT ;
    USE SIGNAL ;
    PORT
      LAYER M5 ;
        RECT 28.320 69.036 28.344 69.120 ;
    END
  END wo_d[380]
  PIN wo_d[381]
    DIRECTION OUTPUT ;
    USE SIGNAL ;
    PORT
      LAYER M3 ;
        RECT 28.512 69.082 28.530 69.120 ;
    END
  END wo_d[381]
  PIN wo_d[382]
    DIRECTION OUTPUT ;
    USE SIGNAL ;
    PORT
      LAYER M3 ;
        RECT 28.656 69.082 28.674 69.120 ;
    END
  END wo_d[382]
  PIN wo_d[383]
    DIRECTION OUTPUT ;
    USE SIGNAL ;
    PORT
      LAYER M3 ;
        RECT 28.800 69.082 28.818 69.120 ;
    END
  END wo_d[383]
  PIN wo_d[384]
    DIRECTION OUTPUT ;
    USE SIGNAL ;
    PORT
      LAYER M3 ;
        RECT 28.944 69.082 28.962 69.120 ;
    END
  END wo_d[384]
  PIN wo_d[385]
    DIRECTION OUTPUT ;
    USE SIGNAL ;
    PORT
      LAYER M5 ;
        RECT 29.088 69.036 29.112 69.120 ;
    END
  END wo_d[385]
  PIN wo_d[386]
    DIRECTION OUTPUT ;
    USE SIGNAL ;
    PORT
      LAYER M3 ;
        RECT 29.232 69.082 29.250 69.120 ;
    END
  END wo_d[386]
  PIN wo_d[387]
    DIRECTION OUTPUT ;
    USE SIGNAL ;
    PORT
      LAYER M5 ;
        RECT 29.376 69.036 29.400 69.120 ;
    END
  END wo_d[387]
  PIN wo_d[388]
    DIRECTION OUTPUT ;
    USE SIGNAL ;
    PORT
      LAYER M3 ;
        RECT 29.592 69.082 29.610 69.120 ;
    END
  END wo_d[388]
  PIN wo_d[389]
    DIRECTION OUTPUT ;
    USE SIGNAL ;
    PORT
      LAYER M5 ;
        RECT 29.856 69.036 29.880 69.120 ;
    END
  END wo_d[389]
  PIN wo_d[38]
    DIRECTION OUTPUT ;
    USE SIGNAL ;
    PORT
      LAYER M4 ;
        RECT 0.000 45.696 0.192 45.720 ;
    END
  END wo_d[38]
  PIN wo_d[390]
    DIRECTION OUTPUT ;
    USE SIGNAL ;
    PORT
      LAYER M3 ;
        RECT 30.024 69.082 30.042 69.120 ;
    END
  END wo_d[390]
  PIN wo_d[391]
    DIRECTION OUTPUT ;
    USE SIGNAL ;
    PORT
      LAYER M5 ;
        RECT 30.144 69.036 30.168 69.120 ;
    END
  END wo_d[391]
  PIN wo_d[392]
    DIRECTION OUTPUT ;
    USE SIGNAL ;
    PORT
      LAYER M3 ;
        RECT 30.312 69.082 30.330 69.120 ;
    END
  END wo_d[392]
  PIN wo_d[393]
    DIRECTION OUTPUT ;
    USE SIGNAL ;
    PORT
      LAYER M3 ;
        RECT 30.456 69.082 30.474 69.120 ;
    END
  END wo_d[393]
  PIN wo_d[394]
    DIRECTION OUTPUT ;
    USE SIGNAL ;
    PORT
      LAYER M3 ;
        RECT 30.600 69.082 30.618 69.120 ;
    END
  END wo_d[394]
  PIN wo_d[395]
    DIRECTION OUTPUT ;
    USE SIGNAL ;
    PORT
      LAYER M3 ;
        RECT 30.744 69.082 30.762 69.120 ;
    END
  END wo_d[395]
  PIN wo_d[396]
    DIRECTION OUTPUT ;
    USE SIGNAL ;
    PORT
      LAYER M5 ;
        RECT 30.912 69.036 30.936 69.120 ;
    END
  END wo_d[396]
  PIN wo_d[397]
    DIRECTION OUTPUT ;
    USE SIGNAL ;
    PORT
      LAYER M3 ;
        RECT 31.032 69.082 31.050 69.120 ;
    END
  END wo_d[397]
  PIN wo_d[398]
    DIRECTION OUTPUT ;
    USE SIGNAL ;
    PORT
      LAYER M5 ;
        RECT 31.200 69.036 31.224 69.120 ;
    END
  END wo_d[398]
  PIN wo_d[399]
    DIRECTION OUTPUT ;
    USE SIGNAL ;
    PORT
      LAYER M3 ;
        RECT 31.320 69.082 31.338 69.120 ;
    END
  END wo_d[399]
  PIN wo_d[39]
    DIRECTION OUTPUT ;
    USE SIGNAL ;
    PORT
      LAYER M4 ;
        RECT 129.408 50.688 129.600 50.712 ;
    END
  END wo_d[39]
  PIN wo_d[3]
    DIRECTION OUTPUT ;
    USE SIGNAL ;
    PORT
      LAYER M4 ;
        RECT 129.408 47.856 129.600 47.880 ;
    END
  END wo_d[3]
  PIN wo_d[400]
    DIRECTION OUTPUT ;
    USE SIGNAL ;
    PORT
      LAYER M5 ;
        RECT 31.488 69.036 31.512 69.120 ;
    END
  END wo_d[400]
  PIN wo_d[401]
    DIRECTION OUTPUT ;
    USE SIGNAL ;
    PORT
      LAYER M3 ;
        RECT 31.680 69.082 31.698 69.120 ;
    END
  END wo_d[401]
  PIN wo_d[402]
    DIRECTION OUTPUT ;
    USE SIGNAL ;
    PORT
      LAYER M5 ;
        RECT 31.776 69.036 31.800 69.120 ;
    END
  END wo_d[402]
  PIN wo_d[403]
    DIRECTION OUTPUT ;
    USE SIGNAL ;
    PORT
      LAYER M3 ;
        RECT 31.968 69.082 31.986 69.120 ;
    END
  END wo_d[403]
  PIN wo_d[404]
    DIRECTION OUTPUT ;
    USE SIGNAL ;
    PORT
      LAYER M3 ;
        RECT 32.112 69.082 32.130 69.120 ;
    END
  END wo_d[404]
  PIN wo_d[405]
    DIRECTION OUTPUT ;
    USE SIGNAL ;
    PORT
      LAYER M3 ;
        RECT 32.256 69.082 32.274 69.120 ;
    END
  END wo_d[405]
  PIN wo_d[406]
    DIRECTION OUTPUT ;
    USE SIGNAL ;
    PORT
      LAYER M3 ;
        RECT 32.400 69.082 32.418 69.120 ;
    END
  END wo_d[406]
  PIN wo_d[407]
    DIRECTION OUTPUT ;
    USE SIGNAL ;
    PORT
      LAYER M5 ;
        RECT 32.544 69.036 32.568 69.120 ;
    END
  END wo_d[407]
  PIN wo_d[408]
    DIRECTION OUTPUT ;
    USE SIGNAL ;
    PORT
      LAYER M3 ;
        RECT 32.688 69.082 32.706 69.120 ;
    END
  END wo_d[408]
  PIN wo_d[409]
    DIRECTION OUTPUT ;
    USE SIGNAL ;
    PORT
      LAYER M5 ;
        RECT 32.832 69.036 32.856 69.120 ;
    END
  END wo_d[409]
  PIN wo_d[40]
    DIRECTION OUTPUT ;
    USE SIGNAL ;
    PORT
      LAYER M4 ;
        RECT 0.000 45.888 0.192 45.912 ;
    END
  END wo_d[40]
  PIN wo_d[410]
    DIRECTION OUTPUT ;
    USE SIGNAL ;
    PORT
      LAYER M3 ;
        RECT 32.976 69.082 32.994 69.120 ;
    END
  END wo_d[410]
  PIN wo_d[411]
    DIRECTION OUTPUT ;
    USE SIGNAL ;
    PORT
      LAYER M5 ;
        RECT 33.120 69.036 33.144 69.120 ;
    END
  END wo_d[411]
  PIN wo_d[412]
    DIRECTION OUTPUT ;
    USE SIGNAL ;
    PORT
      LAYER M5 ;
        RECT 33.312 69.036 33.336 69.120 ;
    END
  END wo_d[412]
  PIN wo_d[413]
    DIRECTION OUTPUT ;
    USE SIGNAL ;
    PORT
      LAYER M5 ;
        RECT 33.408 69.036 33.432 69.120 ;
    END
  END wo_d[413]
  PIN wo_d[414]
    DIRECTION OUTPUT ;
    USE SIGNAL ;
    PORT
      LAYER M5 ;
        RECT 33.600 69.036 33.624 69.120 ;
    END
  END wo_d[414]
  PIN wo_d[415]
    DIRECTION OUTPUT ;
    USE SIGNAL ;
    PORT
      LAYER M3 ;
        RECT 33.768 69.082 33.786 69.120 ;
    END
  END wo_d[415]
  PIN wo_d[416]
    DIRECTION OUTPUT ;
    USE SIGNAL ;
    PORT
      LAYER M5 ;
        RECT 33.888 69.036 33.912 69.120 ;
    END
  END wo_d[416]
  PIN wo_d[417]
    DIRECTION OUTPUT ;
    USE SIGNAL ;
    PORT
      LAYER M3 ;
        RECT 34.056 69.082 34.074 69.120 ;
    END
  END wo_d[417]
  PIN wo_d[418]
    DIRECTION OUTPUT ;
    USE SIGNAL ;
    PORT
      LAYER M3 ;
        RECT 34.200 69.082 34.218 69.120 ;
    END
  END wo_d[418]
  PIN wo_d[419]
    DIRECTION OUTPUT ;
    USE SIGNAL ;
    PORT
      LAYER M3 ;
        RECT 34.344 69.082 34.362 69.120 ;
    END
  END wo_d[419]
  PIN wo_d[41]
    DIRECTION OUTPUT ;
    USE SIGNAL ;
    PORT
      LAYER M4 ;
        RECT 129.408 50.832 129.600 50.856 ;
    END
  END wo_d[41]
  PIN wo_d[420]
    DIRECTION OUTPUT ;
    USE SIGNAL ;
    PORT
      LAYER M3 ;
        RECT 34.488 69.082 34.506 69.120 ;
    END
  END wo_d[420]
  PIN wo_d[421]
    DIRECTION OUTPUT ;
    USE SIGNAL ;
    PORT
      LAYER M3 ;
        RECT 34.632 69.082 34.650 69.120 ;
    END
  END wo_d[421]
  PIN wo_d[422]
    DIRECTION OUTPUT ;
    USE SIGNAL ;
    PORT
      LAYER M3 ;
        RECT 34.776 69.082 34.794 69.120 ;
    END
  END wo_d[422]
  PIN wo_d[423]
    DIRECTION OUTPUT ;
    USE SIGNAL ;
    PORT
      LAYER M3 ;
        RECT 35.064 69.082 35.082 69.120 ;
    END
  END wo_d[423]
  PIN wo_d[424]
    DIRECTION OUTPUT ;
    USE SIGNAL ;
    PORT
      LAYER M5 ;
        RECT 35.232 69.036 35.256 69.120 ;
    END
  END wo_d[424]
  PIN wo_d[425]
    DIRECTION OUTPUT ;
    USE SIGNAL ;
    PORT
      LAYER M3 ;
        RECT 35.424 69.082 35.442 69.120 ;
    END
  END wo_d[425]
  PIN wo_d[426]
    DIRECTION OUTPUT ;
    USE SIGNAL ;
    PORT
      LAYER M3 ;
        RECT 35.568 69.082 35.586 69.120 ;
    END
  END wo_d[426]
  PIN wo_d[427]
    DIRECTION OUTPUT ;
    USE SIGNAL ;
    PORT
      LAYER M3 ;
        RECT 35.712 69.082 35.730 69.120 ;
    END
  END wo_d[427]
  PIN wo_d[428]
    DIRECTION OUTPUT ;
    USE SIGNAL ;
    PORT
      LAYER M3 ;
        RECT 35.856 69.082 35.874 69.120 ;
    END
  END wo_d[428]
  PIN wo_d[429]
    DIRECTION OUTPUT ;
    USE SIGNAL ;
    PORT
      LAYER M5 ;
        RECT 36.000 69.036 36.024 69.120 ;
    END
  END wo_d[429]
  PIN wo_d[42]
    DIRECTION OUTPUT ;
    USE SIGNAL ;
    PORT
      LAYER M4 ;
        RECT 0.000 46.080 0.192 46.104 ;
    END
  END wo_d[42]
  PIN wo_d[430]
    DIRECTION OUTPUT ;
    USE SIGNAL ;
    PORT
      LAYER M3 ;
        RECT 36.144 69.082 36.162 69.120 ;
    END
  END wo_d[430]
  PIN wo_d[431]
    DIRECTION OUTPUT ;
    USE SIGNAL ;
    PORT
      LAYER M5 ;
        RECT 36.288 69.036 36.312 69.120 ;
    END
  END wo_d[431]
  PIN wo_d[432]
    DIRECTION OUTPUT ;
    USE SIGNAL ;
    PORT
      LAYER M5 ;
        RECT 36.480 69.036 36.504 69.120 ;
    END
  END wo_d[432]
  PIN wo_d[433]
    DIRECTION OUTPUT ;
    USE SIGNAL ;
    PORT
      LAYER M5 ;
        RECT 36.576 69.036 36.600 69.120 ;
    END
  END wo_d[433]
  PIN wo_d[434]
    DIRECTION OUTPUT ;
    USE SIGNAL ;
    PORT
      LAYER M5 ;
        RECT 36.768 69.036 36.792 69.120 ;
    END
  END wo_d[434]
  PIN wo_d[435]
    DIRECTION OUTPUT ;
    USE SIGNAL ;
    PORT
      LAYER M5 ;
        RECT 36.864 69.036 36.888 69.120 ;
    END
  END wo_d[435]
  PIN wo_d[436]
    DIRECTION OUTPUT ;
    USE SIGNAL ;
    PORT
      LAYER M5 ;
        RECT 37.056 69.036 37.080 69.120 ;
    END
  END wo_d[436]
  PIN wo_d[437]
    DIRECTION OUTPUT ;
    USE SIGNAL ;
    PORT
      LAYER M3 ;
        RECT 37.224 69.082 37.242 69.120 ;
    END
  END wo_d[437]
  PIN wo_d[438]
    DIRECTION OUTPUT ;
    USE SIGNAL ;
    PORT
      LAYER M5 ;
        RECT 37.344 69.036 37.368 69.120 ;
    END
  END wo_d[438]
  PIN wo_d[439]
    DIRECTION OUTPUT ;
    USE SIGNAL ;
    PORT
      LAYER M3 ;
        RECT 37.512 69.082 37.530 69.120 ;
    END
  END wo_d[439]
  PIN wo_d[43]
    DIRECTION OUTPUT ;
    USE SIGNAL ;
    PORT
      LAYER M4 ;
        RECT 129.408 50.928 129.600 50.952 ;
    END
  END wo_d[43]
  PIN wo_d[440]
    DIRECTION OUTPUT ;
    USE SIGNAL ;
    PORT
      LAYER M3 ;
        RECT 37.656 69.082 37.674 69.120 ;
    END
  END wo_d[440]
  PIN wo_d[441]
    DIRECTION OUTPUT ;
    USE SIGNAL ;
    PORT
      LAYER M3 ;
        RECT 37.800 69.082 37.818 69.120 ;
    END
  END wo_d[441]
  PIN wo_d[442]
    DIRECTION OUTPUT ;
    USE SIGNAL ;
    PORT
      LAYER M3 ;
        RECT 37.944 69.082 37.962 69.120 ;
    END
  END wo_d[442]
  PIN wo_d[443]
    DIRECTION OUTPUT ;
    USE SIGNAL ;
    PORT
      LAYER M5 ;
        RECT 38.112 69.036 38.136 69.120 ;
    END
  END wo_d[443]
  PIN wo_d[444]
    DIRECTION OUTPUT ;
    USE SIGNAL ;
    PORT
      LAYER M3 ;
        RECT 38.232 69.082 38.250 69.120 ;
    END
  END wo_d[444]
  PIN wo_d[445]
    DIRECTION OUTPUT ;
    USE SIGNAL ;
    PORT
      LAYER M5 ;
        RECT 38.400 69.036 38.424 69.120 ;
    END
  END wo_d[445]
  PIN wo_d[446]
    DIRECTION OUTPUT ;
    USE SIGNAL ;
    PORT
      LAYER M3 ;
        RECT 38.520 69.082 38.538 69.120 ;
    END
  END wo_d[446]
  PIN wo_d[447]
    DIRECTION OUTPUT ;
    USE SIGNAL ;
    PORT
      LAYER M5 ;
        RECT 38.688 69.036 38.712 69.120 ;
    END
  END wo_d[447]
  PIN wo_d[448]
    DIRECTION OUTPUT ;
    USE SIGNAL ;
    PORT
      LAYER M3 ;
        RECT 38.880 69.082 38.898 69.120 ;
    END
  END wo_d[448]
  PIN wo_d[449]
    DIRECTION OUTPUT ;
    USE SIGNAL ;
    PORT
      LAYER M5 ;
        RECT 38.976 69.036 39.000 69.120 ;
    END
  END wo_d[449]
  PIN wo_d[44]
    DIRECTION OUTPUT ;
    USE SIGNAL ;
    PORT
      LAYER M4 ;
        RECT 0.000 46.272 0.192 46.296 ;
    END
  END wo_d[44]
  PIN wo_d[450]
    DIRECTION OUTPUT ;
    USE SIGNAL ;
    PORT
      LAYER M3 ;
        RECT 39.168 69.082 39.186 69.120 ;
    END
  END wo_d[450]
  PIN wo_d[451]
    DIRECTION OUTPUT ;
    USE SIGNAL ;
    PORT
      LAYER M3 ;
        RECT 39.312 69.082 39.330 69.120 ;
    END
  END wo_d[451]
  PIN wo_d[452]
    DIRECTION OUTPUT ;
    USE SIGNAL ;
    PORT
      LAYER M3 ;
        RECT 39.456 69.082 39.474 69.120 ;
    END
  END wo_d[452]
  PIN wo_d[453]
    DIRECTION OUTPUT ;
    USE SIGNAL ;
    PORT
      LAYER M3 ;
        RECT 39.600 69.082 39.618 69.120 ;
    END
  END wo_d[453]
  PIN wo_d[454]
    DIRECTION OUTPUT ;
    USE SIGNAL ;
    PORT
      LAYER M5 ;
        RECT 39.744 69.036 39.768 69.120 ;
    END
  END wo_d[454]
  PIN wo_d[455]
    DIRECTION OUTPUT ;
    USE SIGNAL ;
    PORT
      LAYER M3 ;
        RECT 39.888 69.082 39.906 69.120 ;
    END
  END wo_d[455]
  PIN wo_d[456]
    DIRECTION OUTPUT ;
    USE SIGNAL ;
    PORT
      LAYER M5 ;
        RECT 40.032 69.036 40.056 69.120 ;
    END
  END wo_d[456]
  PIN wo_d[457]
    DIRECTION OUTPUT ;
    USE SIGNAL ;
    PORT
      LAYER M3 ;
        RECT 40.176 69.082 40.194 69.120 ;
    END
  END wo_d[457]
  PIN wo_d[458]
    DIRECTION OUTPUT ;
    USE SIGNAL ;
    PORT
      LAYER M3 ;
        RECT 40.464 69.082 40.482 69.120 ;
    END
  END wo_d[458]
  PIN wo_d[459]
    DIRECTION OUTPUT ;
    USE SIGNAL ;
    PORT
      LAYER M3 ;
        RECT 40.680 69.082 40.698 69.120 ;
    END
  END wo_d[459]
  PIN wo_d[45]
    DIRECTION OUTPUT ;
    USE SIGNAL ;
    PORT
      LAYER M4 ;
        RECT 129.408 51.120 129.600 51.144 ;
    END
  END wo_d[45]
  PIN wo_d[460]
    DIRECTION OUTPUT ;
    USE SIGNAL ;
    PORT
      LAYER M5 ;
        RECT 40.800 69.036 40.824 69.120 ;
    END
  END wo_d[460]
  PIN wo_d[461]
    DIRECTION OUTPUT ;
    USE SIGNAL ;
    PORT
      LAYER M3 ;
        RECT 40.968 69.082 40.986 69.120 ;
    END
  END wo_d[461]
  PIN wo_d[462]
    DIRECTION OUTPUT ;
    USE SIGNAL ;
    PORT
      LAYER M3 ;
        RECT 41.112 69.082 41.130 69.120 ;
    END
  END wo_d[462]
  PIN wo_d[463]
    DIRECTION OUTPUT ;
    USE SIGNAL ;
    PORT
      LAYER M3 ;
        RECT 41.256 69.082 41.274 69.120 ;
    END
  END wo_d[463]
  PIN wo_d[464]
    DIRECTION OUTPUT ;
    USE SIGNAL ;
    PORT
      LAYER M3 ;
        RECT 41.400 69.082 41.418 69.120 ;
    END
  END wo_d[464]
  PIN wo_d[465]
    DIRECTION OUTPUT ;
    USE SIGNAL ;
    PORT
      LAYER M5 ;
        RECT 41.568 69.036 41.592 69.120 ;
    END
  END wo_d[465]
  PIN wo_d[466]
    DIRECTION OUTPUT ;
    USE SIGNAL ;
    PORT
      LAYER M3 ;
        RECT 41.688 69.082 41.706 69.120 ;
    END
  END wo_d[466]
  PIN wo_d[467]
    DIRECTION OUTPUT ;
    USE SIGNAL ;
    PORT
      LAYER M5 ;
        RECT 41.856 69.036 41.880 69.120 ;
    END
  END wo_d[467]
  PIN wo_d[468]
    DIRECTION OUTPUT ;
    USE SIGNAL ;
    PORT
      LAYER M3 ;
        RECT 41.976 69.082 41.994 69.120 ;
    END
  END wo_d[468]
  PIN wo_d[469]
    DIRECTION OUTPUT ;
    USE SIGNAL ;
    PORT
      LAYER M5 ;
        RECT 42.144 69.036 42.168 69.120 ;
    END
  END wo_d[469]
  PIN wo_d[46]
    DIRECTION OUTPUT ;
    USE SIGNAL ;
    PORT
      LAYER M4 ;
        RECT 0.000 46.464 0.192 46.488 ;
    END
  END wo_d[46]
  PIN wo_d[470]
    DIRECTION OUTPUT ;
    USE SIGNAL ;
    PORT
      LAYER M3 ;
        RECT 42.336 69.082 42.354 69.120 ;
    END
  END wo_d[470]
  PIN wo_d[471]
    DIRECTION OUTPUT ;
    USE SIGNAL ;
    PORT
      LAYER M5 ;
        RECT 42.432 69.036 42.456 69.120 ;
    END
  END wo_d[471]
  PIN wo_d[472]
    DIRECTION OUTPUT ;
    USE SIGNAL ;
    PORT
      LAYER M3 ;
        RECT 42.624 69.082 42.642 69.120 ;
    END
  END wo_d[472]
  PIN wo_d[473]
    DIRECTION OUTPUT ;
    USE SIGNAL ;
    PORT
      LAYER M3 ;
        RECT 42.768 69.082 42.786 69.120 ;
    END
  END wo_d[473]
  PIN wo_d[474]
    DIRECTION OUTPUT ;
    USE SIGNAL ;
    PORT
      LAYER M3 ;
        RECT 42.912 69.082 42.930 69.120 ;
    END
  END wo_d[474]
  PIN wo_d[475]
    DIRECTION OUTPUT ;
    USE SIGNAL ;
    PORT
      LAYER M3 ;
        RECT 43.056 69.082 43.074 69.120 ;
    END
  END wo_d[475]
  PIN wo_d[476]
    DIRECTION OUTPUT ;
    USE SIGNAL ;
    PORT
      LAYER M5 ;
        RECT 43.200 69.036 43.224 69.120 ;
    END
  END wo_d[476]
  PIN wo_d[477]
    DIRECTION OUTPUT ;
    USE SIGNAL ;
    PORT
      LAYER M3 ;
        RECT 43.344 69.082 43.362 69.120 ;
    END
  END wo_d[477]
  PIN wo_d[478]
    DIRECTION OUTPUT ;
    USE SIGNAL ;
    PORT
      LAYER M5 ;
        RECT 43.488 69.036 43.512 69.120 ;
    END
  END wo_d[478]
  PIN wo_d[479]
    DIRECTION OUTPUT ;
    USE SIGNAL ;
    PORT
      LAYER M5 ;
        RECT 43.680 69.036 43.704 69.120 ;
    END
  END wo_d[479]
  PIN wo_d[47]
    DIRECTION OUTPUT ;
    USE SIGNAL ;
    PORT
      LAYER M4 ;
        RECT 129.408 51.264 129.600 51.288 ;
    END
  END wo_d[47]
  PIN wo_d[480]
    DIRECTION OUTPUT ;
    USE SIGNAL ;
    PORT
      LAYER M5 ;
        RECT 43.776 69.036 43.800 69.120 ;
    END
  END wo_d[480]
  PIN wo_d[481]
    DIRECTION OUTPUT ;
    USE SIGNAL ;
    PORT
      LAYER M5 ;
        RECT 43.968 69.036 43.992 69.120 ;
    END
  END wo_d[481]
  PIN wo_d[482]
    DIRECTION OUTPUT ;
    USE SIGNAL ;
    PORT
      LAYER M5 ;
        RECT 44.064 69.036 44.088 69.120 ;
    END
  END wo_d[482]
  PIN wo_d[483]
    DIRECTION OUTPUT ;
    USE SIGNAL ;
    PORT
      LAYER M5 ;
        RECT 44.256 69.036 44.280 69.120 ;
    END
  END wo_d[483]
  PIN wo_d[484]
    DIRECTION OUTPUT ;
    USE SIGNAL ;
    PORT
      LAYER M3 ;
        RECT 44.424 69.082 44.442 69.120 ;
    END
  END wo_d[484]
  PIN wo_d[485]
    DIRECTION OUTPUT ;
    USE SIGNAL ;
    PORT
      LAYER M5 ;
        RECT 44.544 69.036 44.568 69.120 ;
    END
  END wo_d[485]
  PIN wo_d[486]
    DIRECTION OUTPUT ;
    USE SIGNAL ;
    PORT
      LAYER M3 ;
        RECT 44.712 69.082 44.730 69.120 ;
    END
  END wo_d[486]
  PIN wo_d[487]
    DIRECTION OUTPUT ;
    USE SIGNAL ;
    PORT
      LAYER M3 ;
        RECT 44.856 69.082 44.874 69.120 ;
    END
  END wo_d[487]
  PIN wo_d[488]
    DIRECTION OUTPUT ;
    USE SIGNAL ;
    PORT
      LAYER M3 ;
        RECT 45.000 69.082 45.018 69.120 ;
    END
  END wo_d[488]
  PIN wo_d[489]
    DIRECTION OUTPUT ;
    USE SIGNAL ;
    PORT
      LAYER M3 ;
        RECT 45.144 69.082 45.162 69.120 ;
    END
  END wo_d[489]
  PIN wo_d[48]
    DIRECTION OUTPUT ;
    USE SIGNAL ;
    PORT
      LAYER M4 ;
        RECT 0.000 46.656 0.192 46.680 ;
    END
  END wo_d[48]
  PIN wo_d[490]
    DIRECTION OUTPUT ;
    USE SIGNAL ;
    PORT
      LAYER M5 ;
        RECT 45.312 69.036 45.336 69.120 ;
    END
  END wo_d[490]
  PIN wo_d[491]
    DIRECTION OUTPUT ;
    USE SIGNAL ;
    PORT
      LAYER M3 ;
        RECT 45.432 69.082 45.450 69.120 ;
    END
  END wo_d[491]
  PIN wo_d[492]
    DIRECTION OUTPUT ;
    USE SIGNAL ;
    PORT
      LAYER M5 ;
        RECT 45.600 69.036 45.624 69.120 ;
    END
  END wo_d[492]
  PIN wo_d[493]
    DIRECTION OUTPUT ;
    USE SIGNAL ;
    PORT
      LAYER M3 ;
        RECT 45.792 69.082 45.810 69.120 ;
    END
  END wo_d[493]
  PIN wo_d[494]
    DIRECTION OUTPUT ;
    USE SIGNAL ;
    PORT
      LAYER M3 ;
        RECT 46.080 69.082 46.098 69.120 ;
    END
  END wo_d[494]
  PIN wo_d[495]
    DIRECTION OUTPUT ;
    USE SIGNAL ;
    PORT
      LAYER M3 ;
        RECT 46.224 69.082 46.242 69.120 ;
    END
  END wo_d[495]
  PIN wo_d[496]
    DIRECTION OUTPUT ;
    USE SIGNAL ;
    PORT
      LAYER M3 ;
        RECT 46.368 69.082 46.386 69.120 ;
    END
  END wo_d[496]
  PIN wo_d[497]
    DIRECTION OUTPUT ;
    USE SIGNAL ;
    PORT
      LAYER M3 ;
        RECT 46.512 69.082 46.530 69.120 ;
    END
  END wo_d[497]
  PIN wo_d[498]
    DIRECTION OUTPUT ;
    USE SIGNAL ;
    PORT
      LAYER M5 ;
        RECT 46.656 69.036 46.680 69.120 ;
    END
  END wo_d[498]
  PIN wo_d[499]
    DIRECTION OUTPUT ;
    USE SIGNAL ;
    PORT
      LAYER M3 ;
        RECT 46.800 69.082 46.818 69.120 ;
    END
  END wo_d[499]
  PIN wo_d[49]
    DIRECTION OUTPUT ;
    USE SIGNAL ;
    PORT
      LAYER M4 ;
        RECT 129.408 51.456 129.600 51.480 ;
    END
  END wo_d[49]
  PIN wo_d[4]
    DIRECTION OUTPUT ;
    USE SIGNAL ;
    PORT
      LAYER M4 ;
        RECT 0.000 42.288 0.192 42.312 ;
    END
  END wo_d[4]
  PIN wo_d[500]
    DIRECTION OUTPUT ;
    USE SIGNAL ;
    PORT
      LAYER M5 ;
        RECT 46.944 69.036 46.968 69.120 ;
    END
  END wo_d[500]
  PIN wo_d[501]
    DIRECTION OUTPUT ;
    USE SIGNAL ;
    PORT
      LAYER M5 ;
        RECT 47.136 69.036 47.160 69.120 ;
    END
  END wo_d[501]
  PIN wo_d[502]
    DIRECTION OUTPUT ;
    USE SIGNAL ;
    PORT
      LAYER M5 ;
        RECT 47.232 69.036 47.256 69.120 ;
    END
  END wo_d[502]
  PIN wo_d[503]
    DIRECTION OUTPUT ;
    USE SIGNAL ;
    PORT
      LAYER M5 ;
        RECT 47.424 69.036 47.448 69.120 ;
    END
  END wo_d[503]
  PIN wo_d[504]
    DIRECTION OUTPUT ;
    USE SIGNAL ;
    PORT
      LAYER M5 ;
        RECT 47.520 69.036 47.544 69.120 ;
    END
  END wo_d[504]
  PIN wo_d[505]
    DIRECTION OUTPUT ;
    USE SIGNAL ;
    PORT
      LAYER M5 ;
        RECT 47.712 69.036 47.736 69.120 ;
    END
  END wo_d[505]
  PIN wo_d[506]
    DIRECTION OUTPUT ;
    USE SIGNAL ;
    PORT
      LAYER M3 ;
        RECT 47.880 69.082 47.898 69.120 ;
    END
  END wo_d[506]
  PIN wo_d[507]
    DIRECTION OUTPUT ;
    USE SIGNAL ;
    PORT
      LAYER M5 ;
        RECT 48.000 69.036 48.024 69.120 ;
    END
  END wo_d[507]
  PIN wo_d[508]
    DIRECTION OUTPUT ;
    USE SIGNAL ;
    PORT
      LAYER M3 ;
        RECT 48.168 69.082 48.186 69.120 ;
    END
  END wo_d[508]
  PIN wo_d[509]
    DIRECTION OUTPUT ;
    USE SIGNAL ;
    PORT
      LAYER M3 ;
        RECT 48.312 69.082 48.330 69.120 ;
    END
  END wo_d[509]
  PIN wo_d[50]
    DIRECTION OUTPUT ;
    USE SIGNAL ;
    PORT
      LAYER M4 ;
        RECT 0.000 46.848 0.192 46.872 ;
    END
  END wo_d[50]
  PIN wo_d[510]
    DIRECTION OUTPUT ;
    USE SIGNAL ;
    PORT
      LAYER M3 ;
        RECT 48.456 69.082 48.474 69.120 ;
    END
  END wo_d[510]
  PIN wo_d[511]
    DIRECTION OUTPUT ;
    USE SIGNAL ;
    PORT
      LAYER M3 ;
        RECT 48.600 69.082 48.618 69.120 ;
    END
  END wo_d[511]
  PIN wo_d[512]
    DIRECTION OUTPUT ;
    USE SIGNAL ;
    PORT
      LAYER M5 ;
        RECT 48.768 69.036 48.792 69.120 ;
    END
  END wo_d[512]
  PIN wo_d[513]
    DIRECTION OUTPUT ;
    USE SIGNAL ;
    PORT
      LAYER M3 ;
        RECT 48.888 69.082 48.906 69.120 ;
    END
  END wo_d[513]
  PIN wo_d[514]
    DIRECTION OUTPUT ;
    USE SIGNAL ;
    PORT
      LAYER M5 ;
        RECT 49.056 69.036 49.080 69.120 ;
    END
  END wo_d[514]
  PIN wo_d[515]
    DIRECTION OUTPUT ;
    USE SIGNAL ;
    PORT
      LAYER M3 ;
        RECT 49.176 69.082 49.194 69.120 ;
    END
  END wo_d[515]
  PIN wo_d[516]
    DIRECTION OUTPUT ;
    USE SIGNAL ;
    PORT
      LAYER M5 ;
        RECT 49.344 69.036 49.368 69.120 ;
    END
  END wo_d[516]
  PIN wo_d[517]
    DIRECTION OUTPUT ;
    USE SIGNAL ;
    PORT
      LAYER M3 ;
        RECT 49.536 69.082 49.554 69.120 ;
    END
  END wo_d[517]
  PIN wo_d[518]
    DIRECTION OUTPUT ;
    USE SIGNAL ;
    PORT
      LAYER M5 ;
        RECT 49.632 69.036 49.656 69.120 ;
    END
  END wo_d[518]
  PIN wo_d[519]
    DIRECTION OUTPUT ;
    USE SIGNAL ;
    PORT
      LAYER M3 ;
        RECT 49.824 69.082 49.842 69.120 ;
    END
  END wo_d[519]
  PIN wo_d[51]
    DIRECTION OUTPUT ;
    USE SIGNAL ;
    PORT
      LAYER M4 ;
        RECT 129.408 51.600 129.600 51.624 ;
    END
  END wo_d[51]
  PIN wo_d[520]
    DIRECTION OUTPUT ;
    USE SIGNAL ;
    PORT
      LAYER M3 ;
        RECT 49.968 69.082 49.986 69.120 ;
    END
  END wo_d[520]
  PIN wo_d[521]
    DIRECTION OUTPUT ;
    USE SIGNAL ;
    PORT
      LAYER M3 ;
        RECT 50.112 69.082 50.130 69.120 ;
    END
  END wo_d[521]
  PIN wo_d[522]
    DIRECTION OUTPUT ;
    USE SIGNAL ;
    PORT
      LAYER M3 ;
        RECT 50.256 69.082 50.274 69.120 ;
    END
  END wo_d[522]
  PIN wo_d[523]
    DIRECTION OUTPUT ;
    USE SIGNAL ;
    PORT
      LAYER M5 ;
        RECT 50.400 69.036 50.424 69.120 ;
    END
  END wo_d[523]
  PIN wo_d[524]
    DIRECTION OUTPUT ;
    USE SIGNAL ;
    PORT
      LAYER M3 ;
        RECT 50.544 69.082 50.562 69.120 ;
    END
  END wo_d[524]
  PIN wo_d[525]
    DIRECTION OUTPUT ;
    USE SIGNAL ;
    PORT
      LAYER M5 ;
        RECT 50.688 69.036 50.712 69.120 ;
    END
  END wo_d[525]
  PIN wo_d[526]
    DIRECTION OUTPUT ;
    USE SIGNAL ;
    PORT
      LAYER M5 ;
        RECT 50.880 69.036 50.904 69.120 ;
    END
  END wo_d[526]
  PIN wo_d[527]
    DIRECTION OUTPUT ;
    USE SIGNAL ;
    PORT
      LAYER M5 ;
        RECT 50.976 69.036 51.000 69.120 ;
    END
  END wo_d[527]
  PIN wo_d[528]
    DIRECTION OUTPUT ;
    USE SIGNAL ;
    PORT
      LAYER M3 ;
        RECT 51.264 69.082 51.282 69.120 ;
    END
  END wo_d[528]
  PIN wo_d[529]
    DIRECTION OUTPUT ;
    USE SIGNAL ;
    PORT
      LAYER M5 ;
        RECT 51.456 69.036 51.480 69.120 ;
    END
  END wo_d[529]
  PIN wo_d[52]
    DIRECTION OUTPUT ;
    USE SIGNAL ;
    PORT
      LAYER M4 ;
        RECT 0.000 47.040 0.192 47.064 ;
    END
  END wo_d[52]
  PIN wo_d[530]
    DIRECTION OUTPUT ;
    USE SIGNAL ;
    PORT
      LAYER M3 ;
        RECT 51.624 69.082 51.642 69.120 ;
    END
  END wo_d[530]
  PIN wo_d[531]
    DIRECTION OUTPUT ;
    USE SIGNAL ;
    PORT
      LAYER M3 ;
        RECT 51.768 69.082 51.786 69.120 ;
    END
  END wo_d[531]
  PIN wo_d[532]
    DIRECTION OUTPUT ;
    USE SIGNAL ;
    PORT
      LAYER M3 ;
        RECT 51.912 69.082 51.930 69.120 ;
    END
  END wo_d[532]
  PIN wo_d[533]
    DIRECTION OUTPUT ;
    USE SIGNAL ;
    PORT
      LAYER M3 ;
        RECT 52.056 69.082 52.074 69.120 ;
    END
  END wo_d[533]
  PIN wo_d[534]
    DIRECTION OUTPUT ;
    USE SIGNAL ;
    PORT
      LAYER M5 ;
        RECT 52.224 69.036 52.248 69.120 ;
    END
  END wo_d[534]
  PIN wo_d[535]
    DIRECTION OUTPUT ;
    USE SIGNAL ;
    PORT
      LAYER M3 ;
        RECT 52.344 69.082 52.362 69.120 ;
    END
  END wo_d[535]
  PIN wo_d[536]
    DIRECTION OUTPUT ;
    USE SIGNAL ;
    PORT
      LAYER M5 ;
        RECT 52.512 69.036 52.536 69.120 ;
    END
  END wo_d[536]
  PIN wo_d[537]
    DIRECTION OUTPUT ;
    USE SIGNAL ;
    PORT
      LAYER M3 ;
        RECT 52.704 69.082 52.722 69.120 ;
    END
  END wo_d[537]
  PIN wo_d[538]
    DIRECTION OUTPUT ;
    USE SIGNAL ;
    PORT
      LAYER M5 ;
        RECT 52.800 69.036 52.824 69.120 ;
    END
  END wo_d[538]
  PIN wo_d[539]
    DIRECTION OUTPUT ;
    USE SIGNAL ;
    PORT
      LAYER M3 ;
        RECT 52.992 69.082 53.010 69.120 ;
    END
  END wo_d[539]
  PIN wo_d[53]
    DIRECTION OUTPUT ;
    USE SIGNAL ;
    PORT
      LAYER M4 ;
        RECT 129.408 51.696 129.600 51.720 ;
    END
  END wo_d[53]
  PIN wo_d[540]
    DIRECTION OUTPUT ;
    USE SIGNAL ;
    PORT
      LAYER M5 ;
        RECT 53.088 69.036 53.112 69.120 ;
    END
  END wo_d[540]
  PIN wo_d[541]
    DIRECTION OUTPUT ;
    USE SIGNAL ;
    PORT
      LAYER M3 ;
        RECT 53.280 69.082 53.298 69.120 ;
    END
  END wo_d[541]
  PIN wo_d[542]
    DIRECTION OUTPUT ;
    USE SIGNAL ;
    PORT
      LAYER M3 ;
        RECT 53.424 69.082 53.442 69.120 ;
    END
  END wo_d[542]
  PIN wo_d[543]
    DIRECTION OUTPUT ;
    USE SIGNAL ;
    PORT
      LAYER M3 ;
        RECT 53.568 69.082 53.586 69.120 ;
    END
  END wo_d[543]
  PIN wo_d[544]
    DIRECTION OUTPUT ;
    USE SIGNAL ;
    PORT
      LAYER M3 ;
        RECT 53.712 69.082 53.730 69.120 ;
    END
  END wo_d[544]
  PIN wo_d[545]
    DIRECTION OUTPUT ;
    USE SIGNAL ;
    PORT
      LAYER M5 ;
        RECT 53.856 69.036 53.880 69.120 ;
    END
  END wo_d[545]
  PIN wo_d[546]
    DIRECTION OUTPUT ;
    USE SIGNAL ;
    PORT
      LAYER M3 ;
        RECT 54.000 69.082 54.018 69.120 ;
    END
  END wo_d[546]
  PIN wo_d[547]
    DIRECTION OUTPUT ;
    USE SIGNAL ;
    PORT
      LAYER M5 ;
        RECT 54.144 69.036 54.168 69.120 ;
    END
  END wo_d[547]
  PIN wo_d[548]
    DIRECTION OUTPUT ;
    USE SIGNAL ;
    PORT
      LAYER M5 ;
        RECT 54.336 69.036 54.360 69.120 ;
    END
  END wo_d[548]
  PIN wo_d[549]
    DIRECTION OUTPUT ;
    USE SIGNAL ;
    PORT
      LAYER M5 ;
        RECT 54.432 69.036 54.456 69.120 ;
    END
  END wo_d[549]
  PIN wo_d[54]
    DIRECTION OUTPUT ;
    USE SIGNAL ;
    PORT
      LAYER M4 ;
        RECT 0.000 47.280 0.192 47.304 ;
    END
  END wo_d[54]
  PIN wo_d[550]
    DIRECTION OUTPUT ;
    USE SIGNAL ;
    PORT
      LAYER M5 ;
        RECT 54.624 69.036 54.648 69.120 ;
    END
  END wo_d[550]
  PIN wo_d[551]
    DIRECTION OUTPUT ;
    USE SIGNAL ;
    PORT
      LAYER M5 ;
        RECT 54.720 69.036 54.744 69.120 ;
    END
  END wo_d[551]
  PIN wo_d[552]
    DIRECTION OUTPUT ;
    USE SIGNAL ;
    PORT
      LAYER M5 ;
        RECT 54.912 69.036 54.936 69.120 ;
    END
  END wo_d[552]
  PIN wo_d[553]
    DIRECTION OUTPUT ;
    USE SIGNAL ;
    PORT
      LAYER M3 ;
        RECT 55.080 69.082 55.098 69.120 ;
    END
  END wo_d[553]
  PIN wo_d[554]
    DIRECTION OUTPUT ;
    USE SIGNAL ;
    PORT
      LAYER M5 ;
        RECT 55.200 69.036 55.224 69.120 ;
    END
  END wo_d[554]
  PIN wo_d[555]
    DIRECTION OUTPUT ;
    USE SIGNAL ;
    PORT
      LAYER M3 ;
        RECT 55.368 69.082 55.386 69.120 ;
    END
  END wo_d[555]
  PIN wo_d[556]
    DIRECTION OUTPUT ;
    USE SIGNAL ;
    PORT
      LAYER M3 ;
        RECT 55.512 69.082 55.530 69.120 ;
    END
  END wo_d[556]
  PIN wo_d[557]
    DIRECTION OUTPUT ;
    USE SIGNAL ;
    PORT
      LAYER M3 ;
        RECT 55.656 69.082 55.674 69.120 ;
    END
  END wo_d[557]
  PIN wo_d[558]
    DIRECTION OUTPUT ;
    USE SIGNAL ;
    PORT
      LAYER M3 ;
        RECT 55.800 69.082 55.818 69.120 ;
    END
  END wo_d[558]
  PIN wo_d[559]
    DIRECTION OUTPUT ;
    USE SIGNAL ;
    PORT
      LAYER M5 ;
        RECT 55.968 69.036 55.992 69.120 ;
    END
  END wo_d[559]
  PIN wo_d[55]
    DIRECTION OUTPUT ;
    USE SIGNAL ;
    PORT
      LAYER M4 ;
        RECT 129.408 51.888 129.600 51.912 ;
    END
  END wo_d[55]
  PIN wo_d[560]
    DIRECTION OUTPUT ;
    USE SIGNAL ;
    PORT
      LAYER M3 ;
        RECT 56.088 69.082 56.106 69.120 ;
    END
  END wo_d[560]
  PIN wo_d[561]
    DIRECTION OUTPUT ;
    USE SIGNAL ;
    PORT
      LAYER M5 ;
        RECT 56.256 69.036 56.280 69.120 ;
    END
  END wo_d[561]
  PIN wo_d[562]
    DIRECTION OUTPUT ;
    USE SIGNAL ;
    PORT
      LAYER M3 ;
        RECT 56.376 69.082 56.394 69.120 ;
    END
  END wo_d[562]
  PIN wo_d[563]
    DIRECTION OUTPUT ;
    USE SIGNAL ;
    PORT
      LAYER M3 ;
        RECT 56.664 69.082 56.682 69.120 ;
    END
  END wo_d[563]
  PIN wo_d[564]
    DIRECTION OUTPUT ;
    USE SIGNAL ;
    PORT
      LAYER M3 ;
        RECT 56.880 69.082 56.898 69.120 ;
    END
  END wo_d[564]
  PIN wo_d[565]
    DIRECTION OUTPUT ;
    USE SIGNAL ;
    PORT
      LAYER M3 ;
        RECT 57.024 69.082 57.042 69.120 ;
    END
  END wo_d[565]
  PIN wo_d[566]
    DIRECTION OUTPUT ;
    USE SIGNAL ;
    PORT
      LAYER M3 ;
        RECT 57.168 69.082 57.186 69.120 ;
    END
  END wo_d[566]
  PIN wo_d[567]
    DIRECTION OUTPUT ;
    USE SIGNAL ;
    PORT
      LAYER M5 ;
        RECT 57.312 69.036 57.336 69.120 ;
    END
  END wo_d[567]
  PIN wo_d[568]
    DIRECTION OUTPUT ;
    USE SIGNAL ;
    PORT
      LAYER M3 ;
        RECT 57.456 69.082 57.474 69.120 ;
    END
  END wo_d[568]
  PIN wo_d[569]
    DIRECTION OUTPUT ;
    USE SIGNAL ;
    PORT
      LAYER M5 ;
        RECT 57.600 69.036 57.624 69.120 ;
    END
  END wo_d[569]
  PIN wo_d[56]
    DIRECTION OUTPUT ;
    USE SIGNAL ;
    PORT
      LAYER M4 ;
        RECT 0.000 47.472 0.192 47.496 ;
    END
  END wo_d[56]
  PIN wo_d[570]
    DIRECTION OUTPUT ;
    USE SIGNAL ;
    PORT
      LAYER M5 ;
        RECT 57.792 69.036 57.816 69.120 ;
    END
  END wo_d[570]
  PIN wo_d[571]
    DIRECTION OUTPUT ;
    USE SIGNAL ;
    PORT
      LAYER M5 ;
        RECT 57.888 69.036 57.912 69.120 ;
    END
  END wo_d[571]
  PIN wo_d[572]
    DIRECTION OUTPUT ;
    USE SIGNAL ;
    PORT
      LAYER M5 ;
        RECT 58.080 69.036 58.104 69.120 ;
    END
  END wo_d[572]
  PIN wo_d[573]
    DIRECTION OUTPUT ;
    USE SIGNAL ;
    PORT
      LAYER M3 ;
        RECT 58.248 69.082 58.266 69.120 ;
    END
  END wo_d[573]
  PIN wo_d[574]
    DIRECTION OUTPUT ;
    USE SIGNAL ;
    PORT
      LAYER M5 ;
        RECT 58.368 69.036 58.392 69.120 ;
    END
  END wo_d[574]
  PIN wo_d[575]
    DIRECTION OUTPUT ;
    USE SIGNAL ;
    PORT
      LAYER M3 ;
        RECT 58.536 69.082 58.554 69.120 ;
    END
  END wo_d[575]
  PIN wo_d[576]
    DIRECTION OUTPUT ;
    USE SIGNAL ;
    PORT
      LAYER M5 ;
        RECT 58.656 69.036 58.680 69.120 ;
    END
  END wo_d[576]
  PIN wo_d[577]
    DIRECTION OUTPUT ;
    USE SIGNAL ;
    PORT
      LAYER M3 ;
        RECT 58.824 69.082 58.842 69.120 ;
    END
  END wo_d[577]
  PIN wo_d[578]
    DIRECTION OUTPUT ;
    USE SIGNAL ;
    PORT
      LAYER M3 ;
        RECT 58.968 69.082 58.986 69.120 ;
    END
  END wo_d[578]
  PIN wo_d[579]
    DIRECTION OUTPUT ;
    USE SIGNAL ;
    PORT
      LAYER M3 ;
        RECT 59.112 69.082 59.130 69.120 ;
    END
  END wo_d[579]
  PIN wo_d[57]
    DIRECTION OUTPUT ;
    USE SIGNAL ;
    PORT
      LAYER M4 ;
        RECT 129.408 52.032 129.600 52.056 ;
    END
  END wo_d[57]
  PIN wo_d[580]
    DIRECTION OUTPUT ;
    USE SIGNAL ;
    PORT
      LAYER M3 ;
        RECT 59.256 69.082 59.274 69.120 ;
    END
  END wo_d[580]
  PIN wo_d[581]
    DIRECTION OUTPUT ;
    USE SIGNAL ;
    PORT
      LAYER M5 ;
        RECT 59.424 69.036 59.448 69.120 ;
    END
  END wo_d[581]
  PIN wo_d[582]
    DIRECTION OUTPUT ;
    USE SIGNAL ;
    PORT
      LAYER M3 ;
        RECT 59.544 69.082 59.562 69.120 ;
    END
  END wo_d[582]
  PIN wo_d[583]
    DIRECTION OUTPUT ;
    USE SIGNAL ;
    PORT
      LAYER M5 ;
        RECT 59.712 69.036 59.736 69.120 ;
    END
  END wo_d[583]
  PIN wo_d[584]
    DIRECTION OUTPUT ;
    USE SIGNAL ;
    PORT
      LAYER M3 ;
        RECT 59.904 69.082 59.922 69.120 ;
    END
  END wo_d[584]
  PIN wo_d[585]
    DIRECTION OUTPUT ;
    USE SIGNAL ;
    PORT
      LAYER M5 ;
        RECT 60.000 69.036 60.024 69.120 ;
    END
  END wo_d[585]
  PIN wo_d[586]
    DIRECTION OUTPUT ;
    USE SIGNAL ;
    PORT
      LAYER M3 ;
        RECT 60.192 69.082 60.210 69.120 ;
    END
  END wo_d[586]
  PIN wo_d[587]
    DIRECTION OUTPUT ;
    USE SIGNAL ;
    PORT
      LAYER M5 ;
        RECT 60.288 69.036 60.312 69.120 ;
    END
  END wo_d[587]
  PIN wo_d[588]
    DIRECTION OUTPUT ;
    USE SIGNAL ;
    PORT
      LAYER M3 ;
        RECT 60.480 69.082 60.498 69.120 ;
    END
  END wo_d[588]
  PIN wo_d[589]
    DIRECTION OUTPUT ;
    USE SIGNAL ;
    PORT
      LAYER M3 ;
        RECT 60.624 69.082 60.642 69.120 ;
    END
  END wo_d[589]
  PIN wo_d[58]
    DIRECTION OUTPUT ;
    USE SIGNAL ;
    PORT
      LAYER M4 ;
        RECT 0.000 47.664 0.192 47.688 ;
    END
  END wo_d[58]
  PIN wo_d[590]
    DIRECTION OUTPUT ;
    USE SIGNAL ;
    PORT
      LAYER M3 ;
        RECT 60.768 69.082 60.786 69.120 ;
    END
  END wo_d[590]
  PIN wo_d[591]
    DIRECTION OUTPUT ;
    USE SIGNAL ;
    PORT
      LAYER M3 ;
        RECT 60.912 69.082 60.930 69.120 ;
    END
  END wo_d[591]
  PIN wo_d[592]
    DIRECTION OUTPUT ;
    USE SIGNAL ;
    PORT
      LAYER M5 ;
        RECT 61.056 69.036 61.080 69.120 ;
    END
  END wo_d[592]
  PIN wo_d[593]
    DIRECTION OUTPUT ;
    USE SIGNAL ;
    PORT
      LAYER M3 ;
        RECT 61.200 69.082 61.218 69.120 ;
    END
  END wo_d[593]
  PIN wo_d[594]
    DIRECTION OUTPUT ;
    USE SIGNAL ;
    PORT
      LAYER M5 ;
        RECT 61.344 69.036 61.368 69.120 ;
    END
  END wo_d[594]
  PIN wo_d[595]
    DIRECTION OUTPUT ;
    USE SIGNAL ;
    PORT
      LAYER M5 ;
        RECT 61.536 69.036 61.560 69.120 ;
    END
  END wo_d[595]
  PIN wo_d[596]
    DIRECTION OUTPUT ;
    USE SIGNAL ;
    PORT
      LAYER M5 ;
        RECT 61.632 69.036 61.656 69.120 ;
    END
  END wo_d[596]
  PIN wo_d[597]
    DIRECTION OUTPUT ;
    USE SIGNAL ;
    PORT
      LAYER M3 ;
        RECT 61.848 69.082 61.866 69.120 ;
    END
  END wo_d[597]
  PIN wo_d[598]
    DIRECTION OUTPUT ;
    USE SIGNAL ;
    PORT
      LAYER M3 ;
        RECT 62.064 69.082 62.082 69.120 ;
    END
  END wo_d[598]
  PIN wo_d[599]
    DIRECTION OUTPUT ;
    USE SIGNAL ;
    PORT
      LAYER M3 ;
        RECT 62.280 69.082 62.298 69.120 ;
    END
  END wo_d[599]
  PIN wo_d[59]
    DIRECTION OUTPUT ;
    USE SIGNAL ;
    PORT
      LAYER M4 ;
        RECT 129.408 52.224 129.600 52.248 ;
    END
  END wo_d[59]
  PIN wo_d[5]
    DIRECTION OUTPUT ;
    USE SIGNAL ;
    PORT
      LAYER M4 ;
        RECT 129.408 48.000 129.600 48.024 ;
    END
  END wo_d[5]
  PIN wo_d[600]
    DIRECTION OUTPUT ;
    USE SIGNAL ;
    PORT
      LAYER M3 ;
        RECT 62.424 69.082 62.442 69.120 ;
    END
  END wo_d[600]
  PIN wo_d[601]
    DIRECTION OUTPUT ;
    USE SIGNAL ;
    PORT
      LAYER M3 ;
        RECT 62.568 69.082 62.586 69.120 ;
    END
  END wo_d[601]
  PIN wo_d[602]
    DIRECTION OUTPUT ;
    USE SIGNAL ;
    PORT
      LAYER M3 ;
        RECT 62.712 69.082 62.730 69.120 ;
    END
  END wo_d[602]
  PIN wo_d[603]
    DIRECTION OUTPUT ;
    USE SIGNAL ;
    PORT
      LAYER M5 ;
        RECT 62.880 69.036 62.904 69.120 ;
    END
  END wo_d[603]
  PIN wo_d[604]
    DIRECTION OUTPUT ;
    USE SIGNAL ;
    PORT
      LAYER M3 ;
        RECT 63.000 69.082 63.018 69.120 ;
    END
  END wo_d[604]
  PIN wo_d[605]
    DIRECTION OUTPUT ;
    USE SIGNAL ;
    PORT
      LAYER M5 ;
        RECT 63.168 69.036 63.192 69.120 ;
    END
  END wo_d[605]
  PIN wo_d[606]
    DIRECTION OUTPUT ;
    USE SIGNAL ;
    PORT
      LAYER M3 ;
        RECT 63.360 69.082 63.378 69.120 ;
    END
  END wo_d[606]
  PIN wo_d[607]
    DIRECTION OUTPUT ;
    USE SIGNAL ;
    PORT
      LAYER M5 ;
        RECT 63.456 69.036 63.480 69.120 ;
    END
  END wo_d[607]
  PIN wo_d[608]
    DIRECTION OUTPUT ;
    USE SIGNAL ;
    PORT
      LAYER M3 ;
        RECT 63.648 69.082 63.666 69.120 ;
    END
  END wo_d[608]
  PIN wo_d[609]
    DIRECTION OUTPUT ;
    USE SIGNAL ;
    PORT
      LAYER M5 ;
        RECT 63.744 69.036 63.768 69.120 ;
    END
  END wo_d[609]
  PIN wo_d[60]
    DIRECTION OUTPUT ;
    USE SIGNAL ;
    PORT
      LAYER M4 ;
        RECT 0.000 47.856 0.192 47.880 ;
    END
  END wo_d[60]
  PIN wo_d[610]
    DIRECTION OUTPUT ;
    USE SIGNAL ;
    PORT
      LAYER M3 ;
        RECT 63.936 69.082 63.954 69.120 ;
    END
  END wo_d[610]
  PIN wo_d[611]
    DIRECTION OUTPUT ;
    USE SIGNAL ;
    PORT
      LAYER M3 ;
        RECT 64.080 69.082 64.098 69.120 ;
    END
  END wo_d[611]
  PIN wo_d[612]
    DIRECTION OUTPUT ;
    USE SIGNAL ;
    PORT
      LAYER M3 ;
        RECT 65.376 69.082 65.394 69.120 ;
    END
  END wo_d[612]
  PIN wo_d[613]
    DIRECTION OUTPUT ;
    USE SIGNAL ;
    PORT
      LAYER M3 ;
        RECT 65.520 69.082 65.538 69.120 ;
    END
  END wo_d[613]
  PIN wo_d[614]
    DIRECTION OUTPUT ;
    USE SIGNAL ;
    PORT
      LAYER M5 ;
        RECT 65.664 69.036 65.688 69.120 ;
    END
  END wo_d[614]
  PIN wo_d[615]
    DIRECTION OUTPUT ;
    USE SIGNAL ;
    PORT
      LAYER M3 ;
        RECT 65.808 69.082 65.826 69.120 ;
    END
  END wo_d[615]
  PIN wo_d[616]
    DIRECTION OUTPUT ;
    USE SIGNAL ;
    PORT
      LAYER M5 ;
        RECT 65.952 69.036 65.976 69.120 ;
    END
  END wo_d[616]
  PIN wo_d[617]
    DIRECTION OUTPUT ;
    USE SIGNAL ;
    PORT
      LAYER M5 ;
        RECT 66.144 69.036 66.168 69.120 ;
    END
  END wo_d[617]
  PIN wo_d[618]
    DIRECTION OUTPUT ;
    USE SIGNAL ;
    PORT
      LAYER M5 ;
        RECT 66.240 69.036 66.264 69.120 ;
    END
  END wo_d[618]
  PIN wo_d[619]
    DIRECTION OUTPUT ;
    USE SIGNAL ;
    PORT
      LAYER M5 ;
        RECT 66.432 69.036 66.456 69.120 ;
    END
  END wo_d[619]
  PIN wo_d[61]
    DIRECTION OUTPUT ;
    USE SIGNAL ;
    PORT
      LAYER M4 ;
        RECT 129.408 52.368 129.600 52.392 ;
    END
  END wo_d[61]
  PIN wo_d[620]
    DIRECTION OUTPUT ;
    USE SIGNAL ;
    PORT
      LAYER M3 ;
        RECT 66.600 69.082 66.618 69.120 ;
    END
  END wo_d[620]
  PIN wo_d[621]
    DIRECTION OUTPUT ;
    USE SIGNAL ;
    PORT
      LAYER M5 ;
        RECT 66.720 69.036 66.744 69.120 ;
    END
  END wo_d[621]
  PIN wo_d[622]
    DIRECTION OUTPUT ;
    USE SIGNAL ;
    PORT
      LAYER M3 ;
        RECT 66.888 69.082 66.906 69.120 ;
    END
  END wo_d[622]
  PIN wo_d[623]
    DIRECTION OUTPUT ;
    USE SIGNAL ;
    PORT
      LAYER M5 ;
        RECT 67.008 69.036 67.032 69.120 ;
    END
  END wo_d[623]
  PIN wo_d[624]
    DIRECTION OUTPUT ;
    USE SIGNAL ;
    PORT
      LAYER M3 ;
        RECT 67.176 69.082 67.194 69.120 ;
    END
  END wo_d[624]
  PIN wo_d[625]
    DIRECTION OUTPUT ;
    USE SIGNAL ;
    PORT
      LAYER M3 ;
        RECT 67.392 69.082 67.410 69.120 ;
    END
  END wo_d[625]
  PIN wo_d[626]
    DIRECTION OUTPUT ;
    USE SIGNAL ;
    PORT
      LAYER M3 ;
        RECT 67.608 69.082 67.626 69.120 ;
    END
  END wo_d[626]
  PIN wo_d[627]
    DIRECTION OUTPUT ;
    USE SIGNAL ;
    PORT
      LAYER M5 ;
        RECT 67.776 69.036 67.800 69.120 ;
    END
  END wo_d[627]
  PIN wo_d[628]
    DIRECTION OUTPUT ;
    USE SIGNAL ;
    PORT
      LAYER M3 ;
        RECT 67.968 69.082 67.986 69.120 ;
    END
  END wo_d[628]
  PIN wo_d[629]
    DIRECTION OUTPUT ;
    USE SIGNAL ;
    PORT
      LAYER M5 ;
        RECT 68.064 69.036 68.088 69.120 ;
    END
  END wo_d[629]
  PIN wo_d[62]
    DIRECTION OUTPUT ;
    USE SIGNAL ;
    PORT
      LAYER M4 ;
        RECT 0.000 48.048 0.192 48.072 ;
    END
  END wo_d[62]
  PIN wo_d[630]
    DIRECTION OUTPUT ;
    USE SIGNAL ;
    PORT
      LAYER M3 ;
        RECT 68.256 69.082 68.274 69.120 ;
    END
  END wo_d[630]
  PIN wo_d[631]
    DIRECTION OUTPUT ;
    USE SIGNAL ;
    PORT
      LAYER M3 ;
        RECT 68.400 69.082 68.418 69.120 ;
    END
  END wo_d[631]
  PIN wo_d[632]
    DIRECTION OUTPUT ;
    USE SIGNAL ;
    PORT
      LAYER M3 ;
        RECT 68.544 69.082 68.562 69.120 ;
    END
  END wo_d[632]
  PIN wo_d[633]
    DIRECTION OUTPUT ;
    USE SIGNAL ;
    PORT
      LAYER M3 ;
        RECT 68.688 69.082 68.706 69.120 ;
    END
  END wo_d[633]
  PIN wo_d[634]
    DIRECTION OUTPUT ;
    USE SIGNAL ;
    PORT
      LAYER M3 ;
        RECT 68.832 69.082 68.850 69.120 ;
    END
  END wo_d[634]
  PIN wo_d[635]
    DIRECTION OUTPUT ;
    USE SIGNAL ;
    PORT
      LAYER M3 ;
        RECT 68.976 69.082 68.994 69.120 ;
    END
  END wo_d[635]
  PIN wo_d[636]
    DIRECTION OUTPUT ;
    USE SIGNAL ;
    PORT
      LAYER M5 ;
        RECT 69.120 69.036 69.144 69.120 ;
    END
  END wo_d[636]
  PIN wo_d[637]
    DIRECTION OUTPUT ;
    USE SIGNAL ;
    PORT
      LAYER M3 ;
        RECT 69.264 69.082 69.282 69.120 ;
    END
  END wo_d[637]
  PIN wo_d[638]
    DIRECTION OUTPUT ;
    USE SIGNAL ;
    PORT
      LAYER M5 ;
        RECT 69.408 69.036 69.432 69.120 ;
    END
  END wo_d[638]
  PIN wo_d[639]
    DIRECTION OUTPUT ;
    USE SIGNAL ;
    PORT
      LAYER M5 ;
        RECT 69.600 69.036 69.624 69.120 ;
    END
  END wo_d[639]
  PIN wo_d[63]
    DIRECTION OUTPUT ;
    USE SIGNAL ;
    PORT
      LAYER M4 ;
        RECT 129.408 52.560 129.600 52.584 ;
    END
  END wo_d[63]
  PIN wo_d[640]
    DIRECTION OUTPUT ;
    USE SIGNAL ;
    PORT
      LAYER M5 ;
        RECT 69.696 69.036 69.720 69.120 ;
    END
  END wo_d[640]
  PIN wo_d[641]
    DIRECTION OUTPUT ;
    USE SIGNAL ;
    PORT
      LAYER M5 ;
        RECT 69.888 69.036 69.912 69.120 ;
    END
  END wo_d[641]
  PIN wo_d[642]
    DIRECTION OUTPUT ;
    USE SIGNAL ;
    PORT
      LAYER M3 ;
        RECT 70.056 69.082 70.074 69.120 ;
    END
  END wo_d[642]
  PIN wo_d[643]
    DIRECTION OUTPUT ;
    USE SIGNAL ;
    PORT
      LAYER M5 ;
        RECT 70.176 69.036 70.200 69.120 ;
    END
  END wo_d[643]
  PIN wo_d[644]
    DIRECTION OUTPUT ;
    USE SIGNAL ;
    PORT
      LAYER M3 ;
        RECT 70.344 69.082 70.362 69.120 ;
    END
  END wo_d[644]
  PIN wo_d[645]
    DIRECTION OUTPUT ;
    USE SIGNAL ;
    PORT
      LAYER M5 ;
        RECT 70.464 69.036 70.488 69.120 ;
    END
  END wo_d[645]
  PIN wo_d[646]
    DIRECTION OUTPUT ;
    USE SIGNAL ;
    PORT
      LAYER M3 ;
        RECT 70.632 69.082 70.650 69.120 ;
    END
  END wo_d[646]
  PIN wo_d[647]
    DIRECTION OUTPUT ;
    USE SIGNAL ;
    PORT
      LAYER M3 ;
        RECT 70.776 69.082 70.794 69.120 ;
    END
  END wo_d[647]
  PIN wo_d[648]
    DIRECTION OUTPUT ;
    USE SIGNAL ;
    PORT
      LAYER M3 ;
        RECT 70.920 69.082 70.938 69.120 ;
    END
  END wo_d[648]
  PIN wo_d[649]
    DIRECTION OUTPUT ;
    USE SIGNAL ;
    PORT
      LAYER M3 ;
        RECT 71.064 69.082 71.082 69.120 ;
    END
  END wo_d[649]
  PIN wo_d[64]
    DIRECTION OUTPUT ;
    USE SIGNAL ;
    PORT
      LAYER M4 ;
        RECT 0.000 48.240 0.192 48.264 ;
    END
  END wo_d[64]
  PIN wo_d[650]
    DIRECTION OUTPUT ;
    USE SIGNAL ;
    PORT
      LAYER M5 ;
        RECT 71.232 69.036 71.256 69.120 ;
    END
  END wo_d[650]
  PIN wo_d[651]
    DIRECTION OUTPUT ;
    USE SIGNAL ;
    PORT
      LAYER M3 ;
        RECT 71.352 69.082 71.370 69.120 ;
    END
  END wo_d[651]
  PIN wo_d[652]
    DIRECTION OUTPUT ;
    USE SIGNAL ;
    PORT
      LAYER M5 ;
        RECT 71.520 69.036 71.544 69.120 ;
    END
  END wo_d[652]
  PIN wo_d[653]
    DIRECTION OUTPUT ;
    USE SIGNAL ;
    PORT
      LAYER M3 ;
        RECT 71.712 69.082 71.730 69.120 ;
    END
  END wo_d[653]
  PIN wo_d[654]
    DIRECTION OUTPUT ;
    USE SIGNAL ;
    PORT
      LAYER M5 ;
        RECT 71.808 69.036 71.832 69.120 ;
    END
  END wo_d[654]
  PIN wo_d[655]
    DIRECTION OUTPUT ;
    USE SIGNAL ;
    PORT
      LAYER M3 ;
        RECT 72.000 69.082 72.018 69.120 ;
    END
  END wo_d[655]
  PIN wo_d[656]
    DIRECTION OUTPUT ;
    USE SIGNAL ;
    PORT
      LAYER M5 ;
        RECT 72.096 69.036 72.120 69.120 ;
    END
  END wo_d[656]
  PIN wo_d[657]
    DIRECTION OUTPUT ;
    USE SIGNAL ;
    PORT
      LAYER M3 ;
        RECT 72.288 69.082 72.306 69.120 ;
    END
  END wo_d[657]
  PIN wo_d[658]
    DIRECTION OUTPUT ;
    USE SIGNAL ;
    PORT
      LAYER M3 ;
        RECT 72.432 69.082 72.450 69.120 ;
    END
  END wo_d[658]
  PIN wo_d[659]
    DIRECTION OUTPUT ;
    USE SIGNAL ;
    PORT
      LAYER M3 ;
        RECT 72.576 69.082 72.594 69.120 ;
    END
  END wo_d[659]
  PIN wo_d[65]
    DIRECTION OUTPUT ;
    USE SIGNAL ;
    PORT
      LAYER M4 ;
        RECT 129.408 52.656 129.600 52.680 ;
    END
  END wo_d[65]
  PIN wo_d[660]
    DIRECTION OUTPUT ;
    USE SIGNAL ;
    PORT
      LAYER M3 ;
        RECT 72.792 69.082 72.810 69.120 ;
    END
  END wo_d[660]
  PIN wo_d[661]
    DIRECTION OUTPUT ;
    USE SIGNAL ;
    PORT
      LAYER M5 ;
        RECT 73.056 69.036 73.080 69.120 ;
    END
  END wo_d[661]
  PIN wo_d[662]
    DIRECTION OUTPUT ;
    USE SIGNAL ;
    PORT
      LAYER M5 ;
        RECT 73.152 69.036 73.176 69.120 ;
    END
  END wo_d[662]
  PIN wo_d[663]
    DIRECTION OUTPUT ;
    USE SIGNAL ;
    PORT
      LAYER M5 ;
        RECT 73.344 69.036 73.368 69.120 ;
    END
  END wo_d[663]
  PIN wo_d[664]
    DIRECTION OUTPUT ;
    USE SIGNAL ;
    PORT
      LAYER M3 ;
        RECT 73.512 69.082 73.530 69.120 ;
    END
  END wo_d[664]
  PIN wo_d[665]
    DIRECTION OUTPUT ;
    USE SIGNAL ;
    PORT
      LAYER M5 ;
        RECT 73.632 69.036 73.656 69.120 ;
    END
  END wo_d[665]
  PIN wo_d[666]
    DIRECTION OUTPUT ;
    USE SIGNAL ;
    PORT
      LAYER M3 ;
        RECT 73.800 69.082 73.818 69.120 ;
    END
  END wo_d[666]
  PIN wo_d[667]
    DIRECTION OUTPUT ;
    USE SIGNAL ;
    PORT
      LAYER M3 ;
        RECT 73.944 69.082 73.962 69.120 ;
    END
  END wo_d[667]
  PIN wo_d[668]
    DIRECTION OUTPUT ;
    USE SIGNAL ;
    PORT
      LAYER M3 ;
        RECT 74.088 69.082 74.106 69.120 ;
    END
  END wo_d[668]
  PIN wo_d[669]
    DIRECTION OUTPUT ;
    USE SIGNAL ;
    PORT
      LAYER M3 ;
        RECT 74.232 69.082 74.250 69.120 ;
    END
  END wo_d[669]
  PIN wo_d[66]
    DIRECTION OUTPUT ;
    USE SIGNAL ;
    PORT
      LAYER M4 ;
        RECT 0.000 48.432 0.192 48.456 ;
    END
  END wo_d[66]
  PIN wo_d[670]
    DIRECTION OUTPUT ;
    USE SIGNAL ;
    PORT
      LAYER M3 ;
        RECT 74.376 69.082 74.394 69.120 ;
    END
  END wo_d[670]
  PIN wo_d[671]
    DIRECTION OUTPUT ;
    USE SIGNAL ;
    PORT
      LAYER M3 ;
        RECT 74.520 69.082 74.538 69.120 ;
    END
  END wo_d[671]
  PIN wo_d[672]
    DIRECTION OUTPUT ;
    USE SIGNAL ;
    PORT
      LAYER M5 ;
        RECT 74.688 69.036 74.712 69.120 ;
    END
  END wo_d[672]
  PIN wo_d[673]
    DIRECTION OUTPUT ;
    USE SIGNAL ;
    PORT
      LAYER M3 ;
        RECT 74.808 69.082 74.826 69.120 ;
    END
  END wo_d[673]
  PIN wo_d[674]
    DIRECTION OUTPUT ;
    USE SIGNAL ;
    PORT
      LAYER M5 ;
        RECT 74.976 69.036 75.000 69.120 ;
    END
  END wo_d[674]
  PIN wo_d[675]
    DIRECTION OUTPUT ;
    USE SIGNAL ;
    PORT
      LAYER M3 ;
        RECT 75.168 69.082 75.186 69.120 ;
    END
  END wo_d[675]
  PIN wo_d[676]
    DIRECTION OUTPUT ;
    USE SIGNAL ;
    PORT
      LAYER M5 ;
        RECT 75.264 69.036 75.288 69.120 ;
    END
  END wo_d[676]
  PIN wo_d[677]
    DIRECTION OUTPUT ;
    USE SIGNAL ;
    PORT
      LAYER M3 ;
        RECT 75.456 69.082 75.474 69.120 ;
    END
  END wo_d[677]
  PIN wo_d[678]
    DIRECTION OUTPUT ;
    USE SIGNAL ;
    PORT
      LAYER M3 ;
        RECT 75.600 69.082 75.618 69.120 ;
    END
  END wo_d[678]
  PIN wo_d[679]
    DIRECTION OUTPUT ;
    USE SIGNAL ;
    PORT
      LAYER M3 ;
        RECT 75.744 69.082 75.762 69.120 ;
    END
  END wo_d[679]
  PIN wo_d[67]
    DIRECTION OUTPUT ;
    USE SIGNAL ;
    PORT
      LAYER M4 ;
        RECT 129.408 52.800 129.600 52.824 ;
    END
  END wo_d[67]
  PIN wo_d[680]
    DIRECTION OUTPUT ;
    USE SIGNAL ;
    PORT
      LAYER M3 ;
        RECT 75.888 69.082 75.906 69.120 ;
    END
  END wo_d[680]
  PIN wo_d[681]
    DIRECTION OUTPUT ;
    USE SIGNAL ;
    PORT
      LAYER M3 ;
        RECT 76.032 69.082 76.050 69.120 ;
    END
  END wo_d[681]
  PIN wo_d[682]
    DIRECTION OUTPUT ;
    USE SIGNAL ;
    PORT
      LAYER M3 ;
        RECT 76.176 69.082 76.194 69.120 ;
    END
  END wo_d[682]
  PIN wo_d[683]
    DIRECTION OUTPUT ;
    USE SIGNAL ;
    PORT
      LAYER M5 ;
        RECT 76.320 69.036 76.344 69.120 ;
    END
  END wo_d[683]
  PIN wo_d[684]
    DIRECTION OUTPUT ;
    USE SIGNAL ;
    PORT
      LAYER M3 ;
        RECT 76.464 69.082 76.482 69.120 ;
    END
  END wo_d[684]
  PIN wo_d[685]
    DIRECTION OUTPUT ;
    USE SIGNAL ;
    PORT
      LAYER M5 ;
        RECT 76.608 69.036 76.632 69.120 ;
    END
  END wo_d[685]
  PIN wo_d[686]
    DIRECTION OUTPUT ;
    USE SIGNAL ;
    PORT
      LAYER M5 ;
        RECT 76.800 69.036 76.824 69.120 ;
    END
  END wo_d[686]
  PIN wo_d[687]
    DIRECTION OUTPUT ;
    USE SIGNAL ;
    PORT
      LAYER M5 ;
        RECT 76.896 69.036 76.920 69.120 ;
    END
  END wo_d[687]
  PIN wo_d[688]
    DIRECTION OUTPUT ;
    USE SIGNAL ;
    PORT
      LAYER M5 ;
        RECT 77.088 69.036 77.112 69.120 ;
    END
  END wo_d[688]
  PIN wo_d[689]
    DIRECTION OUTPUT ;
    USE SIGNAL ;
    PORT
      LAYER M3 ;
        RECT 77.256 69.082 77.274 69.120 ;
    END
  END wo_d[689]
  PIN wo_d[68]
    DIRECTION OUTPUT ;
    USE SIGNAL ;
    PORT
      LAYER M4 ;
        RECT 0.000 48.624 0.192 48.648 ;
    END
  END wo_d[68]
  PIN wo_d[690]
    DIRECTION OUTPUT ;
    USE SIGNAL ;
    PORT
      LAYER M5 ;
        RECT 77.376 69.036 77.400 69.120 ;
    END
  END wo_d[690]
  PIN wo_d[691]
    DIRECTION OUTPUT ;
    USE SIGNAL ;
    PORT
      LAYER M3 ;
        RECT 77.544 69.082 77.562 69.120 ;
    END
  END wo_d[691]
  PIN wo_d[692]
    DIRECTION OUTPUT ;
    USE SIGNAL ;
    PORT
      LAYER M5 ;
        RECT 77.664 69.036 77.688 69.120 ;
    END
  END wo_d[692]
  PIN wo_d[693]
    DIRECTION OUTPUT ;
    USE SIGNAL ;
    PORT
      LAYER M3 ;
        RECT 77.832 69.082 77.850 69.120 ;
    END
  END wo_d[693]
  PIN wo_d[694]
    DIRECTION OUTPUT ;
    USE SIGNAL ;
    PORT
      LAYER M3 ;
        RECT 77.976 69.082 77.994 69.120 ;
    END
  END wo_d[694]
  PIN wo_d[695]
    DIRECTION OUTPUT ;
    USE SIGNAL ;
    PORT
      LAYER M3 ;
        RECT 78.192 69.082 78.210 69.120 ;
    END
  END wo_d[695]
  PIN wo_d[696]
    DIRECTION OUTPUT ;
    USE SIGNAL ;
    PORT
      LAYER M5 ;
        RECT 78.432 69.036 78.456 69.120 ;
    END
  END wo_d[696]
  PIN wo_d[697]
    DIRECTION OUTPUT ;
    USE SIGNAL ;
    PORT
      LAYER M3 ;
        RECT 78.624 69.082 78.642 69.120 ;
    END
  END wo_d[697]
  PIN wo_d[698]
    DIRECTION OUTPUT ;
    USE SIGNAL ;
    PORT
      LAYER M5 ;
        RECT 78.720 69.036 78.744 69.120 ;
    END
  END wo_d[698]
  PIN wo_d[699]
    DIRECTION OUTPUT ;
    USE SIGNAL ;
    PORT
      LAYER M3 ;
        RECT 78.912 69.082 78.930 69.120 ;
    END
  END wo_d[699]
  PIN wo_d[69]
    DIRECTION OUTPUT ;
    USE SIGNAL ;
    PORT
      LAYER M4 ;
        RECT 129.408 52.992 129.600 53.016 ;
    END
  END wo_d[69]
  PIN wo_d[6]
    DIRECTION OUTPUT ;
    USE SIGNAL ;
    PORT
      LAYER M4 ;
        RECT 0.000 42.576 0.192 42.600 ;
    END
  END wo_d[6]
  PIN wo_d[700]
    DIRECTION OUTPUT ;
    USE SIGNAL ;
    PORT
      LAYER M3 ;
        RECT 79.056 69.082 79.074 69.120 ;
    END
  END wo_d[700]
  PIN wo_d[701]
    DIRECTION OUTPUT ;
    USE SIGNAL ;
    PORT
      LAYER M3 ;
        RECT 79.200 69.082 79.218 69.120 ;
    END
  END wo_d[701]
  PIN wo_d[702]
    DIRECTION OUTPUT ;
    USE SIGNAL ;
    PORT
      LAYER M3 ;
        RECT 79.344 69.082 79.362 69.120 ;
    END
  END wo_d[702]
  PIN wo_d[703]
    DIRECTION OUTPUT ;
    USE SIGNAL ;
    PORT
      LAYER M3 ;
        RECT 79.488 69.082 79.506 69.120 ;
    END
  END wo_d[703]
  PIN wo_d[704]
    DIRECTION OUTPUT ;
    USE SIGNAL ;
    PORT
      LAYER M3 ;
        RECT 79.632 69.082 79.650 69.120 ;
    END
  END wo_d[704]
  PIN wo_d[705]
    DIRECTION OUTPUT ;
    USE SIGNAL ;
    PORT
      LAYER M5 ;
        RECT 79.776 69.036 79.800 69.120 ;
    END
  END wo_d[705]
  PIN wo_d[706]
    DIRECTION OUTPUT ;
    USE SIGNAL ;
    PORT
      LAYER M3 ;
        RECT 79.920 69.082 79.938 69.120 ;
    END
  END wo_d[706]
  PIN wo_d[707]
    DIRECTION OUTPUT ;
    USE SIGNAL ;
    PORT
      LAYER M5 ;
        RECT 80.064 69.036 80.088 69.120 ;
    END
  END wo_d[707]
  PIN wo_d[708]
    DIRECTION OUTPUT ;
    USE SIGNAL ;
    PORT
      LAYER M5 ;
        RECT 80.256 69.036 80.280 69.120 ;
    END
  END wo_d[708]
  PIN wo_d[709]
    DIRECTION OUTPUT ;
    USE SIGNAL ;
    PORT
      LAYER M5 ;
        RECT 80.352 69.036 80.376 69.120 ;
    END
  END wo_d[709]
  PIN wo_d[70]
    DIRECTION OUTPUT ;
    USE SIGNAL ;
    PORT
      LAYER M4 ;
        RECT 0.000 48.816 0.192 48.840 ;
    END
  END wo_d[70]
  PIN wo_d[710]
    DIRECTION OUTPUT ;
    USE SIGNAL ;
    PORT
      LAYER M5 ;
        RECT 80.544 69.036 80.568 69.120 ;
    END
  END wo_d[710]
  PIN wo_d[711]
    DIRECTION OUTPUT ;
    USE SIGNAL ;
    PORT
      LAYER M3 ;
        RECT 80.712 69.082 80.730 69.120 ;
    END
  END wo_d[711]
  PIN wo_d[712]
    DIRECTION OUTPUT ;
    USE SIGNAL ;
    PORT
      LAYER M5 ;
        RECT 80.832 69.036 80.856 69.120 ;
    END
  END wo_d[712]
  PIN wo_d[713]
    DIRECTION OUTPUT ;
    USE SIGNAL ;
    PORT
      LAYER M3 ;
        RECT 81.000 69.082 81.018 69.120 ;
    END
  END wo_d[713]
  PIN wo_d[714]
    DIRECTION OUTPUT ;
    USE SIGNAL ;
    PORT
      LAYER M3 ;
        RECT 81.144 69.082 81.162 69.120 ;
    END
  END wo_d[714]
  PIN wo_d[715]
    DIRECTION OUTPUT ;
    USE SIGNAL ;
    PORT
      LAYER M3 ;
        RECT 81.288 69.082 81.306 69.120 ;
    END
  END wo_d[715]
  PIN wo_d[716]
    DIRECTION OUTPUT ;
    USE SIGNAL ;
    PORT
      LAYER M3 ;
        RECT 81.432 69.082 81.450 69.120 ;
    END
  END wo_d[716]
  PIN wo_d[717]
    DIRECTION OUTPUT ;
    USE SIGNAL ;
    PORT
      LAYER M3 ;
        RECT 81.576 69.082 81.594 69.120 ;
    END
  END wo_d[717]
  PIN wo_d[718]
    DIRECTION OUTPUT ;
    USE SIGNAL ;
    PORT
      LAYER M3 ;
        RECT 81.720 69.082 81.738 69.120 ;
    END
  END wo_d[718]
  PIN wo_d[719]
    DIRECTION OUTPUT ;
    USE SIGNAL ;
    PORT
      LAYER M5 ;
        RECT 81.888 69.036 81.912 69.120 ;
    END
  END wo_d[719]
  PIN wo_d[71]
    DIRECTION OUTPUT ;
    USE SIGNAL ;
    PORT
      LAYER M4 ;
        RECT 129.408 53.136 129.600 53.160 ;
    END
  END wo_d[71]
  PIN wo_d[720]
    DIRECTION OUTPUT ;
    USE SIGNAL ;
    PORT
      LAYER M3 ;
        RECT 82.008 69.082 82.026 69.120 ;
    END
  END wo_d[720]
  PIN wo_d[721]
    DIRECTION OUTPUT ;
    USE SIGNAL ;
    PORT
      LAYER M5 ;
        RECT 82.176 69.036 82.200 69.120 ;
    END
  END wo_d[721]
  PIN wo_d[722]
    DIRECTION OUTPUT ;
    USE SIGNAL ;
    PORT
      LAYER M3 ;
        RECT 82.368 69.082 82.386 69.120 ;
    END
  END wo_d[722]
  PIN wo_d[723]
    DIRECTION OUTPUT ;
    USE SIGNAL ;
    PORT
      LAYER M5 ;
        RECT 82.464 69.036 82.488 69.120 ;
    END
  END wo_d[723]
  PIN wo_d[724]
    DIRECTION OUTPUT ;
    USE SIGNAL ;
    PORT
      LAYER M3 ;
        RECT 82.656 69.082 82.674 69.120 ;
    END
  END wo_d[724]
  PIN wo_d[725]
    DIRECTION OUTPUT ;
    USE SIGNAL ;
    PORT
      LAYER M3 ;
        RECT 82.800 69.082 82.818 69.120 ;
    END
  END wo_d[725]
  PIN wo_d[726]
    DIRECTION OUTPUT ;
    USE SIGNAL ;
    PORT
      LAYER M3 ;
        RECT 82.944 69.082 82.962 69.120 ;
    END
  END wo_d[726]
  PIN wo_d[727]
    DIRECTION OUTPUT ;
    USE SIGNAL ;
    PORT
      LAYER M3 ;
        RECT 83.088 69.082 83.106 69.120 ;
    END
  END wo_d[727]
  PIN wo_d[728]
    DIRECTION OUTPUT ;
    USE SIGNAL ;
    PORT
      LAYER M3 ;
        RECT 83.232 69.082 83.250 69.120 ;
    END
  END wo_d[728]
  PIN wo_d[729]
    DIRECTION OUTPUT ;
    USE SIGNAL ;
    PORT
      LAYER M3 ;
        RECT 83.376 69.082 83.394 69.120 ;
    END
  END wo_d[729]
  PIN wo_d[72]
    DIRECTION OUTPUT ;
    USE SIGNAL ;
    PORT
      LAYER M4 ;
        RECT 0.000 49.008 0.192 49.032 ;
    END
  END wo_d[72]
  PIN wo_d[730]
    DIRECTION OUTPUT ;
    USE SIGNAL ;
    PORT
      LAYER M3 ;
        RECT 83.664 69.082 83.682 69.120 ;
    END
  END wo_d[730]
  PIN wo_d[731]
    DIRECTION OUTPUT ;
    USE SIGNAL ;
    PORT
      LAYER M5 ;
        RECT 83.808 69.036 83.832 69.120 ;
    END
  END wo_d[731]
  PIN wo_d[732]
    DIRECTION OUTPUT ;
    USE SIGNAL ;
    PORT
      LAYER M5 ;
        RECT 84.000 69.036 84.024 69.120 ;
    END
  END wo_d[732]
  PIN wo_d[733]
    DIRECTION OUTPUT ;
    USE SIGNAL ;
    PORT
      LAYER M3 ;
        RECT 84.168 69.082 84.186 69.120 ;
    END
  END wo_d[733]
  PIN wo_d[734]
    DIRECTION OUTPUT ;
    USE SIGNAL ;
    PORT
      LAYER M5 ;
        RECT 84.288 69.036 84.312 69.120 ;
    END
  END wo_d[734]
  PIN wo_d[735]
    DIRECTION OUTPUT ;
    USE SIGNAL ;
    PORT
      LAYER M3 ;
        RECT 84.456 69.082 84.474 69.120 ;
    END
  END wo_d[735]
  PIN wo_d[736]
    DIRECTION OUTPUT ;
    USE SIGNAL ;
    PORT
      LAYER M3 ;
        RECT 84.600 69.082 84.618 69.120 ;
    END
  END wo_d[736]
  PIN wo_d[737]
    DIRECTION OUTPUT ;
    USE SIGNAL ;
    PORT
      LAYER M3 ;
        RECT 84.744 69.082 84.762 69.120 ;
    END
  END wo_d[737]
  PIN wo_d[738]
    DIRECTION OUTPUT ;
    USE SIGNAL ;
    PORT
      LAYER M3 ;
        RECT 84.888 69.082 84.906 69.120 ;
    END
  END wo_d[738]
  PIN wo_d[739]
    DIRECTION OUTPUT ;
    USE SIGNAL ;
    PORT
      LAYER M3 ;
        RECT 85.032 69.082 85.050 69.120 ;
    END
  END wo_d[739]
  PIN wo_d[73]
    DIRECTION OUTPUT ;
    USE SIGNAL ;
    PORT
      LAYER M4 ;
        RECT 129.408 53.328 129.600 53.352 ;
    END
  END wo_d[73]
  PIN wo_d[740]
    DIRECTION OUTPUT ;
    USE SIGNAL ;
    PORT
      LAYER M3 ;
        RECT 85.176 69.082 85.194 69.120 ;
    END
  END wo_d[740]
  PIN wo_d[741]
    DIRECTION OUTPUT ;
    USE SIGNAL ;
    PORT
      LAYER M5 ;
        RECT 85.344 69.036 85.368 69.120 ;
    END
  END wo_d[741]
  PIN wo_d[742]
    DIRECTION OUTPUT ;
    USE SIGNAL ;
    PORT
      LAYER M3 ;
        RECT 85.464 69.082 85.482 69.120 ;
    END
  END wo_d[742]
  PIN wo_d[743]
    DIRECTION OUTPUT ;
    USE SIGNAL ;
    PORT
      LAYER M5 ;
        RECT 85.632 69.036 85.656 69.120 ;
    END
  END wo_d[743]
  PIN wo_d[744]
    DIRECTION OUTPUT ;
    USE SIGNAL ;
    PORT
      LAYER M3 ;
        RECT 85.824 69.082 85.842 69.120 ;
    END
  END wo_d[744]
  PIN wo_d[745]
    DIRECTION OUTPUT ;
    USE SIGNAL ;
    PORT
      LAYER M5 ;
        RECT 85.920 69.036 85.944 69.120 ;
    END
  END wo_d[745]
  PIN wo_d[746]
    DIRECTION OUTPUT ;
    USE SIGNAL ;
    PORT
      LAYER M3 ;
        RECT 86.112 69.082 86.130 69.120 ;
    END
  END wo_d[746]
  PIN wo_d[747]
    DIRECTION OUTPUT ;
    USE SIGNAL ;
    PORT
      LAYER M3 ;
        RECT 86.256 69.082 86.274 69.120 ;
    END
  END wo_d[747]
  PIN wo_d[748]
    DIRECTION OUTPUT ;
    USE SIGNAL ;
    PORT
      LAYER M3 ;
        RECT 86.400 69.082 86.418 69.120 ;
    END
  END wo_d[748]
  PIN wo_d[749]
    DIRECTION OUTPUT ;
    USE SIGNAL ;
    PORT
      LAYER M3 ;
        RECT 86.544 69.082 86.562 69.120 ;
    END
  END wo_d[749]
  PIN wo_d[74]
    DIRECTION OUTPUT ;
    USE SIGNAL ;
    PORT
      LAYER M4 ;
        RECT 0.000 49.200 0.192 49.224 ;
    END
  END wo_d[74]
  PIN wo_d[750]
    DIRECTION OUTPUT ;
    USE SIGNAL ;
    PORT
      LAYER M5 ;
        RECT 86.688 69.036 86.712 69.120 ;
    END
  END wo_d[750]
  PIN wo_d[751]
    DIRECTION OUTPUT ;
    USE SIGNAL ;
    PORT
      LAYER M3 ;
        RECT 86.832 69.082 86.850 69.120 ;
    END
  END wo_d[751]
  PIN wo_d[752]
    DIRECTION OUTPUT ;
    USE SIGNAL ;
    PORT
      LAYER M5 ;
        RECT 86.976 69.036 87.000 69.120 ;
    END
  END wo_d[752]
  PIN wo_d[753]
    DIRECTION OUTPUT ;
    USE SIGNAL ;
    PORT
      LAYER M3 ;
        RECT 87.120 69.082 87.138 69.120 ;
    END
  END wo_d[753]
  PIN wo_d[754]
    DIRECTION OUTPUT ;
    USE SIGNAL ;
    PORT
      LAYER M5 ;
        RECT 87.264 69.036 87.288 69.120 ;
    END
  END wo_d[754]
  PIN wo_d[755]
    DIRECTION OUTPUT ;
    USE SIGNAL ;
    PORT
      LAYER M5 ;
        RECT 87.456 69.036 87.480 69.120 ;
    END
  END wo_d[755]
  PIN wo_d[756]
    DIRECTION OUTPUT ;
    USE SIGNAL ;
    PORT
      LAYER M5 ;
        RECT 87.552 69.036 87.576 69.120 ;
    END
  END wo_d[756]
  PIN wo_d[757]
    DIRECTION OUTPUT ;
    USE SIGNAL ;
    PORT
      LAYER M5 ;
        RECT 87.744 69.036 87.768 69.120 ;
    END
  END wo_d[757]
  PIN wo_d[758]
    DIRECTION OUTPUT ;
    USE SIGNAL ;
    PORT
      LAYER M3 ;
        RECT 87.912 69.082 87.930 69.120 ;
    END
  END wo_d[758]
  PIN wo_d[759]
    DIRECTION OUTPUT ;
    USE SIGNAL ;
    PORT
      LAYER M5 ;
        RECT 88.032 69.036 88.056 69.120 ;
    END
  END wo_d[759]
  PIN wo_d[75]
    DIRECTION OUTPUT ;
    USE SIGNAL ;
    PORT
      LAYER M4 ;
        RECT 129.408 53.424 129.600 53.448 ;
    END
  END wo_d[75]
  PIN wo_d[760]
    DIRECTION OUTPUT ;
    USE SIGNAL ;
    PORT
      LAYER M3 ;
        RECT 88.200 69.082 88.218 69.120 ;
    END
  END wo_d[760]
  PIN wo_d[761]
    DIRECTION OUTPUT ;
    USE SIGNAL ;
    PORT
      LAYER M3 ;
        RECT 88.344 69.082 88.362 69.120 ;
    END
  END wo_d[761]
  PIN wo_d[762]
    DIRECTION OUTPUT ;
    USE SIGNAL ;
    PORT
      LAYER M3 ;
        RECT 88.488 69.082 88.506 69.120 ;
    END
  END wo_d[762]
  PIN wo_d[763]
    DIRECTION OUTPUT ;
    USE SIGNAL ;
    PORT
      LAYER M3 ;
        RECT 88.632 69.082 88.650 69.120 ;
    END
  END wo_d[763]
  PIN wo_d[764]
    DIRECTION OUTPUT ;
    USE SIGNAL ;
    PORT
      LAYER M3 ;
        RECT 88.776 69.082 88.794 69.120 ;
    END
  END wo_d[764]
  PIN wo_d[765]
    DIRECTION OUTPUT ;
    USE SIGNAL ;
    PORT
      LAYER M3 ;
        RECT 88.992 69.082 89.010 69.120 ;
    END
  END wo_d[765]
  PIN wo_d[766]
    DIRECTION OUTPUT ;
    USE SIGNAL ;
    PORT
      LAYER M3 ;
        RECT 89.280 69.082 89.298 69.120 ;
    END
  END wo_d[766]
  PIN wo_d[767]
    DIRECTION OUTPUT ;
    USE SIGNAL ;
    PORT
      LAYER M5 ;
        RECT 89.376 69.036 89.400 69.120 ;
    END
  END wo_d[767]
  PIN wo_d[768]
    DIRECTION OUTPUT ;
    USE SIGNAL ;
    PORT
      LAYER M3 ;
        RECT 89.568 69.082 89.586 69.120 ;
    END
  END wo_d[768]
  PIN wo_d[769]
    DIRECTION OUTPUT ;
    USE SIGNAL ;
    PORT
      LAYER M3 ;
        RECT 89.712 69.082 89.730 69.120 ;
    END
  END wo_d[769]
  PIN wo_d[76]
    DIRECTION OUTPUT ;
    USE SIGNAL ;
    PORT
      LAYER M4 ;
        RECT 0.000 49.488 0.192 49.512 ;
    END
  END wo_d[76]
  PIN wo_d[770]
    DIRECTION OUTPUT ;
    USE SIGNAL ;
    PORT
      LAYER M3 ;
        RECT 89.856 69.082 89.874 69.120 ;
    END
  END wo_d[770]
  PIN wo_d[771]
    DIRECTION OUTPUT ;
    USE SIGNAL ;
    PORT
      LAYER M3 ;
        RECT 90.000 69.082 90.018 69.120 ;
    END
  END wo_d[771]
  PIN wo_d[772]
    DIRECTION OUTPUT ;
    USE SIGNAL ;
    PORT
      LAYER M5 ;
        RECT 90.144 69.036 90.168 69.120 ;
    END
  END wo_d[772]
  PIN wo_d[773]
    DIRECTION OUTPUT ;
    USE SIGNAL ;
    PORT
      LAYER M3 ;
        RECT 90.288 69.082 90.306 69.120 ;
    END
  END wo_d[773]
  PIN wo_d[774]
    DIRECTION OUTPUT ;
    USE SIGNAL ;
    PORT
      LAYER M5 ;
        RECT 90.432 69.036 90.456 69.120 ;
    END
  END wo_d[774]
  PIN wo_d[775]
    DIRECTION OUTPUT ;
    USE SIGNAL ;
    PORT
      LAYER M3 ;
        RECT 90.576 69.082 90.594 69.120 ;
    END
  END wo_d[775]
  PIN wo_d[776]
    DIRECTION OUTPUT ;
    USE SIGNAL ;
    PORT
      LAYER M5 ;
        RECT 90.720 69.036 90.744 69.120 ;
    END
  END wo_d[776]
  PIN wo_d[777]
    DIRECTION OUTPUT ;
    USE SIGNAL ;
    PORT
      LAYER M5 ;
        RECT 90.912 69.036 90.936 69.120 ;
    END
  END wo_d[777]
  PIN wo_d[778]
    DIRECTION OUTPUT ;
    USE SIGNAL ;
    PORT
      LAYER M5 ;
        RECT 91.008 69.036 91.032 69.120 ;
    END
  END wo_d[778]
  PIN wo_d[779]
    DIRECTION OUTPUT ;
    USE SIGNAL ;
    PORT
      LAYER M5 ;
        RECT 91.200 69.036 91.224 69.120 ;
    END
  END wo_d[779]
  PIN wo_d[77]
    DIRECTION OUTPUT ;
    USE SIGNAL ;
    PORT
      LAYER M4 ;
        RECT 129.408 53.616 129.600 53.640 ;
    END
  END wo_d[77]
  PIN wo_d[780]
    DIRECTION OUTPUT ;
    USE SIGNAL ;
    PORT
      LAYER M3 ;
        RECT 91.368 69.082 91.386 69.120 ;
    END
  END wo_d[780]
  PIN wo_d[781]
    DIRECTION OUTPUT ;
    USE SIGNAL ;
    PORT
      LAYER M5 ;
        RECT 91.488 69.036 91.512 69.120 ;
    END
  END wo_d[781]
  PIN wo_d[782]
    DIRECTION OUTPUT ;
    USE SIGNAL ;
    PORT
      LAYER M3 ;
        RECT 91.656 69.082 91.674 69.120 ;
    END
  END wo_d[782]
  PIN wo_d[783]
    DIRECTION OUTPUT ;
    USE SIGNAL ;
    PORT
      LAYER M3 ;
        RECT 91.800 69.082 91.818 69.120 ;
    END
  END wo_d[783]
  PIN wo_d[784]
    DIRECTION OUTPUT ;
    USE SIGNAL ;
    PORT
      LAYER M3 ;
        RECT 91.944 69.082 91.962 69.120 ;
    END
  END wo_d[784]
  PIN wo_d[785]
    DIRECTION OUTPUT ;
    USE SIGNAL ;
    PORT
      LAYER M3 ;
        RECT 92.088 69.082 92.106 69.120 ;
    END
  END wo_d[785]
  PIN wo_d[786]
    DIRECTION OUTPUT ;
    USE SIGNAL ;
    PORT
      LAYER M3 ;
        RECT 92.232 69.082 92.250 69.120 ;
    END
  END wo_d[786]
  PIN wo_d[787]
    DIRECTION OUTPUT ;
    USE SIGNAL ;
    PORT
      LAYER M3 ;
        RECT 92.376 69.082 92.394 69.120 ;
    END
  END wo_d[787]
  PIN wo_d[788]
    DIRECTION OUTPUT ;
    USE SIGNAL ;
    PORT
      LAYER M5 ;
        RECT 92.544 69.036 92.568 69.120 ;
    END
  END wo_d[788]
  PIN wo_d[789]
    DIRECTION OUTPUT ;
    USE SIGNAL ;
    PORT
      LAYER M3 ;
        RECT 92.664 69.082 92.682 69.120 ;
    END
  END wo_d[789]
  PIN wo_d[78]
    DIRECTION OUTPUT ;
    USE SIGNAL ;
    PORT
      LAYER M4 ;
        RECT 0.000 49.680 0.192 49.704 ;
    END
  END wo_d[78]
  PIN wo_d[790]
    DIRECTION OUTPUT ;
    USE SIGNAL ;
    PORT
      LAYER M5 ;
        RECT 92.832 69.036 92.856 69.120 ;
    END
  END wo_d[790]
  PIN wo_d[791]
    DIRECTION OUTPUT ;
    USE SIGNAL ;
    PORT
      LAYER M3 ;
        RECT 93.024 69.082 93.042 69.120 ;
    END
  END wo_d[791]
  PIN wo_d[792]
    DIRECTION OUTPUT ;
    USE SIGNAL ;
    PORT
      LAYER M5 ;
        RECT 93.120 69.036 93.144 69.120 ;
    END
  END wo_d[792]
  PIN wo_d[793]
    DIRECTION OUTPUT ;
    USE SIGNAL ;
    PORT
      LAYER M3 ;
        RECT 93.312 69.082 93.330 69.120 ;
    END
  END wo_d[793]
  PIN wo_d[794]
    DIRECTION OUTPUT ;
    USE SIGNAL ;
    PORT
      LAYER M3 ;
        RECT 93.456 69.082 93.474 69.120 ;
    END
  END wo_d[794]
  PIN wo_d[795]
    DIRECTION OUTPUT ;
    USE SIGNAL ;
    PORT
      LAYER M3 ;
        RECT 93.600 69.082 93.618 69.120 ;
    END
  END wo_d[795]
  PIN wo_d[796]
    DIRECTION OUTPUT ;
    USE SIGNAL ;
    PORT
      LAYER M3 ;
        RECT 93.744 69.082 93.762 69.120 ;
    END
  END wo_d[796]
  PIN wo_d[797]
    DIRECTION OUTPUT ;
    USE SIGNAL ;
    PORT
      LAYER M5 ;
        RECT 93.888 69.036 93.912 69.120 ;
    END
  END wo_d[797]
  PIN wo_d[798]
    DIRECTION OUTPUT ;
    USE SIGNAL ;
    PORT
      LAYER M3 ;
        RECT 94.032 69.082 94.050 69.120 ;
    END
  END wo_d[798]
  PIN wo_d[799]
    DIRECTION OUTPUT ;
    USE SIGNAL ;
    PORT
      LAYER M5 ;
        RECT 94.176 69.036 94.200 69.120 ;
    END
  END wo_d[799]
  PIN wo_d[79]
    DIRECTION OUTPUT ;
    USE SIGNAL ;
    PORT
      LAYER M4 ;
        RECT 129.408 53.760 129.600 53.784 ;
    END
  END wo_d[79]
  PIN wo_d[7]
    DIRECTION OUTPUT ;
    USE SIGNAL ;
    PORT
      LAYER M4 ;
        RECT 129.408 48.192 129.600 48.216 ;
    END
  END wo_d[7]
  PIN wo_d[800]
    DIRECTION OUTPUT ;
    USE SIGNAL ;
    PORT
      LAYER M3 ;
        RECT 94.392 69.082 94.410 69.120 ;
    END
  END wo_d[800]
  PIN wo_d[801]
    DIRECTION OUTPUT ;
    USE SIGNAL ;
    PORT
      LAYER M5 ;
        RECT 94.656 69.036 94.680 69.120 ;
    END
  END wo_d[801]
  PIN wo_d[802]
    DIRECTION OUTPUT ;
    USE SIGNAL ;
    PORT
      LAYER M3 ;
        RECT 94.824 69.082 94.842 69.120 ;
    END
  END wo_d[802]
  PIN wo_d[803]
    DIRECTION OUTPUT ;
    USE SIGNAL ;
    PORT
      LAYER M5 ;
        RECT 94.944 69.036 94.968 69.120 ;
    END
  END wo_d[803]
  PIN wo_d[804]
    DIRECTION OUTPUT ;
    USE SIGNAL ;
    PORT
      LAYER M3 ;
        RECT 95.112 69.082 95.130 69.120 ;
    END
  END wo_d[804]
  PIN wo_d[805]
    DIRECTION OUTPUT ;
    USE SIGNAL ;
    PORT
      LAYER M3 ;
        RECT 95.256 69.082 95.274 69.120 ;
    END
  END wo_d[805]
  PIN wo_d[806]
    DIRECTION OUTPUT ;
    USE SIGNAL ;
    PORT
      LAYER M3 ;
        RECT 95.400 69.082 95.418 69.120 ;
    END
  END wo_d[806]
  PIN wo_d[807]
    DIRECTION OUTPUT ;
    USE SIGNAL ;
    PORT
      LAYER M3 ;
        RECT 95.544 69.082 95.562 69.120 ;
    END
  END wo_d[807]
  PIN wo_d[808]
    DIRECTION OUTPUT ;
    USE SIGNAL ;
    PORT
      LAYER M5 ;
        RECT 95.712 69.036 95.736 69.120 ;
    END
  END wo_d[808]
  PIN wo_d[809]
    DIRECTION OUTPUT ;
    USE SIGNAL ;
    PORT
      LAYER M3 ;
        RECT 95.832 69.082 95.850 69.120 ;
    END
  END wo_d[809]
  PIN wo_d[80]
    DIRECTION OUTPUT ;
    USE SIGNAL ;
    PORT
      LAYER M4 ;
        RECT 0.000 49.872 0.192 49.896 ;
    END
  END wo_d[80]
  PIN wo_d[810]
    DIRECTION OUTPUT ;
    USE SIGNAL ;
    PORT
      LAYER M5 ;
        RECT 96.000 69.036 96.024 69.120 ;
    END
  END wo_d[810]
  PIN wo_d[811]
    DIRECTION OUTPUT ;
    USE SIGNAL ;
    PORT
      LAYER M3 ;
        RECT 96.120 69.082 96.138 69.120 ;
    END
  END wo_d[811]
  PIN wo_d[812]
    DIRECTION OUTPUT ;
    USE SIGNAL ;
    PORT
      LAYER M5 ;
        RECT 96.288 69.036 96.312 69.120 ;
    END
  END wo_d[812]
  PIN wo_d[813]
    DIRECTION OUTPUT ;
    USE SIGNAL ;
    PORT
      LAYER M3 ;
        RECT 96.480 69.082 96.498 69.120 ;
    END
  END wo_d[813]
  PIN wo_d[814]
    DIRECTION OUTPUT ;
    USE SIGNAL ;
    PORT
      LAYER M5 ;
        RECT 96.576 69.036 96.600 69.120 ;
    END
  END wo_d[814]
  PIN wo_d[815]
    DIRECTION OUTPUT ;
    USE SIGNAL ;
    PORT
      LAYER M3 ;
        RECT 96.768 69.082 96.786 69.120 ;
    END
  END wo_d[815]
  PIN wo_d[816]
    DIRECTION OUTPUT ;
    USE SIGNAL ;
    PORT
      LAYER M3 ;
        RECT 96.912 69.082 96.930 69.120 ;
    END
  END wo_d[816]
  PIN wo_d[817]
    DIRECTION OUTPUT ;
    USE SIGNAL ;
    PORT
      LAYER M3 ;
        RECT 97.056 69.082 97.074 69.120 ;
    END
  END wo_d[817]
  PIN wo_d[818]
    DIRECTION OUTPUT ;
    USE SIGNAL ;
    PORT
      LAYER M3 ;
        RECT 97.200 69.082 97.218 69.120 ;
    END
  END wo_d[818]
  PIN wo_d[819]
    DIRECTION OUTPUT ;
    USE SIGNAL ;
    PORT
      LAYER M5 ;
        RECT 97.344 69.036 97.368 69.120 ;
    END
  END wo_d[819]
  PIN wo_d[81]
    DIRECTION OUTPUT ;
    USE SIGNAL ;
    PORT
      LAYER M4 ;
        RECT 129.408 53.904 129.600 53.928 ;
    END
  END wo_d[81]
  PIN wo_d[820]
    DIRECTION OUTPUT ;
    USE SIGNAL ;
    PORT
      LAYER M3 ;
        RECT 97.488 69.082 97.506 69.120 ;
    END
  END wo_d[820]
  PIN wo_d[821]
    DIRECTION OUTPUT ;
    USE SIGNAL ;
    PORT
      LAYER M5 ;
        RECT 97.632 69.036 97.656 69.120 ;
    END
  END wo_d[821]
  PIN wo_d[822]
    DIRECTION OUTPUT ;
    USE SIGNAL ;
    PORT
      LAYER M3 ;
        RECT 97.776 69.082 97.794 69.120 ;
    END
  END wo_d[822]
  PIN wo_d[823]
    DIRECTION OUTPUT ;
    USE SIGNAL ;
    PORT
      LAYER M5 ;
        RECT 97.920 69.036 97.944 69.120 ;
    END
  END wo_d[823]
  PIN wo_d[824]
    DIRECTION OUTPUT ;
    USE SIGNAL ;
    PORT
      LAYER M5 ;
        RECT 98.112 69.036 98.136 69.120 ;
    END
  END wo_d[824]
  PIN wo_d[825]
    DIRECTION OUTPUT ;
    USE SIGNAL ;
    PORT
      LAYER M5 ;
        RECT 98.208 69.036 98.232 69.120 ;
    END
  END wo_d[825]
  PIN wo_d[826]
    DIRECTION OUTPUT ;
    USE SIGNAL ;
    PORT
      LAYER M5 ;
        RECT 98.400 69.036 98.424 69.120 ;
    END
  END wo_d[826]
  PIN wo_d[827]
    DIRECTION OUTPUT ;
    USE SIGNAL ;
    PORT
      LAYER M3 ;
        RECT 98.568 69.082 98.586 69.120 ;
    END
  END wo_d[827]
  PIN wo_d[828]
    DIRECTION OUTPUT ;
    USE SIGNAL ;
    PORT
      LAYER M5 ;
        RECT 98.688 69.036 98.712 69.120 ;
    END
  END wo_d[828]
  PIN wo_d[829]
    DIRECTION OUTPUT ;
    USE SIGNAL ;
    PORT
      LAYER M3 ;
        RECT 98.856 69.082 98.874 69.120 ;
    END
  END wo_d[829]
  PIN wo_d[82]
    DIRECTION OUTPUT ;
    USE SIGNAL ;
    PORT
      LAYER M4 ;
        RECT 0.000 50.064 0.192 50.088 ;
    END
  END wo_d[82]
  PIN wo_d[830]
    DIRECTION OUTPUT ;
    USE SIGNAL ;
    PORT
      LAYER M3 ;
        RECT 99.000 69.082 99.018 69.120 ;
    END
  END wo_d[830]
  PIN wo_d[831]
    DIRECTION OUTPUT ;
    USE SIGNAL ;
    PORT
      LAYER M3 ;
        RECT 99.144 69.082 99.162 69.120 ;
    END
  END wo_d[831]
  PIN wo_d[832]
    DIRECTION OUTPUT ;
    USE SIGNAL ;
    PORT
      LAYER M3 ;
        RECT 99.288 69.082 99.306 69.120 ;
    END
  END wo_d[832]
  PIN wo_d[833]
    DIRECTION OUTPUT ;
    USE SIGNAL ;
    PORT
      LAYER M3 ;
        RECT 99.432 69.082 99.450 69.120 ;
    END
  END wo_d[833]
  PIN wo_d[834]
    DIRECTION OUTPUT ;
    USE SIGNAL ;
    PORT
      LAYER M3 ;
        RECT 99.576 69.082 99.594 69.120 ;
    END
  END wo_d[834]
  PIN wo_d[835]
    DIRECTION OUTPUT ;
    USE SIGNAL ;
    PORT
      LAYER M3 ;
        RECT 99.864 69.082 99.882 69.120 ;
    END
  END wo_d[835]
  PIN wo_d[836]
    DIRECTION OUTPUT ;
    USE SIGNAL ;
    PORT
      LAYER M5 ;
        RECT 100.032 69.036 100.056 69.120 ;
    END
  END wo_d[836]
  PIN wo_d[837]
    DIRECTION OUTPUT ;
    USE SIGNAL ;
    PORT
      LAYER M3 ;
        RECT 100.224 69.082 100.242 69.120 ;
    END
  END wo_d[837]
  PIN wo_d[838]
    DIRECTION OUTPUT ;
    USE SIGNAL ;
    PORT
      LAYER M3 ;
        RECT 100.368 69.082 100.386 69.120 ;
    END
  END wo_d[838]
  PIN wo_d[839]
    DIRECTION OUTPUT ;
    USE SIGNAL ;
    PORT
      LAYER M3 ;
        RECT 100.512 69.082 100.530 69.120 ;
    END
  END wo_d[839]
  PIN wo_d[83]
    DIRECTION OUTPUT ;
    USE SIGNAL ;
    PORT
      LAYER M4 ;
        RECT 129.408 54.096 129.600 54.120 ;
    END
  END wo_d[83]
  PIN wo_d[840]
    DIRECTION OUTPUT ;
    USE SIGNAL ;
    PORT
      LAYER M3 ;
        RECT 100.656 69.082 100.674 69.120 ;
    END
  END wo_d[840]
  PIN wo_d[841]
    DIRECTION OUTPUT ;
    USE SIGNAL ;
    PORT
      LAYER M5 ;
        RECT 100.800 69.036 100.824 69.120 ;
    END
  END wo_d[841]
  PIN wo_d[842]
    DIRECTION OUTPUT ;
    USE SIGNAL ;
    PORT
      LAYER M3 ;
        RECT 100.944 69.082 100.962 69.120 ;
    END
  END wo_d[842]
  PIN wo_d[843]
    DIRECTION OUTPUT ;
    USE SIGNAL ;
    PORT
      LAYER M5 ;
        RECT 101.088 69.036 101.112 69.120 ;
    END
  END wo_d[843]
  PIN wo_d[844]
    DIRECTION OUTPUT ;
    USE SIGNAL ;
    PORT
      LAYER M5 ;
        RECT 101.280 69.036 101.304 69.120 ;
    END
  END wo_d[844]
  PIN wo_d[845]
    DIRECTION OUTPUT ;
    USE SIGNAL ;
    PORT
      LAYER M5 ;
        RECT 101.376 69.036 101.400 69.120 ;
    END
  END wo_d[845]
  PIN wo_d[846]
    DIRECTION OUTPUT ;
    USE SIGNAL ;
    PORT
      LAYER M5 ;
        RECT 101.568 69.036 101.592 69.120 ;
    END
  END wo_d[846]
  PIN wo_d[847]
    DIRECTION OUTPUT ;
    USE SIGNAL ;
    PORT
      LAYER M5 ;
        RECT 101.664 69.036 101.688 69.120 ;
    END
  END wo_d[847]
  PIN wo_d[848]
    DIRECTION OUTPUT ;
    USE SIGNAL ;
    PORT
      LAYER M5 ;
        RECT 101.856 69.036 101.880 69.120 ;
    END
  END wo_d[848]
  PIN wo_d[849]
    DIRECTION OUTPUT ;
    USE SIGNAL ;
    PORT
      LAYER M3 ;
        RECT 102.024 69.082 102.042 69.120 ;
    END
  END wo_d[849]
  PIN wo_d[84]
    DIRECTION OUTPUT ;
    USE SIGNAL ;
    PORT
      LAYER M4 ;
        RECT 0.000 50.256 0.192 50.280 ;
    END
  END wo_d[84]
  PIN wo_d[850]
    DIRECTION OUTPUT ;
    USE SIGNAL ;
    PORT
      LAYER M5 ;
        RECT 102.144 69.036 102.168 69.120 ;
    END
  END wo_d[850]
  PIN wo_d[851]
    DIRECTION OUTPUT ;
    USE SIGNAL ;
    PORT
      LAYER M3 ;
        RECT 102.312 69.082 102.330 69.120 ;
    END
  END wo_d[851]
  PIN wo_d[852]
    DIRECTION OUTPUT ;
    USE SIGNAL ;
    PORT
      LAYER M3 ;
        RECT 102.456 69.082 102.474 69.120 ;
    END
  END wo_d[852]
  PIN wo_d[853]
    DIRECTION OUTPUT ;
    USE SIGNAL ;
    PORT
      LAYER M3 ;
        RECT 102.600 69.082 102.618 69.120 ;
    END
  END wo_d[853]
  PIN wo_d[854]
    DIRECTION OUTPUT ;
    USE SIGNAL ;
    PORT
      LAYER M3 ;
        RECT 102.744 69.082 102.762 69.120 ;
    END
  END wo_d[854]
  PIN wo_d[855]
    DIRECTION OUTPUT ;
    USE SIGNAL ;
    PORT
      LAYER M5 ;
        RECT 102.912 69.036 102.936 69.120 ;
    END
  END wo_d[855]
  PIN wo_d[856]
    DIRECTION OUTPUT ;
    USE SIGNAL ;
    PORT
      LAYER M3 ;
        RECT 103.032 69.082 103.050 69.120 ;
    END
  END wo_d[856]
  PIN wo_d[857]
    DIRECTION OUTPUT ;
    USE SIGNAL ;
    PORT
      LAYER M5 ;
        RECT 103.200 69.036 103.224 69.120 ;
    END
  END wo_d[857]
  PIN wo_d[858]
    DIRECTION OUTPUT ;
    USE SIGNAL ;
    PORT
      LAYER M3 ;
        RECT 103.320 69.082 103.338 69.120 ;
    END
  END wo_d[858]
  PIN wo_d[859]
    DIRECTION OUTPUT ;
    USE SIGNAL ;
    PORT
      LAYER M5 ;
        RECT 103.488 69.036 103.512 69.120 ;
    END
  END wo_d[859]
  PIN wo_d[85]
    DIRECTION OUTPUT ;
    USE SIGNAL ;
    PORT
      LAYER M4 ;
        RECT 129.408 54.192 129.600 54.216 ;
    END
  END wo_d[85]
  PIN wo_d[860]
    DIRECTION OUTPUT ;
    USE SIGNAL ;
    PORT
      LAYER M3 ;
        RECT 103.680 69.082 103.698 69.120 ;
    END
  END wo_d[860]
  PIN wo_d[861]
    DIRECTION OUTPUT ;
    USE SIGNAL ;
    PORT
      LAYER M5 ;
        RECT 103.776 69.036 103.800 69.120 ;
    END
  END wo_d[861]
  PIN wo_d[862]
    DIRECTION OUTPUT ;
    USE SIGNAL ;
    PORT
      LAYER M3 ;
        RECT 103.968 69.082 103.986 69.120 ;
    END
  END wo_d[862]
  PIN wo_d[863]
    DIRECTION OUTPUT ;
    USE SIGNAL ;
    PORT
      LAYER M3 ;
        RECT 104.112 69.082 104.130 69.120 ;
    END
  END wo_d[863]
  PIN wo_d[864]
    DIRECTION OUTPUT ;
    USE SIGNAL ;
    PORT
      LAYER M3 ;
        RECT 104.256 69.082 104.274 69.120 ;
    END
  END wo_d[864]
  PIN wo_d[865]
    DIRECTION OUTPUT ;
    USE SIGNAL ;
    PORT
      LAYER M3 ;
        RECT 104.400 69.082 104.418 69.120 ;
    END
  END wo_d[865]
  PIN wo_d[866]
    DIRECTION OUTPUT ;
    USE SIGNAL ;
    PORT
      LAYER M5 ;
        RECT 104.544 69.036 104.568 69.120 ;
    END
  END wo_d[866]
  PIN wo_d[867]
    DIRECTION OUTPUT ;
    USE SIGNAL ;
    PORT
      LAYER M3 ;
        RECT 104.688 69.082 104.706 69.120 ;
    END
  END wo_d[867]
  PIN wo_d[868]
    DIRECTION OUTPUT ;
    USE SIGNAL ;
    PORT
      LAYER M5 ;
        RECT 104.832 69.036 104.856 69.120 ;
    END
  END wo_d[868]
  PIN wo_d[869]
    DIRECTION OUTPUT ;
    USE SIGNAL ;
    PORT
      LAYER M3 ;
        RECT 104.976 69.082 104.994 69.120 ;
    END
  END wo_d[869]
  PIN wo_d[86]
    DIRECTION OUTPUT ;
    USE SIGNAL ;
    PORT
      LAYER M4 ;
        RECT 0.000 50.448 0.192 50.472 ;
    END
  END wo_d[86]
  PIN wo_d[870]
    DIRECTION OUTPUT ;
    USE SIGNAL ;
    PORT
      LAYER M3 ;
        RECT 105.264 69.082 105.282 69.120 ;
    END
  END wo_d[870]
  PIN wo_d[871]
    DIRECTION OUTPUT ;
    USE SIGNAL ;
    PORT
      LAYER M3 ;
        RECT 105.480 69.082 105.498 69.120 ;
    END
  END wo_d[871]
  PIN wo_d[872]
    DIRECTION OUTPUT ;
    USE SIGNAL ;
    PORT
      LAYER M5 ;
        RECT 105.600 69.036 105.624 69.120 ;
    END
  END wo_d[872]
  PIN wo_d[873]
    DIRECTION OUTPUT ;
    USE SIGNAL ;
    PORT
      LAYER M3 ;
        RECT 105.768 69.082 105.786 69.120 ;
    END
  END wo_d[873]
  PIN wo_d[874]
    DIRECTION OUTPUT ;
    USE SIGNAL ;
    PORT
      LAYER M3 ;
        RECT 105.912 69.082 105.930 69.120 ;
    END
  END wo_d[874]
  PIN wo_d[875]
    DIRECTION OUTPUT ;
    USE SIGNAL ;
    PORT
      LAYER M3 ;
        RECT 106.056 69.082 106.074 69.120 ;
    END
  END wo_d[875]
  PIN wo_d[876]
    DIRECTION OUTPUT ;
    USE SIGNAL ;
    PORT
      LAYER M3 ;
        RECT 106.200 69.082 106.218 69.120 ;
    END
  END wo_d[876]
  PIN wo_d[877]
    DIRECTION OUTPUT ;
    USE SIGNAL ;
    PORT
      LAYER M5 ;
        RECT 106.368 69.036 106.392 69.120 ;
    END
  END wo_d[877]
  PIN wo_d[878]
    DIRECTION OUTPUT ;
    USE SIGNAL ;
    PORT
      LAYER M3 ;
        RECT 106.488 69.082 106.506 69.120 ;
    END
  END wo_d[878]
  PIN wo_d[879]
    DIRECTION OUTPUT ;
    USE SIGNAL ;
    PORT
      LAYER M5 ;
        RECT 106.656 69.036 106.680 69.120 ;
    END
  END wo_d[879]
  PIN wo_d[87]
    DIRECTION OUTPUT ;
    USE SIGNAL ;
    PORT
      LAYER M4 ;
        RECT 129.408 54.384 129.600 54.408 ;
    END
  END wo_d[87]
  PIN wo_d[880]
    DIRECTION OUTPUT ;
    USE SIGNAL ;
    PORT
      LAYER M3 ;
        RECT 106.776 69.082 106.794 69.120 ;
    END
  END wo_d[880]
  PIN wo_d[881]
    DIRECTION OUTPUT ;
    USE SIGNAL ;
    PORT
      LAYER M5 ;
        RECT 106.944 69.036 106.968 69.120 ;
    END
  END wo_d[881]
  PIN wo_d[882]
    DIRECTION OUTPUT ;
    USE SIGNAL ;
    PORT
      LAYER M3 ;
        RECT 107.136 69.082 107.154 69.120 ;
    END
  END wo_d[882]
  PIN wo_d[883]
    DIRECTION OUTPUT ;
    USE SIGNAL ;
    PORT
      LAYER M5 ;
        RECT 107.232 69.036 107.256 69.120 ;
    END
  END wo_d[883]
  PIN wo_d[884]
    DIRECTION OUTPUT ;
    USE SIGNAL ;
    PORT
      LAYER M3 ;
        RECT 107.424 69.082 107.442 69.120 ;
    END
  END wo_d[884]
  PIN wo_d[885]
    DIRECTION OUTPUT ;
    USE SIGNAL ;
    PORT
      LAYER M3 ;
        RECT 107.568 69.082 107.586 69.120 ;
    END
  END wo_d[885]
  PIN wo_d[886]
    DIRECTION OUTPUT ;
    USE SIGNAL ;
    PORT
      LAYER M3 ;
        RECT 107.712 69.082 107.730 69.120 ;
    END
  END wo_d[886]
  PIN wo_d[887]
    DIRECTION OUTPUT ;
    USE SIGNAL ;
    PORT
      LAYER M3 ;
        RECT 107.856 69.082 107.874 69.120 ;
    END
  END wo_d[887]
  PIN wo_d[888]
    DIRECTION OUTPUT ;
    USE SIGNAL ;
    PORT
      LAYER M5 ;
        RECT 108.000 69.036 108.024 69.120 ;
    END
  END wo_d[888]
  PIN wo_d[889]
    DIRECTION OUTPUT ;
    USE SIGNAL ;
    PORT
      LAYER M3 ;
        RECT 108.144 69.082 108.162 69.120 ;
    END
  END wo_d[889]
  PIN wo_d[88]
    DIRECTION OUTPUT ;
    USE SIGNAL ;
    PORT
      LAYER M4 ;
        RECT 0.000 50.640 0.192 50.664 ;
    END
  END wo_d[88]
  PIN wo_d[890]
    DIRECTION OUTPUT ;
    USE SIGNAL ;
    PORT
      LAYER M5 ;
        RECT 108.288 69.036 108.312 69.120 ;
    END
  END wo_d[890]
  PIN wo_d[891]
    DIRECTION OUTPUT ;
    USE SIGNAL ;
    PORT
      LAYER M5 ;
        RECT 108.480 69.036 108.504 69.120 ;
    END
  END wo_d[891]
  PIN wo_d[892]
    DIRECTION OUTPUT ;
    USE SIGNAL ;
    PORT
      LAYER M5 ;
        RECT 108.576 69.036 108.600 69.120 ;
    END
  END wo_d[892]
  PIN wo_d[893]
    DIRECTION OUTPUT ;
    USE SIGNAL ;
    PORT
      LAYER M5 ;
        RECT 108.768 69.036 108.792 69.120 ;
    END
  END wo_d[893]
  PIN wo_d[894]
    DIRECTION OUTPUT ;
    USE SIGNAL ;
    PORT
      LAYER M5 ;
        RECT 108.864 69.036 108.888 69.120 ;
    END
  END wo_d[894]
  PIN wo_d[895]
    DIRECTION OUTPUT ;
    USE SIGNAL ;
    PORT
      LAYER M5 ;
        RECT 109.056 69.036 109.080 69.120 ;
    END
  END wo_d[895]
  PIN wo_d[896]
    DIRECTION OUTPUT ;
    USE SIGNAL ;
    PORT
      LAYER M3 ;
        RECT 109.224 69.082 109.242 69.120 ;
    END
  END wo_d[896]
  PIN wo_d[897]
    DIRECTION OUTPUT ;
    USE SIGNAL ;
    PORT
      LAYER M5 ;
        RECT 109.344 69.036 109.368 69.120 ;
    END
  END wo_d[897]
  PIN wo_d[898]
    DIRECTION OUTPUT ;
    USE SIGNAL ;
    PORT
      LAYER M3 ;
        RECT 109.512 69.082 109.530 69.120 ;
    END
  END wo_d[898]
  PIN wo_d[899]
    DIRECTION OUTPUT ;
    USE SIGNAL ;
    PORT
      LAYER M3 ;
        RECT 109.656 69.082 109.674 69.120 ;
    END
  END wo_d[899]
  PIN wo_d[89]
    DIRECTION OUTPUT ;
    USE SIGNAL ;
    PORT
      LAYER M4 ;
        RECT 129.408 54.528 129.600 54.552 ;
    END
  END wo_d[89]
  PIN wo_d[8]
    DIRECTION OUTPUT ;
    USE SIGNAL ;
    PORT
      LAYER M4 ;
        RECT 0.000 42.768 0.192 42.792 ;
    END
  END wo_d[8]
  PIN wo_d[900]
    DIRECTION OUTPUT ;
    USE SIGNAL ;
    PORT
      LAYER M3 ;
        RECT 109.800 69.082 109.818 69.120 ;
    END
  END wo_d[900]
  PIN wo_d[901]
    DIRECTION OUTPUT ;
    USE SIGNAL ;
    PORT
      LAYER M3 ;
        RECT 109.944 69.082 109.962 69.120 ;
    END
  END wo_d[901]
  PIN wo_d[902]
    DIRECTION OUTPUT ;
    USE SIGNAL ;
    PORT
      LAYER M5 ;
        RECT 110.112 69.036 110.136 69.120 ;
    END
  END wo_d[902]
  PIN wo_d[903]
    DIRECTION OUTPUT ;
    USE SIGNAL ;
    PORT
      LAYER M3 ;
        RECT 110.232 69.082 110.250 69.120 ;
    END
  END wo_d[903]
  PIN wo_d[904]
    DIRECTION OUTPUT ;
    USE SIGNAL ;
    PORT
      LAYER M5 ;
        RECT 110.400 69.036 110.424 69.120 ;
    END
  END wo_d[904]
  PIN wo_d[905]
    DIRECTION OUTPUT ;
    USE SIGNAL ;
    PORT
      LAYER M3 ;
        RECT 110.592 69.082 110.610 69.120 ;
    END
  END wo_d[905]
  PIN wo_d[906]
    DIRECTION OUTPUT ;
    USE SIGNAL ;
    PORT
      LAYER M3 ;
        RECT 110.880 69.082 110.898 69.120 ;
    END
  END wo_d[906]
  PIN wo_d[907]
    DIRECTION OUTPUT ;
    USE SIGNAL ;
    PORT
      LAYER M3 ;
        RECT 111.024 69.082 111.042 69.120 ;
    END
  END wo_d[907]
  PIN wo_d[908]
    DIRECTION OUTPUT ;
    USE SIGNAL ;
    PORT
      LAYER M3 ;
        RECT 111.168 69.082 111.186 69.120 ;
    END
  END wo_d[908]
  PIN wo_d[909]
    DIRECTION OUTPUT ;
    USE SIGNAL ;
    PORT
      LAYER M3 ;
        RECT 111.312 69.082 111.330 69.120 ;
    END
  END wo_d[909]
  PIN wo_d[90]
    DIRECTION OUTPUT ;
    USE SIGNAL ;
    PORT
      LAYER M4 ;
        RECT 0.000 50.832 0.192 50.856 ;
    END
  END wo_d[90]
  PIN wo_d[910]
    DIRECTION OUTPUT ;
    USE SIGNAL ;
    PORT
      LAYER M5 ;
        RECT 111.456 69.036 111.480 69.120 ;
    END
  END wo_d[910]
  PIN wo_d[911]
    DIRECTION OUTPUT ;
    USE SIGNAL ;
    PORT
      LAYER M3 ;
        RECT 111.600 69.082 111.618 69.120 ;
    END
  END wo_d[911]
  PIN wo_d[912]
    DIRECTION OUTPUT ;
    USE SIGNAL ;
    PORT
      LAYER M5 ;
        RECT 111.744 69.036 111.768 69.120 ;
    END
  END wo_d[912]
  PIN wo_d[913]
    DIRECTION OUTPUT ;
    USE SIGNAL ;
    PORT
      LAYER M5 ;
        RECT 111.936 69.036 111.960 69.120 ;
    END
  END wo_d[913]
  PIN wo_d[914]
    DIRECTION OUTPUT ;
    USE SIGNAL ;
    PORT
      LAYER M5 ;
        RECT 112.032 69.036 112.056 69.120 ;
    END
  END wo_d[914]
  PIN wo_d[915]
    DIRECTION OUTPUT ;
    USE SIGNAL ;
    PORT
      LAYER M5 ;
        RECT 112.224 69.036 112.248 69.120 ;
    END
  END wo_d[915]
  PIN wo_d[916]
    DIRECTION OUTPUT ;
    USE SIGNAL ;
    PORT
      LAYER M5 ;
        RECT 112.320 69.036 112.344 69.120 ;
    END
  END wo_d[916]
  PIN wo_d[917]
    DIRECTION OUTPUT ;
    USE SIGNAL ;
    PORT
      LAYER M5 ;
        RECT 112.512 69.036 112.536 69.120 ;
    END
  END wo_d[917]
  PIN wo_d[918]
    DIRECTION OUTPUT ;
    USE SIGNAL ;
    PORT
      LAYER M3 ;
        RECT 112.680 69.082 112.698 69.120 ;
    END
  END wo_d[918]
  PIN wo_d[919]
    DIRECTION OUTPUT ;
    USE SIGNAL ;
    PORT
      LAYER M5 ;
        RECT 112.800 69.036 112.824 69.120 ;
    END
  END wo_d[919]
  PIN wo_d[91]
    DIRECTION OUTPUT ;
    USE SIGNAL ;
    PORT
      LAYER M4 ;
        RECT 129.408 54.672 129.600 54.696 ;
    END
  END wo_d[91]
  PIN wo_d[920]
    DIRECTION OUTPUT ;
    USE SIGNAL ;
    PORT
      LAYER M3 ;
        RECT 112.968 69.082 112.986 69.120 ;
    END
  END wo_d[920]
  PIN wo_d[921]
    DIRECTION OUTPUT ;
    USE SIGNAL ;
    PORT
      LAYER M3 ;
        RECT 113.112 69.082 113.130 69.120 ;
    END
  END wo_d[921]
  PIN wo_d[922]
    DIRECTION OUTPUT ;
    USE SIGNAL ;
    PORT
      LAYER M3 ;
        RECT 113.256 69.082 113.274 69.120 ;
    END
  END wo_d[922]
  PIN wo_d[923]
    DIRECTION OUTPUT ;
    USE SIGNAL ;
    PORT
      LAYER M3 ;
        RECT 113.400 69.082 113.418 69.120 ;
    END
  END wo_d[923]
  PIN wo_d[924]
    DIRECTION OUTPUT ;
    USE SIGNAL ;
    PORT
      LAYER M5 ;
        RECT 113.568 69.036 113.592 69.120 ;
    END
  END wo_d[924]
  PIN wo_d[925]
    DIRECTION OUTPUT ;
    USE SIGNAL ;
    PORT
      LAYER M3 ;
        RECT 113.688 69.082 113.706 69.120 ;
    END
  END wo_d[925]
  PIN wo_d[926]
    DIRECTION OUTPUT ;
    USE SIGNAL ;
    PORT
      LAYER M5 ;
        RECT 113.856 69.036 113.880 69.120 ;
    END
  END wo_d[926]
  PIN wo_d[927]
    DIRECTION OUTPUT ;
    USE SIGNAL ;
    PORT
      LAYER M3 ;
        RECT 113.976 69.082 113.994 69.120 ;
    END
  END wo_d[927]
  PIN wo_d[928]
    DIRECTION OUTPUT ;
    USE SIGNAL ;
    PORT
      LAYER M5 ;
        RECT 114.144 69.036 114.168 69.120 ;
    END
  END wo_d[928]
  PIN wo_d[929]
    DIRECTION OUTPUT ;
    USE SIGNAL ;
    PORT
      LAYER M3 ;
        RECT 114.336 69.082 114.354 69.120 ;
    END
  END wo_d[929]
  PIN wo_d[92]
    DIRECTION OUTPUT ;
    USE SIGNAL ;
    PORT
      LAYER M4 ;
        RECT 0.000 51.024 0.192 51.048 ;
    END
  END wo_d[92]
  PIN wo_d[930]
    DIRECTION OUTPUT ;
    USE SIGNAL ;
    PORT
      LAYER M5 ;
        RECT 114.432 69.036 114.456 69.120 ;
    END
  END wo_d[930]
  PIN wo_d[931]
    DIRECTION OUTPUT ;
    USE SIGNAL ;
    PORT
      LAYER M3 ;
        RECT 114.624 69.082 114.642 69.120 ;
    END
  END wo_d[931]
  PIN wo_d[932]
    DIRECTION OUTPUT ;
    USE SIGNAL ;
    PORT
      LAYER M3 ;
        RECT 114.768 69.082 114.786 69.120 ;
    END
  END wo_d[932]
  PIN wo_d[933]
    DIRECTION OUTPUT ;
    USE SIGNAL ;
    PORT
      LAYER M3 ;
        RECT 114.912 69.082 114.930 69.120 ;
    END
  END wo_d[933]
  PIN wo_d[934]
    DIRECTION OUTPUT ;
    USE SIGNAL ;
    PORT
      LAYER M3 ;
        RECT 115.056 69.082 115.074 69.120 ;
    END
  END wo_d[934]
  PIN wo_d[935]
    DIRECTION OUTPUT ;
    USE SIGNAL ;
    PORT
      LAYER M5 ;
        RECT 115.200 69.036 115.224 69.120 ;
    END
  END wo_d[935]
  PIN wo_d[936]
    DIRECTION OUTPUT ;
    USE SIGNAL ;
    PORT
      LAYER M3 ;
        RECT 115.344 69.082 115.362 69.120 ;
    END
  END wo_d[936]
  PIN wo_d[937]
    DIRECTION OUTPUT ;
    USE SIGNAL ;
    PORT
      LAYER M5 ;
        RECT 115.488 69.036 115.512 69.120 ;
    END
  END wo_d[937]
  PIN wo_d[938]
    DIRECTION OUTPUT ;
    USE SIGNAL ;
    PORT
      LAYER M5 ;
        RECT 115.680 69.036 115.704 69.120 ;
    END
  END wo_d[938]
  PIN wo_d[939]
    DIRECTION OUTPUT ;
    USE SIGNAL ;
    PORT
      LAYER M5 ;
        RECT 115.776 69.036 115.800 69.120 ;
    END
  END wo_d[939]
  PIN wo_d[93]
    DIRECTION OUTPUT ;
    USE SIGNAL ;
    PORT
      LAYER M4 ;
        RECT 129.408 54.864 129.600 54.888 ;
    END
  END wo_d[93]
  PIN wo_d[940]
    DIRECTION OUTPUT ;
    USE SIGNAL ;
    PORT
      LAYER M3 ;
        RECT 116.064 69.082 116.082 69.120 ;
    END
  END wo_d[940]
  PIN wo_d[941]
    DIRECTION OUTPUT ;
    USE SIGNAL ;
    PORT
      LAYER M5 ;
        RECT 116.256 69.036 116.280 69.120 ;
    END
  END wo_d[941]
  PIN wo_d[942]
    DIRECTION OUTPUT ;
    USE SIGNAL ;
    PORT
      LAYER M3 ;
        RECT 116.424 69.082 116.442 69.120 ;
    END
  END wo_d[942]
  PIN wo_d[943]
    DIRECTION OUTPUT ;
    USE SIGNAL ;
    PORT
      LAYER M3 ;
        RECT 116.568 69.082 116.586 69.120 ;
    END
  END wo_d[943]
  PIN wo_d[944]
    DIRECTION OUTPUT ;
    USE SIGNAL ;
    PORT
      LAYER M3 ;
        RECT 116.712 69.082 116.730 69.120 ;
    END
  END wo_d[944]
  PIN wo_d[945]
    DIRECTION OUTPUT ;
    USE SIGNAL ;
    PORT
      LAYER M3 ;
        RECT 116.856 69.082 116.874 69.120 ;
    END
  END wo_d[945]
  PIN wo_d[946]
    DIRECTION OUTPUT ;
    USE SIGNAL ;
    PORT
      LAYER M5 ;
        RECT 117.024 69.036 117.048 69.120 ;
    END
  END wo_d[946]
  PIN wo_d[947]
    DIRECTION OUTPUT ;
    USE SIGNAL ;
    PORT
      LAYER M3 ;
        RECT 117.144 69.082 117.162 69.120 ;
    END
  END wo_d[947]
  PIN wo_d[948]
    DIRECTION OUTPUT ;
    USE SIGNAL ;
    PORT
      LAYER M5 ;
        RECT 117.312 69.036 117.336 69.120 ;
    END
  END wo_d[948]
  PIN wo_d[949]
    DIRECTION OUTPUT ;
    USE SIGNAL ;
    PORT
      LAYER M3 ;
        RECT 117.504 69.082 117.522 69.120 ;
    END
  END wo_d[949]
  PIN wo_d[94]
    DIRECTION OUTPUT ;
    USE SIGNAL ;
    PORT
      LAYER M4 ;
        RECT 0.000 51.216 0.192 51.240 ;
    END
  END wo_d[94]
  PIN wo_d[950]
    DIRECTION OUTPUT ;
    USE SIGNAL ;
    PORT
      LAYER M5 ;
        RECT 117.600 69.036 117.624 69.120 ;
    END
  END wo_d[950]
  PIN wo_d[951]
    DIRECTION OUTPUT ;
    USE SIGNAL ;
    PORT
      LAYER M3 ;
        RECT 117.792 69.082 117.810 69.120 ;
    END
  END wo_d[951]
  PIN wo_d[952]
    DIRECTION OUTPUT ;
    USE SIGNAL ;
    PORT
      LAYER M5 ;
        RECT 117.888 69.036 117.912 69.120 ;
    END
  END wo_d[952]
  PIN wo_d[953]
    DIRECTION OUTPUT ;
    USE SIGNAL ;
    PORT
      LAYER M3 ;
        RECT 118.080 69.082 118.098 69.120 ;
    END
  END wo_d[953]
  PIN wo_d[954]
    DIRECTION OUTPUT ;
    USE SIGNAL ;
    PORT
      LAYER M3 ;
        RECT 118.224 69.082 118.242 69.120 ;
    END
  END wo_d[954]
  PIN wo_d[955]
    DIRECTION OUTPUT ;
    USE SIGNAL ;
    PORT
      LAYER M3 ;
        RECT 118.368 69.082 118.386 69.120 ;
    END
  END wo_d[955]
  PIN wo_d[956]
    DIRECTION OUTPUT ;
    USE SIGNAL ;
    PORT
      LAYER M3 ;
        RECT 118.512 69.082 118.530 69.120 ;
    END
  END wo_d[956]
  PIN wo_d[957]
    DIRECTION OUTPUT ;
    USE SIGNAL ;
    PORT
      LAYER M5 ;
        RECT 118.656 69.036 118.680 69.120 ;
    END
  END wo_d[957]
  PIN wo_d[958]
    DIRECTION OUTPUT ;
    USE SIGNAL ;
    PORT
      LAYER M3 ;
        RECT 118.800 69.082 118.818 69.120 ;
    END
  END wo_d[958]
  PIN wo_d[959]
    DIRECTION OUTPUT ;
    USE SIGNAL ;
    PORT
      LAYER M5 ;
        RECT 118.944 69.036 118.968 69.120 ;
    END
  END wo_d[959]
  PIN wo_d[95]
    DIRECTION OUTPUT ;
    USE SIGNAL ;
    PORT
      LAYER M4 ;
        RECT 129.408 54.960 129.600 54.984 ;
    END
  END wo_d[95]
  PIN wo_d[960]
    DIRECTION OUTPUT ;
    USE SIGNAL ;
    PORT
      LAYER M5 ;
        RECT 119.136 69.036 119.160 69.120 ;
    END
  END wo_d[960]
  PIN wo_d[961]
    DIRECTION OUTPUT ;
    USE SIGNAL ;
    PORT
      LAYER M5 ;
        RECT 119.232 69.036 119.256 69.120 ;
    END
  END wo_d[961]
  PIN wo_d[962]
    DIRECTION OUTPUT ;
    USE SIGNAL ;
    PORT
      LAYER M5 ;
        RECT 119.424 69.036 119.448 69.120 ;
    END
  END wo_d[962]
  PIN wo_d[963]
    DIRECTION OUTPUT ;
    USE SIGNAL ;
    PORT
      LAYER M5 ;
        RECT 119.520 69.036 119.544 69.120 ;
    END
  END wo_d[963]
  PIN wo_d[964]
    DIRECTION OUTPUT ;
    USE SIGNAL ;
    PORT
      LAYER M5 ;
        RECT 119.712 69.036 119.736 69.120 ;
    END
  END wo_d[964]
  PIN wo_d[965]
    DIRECTION OUTPUT ;
    USE SIGNAL ;
    PORT
      LAYER M3 ;
        RECT 119.880 69.082 119.898 69.120 ;
    END
  END wo_d[965]
  PIN wo_d[966]
    DIRECTION OUTPUT ;
    USE SIGNAL ;
    PORT
      LAYER M5 ;
        RECT 120.000 69.036 120.024 69.120 ;
    END
  END wo_d[966]
  PIN wo_d[967]
    DIRECTION OUTPUT ;
    USE SIGNAL ;
    PORT
      LAYER M3 ;
        RECT 120.168 69.082 120.186 69.120 ;
    END
  END wo_d[967]
  PIN wo_d[968]
    DIRECTION OUTPUT ;
    USE SIGNAL ;
    PORT
      LAYER M3 ;
        RECT 120.312 69.082 120.330 69.120 ;
    END
  END wo_d[968]
  PIN wo_d[969]
    DIRECTION OUTPUT ;
    USE SIGNAL ;
    PORT
      LAYER M3 ;
        RECT 120.456 69.082 120.474 69.120 ;
    END
  END wo_d[969]
  PIN wo_d[96]
    DIRECTION OUTPUT ;
    USE SIGNAL ;
    PORT
      LAYER M4 ;
        RECT 0.000 51.408 0.192 51.432 ;
    END
  END wo_d[96]
  PIN wo_d[970]
    DIRECTION OUTPUT ;
    USE SIGNAL ;
    PORT
      LAYER M3 ;
        RECT 120.600 69.082 120.618 69.120 ;
    END
  END wo_d[970]
  PIN wo_d[971]
    DIRECTION OUTPUT ;
    USE SIGNAL ;
    PORT
      LAYER M5 ;
        RECT 120.768 69.036 120.792 69.120 ;
    END
  END wo_d[971]
  PIN wo_d[972]
    DIRECTION OUTPUT ;
    USE SIGNAL ;
    PORT
      LAYER M3 ;
        RECT 120.888 69.082 120.906 69.120 ;
    END
  END wo_d[972]
  PIN wo_d[973]
    DIRECTION OUTPUT ;
    USE SIGNAL ;
    PORT
      LAYER M5 ;
        RECT 121.056 69.036 121.080 69.120 ;
    END
  END wo_d[973]
  PIN wo_d[974]
    DIRECTION OUTPUT ;
    USE SIGNAL ;
    PORT
      LAYER M3 ;
        RECT 121.176 69.082 121.194 69.120 ;
    END
  END wo_d[974]
  PIN wo_d[975]
    DIRECTION OUTPUT ;
    USE SIGNAL ;
    PORT
      LAYER M3 ;
        RECT 121.464 69.082 121.482 69.120 ;
    END
  END wo_d[975]
  PIN wo_d[976]
    DIRECTION OUTPUT ;
    USE SIGNAL ;
    PORT
      LAYER M3 ;
        RECT 121.680 69.082 121.698 69.120 ;
    END
  END wo_d[976]
  PIN wo_d[977]
    DIRECTION OUTPUT ;
    USE SIGNAL ;
    PORT
      LAYER M3 ;
        RECT 121.824 69.082 121.842 69.120 ;
    END
  END wo_d[977]
  PIN wo_d[978]
    DIRECTION OUTPUT ;
    USE SIGNAL ;
    PORT
      LAYER M3 ;
        RECT 121.968 69.082 121.986 69.120 ;
    END
  END wo_d[978]
  PIN wo_d[979]
    DIRECTION OUTPUT ;
    USE SIGNAL ;
    PORT
      LAYER M5 ;
        RECT 122.112 69.036 122.136 69.120 ;
    END
  END wo_d[979]
  PIN wo_d[97]
    DIRECTION OUTPUT ;
    USE SIGNAL ;
    PORT
      LAYER M4 ;
        RECT 129.408 55.152 129.600 55.176 ;
    END
  END wo_d[97]
  PIN wo_d[980]
    DIRECTION OUTPUT ;
    USE SIGNAL ;
    PORT
      LAYER M3 ;
        RECT 122.256 69.082 122.274 69.120 ;
    END
  END wo_d[980]
  PIN wo_d[981]
    DIRECTION OUTPUT ;
    USE SIGNAL ;
    PORT
      LAYER M5 ;
        RECT 122.400 69.036 122.424 69.120 ;
    END
  END wo_d[981]
  PIN wo_d[982]
    DIRECTION OUTPUT ;
    USE SIGNAL ;
    PORT
      LAYER M5 ;
        RECT 122.592 69.036 122.616 69.120 ;
    END
  END wo_d[982]
  PIN wo_d[983]
    DIRECTION OUTPUT ;
    USE SIGNAL ;
    PORT
      LAYER M5 ;
        RECT 122.688 69.036 122.712 69.120 ;
    END
  END wo_d[983]
  PIN wo_d[984]
    DIRECTION OUTPUT ;
    USE SIGNAL ;
    PORT
      LAYER M5 ;
        RECT 122.880 69.036 122.904 69.120 ;
    END
  END wo_d[984]
  PIN wo_d[985]
    DIRECTION OUTPUT ;
    USE SIGNAL ;
    PORT
      LAYER M3 ;
        RECT 123.048 69.082 123.066 69.120 ;
    END
  END wo_d[985]
  PIN wo_d[986]
    DIRECTION OUTPUT ;
    USE SIGNAL ;
    PORT
      LAYER M5 ;
        RECT 123.168 69.036 123.192 69.120 ;
    END
  END wo_d[986]
  PIN wo_d[987]
    DIRECTION OUTPUT ;
    USE SIGNAL ;
    PORT
      LAYER M3 ;
        RECT 123.336 69.082 123.354 69.120 ;
    END
  END wo_d[987]
  PIN wo_d[988]
    DIRECTION OUTPUT ;
    USE SIGNAL ;
    PORT
      LAYER M5 ;
        RECT 123.456 69.036 123.480 69.120 ;
    END
  END wo_d[988]
  PIN wo_d[989]
    DIRECTION OUTPUT ;
    USE SIGNAL ;
    PORT
      LAYER M3 ;
        RECT 123.624 69.082 123.642 69.120 ;
    END
  END wo_d[989]
  PIN wo_d[98]
    DIRECTION OUTPUT ;
    USE SIGNAL ;
    PORT
      LAYER M4 ;
        RECT 0.000 51.600 0.192 51.624 ;
    END
  END wo_d[98]
  PIN wo_d[990]
    DIRECTION OUTPUT ;
    USE SIGNAL ;
    PORT
      LAYER M3 ;
        RECT 123.768 69.082 123.786 69.120 ;
    END
  END wo_d[990]
  PIN wo_d[991]
    DIRECTION OUTPUT ;
    USE SIGNAL ;
    PORT
      LAYER M3 ;
        RECT 123.912 69.082 123.930 69.120 ;
    END
  END wo_d[991]
  PIN wo_d[992]
    DIRECTION OUTPUT ;
    USE SIGNAL ;
    PORT
      LAYER M3 ;
        RECT 124.056 69.082 124.074 69.120 ;
    END
  END wo_d[992]
  PIN wo_d[993]
    DIRECTION OUTPUT ;
    USE SIGNAL ;
    PORT
      LAYER M5 ;
        RECT 124.224 69.036 124.248 69.120 ;
    END
  END wo_d[993]
  PIN wo_d[994]
    DIRECTION OUTPUT ;
    USE SIGNAL ;
    PORT
      LAYER M3 ;
        RECT 124.344 69.082 124.362 69.120 ;
    END
  END wo_d[994]
  PIN wo_d[995]
    DIRECTION OUTPUT ;
    USE SIGNAL ;
    PORT
      LAYER M5 ;
        RECT 124.512 69.036 124.536 69.120 ;
    END
  END wo_d[995]
  PIN wo_d[996]
    DIRECTION OUTPUT ;
    USE SIGNAL ;
    PORT
      LAYER M3 ;
        RECT 124.704 69.082 124.722 69.120 ;
    END
  END wo_d[996]
  PIN wo_d[997]
    DIRECTION OUTPUT ;
    USE SIGNAL ;
    PORT
      LAYER M5 ;
        RECT 124.800 69.036 124.824 69.120 ;
    END
  END wo_d[997]
  PIN wo_d[998]
    DIRECTION OUTPUT ;
    USE SIGNAL ;
    PORT
      LAYER M3 ;
        RECT 124.992 69.082 125.010 69.120 ;
    END
  END wo_d[998]
  PIN wo_d[999]
    DIRECTION OUTPUT ;
    USE SIGNAL ;
    PORT
      LAYER M5 ;
        RECT 125.088 69.036 125.112 69.120 ;
    END
  END wo_d[999]
  PIN wo_d[99]
    DIRECTION OUTPUT ;
    USE SIGNAL ;
    PORT
      LAYER M4 ;
        RECT 129.408 55.296 129.600 55.320 ;
    END
  END wo_d[99]
  PIN wo_d[9]
    DIRECTION OUTPUT ;
    USE SIGNAL ;
    PORT
      LAYER M4 ;
        RECT 129.408 48.336 129.600 48.360 ;
    END
  END wo_d[9]
  PIN wo_ep
    DIRECTION OUTPUT ;
    USE SIGNAL ;
    PORT
      LAYER M4 ;
        RECT 129.408 42.096 129.600 42.120 ;
    END
  END wo_ep
  PIN wo_m[0]
    DIRECTION OUTPUT ;
    USE SIGNAL ;
    PORT
      LAYER M4 ;
        RECT 0.000 35.568 0.192 35.592 ;
    END
  END wo_m[0]
  PIN wo_m[10]
    DIRECTION OUTPUT ;
    USE SIGNAL ;
    PORT
      LAYER M4 ;
        RECT 0.000 36.624 0.192 36.648 ;
    END
  END wo_m[10]
  PIN wo_m[11]
    DIRECTION OUTPUT ;
    USE SIGNAL ;
    PORT
      LAYER M4 ;
        RECT 129.408 43.536 129.600 43.560 ;
    END
  END wo_m[11]
  PIN wo_m[12]
    DIRECTION OUTPUT ;
    USE SIGNAL ;
    PORT
      LAYER M4 ;
        RECT 0.000 36.816 0.192 36.840 ;
    END
  END wo_m[12]
  PIN wo_m[13]
    DIRECTION OUTPUT ;
    USE SIGNAL ;
    PORT
      LAYER M4 ;
        RECT 129.408 43.632 129.600 43.656 ;
    END
  END wo_m[13]
  PIN wo_m[14]
    DIRECTION OUTPUT ;
    USE SIGNAL ;
    PORT
      LAYER M4 ;
        RECT 0.000 37.008 0.192 37.032 ;
    END
  END wo_m[14]
  PIN wo_m[15]
    DIRECTION OUTPUT ;
    USE SIGNAL ;
    PORT
      LAYER M4 ;
        RECT 129.408 43.824 129.600 43.848 ;
    END
  END wo_m[15]
  PIN wo_m[16]
    DIRECTION OUTPUT ;
    USE SIGNAL ;
    PORT
      LAYER M4 ;
        RECT 0.000 37.200 0.192 37.224 ;
    END
  END wo_m[16]
  PIN wo_m[17]
    DIRECTION OUTPUT ;
    USE SIGNAL ;
    PORT
      LAYER M4 ;
        RECT 129.408 43.968 129.600 43.992 ;
    END
  END wo_m[17]
  PIN wo_m[18]
    DIRECTION OUTPUT ;
    USE SIGNAL ;
    PORT
      LAYER M4 ;
        RECT 0.000 37.392 0.192 37.416 ;
    END
  END wo_m[18]
  PIN wo_m[19]
    DIRECTION OUTPUT ;
    USE SIGNAL ;
    PORT
      LAYER M4 ;
        RECT 129.408 44.160 129.600 44.184 ;
    END
  END wo_m[19]
  PIN wo_m[1]
    DIRECTION OUTPUT ;
    USE SIGNAL ;
    PORT
      LAYER M4 ;
        RECT 129.408 42.768 129.600 42.792 ;
    END
  END wo_m[1]
  PIN wo_m[20]
    DIRECTION OUTPUT ;
    USE SIGNAL ;
    PORT
      LAYER M4 ;
        RECT 0.000 37.584 0.192 37.608 ;
    END
  END wo_m[20]
  PIN wo_m[21]
    DIRECTION OUTPUT ;
    USE SIGNAL ;
    PORT
      LAYER M4 ;
        RECT 129.408 44.304 129.600 44.328 ;
    END
  END wo_m[21]
  PIN wo_m[22]
    DIRECTION OUTPUT ;
    USE SIGNAL ;
    PORT
      LAYER M4 ;
        RECT 0.000 37.776 0.192 37.800 ;
    END
  END wo_m[22]
  PIN wo_m[23]
    DIRECTION OUTPUT ;
    USE SIGNAL ;
    PORT
      LAYER M4 ;
        RECT 129.408 44.496 129.600 44.520 ;
    END
  END wo_m[23]
  PIN wo_m[24]
    DIRECTION OUTPUT ;
    USE SIGNAL ;
    PORT
      LAYER M4 ;
        RECT 0.000 38.016 0.192 38.040 ;
    END
  END wo_m[24]
  PIN wo_m[25]
    DIRECTION OUTPUT ;
    USE SIGNAL ;
    PORT
      LAYER M4 ;
        RECT 129.408 44.592 129.600 44.616 ;
    END
  END wo_m[25]
  PIN wo_m[26]
    DIRECTION OUTPUT ;
    USE SIGNAL ;
    PORT
      LAYER M4 ;
        RECT 0.000 38.208 0.192 38.232 ;
    END
  END wo_m[26]
  PIN wo_m[27]
    DIRECTION OUTPUT ;
    USE SIGNAL ;
    PORT
      LAYER M4 ;
        RECT 129.408 44.736 129.600 44.760 ;
    END
  END wo_m[27]
  PIN wo_m[28]
    DIRECTION OUTPUT ;
    USE SIGNAL ;
    PORT
      LAYER M4 ;
        RECT 0.000 38.400 0.192 38.424 ;
    END
  END wo_m[28]
  PIN wo_m[29]
    DIRECTION OUTPUT ;
    USE SIGNAL ;
    PORT
      LAYER M4 ;
        RECT 129.408 44.928 129.600 44.952 ;
    END
  END wo_m[29]
  PIN wo_m[2]
    DIRECTION OUTPUT ;
    USE SIGNAL ;
    PORT
      LAYER M4 ;
        RECT 0.000 35.856 0.192 35.880 ;
    END
  END wo_m[2]
  PIN wo_m[30]
    DIRECTION OUTPUT ;
    USE SIGNAL ;
    PORT
      LAYER M4 ;
        RECT 0.000 38.592 0.192 38.616 ;
    END
  END wo_m[30]
  PIN wo_m[31]
    DIRECTION OUTPUT ;
    USE SIGNAL ;
    PORT
      LAYER M4 ;
        RECT 129.408 45.072 129.600 45.096 ;
    END
  END wo_m[31]
  PIN wo_m[32]
    DIRECTION OUTPUT ;
    USE SIGNAL ;
    PORT
      LAYER M4 ;
        RECT 0.000 38.784 0.192 38.808 ;
    END
  END wo_m[32]
  PIN wo_m[33]
    DIRECTION OUTPUT ;
    USE SIGNAL ;
    PORT
      LAYER M4 ;
        RECT 129.408 45.264 129.600 45.288 ;
    END
  END wo_m[33]
  PIN wo_m[34]
    DIRECTION OUTPUT ;
    USE SIGNAL ;
    PORT
      LAYER M4 ;
        RECT 0.000 38.976 0.192 39.000 ;
    END
  END wo_m[34]
  PIN wo_m[35]
    DIRECTION OUTPUT ;
    USE SIGNAL ;
    PORT
      LAYER M4 ;
        RECT 129.408 45.360 129.600 45.384 ;
    END
  END wo_m[35]
  PIN wo_m[36]
    DIRECTION OUTPUT ;
    USE SIGNAL ;
    PORT
      LAYER M4 ;
        RECT 0.000 39.168 0.192 39.192 ;
    END
  END wo_m[36]
  PIN wo_m[37]
    DIRECTION OUTPUT ;
    USE SIGNAL ;
    PORT
      LAYER M4 ;
        RECT 129.408 45.552 129.600 45.576 ;
    END
  END wo_m[37]
  PIN wo_m[38]
    DIRECTION OUTPUT ;
    USE SIGNAL ;
    PORT
      LAYER M4 ;
        RECT 0.000 39.360 0.192 39.384 ;
    END
  END wo_m[38]
  PIN wo_m[39]
    DIRECTION OUTPUT ;
    USE SIGNAL ;
    PORT
      LAYER M4 ;
        RECT 129.408 45.696 129.600 45.720 ;
    END
  END wo_m[39]
  PIN wo_m[3]
    DIRECTION OUTPUT ;
    USE SIGNAL ;
    PORT
      LAYER M4 ;
        RECT 129.408 42.864 129.600 42.888 ;
    END
  END wo_m[3]
  PIN wo_m[40]
    DIRECTION OUTPUT ;
    USE SIGNAL ;
    PORT
      LAYER M4 ;
        RECT 0.000 39.552 0.192 39.576 ;
    END
  END wo_m[40]
  PIN wo_m[41]
    DIRECTION OUTPUT ;
    USE SIGNAL ;
    PORT
      LAYER M4 ;
        RECT 129.408 45.840 129.600 45.864 ;
    END
  END wo_m[41]
  PIN wo_m[42]
    DIRECTION OUTPUT ;
    USE SIGNAL ;
    PORT
      LAYER M4 ;
        RECT 0.000 39.744 0.192 39.768 ;
    END
  END wo_m[42]
  PIN wo_m[43]
    DIRECTION OUTPUT ;
    USE SIGNAL ;
    PORT
      LAYER M4 ;
        RECT 129.408 46.032 129.600 46.056 ;
    END
  END wo_m[43]
  PIN wo_m[44]
    DIRECTION OUTPUT ;
    USE SIGNAL ;
    PORT
      LAYER M4 ;
        RECT 0.000 39.936 0.192 39.960 ;
    END
  END wo_m[44]
  PIN wo_m[45]
    DIRECTION OUTPUT ;
    USE SIGNAL ;
    PORT
      LAYER M4 ;
        RECT 129.408 46.128 129.600 46.152 ;
    END
  END wo_m[45]
  PIN wo_m[46]
    DIRECTION OUTPUT ;
    USE SIGNAL ;
    PORT
      LAYER M4 ;
        RECT 0.000 40.128 0.192 40.152 ;
    END
  END wo_m[46]
  PIN wo_m[47]
    DIRECTION OUTPUT ;
    USE SIGNAL ;
    PORT
      LAYER M4 ;
        RECT 129.408 46.320 129.600 46.344 ;
    END
  END wo_m[47]
  PIN wo_m[48]
    DIRECTION OUTPUT ;
    USE SIGNAL ;
    PORT
      LAYER M4 ;
        RECT 0.000 40.368 0.192 40.392 ;
    END
  END wo_m[48]
  PIN wo_m[49]
    DIRECTION OUTPUT ;
    USE SIGNAL ;
    PORT
      LAYER M4 ;
        RECT 129.408 46.464 129.600 46.488 ;
    END
  END wo_m[49]
  PIN wo_m[4]
    DIRECTION OUTPUT ;
    USE SIGNAL ;
    PORT
      LAYER M4 ;
        RECT 0.000 36.048 0.192 36.072 ;
    END
  END wo_m[4]
  PIN wo_m[50]
    DIRECTION OUTPUT ;
    USE SIGNAL ;
    PORT
      LAYER M4 ;
        RECT 0.000 40.560 0.192 40.584 ;
    END
  END wo_m[50]
  PIN wo_m[51]
    DIRECTION OUTPUT ;
    USE SIGNAL ;
    PORT
      LAYER M4 ;
        RECT 129.408 46.608 129.600 46.632 ;
    END
  END wo_m[51]
  PIN wo_m[52]
    DIRECTION OUTPUT ;
    USE SIGNAL ;
    PORT
      LAYER M4 ;
        RECT 0.000 40.752 0.192 40.776 ;
    END
  END wo_m[52]
  PIN wo_m[53]
    DIRECTION OUTPUT ;
    USE SIGNAL ;
    PORT
      LAYER M4 ;
        RECT 129.408 46.800 129.600 46.824 ;
    END
  END wo_m[53]
  PIN wo_m[54]
    DIRECTION OUTPUT ;
    USE SIGNAL ;
    PORT
      LAYER M4 ;
        RECT 0.000 40.944 0.192 40.968 ;
    END
  END wo_m[54]
  PIN wo_m[55]
    DIRECTION OUTPUT ;
    USE SIGNAL ;
    PORT
      LAYER M4 ;
        RECT 129.408 46.896 129.600 46.920 ;
    END
  END wo_m[55]
  PIN wo_m[56]
    DIRECTION OUTPUT ;
    USE SIGNAL ;
    PORT
      LAYER M4 ;
        RECT 0.000 41.136 0.192 41.160 ;
    END
  END wo_m[56]
  PIN wo_m[57]
    DIRECTION OUTPUT ;
    USE SIGNAL ;
    PORT
      LAYER M4 ;
        RECT 129.408 47.088 129.600 47.112 ;
    END
  END wo_m[57]
  PIN wo_m[58]
    DIRECTION OUTPUT ;
    USE SIGNAL ;
    PORT
      LAYER M4 ;
        RECT 0.000 41.328 0.192 41.352 ;
    END
  END wo_m[58]
  PIN wo_m[59]
    DIRECTION OUTPUT ;
    USE SIGNAL ;
    PORT
      LAYER M4 ;
        RECT 129.408 47.232 129.600 47.256 ;
    END
  END wo_m[59]
  PIN wo_m[5]
    DIRECTION OUTPUT ;
    USE SIGNAL ;
    PORT
      LAYER M4 ;
        RECT 129.408 43.056 129.600 43.080 ;
    END
  END wo_m[5]
  PIN wo_m[60]
    DIRECTION OUTPUT ;
    USE SIGNAL ;
    PORT
      LAYER M4 ;
        RECT 0.000 41.520 0.192 41.544 ;
    END
  END wo_m[60]
  PIN wo_m[61]
    DIRECTION OUTPUT ;
    USE SIGNAL ;
    PORT
      LAYER M4 ;
        RECT 129.408 47.424 129.600 47.448 ;
    END
  END wo_m[61]
  PIN wo_m[62]
    DIRECTION OUTPUT ;
    USE SIGNAL ;
    PORT
      LAYER M4 ;
        RECT 0.000 41.712 0.192 41.736 ;
    END
  END wo_m[62]
  PIN wo_m[63]
    DIRECTION OUTPUT ;
    USE SIGNAL ;
    PORT
      LAYER M4 ;
        RECT 129.408 47.568 129.600 47.592 ;
    END
  END wo_m[63]
  PIN wo_m[6]
    DIRECTION OUTPUT ;
    USE SIGNAL ;
    PORT
      LAYER M4 ;
        RECT 0.000 36.240 0.192 36.264 ;
    END
  END wo_m[6]
  PIN wo_m[7]
    DIRECTION OUTPUT ;
    USE SIGNAL ;
    PORT
      LAYER M4 ;
        RECT 129.408 43.200 129.600 43.224 ;
    END
  END wo_m[7]
  PIN wo_m[8]
    DIRECTION OUTPUT ;
    USE SIGNAL ;
    PORT
      LAYER M4 ;
        RECT 0.000 36.432 0.192 36.456 ;
    END
  END wo_m[8]
  PIN wo_m[9]
    DIRECTION OUTPUT ;
    USE SIGNAL ;
    PORT
      LAYER M4 ;
        RECT 129.408 43.392 129.600 43.416 ;
    END
  END wo_m[9]
  PIN wo_off[0]
    DIRECTION OUTPUT ;
    USE SIGNAL ;
    PORT
      LAYER M4 ;
        RECT 0.000 34.992 0.192 35.016 ;
    END
  END wo_off[0]
  PIN wo_off[1]
    DIRECTION OUTPUT ;
    USE SIGNAL ;
    PORT
      LAYER M4 ;
        RECT 129.408 42.288 129.600 42.312 ;
    END
  END wo_off[1]
  PIN wo_off[2]
    DIRECTION OUTPUT ;
    USE SIGNAL ;
    PORT
      LAYER M4 ;
        RECT 0.000 35.184 0.192 35.208 ;
    END
  END wo_off[2]
  PIN wo_off[3]
    DIRECTION OUTPUT ;
    USE SIGNAL ;
    PORT
      LAYER M4 ;
        RECT 129.408 42.432 129.600 42.456 ;
    END
  END wo_off[3]
  PIN wo_off[4]
    DIRECTION OUTPUT ;
    USE SIGNAL ;
    PORT
      LAYER M4 ;
        RECT 0.000 35.376 0.192 35.400 ;
    END
  END wo_off[4]
  PIN wo_off[5]
    DIRECTION OUTPUT ;
    USE SIGNAL ;
    PORT
      LAYER M4 ;
        RECT 129.408 42.624 129.600 42.648 ;
    END
  END wo_off[5]
  PIN wo_v
    DIRECTION OUTPUT ;
    USE SIGNAL ;
    PORT
      LAYER M4 ;
        RECT 0.000 34.800 0.192 34.824 ;
    END
  END wo_v
  PIN VDD
    DIRECTION INOUT ;
    USE POWER ;
    PORT
      LAYER M5 ;
        RECT 126.792 2.151 126.912 66.969 ;
        RECT 121.392 2.151 121.512 66.969 ;
        RECT 115.992 2.151 116.112 66.969 ;
        RECT 110.592 2.151 110.712 66.969 ;
        RECT 105.192 2.151 105.312 66.969 ;
        RECT 99.792 2.151 99.912 66.969 ;
        RECT 94.392 2.151 94.512 66.969 ;
        RECT 88.992 2.151 89.112 66.969 ;
        RECT 83.592 2.151 83.712 66.969 ;
        RECT 78.192 2.151 78.312 66.969 ;
        RECT 72.792 2.151 72.912 66.969 ;
        RECT 67.392 2.151 67.512 66.969 ;
        RECT 61.992 2.151 62.112 66.969 ;
        RECT 56.592 2.151 56.712 66.969 ;
        RECT 51.192 2.151 51.312 66.969 ;
        RECT 45.792 2.151 45.912 66.969 ;
        RECT 40.392 2.151 40.512 66.969 ;
        RECT 34.992 2.151 35.112 66.969 ;
        RECT 29.592 2.151 29.712 66.969 ;
        RECT 24.192 2.151 24.312 66.969 ;
        RECT 18.792 2.151 18.912 66.969 ;
        RECT 13.392 2.151 13.512 66.969 ;
        RECT 7.992 2.151 8.112 66.969 ;
        RECT 2.592 2.151 2.712 66.969 ;
    END
  END VDD
  PIN VSS
    DIRECTION INOUT ;
    USE GROUND ;
    PORT
      LAYER M5 ;
        RECT 126.600 2.137 126.720 66.983 ;
        RECT 121.200 2.137 121.320 66.983 ;
        RECT 115.800 2.137 115.920 66.983 ;
        RECT 110.400 2.137 110.520 66.983 ;
        RECT 105.000 2.137 105.120 66.983 ;
        RECT 99.600 2.137 99.720 66.983 ;
        RECT 94.200 2.137 94.320 66.983 ;
        RECT 88.800 2.137 88.920 66.983 ;
        RECT 83.400 2.137 83.520 66.983 ;
        RECT 78.000 2.137 78.120 66.983 ;
        RECT 72.600 2.137 72.720 66.983 ;
        RECT 67.200 2.137 67.320 66.983 ;
        RECT 61.800 2.137 61.920 66.983 ;
        RECT 56.400 2.137 56.520 66.983 ;
        RECT 51.000 2.137 51.120 66.983 ;
        RECT 45.600 2.137 45.720 66.983 ;
        RECT 40.200 2.137 40.320 66.983 ;
        RECT 34.800 2.137 34.920 66.983 ;
        RECT 29.400 2.137 29.520 66.983 ;
        RECT 24.000 2.137 24.120 66.983 ;
        RECT 18.600 2.137 18.720 66.983 ;
        RECT 13.200 2.137 13.320 66.983 ;
        RECT 7.800 2.137 7.920 66.983 ;
        RECT 2.400 2.137 2.520 66.983 ;
    END
  END VSS
  OBS
    LAYER M1 ;
      RECT 0.500 0.500 129.100 68.620 ;
    LAYER M2 ;
      RECT 0.500 0.500 129.100 68.620 ;
    LAYER M3 ;
      RECT 10.800 10.800 118.800 58.320 ;
    LAYER M4 ;
      RECT 10.800 10.800 118.800 58.320 ;
    LAYER M5 ;
      RECT 10.800 10.800 13.200 58.320 ;
      RECT 13.320 10.800 13.392 58.320 ;
      RECT 13.512 10.800 18.600 58.320 ;
      RECT 18.720 10.800 18.792 58.320 ;
      RECT 18.912 10.800 24.000 58.320 ;
      RECT 24.120 10.800 24.192 58.320 ;
      RECT 24.312 10.800 29.400 58.320 ;
      RECT 29.520 10.800 29.592 58.320 ;
      RECT 29.712 10.800 34.800 58.320 ;
      RECT 34.920 10.800 34.992 58.320 ;
      RECT 35.112 10.800 40.200 58.320 ;
      RECT 40.320 10.800 40.392 58.320 ;
      RECT 40.512 10.800 45.600 58.320 ;
      RECT 45.720 10.800 45.792 58.320 ;
      RECT 45.912 10.800 51.000 58.320 ;
      RECT 51.120 10.800 51.192 58.320 ;
      RECT 51.312 10.800 56.400 58.320 ;
      RECT 56.520 10.800 56.592 58.320 ;
      RECT 56.712 10.800 61.800 58.320 ;
      RECT 61.920 10.800 61.992 58.320 ;
      RECT 62.112 10.800 67.200 58.320 ;
      RECT 67.320 10.800 67.392 58.320 ;
      RECT 67.512 10.800 72.600 58.320 ;
      RECT 72.720 10.800 72.792 58.320 ;
      RECT 72.912 10.800 78.000 58.320 ;
      RECT 78.120 10.800 78.192 58.320 ;
      RECT 78.312 10.800 83.400 58.320 ;
      RECT 83.520 10.800 83.592 58.320 ;
      RECT 83.712 10.800 88.800 58.320 ;
      RECT 88.920 10.800 88.992 58.320 ;
      RECT 89.112 10.800 94.200 58.320 ;
      RECT 94.320 10.800 94.392 58.320 ;
      RECT 94.512 10.800 99.600 58.320 ;
      RECT 99.720 10.800 99.792 58.320 ;
      RECT 99.912 10.800 105.000 58.320 ;
      RECT 105.120 10.800 105.192 58.320 ;
      RECT 105.312 10.800 110.400 58.320 ;
      RECT 110.520 10.800 110.592 58.320 ;
      RECT 110.712 10.800 115.800 58.320 ;
      RECT 115.920 10.800 115.992 58.320 ;
      RECT 116.112 10.800 118.800 58.320 ;
  END
END ot_qfd_xs_leaf
END LIBRARY
